VERSION 5.8 ;
BUSBITCHARS "[]" ;
DIVIDERCHAR "/" ;
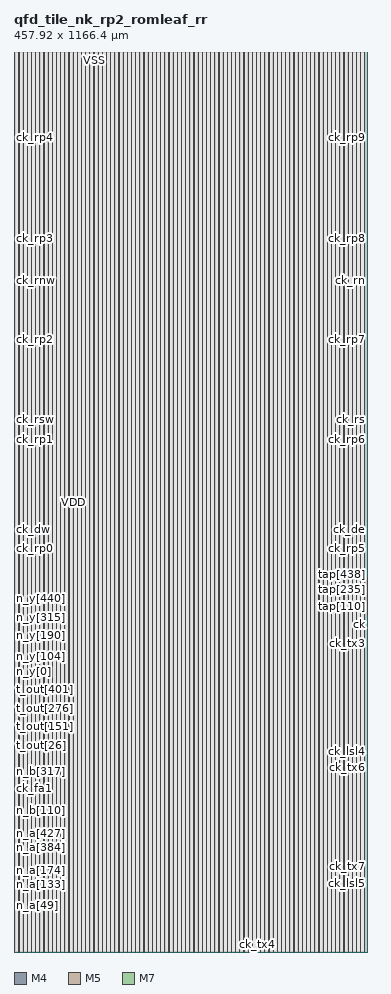
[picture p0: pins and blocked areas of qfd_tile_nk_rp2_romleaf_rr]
MACRO qfd_tile_nk_rp2_romleaf_rr
  CLASS BLOCK ;
  ORIGIN 0 0 ;
  FOREIGN qfd_tile_nk_rp2_romleaf_rr 0 0 ;
  SIZE 457.92 BY 1166.4 ;
  SYMMETRY X Y ;
  PIN n_a[0]
    DIRECTION INPUT ;
    USE SIGNAL ;
    PORT
      LAYER M4 ;
        RECT 0.000 61.632 0.192 61.656 ;
    END
  END n_a[0]
  PIN n_a[1]
    DIRECTION INPUT ;
    USE SIGNAL ;
    PORT
      LAYER M4 ;
        RECT 0.000 61.824 0.192 61.848 ;
    END
  END n_a[1]
  PIN n_a[2]
    DIRECTION INPUT ;
    USE SIGNAL ;
    PORT
      LAYER M4 ;
        RECT 0.000 62.016 0.192 62.040 ;
    END
  END n_a[2]
  PIN n_a[3]
    DIRECTION INPUT ;
    USE SIGNAL ;
    PORT
      LAYER M4 ;
        RECT 0.000 62.208 0.192 62.232 ;
    END
  END n_a[3]
  PIN n_a[4]
    DIRECTION INPUT ;
    USE SIGNAL ;
    PORT
      LAYER M4 ;
        RECT 0.000 62.400 0.192 62.424 ;
    END
  END n_a[4]
  PIN n_a[5]
    DIRECTION INPUT ;
    USE SIGNAL ;
    PORT
      LAYER M4 ;
        RECT 0.000 62.592 0.192 62.616 ;
    END
  END n_a[5]
  PIN n_a[6]
    DIRECTION INPUT ;
    USE SIGNAL ;
    PORT
      LAYER M4 ;
        RECT 0.000 62.784 0.192 62.808 ;
    END
  END n_a[6]
  PIN n_a[7]
    DIRECTION INPUT ;
    USE SIGNAL ;
    PORT
      LAYER M4 ;
        RECT 0.000 62.976 0.192 63.000 ;
    END
  END n_a[7]
  PIN n_a[8]
    DIRECTION INPUT ;
    USE SIGNAL ;
    PORT
      LAYER M4 ;
        RECT 0.000 63.168 0.192 63.192 ;
    END
  END n_a[8]
  PIN n_a[9]
    DIRECTION INPUT ;
    USE SIGNAL ;
    PORT
      LAYER M4 ;
        RECT 0.000 63.360 0.192 63.384 ;
    END
  END n_a[9]
  PIN n_a[10]
    DIRECTION INPUT ;
    USE SIGNAL ;
    PORT
      LAYER M4 ;
        RECT 0.000 63.552 0.192 63.576 ;
    END
  END n_a[10]
  PIN n_a[11]
    DIRECTION INPUT ;
    USE SIGNAL ;
    PORT
      LAYER M4 ;
        RECT 0.000 63.744 0.192 63.768 ;
    END
  END n_a[11]
  PIN n_a[12]
    DIRECTION INPUT ;
    USE SIGNAL ;
    PORT
      LAYER M4 ;
        RECT 0.000 63.936 0.192 63.960 ;
    END
  END n_a[12]
  PIN n_a[13]
    DIRECTION INPUT ;
    USE SIGNAL ;
    PORT
      LAYER M4 ;
        RECT 0.000 64.128 0.192 64.152 ;
    END
  END n_a[13]
  PIN n_a[14]
    DIRECTION INPUT ;
    USE SIGNAL ;
    PORT
      LAYER M4 ;
        RECT 0.000 64.320 0.192 64.344 ;
    END
  END n_a[14]
  PIN n_a[15]
    DIRECTION INPUT ;
    USE SIGNAL ;
    PORT
      LAYER M4 ;
        RECT 0.000 64.512 0.192 64.536 ;
    END
  END n_a[15]
  PIN n_a[16]
    DIRECTION INPUT ;
    USE SIGNAL ;
    PORT
      LAYER M4 ;
        RECT 0.000 64.704 0.192 64.728 ;
    END
  END n_a[16]
  PIN n_a[17]
    DIRECTION INPUT ;
    USE SIGNAL ;
    PORT
      LAYER M4 ;
        RECT 0.000 64.896 0.192 64.920 ;
    END
  END n_a[17]
  PIN n_a[18]
    DIRECTION INPUT ;
    USE SIGNAL ;
    PORT
      LAYER M4 ;
        RECT 0.000 65.088 0.192 65.112 ;
    END
  END n_a[18]
  PIN n_a[19]
    DIRECTION INPUT ;
    USE SIGNAL ;
    PORT
      LAYER M4 ;
        RECT 0.000 65.280 0.192 65.304 ;
    END
  END n_a[19]
  PIN n_a[20]
    DIRECTION INPUT ;
    USE SIGNAL ;
    PORT
      LAYER M4 ;
        RECT 0.000 65.472 0.192 65.496 ;
    END
  END n_a[20]
  PIN n_a[21]
    DIRECTION INPUT ;
    USE SIGNAL ;
    PORT
      LAYER M4 ;
        RECT 0.000 65.664 0.192 65.688 ;
    END
  END n_a[21]
  PIN n_a[22]
    DIRECTION INPUT ;
    USE SIGNAL ;
    PORT
      LAYER M4 ;
        RECT 0.000 65.856 0.192 65.880 ;
    END
  END n_a[22]
  PIN n_a[23]
    DIRECTION INPUT ;
    USE SIGNAL ;
    PORT
      LAYER M4 ;
        RECT 0.000 66.048 0.192 66.072 ;
    END
  END n_a[23]
  PIN n_a[24]
    DIRECTION INPUT ;
    USE SIGNAL ;
    PORT
      LAYER M4 ;
        RECT 0.000 66.240 0.192 66.264 ;
    END
  END n_a[24]
  PIN n_a[25]
    DIRECTION INPUT ;
    USE SIGNAL ;
    PORT
      LAYER M4 ;
        RECT 0.000 66.432 0.192 66.456 ;
    END
  END n_a[25]
  PIN n_a[26]
    DIRECTION INPUT ;
    USE SIGNAL ;
    PORT
      LAYER M4 ;
        RECT 0.000 66.624 0.192 66.648 ;
    END
  END n_a[26]
  PIN n_a[27]
    DIRECTION INPUT ;
    USE SIGNAL ;
    PORT
      LAYER M4 ;
        RECT 0.000 66.816 0.192 66.840 ;
    END
  END n_a[27]
  PIN n_a[28]
    DIRECTION INPUT ;
    USE SIGNAL ;
    PORT
      LAYER M4 ;
        RECT 0.000 67.008 0.192 67.032 ;
    END
  END n_a[28]
  PIN n_a[29]
    DIRECTION INPUT ;
    USE SIGNAL ;
    PORT
      LAYER M4 ;
        RECT 0.000 67.200 0.192 67.224 ;
    END
  END n_a[29]
  PIN n_a[30]
    DIRECTION INPUT ;
    USE SIGNAL ;
    PORT
      LAYER M4 ;
        RECT 0.000 67.392 0.192 67.416 ;
    END
  END n_a[30]
  PIN n_a[31]
    DIRECTION INPUT ;
    USE SIGNAL ;
    PORT
      LAYER M4 ;
        RECT 0.000 67.584 0.192 67.608 ;
    END
  END n_a[31]
  PIN n_a[32]
    DIRECTION INPUT ;
    USE SIGNAL ;
    PORT
      LAYER M4 ;
        RECT 0.000 67.776 0.192 67.800 ;
    END
  END n_a[32]
  PIN n_a[33]
    DIRECTION INPUT ;
    USE SIGNAL ;
    PORT
      LAYER M4 ;
        RECT 0.000 67.968 0.192 67.992 ;
    END
  END n_a[33]
  PIN n_a[34]
    DIRECTION INPUT ;
    USE SIGNAL ;
    PORT
      LAYER M4 ;
        RECT 0.000 68.160 0.192 68.184 ;
    END
  END n_a[34]
  PIN n_a[35]
    DIRECTION INPUT ;
    USE SIGNAL ;
    PORT
      LAYER M4 ;
        RECT 0.000 68.352 0.192 68.376 ;
    END
  END n_a[35]
  PIN n_a[36]
    DIRECTION INPUT ;
    USE SIGNAL ;
    PORT
      LAYER M4 ;
        RECT 0.000 68.544 0.192 68.568 ;
    END
  END n_a[36]
  PIN n_a[37]
    DIRECTION INPUT ;
    USE SIGNAL ;
    PORT
      LAYER M4 ;
        RECT 0.000 68.736 0.192 68.760 ;
    END
  END n_a[37]
  PIN n_a[38]
    DIRECTION INPUT ;
    USE SIGNAL ;
    PORT
      LAYER M4 ;
        RECT 0.000 68.928 0.192 68.952 ;
    END
  END n_a[38]
  PIN n_a[39]
    DIRECTION INPUT ;
    USE SIGNAL ;
    PORT
      LAYER M4 ;
        RECT 0.000 69.120 0.192 69.144 ;
    END
  END n_a[39]
  PIN n_a[40]
    DIRECTION INPUT ;
    USE SIGNAL ;
    PORT
      LAYER M4 ;
        RECT 0.000 69.312 0.192 69.336 ;
    END
  END n_a[40]
  PIN n_a[41]
    DIRECTION INPUT ;
    USE SIGNAL ;
    PORT
      LAYER M4 ;
        RECT 0.000 69.504 0.192 69.528 ;
    END
  END n_a[41]
  PIN n_a[42]
    DIRECTION INPUT ;
    USE SIGNAL ;
    PORT
      LAYER M4 ;
        RECT 0.000 69.696 0.192 69.720 ;
    END
  END n_a[42]
  PIN n_a[43]
    DIRECTION INPUT ;
    USE SIGNAL ;
    PORT
      LAYER M4 ;
        RECT 0.000 69.888 0.192 69.912 ;
    END
  END n_a[43]
  PIN n_a[44]
    DIRECTION INPUT ;
    USE SIGNAL ;
    PORT
      LAYER M4 ;
        RECT 0.000 70.080 0.192 70.104 ;
    END
  END n_a[44]
  PIN n_a[45]
    DIRECTION INPUT ;
    USE SIGNAL ;
    PORT
      LAYER M4 ;
        RECT 0.000 70.272 0.192 70.296 ;
    END
  END n_a[45]
  PIN n_a[46]
    DIRECTION INPUT ;
    USE SIGNAL ;
    PORT
      LAYER M4 ;
        RECT 0.000 70.464 0.192 70.488 ;
    END
  END n_a[46]
  PIN n_a[47]
    DIRECTION INPUT ;
    USE SIGNAL ;
    PORT
      LAYER M4 ;
        RECT 0.000 70.656 0.192 70.680 ;
    END
  END n_a[47]
  PIN n_a[48]
    DIRECTION INPUT ;
    USE SIGNAL ;
    PORT
      LAYER M4 ;
        RECT 0.000 70.848 0.192 70.872 ;
    END
  END n_a[48]
  PIN n_a[49]
    DIRECTION INPUT ;
    USE SIGNAL ;
    PORT
      LAYER M4 ;
        RECT 0.000 71.040 0.192 71.064 ;
    END
  END n_a[49]
  PIN n_a[50]
    DIRECTION INPUT ;
    USE SIGNAL ;
    PORT
      LAYER M4 ;
        RECT 0.000 71.232 0.192 71.256 ;
    END
  END n_a[50]
  PIN n_a[51]
    DIRECTION INPUT ;
    USE SIGNAL ;
    PORT
      LAYER M4 ;
        RECT 0.000 71.424 0.192 71.448 ;
    END
  END n_a[51]
  PIN n_a[52]
    DIRECTION INPUT ;
    USE SIGNAL ;
    PORT
      LAYER M4 ;
        RECT 0.000 71.616 0.192 71.640 ;
    END
  END n_a[52]
  PIN n_a[53]
    DIRECTION INPUT ;
    USE SIGNAL ;
    PORT
      LAYER M4 ;
        RECT 0.000 71.808 0.192 71.832 ;
    END
  END n_a[53]
  PIN n_a[54]
    DIRECTION INPUT ;
    USE SIGNAL ;
    PORT
      LAYER M4 ;
        RECT 0.000 72.000 0.192 72.024 ;
    END
  END n_a[54]
  PIN n_a[55]
    DIRECTION INPUT ;
    USE SIGNAL ;
    PORT
      LAYER M4 ;
        RECT 0.000 72.192 0.192 72.216 ;
    END
  END n_a[55]
  PIN n_a[56]
    DIRECTION INPUT ;
    USE SIGNAL ;
    PORT
      LAYER M4 ;
        RECT 0.000 72.384 0.192 72.408 ;
    END
  END n_a[56]
  PIN n_a[57]
    DIRECTION INPUT ;
    USE SIGNAL ;
    PORT
      LAYER M4 ;
        RECT 0.000 72.576 0.192 72.600 ;
    END
  END n_a[57]
  PIN n_a[58]
    DIRECTION INPUT ;
    USE SIGNAL ;
    PORT
      LAYER M4 ;
        RECT 0.000 72.768 0.192 72.792 ;
    END
  END n_a[58]
  PIN n_a[59]
    DIRECTION INPUT ;
    USE SIGNAL ;
    PORT
      LAYER M4 ;
        RECT 0.000 72.960 0.192 72.984 ;
    END
  END n_a[59]
  PIN n_a[60]
    DIRECTION INPUT ;
    USE SIGNAL ;
    PORT
      LAYER M4 ;
        RECT 0.000 73.152 0.192 73.176 ;
    END
  END n_a[60]
  PIN n_a[61]
    DIRECTION INPUT ;
    USE SIGNAL ;
    PORT
      LAYER M4 ;
        RECT 0.000 73.344 0.192 73.368 ;
    END
  END n_a[61]
  PIN n_a[62]
    DIRECTION INPUT ;
    USE SIGNAL ;
    PORT
      LAYER M4 ;
        RECT 0.000 73.536 0.192 73.560 ;
    END
  END n_a[62]
  PIN n_a[63]
    DIRECTION INPUT ;
    USE SIGNAL ;
    PORT
      LAYER M4 ;
        RECT 0.000 73.728 0.192 73.752 ;
    END
  END n_a[63]
  PIN n_a[64]
    DIRECTION INPUT ;
    USE SIGNAL ;
    PORT
      LAYER M4 ;
        RECT 0.000 73.920 0.192 73.944 ;
    END
  END n_a[64]
  PIN n_a[65]
    DIRECTION INPUT ;
    USE SIGNAL ;
    PORT
      LAYER M4 ;
        RECT 0.000 74.112 0.192 74.136 ;
    END
  END n_a[65]
  PIN n_a[66]
    DIRECTION INPUT ;
    USE SIGNAL ;
    PORT
      LAYER M4 ;
        RECT 0.000 74.304 0.192 74.328 ;
    END
  END n_a[66]
  PIN n_a[67]
    DIRECTION INPUT ;
    USE SIGNAL ;
    PORT
      LAYER M4 ;
        RECT 0.000 74.496 0.192 74.520 ;
    END
  END n_a[67]
  PIN n_a[68]
    DIRECTION INPUT ;
    USE SIGNAL ;
    PORT
      LAYER M4 ;
        RECT 0.000 74.688 0.192 74.712 ;
    END
  END n_a[68]
  PIN n_a[69]
    DIRECTION INPUT ;
    USE SIGNAL ;
    PORT
      LAYER M4 ;
        RECT 0.000 74.880 0.192 74.904 ;
    END
  END n_a[69]
  PIN n_a[70]
    DIRECTION INPUT ;
    USE SIGNAL ;
    PORT
      LAYER M4 ;
        RECT 0.000 75.072 0.192 75.096 ;
    END
  END n_a[70]
  PIN n_a[71]
    DIRECTION INPUT ;
    USE SIGNAL ;
    PORT
      LAYER M4 ;
        RECT 0.000 75.264 0.192 75.288 ;
    END
  END n_a[71]
  PIN n_a[72]
    DIRECTION INPUT ;
    USE SIGNAL ;
    PORT
      LAYER M4 ;
        RECT 0.000 75.456 0.192 75.480 ;
    END
  END n_a[72]
  PIN n_a[73]
    DIRECTION INPUT ;
    USE SIGNAL ;
    PORT
      LAYER M4 ;
        RECT 0.000 75.648 0.192 75.672 ;
    END
  END n_a[73]
  PIN n_a[74]
    DIRECTION INPUT ;
    USE SIGNAL ;
    PORT
      LAYER M4 ;
        RECT 0.000 75.840 0.192 75.864 ;
    END
  END n_a[74]
  PIN n_a[75]
    DIRECTION INPUT ;
    USE SIGNAL ;
    PORT
      LAYER M4 ;
        RECT 0.000 76.032 0.192 76.056 ;
    END
  END n_a[75]
  PIN n_a[76]
    DIRECTION INPUT ;
    USE SIGNAL ;
    PORT
      LAYER M4 ;
        RECT 0.000 76.224 0.192 76.248 ;
    END
  END n_a[76]
  PIN n_a[77]
    DIRECTION INPUT ;
    USE SIGNAL ;
    PORT
      LAYER M4 ;
        RECT 0.000 76.416 0.192 76.440 ;
    END
  END n_a[77]
  PIN n_a[78]
    DIRECTION INPUT ;
    USE SIGNAL ;
    PORT
      LAYER M4 ;
        RECT 0.000 76.608 0.192 76.632 ;
    END
  END n_a[78]
  PIN n_a[79]
    DIRECTION INPUT ;
    USE SIGNAL ;
    PORT
      LAYER M4 ;
        RECT 0.000 76.800 0.192 76.824 ;
    END
  END n_a[79]
  PIN n_a[80]
    DIRECTION INPUT ;
    USE SIGNAL ;
    PORT
      LAYER M4 ;
        RECT 0.000 76.992 0.192 77.016 ;
    END
  END n_a[80]
  PIN n_a[81]
    DIRECTION INPUT ;
    USE SIGNAL ;
    PORT
      LAYER M4 ;
        RECT 0.000 77.184 0.192 77.208 ;
    END
  END n_a[81]
  PIN n_a[82]
    DIRECTION INPUT ;
    USE SIGNAL ;
    PORT
      LAYER M4 ;
        RECT 0.000 77.376 0.192 77.400 ;
    END
  END n_a[82]
  PIN n_a[83]
    DIRECTION INPUT ;
    USE SIGNAL ;
    PORT
      LAYER M4 ;
        RECT 0.000 77.568 0.192 77.592 ;
    END
  END n_a[83]
  PIN n_a[84]
    DIRECTION INPUT ;
    USE SIGNAL ;
    PORT
      LAYER M4 ;
        RECT 0.000 77.760 0.192 77.784 ;
    END
  END n_a[84]
  PIN n_a[85]
    DIRECTION INPUT ;
    USE SIGNAL ;
    PORT
      LAYER M4 ;
        RECT 0.000 77.952 0.192 77.976 ;
    END
  END n_a[85]
  PIN n_a[86]
    DIRECTION INPUT ;
    USE SIGNAL ;
    PORT
      LAYER M4 ;
        RECT 0.000 78.144 0.192 78.168 ;
    END
  END n_a[86]
  PIN n_a[87]
    DIRECTION INPUT ;
    USE SIGNAL ;
    PORT
      LAYER M4 ;
        RECT 0.000 78.336 0.192 78.360 ;
    END
  END n_a[87]
  PIN n_a[88]
    DIRECTION INPUT ;
    USE SIGNAL ;
    PORT
      LAYER M4 ;
        RECT 0.000 78.528 0.192 78.552 ;
    END
  END n_a[88]
  PIN n_a[89]
    DIRECTION INPUT ;
    USE SIGNAL ;
    PORT
      LAYER M4 ;
        RECT 0.000 78.720 0.192 78.744 ;
    END
  END n_a[89]
  PIN n_a[90]
    DIRECTION INPUT ;
    USE SIGNAL ;
    PORT
      LAYER M4 ;
        RECT 0.000 78.912 0.192 78.936 ;
    END
  END n_a[90]
  PIN n_a[91]
    DIRECTION INPUT ;
    USE SIGNAL ;
    PORT
      LAYER M4 ;
        RECT 0.000 79.104 0.192 79.128 ;
    END
  END n_a[91]
  PIN n_a[92]
    DIRECTION INPUT ;
    USE SIGNAL ;
    PORT
      LAYER M4 ;
        RECT 0.000 79.296 0.192 79.320 ;
    END
  END n_a[92]
  PIN n_a[93]
    DIRECTION INPUT ;
    USE SIGNAL ;
    PORT
      LAYER M4 ;
        RECT 0.000 79.488 0.192 79.512 ;
    END
  END n_a[93]
  PIN n_a[94]
    DIRECTION INPUT ;
    USE SIGNAL ;
    PORT
      LAYER M4 ;
        RECT 0.000 79.680 0.192 79.704 ;
    END
  END n_a[94]
  PIN n_a[95]
    DIRECTION INPUT ;
    USE SIGNAL ;
    PORT
      LAYER M4 ;
        RECT 0.000 79.872 0.192 79.896 ;
    END
  END n_a[95]
  PIN n_a[96]
    DIRECTION INPUT ;
    USE SIGNAL ;
    PORT
      LAYER M4 ;
        RECT 0.000 80.064 0.192 80.088 ;
    END
  END n_a[96]
  PIN n_a[97]
    DIRECTION INPUT ;
    USE SIGNAL ;
    PORT
      LAYER M4 ;
        RECT 0.000 80.256 0.192 80.280 ;
    END
  END n_a[97]
  PIN n_a[98]
    DIRECTION INPUT ;
    USE SIGNAL ;
    PORT
      LAYER M4 ;
        RECT 0.000 80.448 0.192 80.472 ;
    END
  END n_a[98]
  PIN n_a[99]
    DIRECTION INPUT ;
    USE SIGNAL ;
    PORT
      LAYER M4 ;
        RECT 0.000 80.640 0.192 80.664 ;
    END
  END n_a[99]
  PIN n_a[100]
    DIRECTION INPUT ;
    USE SIGNAL ;
    PORT
      LAYER M4 ;
        RECT 0.000 80.832 0.192 80.856 ;
    END
  END n_a[100]
  PIN n_a[101]
    DIRECTION INPUT ;
    USE SIGNAL ;
    PORT
      LAYER M4 ;
        RECT 0.000 81.024 0.192 81.048 ;
    END
  END n_a[101]
  PIN n_a[102]
    DIRECTION INPUT ;
    USE SIGNAL ;
    PORT
      LAYER M4 ;
        RECT 0.000 81.216 0.192 81.240 ;
    END
  END n_a[102]
  PIN n_a[103]
    DIRECTION INPUT ;
    USE SIGNAL ;
    PORT
      LAYER M4 ;
        RECT 0.000 81.408 0.192 81.432 ;
    END
  END n_a[103]
  PIN n_a[104]
    DIRECTION INPUT ;
    USE SIGNAL ;
    PORT
      LAYER M4 ;
        RECT 0.000 81.600 0.192 81.624 ;
    END
  END n_a[104]
  PIN n_a[105]
    DIRECTION INPUT ;
    USE SIGNAL ;
    PORT
      LAYER M4 ;
        RECT 0.000 81.792 0.192 81.816 ;
    END
  END n_a[105]
  PIN n_a[106]
    DIRECTION INPUT ;
    USE SIGNAL ;
    PORT
      LAYER M4 ;
        RECT 0.000 81.984 0.192 82.008 ;
    END
  END n_a[106]
  PIN n_a[107]
    DIRECTION INPUT ;
    USE SIGNAL ;
    PORT
      LAYER M4 ;
        RECT 0.000 82.176 0.192 82.200 ;
    END
  END n_a[107]
  PIN n_a[108]
    DIRECTION INPUT ;
    USE SIGNAL ;
    PORT
      LAYER M4 ;
        RECT 0.000 82.368 0.192 82.392 ;
    END
  END n_a[108]
  PIN n_a[109]
    DIRECTION INPUT ;
    USE SIGNAL ;
    PORT
      LAYER M4 ;
        RECT 0.000 82.560 0.192 82.584 ;
    END
  END n_a[109]
  PIN n_a[110]
    DIRECTION INPUT ;
    USE SIGNAL ;
    PORT
      LAYER M4 ;
        RECT 0.000 82.752 0.192 82.776 ;
    END
  END n_a[110]
  PIN n_a[111]
    DIRECTION INPUT ;
    USE SIGNAL ;
    PORT
      LAYER M4 ;
        RECT 0.000 82.944 0.192 82.968 ;
    END
  END n_a[111]
  PIN n_a[112]
    DIRECTION INPUT ;
    USE SIGNAL ;
    PORT
      LAYER M4 ;
        RECT 0.000 83.136 0.192 83.160 ;
    END
  END n_a[112]
  PIN n_a[113]
    DIRECTION INPUT ;
    USE SIGNAL ;
    PORT
      LAYER M4 ;
        RECT 0.000 83.328 0.192 83.352 ;
    END
  END n_a[113]
  PIN n_a[114]
    DIRECTION INPUT ;
    USE SIGNAL ;
    PORT
      LAYER M4 ;
        RECT 0.000 83.520 0.192 83.544 ;
    END
  END n_a[114]
  PIN n_a[115]
    DIRECTION INPUT ;
    USE SIGNAL ;
    PORT
      LAYER M4 ;
        RECT 0.000 83.712 0.192 83.736 ;
    END
  END n_a[115]
  PIN n_a[116]
    DIRECTION INPUT ;
    USE SIGNAL ;
    PORT
      LAYER M4 ;
        RECT 0.000 83.904 0.192 83.928 ;
    END
  END n_a[116]
  PIN n_a[117]
    DIRECTION INPUT ;
    USE SIGNAL ;
    PORT
      LAYER M4 ;
        RECT 0.000 84.096 0.192 84.120 ;
    END
  END n_a[117]
  PIN n_a[118]
    DIRECTION INPUT ;
    USE SIGNAL ;
    PORT
      LAYER M4 ;
        RECT 0.000 84.288 0.192 84.312 ;
    END
  END n_a[118]
  PIN n_a[119]
    DIRECTION INPUT ;
    USE SIGNAL ;
    PORT
      LAYER M4 ;
        RECT 0.000 84.480 0.192 84.504 ;
    END
  END n_a[119]
  PIN n_a[120]
    DIRECTION INPUT ;
    USE SIGNAL ;
    PORT
      LAYER M4 ;
        RECT 0.000 84.672 0.192 84.696 ;
    END
  END n_a[120]
  PIN n_a[121]
    DIRECTION INPUT ;
    USE SIGNAL ;
    PORT
      LAYER M4 ;
        RECT 0.000 84.864 0.192 84.888 ;
    END
  END n_a[121]
  PIN n_a[122]
    DIRECTION INPUT ;
    USE SIGNAL ;
    PORT
      LAYER M4 ;
        RECT 0.000 85.056 0.192 85.080 ;
    END
  END n_a[122]
  PIN n_a[123]
    DIRECTION INPUT ;
    USE SIGNAL ;
    PORT
      LAYER M4 ;
        RECT 0.000 85.248 0.192 85.272 ;
    END
  END n_a[123]
  PIN n_a[124]
    DIRECTION INPUT ;
    USE SIGNAL ;
    PORT
      LAYER M4 ;
        RECT 0.000 85.440 0.192 85.464 ;
    END
  END n_a[124]
  PIN n_a[125]
    DIRECTION INPUT ;
    USE SIGNAL ;
    PORT
      LAYER M4 ;
        RECT 0.000 85.632 0.192 85.656 ;
    END
  END n_a[125]
  PIN n_a[126]
    DIRECTION INPUT ;
    USE SIGNAL ;
    PORT
      LAYER M4 ;
        RECT 0.000 85.824 0.192 85.848 ;
    END
  END n_a[126]
  PIN n_a[127]
    DIRECTION INPUT ;
    USE SIGNAL ;
    PORT
      LAYER M4 ;
        RECT 0.000 86.016 0.192 86.040 ;
    END
  END n_a[127]
  PIN n_a[128]
    DIRECTION INPUT ;
    USE SIGNAL ;
    PORT
      LAYER M4 ;
        RECT 0.000 86.208 0.192 86.232 ;
    END
  END n_a[128]
  PIN n_a[129]
    DIRECTION INPUT ;
    USE SIGNAL ;
    PORT
      LAYER M4 ;
        RECT 0.000 86.400 0.192 86.424 ;
    END
  END n_a[129]
  PIN n_a[130]
    DIRECTION INPUT ;
    USE SIGNAL ;
    PORT
      LAYER M4 ;
        RECT 0.000 86.592 0.192 86.616 ;
    END
  END n_a[130]
  PIN n_a[131]
    DIRECTION INPUT ;
    USE SIGNAL ;
    PORT
      LAYER M4 ;
        RECT 0.000 86.784 0.192 86.808 ;
    END
  END n_a[131]
  PIN n_a[132]
    DIRECTION INPUT ;
    USE SIGNAL ;
    PORT
      LAYER M4 ;
        RECT 0.000 86.976 0.192 87.000 ;
    END
  END n_a[132]
  PIN n_a[133]
    DIRECTION INPUT ;
    USE SIGNAL ;
    PORT
      LAYER M4 ;
        RECT 0.000 87.168 0.192 87.192 ;
    END
  END n_a[133]
  PIN n_a[134]
    DIRECTION INPUT ;
    USE SIGNAL ;
    PORT
      LAYER M4 ;
        RECT 0.000 87.360 0.192 87.384 ;
    END
  END n_a[134]
  PIN n_a[135]
    DIRECTION INPUT ;
    USE SIGNAL ;
    PORT
      LAYER M4 ;
        RECT 0.000 87.552 0.192 87.576 ;
    END
  END n_a[135]
  PIN n_a[136]
    DIRECTION INPUT ;
    USE SIGNAL ;
    PORT
      LAYER M4 ;
        RECT 0.000 87.744 0.192 87.768 ;
    END
  END n_a[136]
  PIN n_a[137]
    DIRECTION INPUT ;
    USE SIGNAL ;
    PORT
      LAYER M4 ;
        RECT 0.000 87.936 0.192 87.960 ;
    END
  END n_a[137]
  PIN n_a[138]
    DIRECTION INPUT ;
    USE SIGNAL ;
    PORT
      LAYER M4 ;
        RECT 0.000 88.128 0.192 88.152 ;
    END
  END n_a[138]
  PIN n_a[139]
    DIRECTION INPUT ;
    USE SIGNAL ;
    PORT
      LAYER M4 ;
        RECT 0.000 88.320 0.192 88.344 ;
    END
  END n_a[139]
  PIN n_a[140]
    DIRECTION INPUT ;
    USE SIGNAL ;
    PORT
      LAYER M4 ;
        RECT 0.000 88.512 0.192 88.536 ;
    END
  END n_a[140]
  PIN n_a[141]
    DIRECTION INPUT ;
    USE SIGNAL ;
    PORT
      LAYER M4 ;
        RECT 0.000 88.704 0.192 88.728 ;
    END
  END n_a[141]
  PIN n_a[142]
    DIRECTION INPUT ;
    USE SIGNAL ;
    PORT
      LAYER M4 ;
        RECT 0.000 88.896 0.192 88.920 ;
    END
  END n_a[142]
  PIN n_a[143]
    DIRECTION INPUT ;
    USE SIGNAL ;
    PORT
      LAYER M4 ;
        RECT 0.000 89.088 0.192 89.112 ;
    END
  END n_a[143]
  PIN n_a[144]
    DIRECTION INPUT ;
    USE SIGNAL ;
    PORT
      LAYER M4 ;
        RECT 0.000 89.280 0.192 89.304 ;
    END
  END n_a[144]
  PIN n_a[145]
    DIRECTION INPUT ;
    USE SIGNAL ;
    PORT
      LAYER M4 ;
        RECT 0.000 89.472 0.192 89.496 ;
    END
  END n_a[145]
  PIN n_a[146]
    DIRECTION INPUT ;
    USE SIGNAL ;
    PORT
      LAYER M4 ;
        RECT 0.000 89.664 0.192 89.688 ;
    END
  END n_a[146]
  PIN n_a[147]
    DIRECTION INPUT ;
    USE SIGNAL ;
    PORT
      LAYER M4 ;
        RECT 0.000 89.856 0.192 89.880 ;
    END
  END n_a[147]
  PIN n_a[148]
    DIRECTION INPUT ;
    USE SIGNAL ;
    PORT
      LAYER M4 ;
        RECT 0.000 90.048 0.192 90.072 ;
    END
  END n_a[148]
  PIN n_a[149]
    DIRECTION INPUT ;
    USE SIGNAL ;
    PORT
      LAYER M4 ;
        RECT 0.000 90.240 0.192 90.264 ;
    END
  END n_a[149]
  PIN n_a[150]
    DIRECTION INPUT ;
    USE SIGNAL ;
    PORT
      LAYER M4 ;
        RECT 0.000 90.432 0.192 90.456 ;
    END
  END n_a[150]
  PIN n_a[151]
    DIRECTION INPUT ;
    USE SIGNAL ;
    PORT
      LAYER M4 ;
        RECT 0.000 90.624 0.192 90.648 ;
    END
  END n_a[151]
  PIN n_a[152]
    DIRECTION INPUT ;
    USE SIGNAL ;
    PORT
      LAYER M4 ;
        RECT 0.000 90.816 0.192 90.840 ;
    END
  END n_a[152]
  PIN n_a[153]
    DIRECTION INPUT ;
    USE SIGNAL ;
    PORT
      LAYER M4 ;
        RECT 0.000 91.008 0.192 91.032 ;
    END
  END n_a[153]
  PIN n_a[154]
    DIRECTION INPUT ;
    USE SIGNAL ;
    PORT
      LAYER M4 ;
        RECT 0.000 91.200 0.192 91.224 ;
    END
  END n_a[154]
  PIN n_a[155]
    DIRECTION INPUT ;
    USE SIGNAL ;
    PORT
      LAYER M4 ;
        RECT 0.000 91.392 0.192 91.416 ;
    END
  END n_a[155]
  PIN n_a[156]
    DIRECTION INPUT ;
    USE SIGNAL ;
    PORT
      LAYER M4 ;
        RECT 0.000 91.584 0.192 91.608 ;
    END
  END n_a[156]
  PIN n_a[157]
    DIRECTION INPUT ;
    USE SIGNAL ;
    PORT
      LAYER M4 ;
        RECT 0.000 91.776 0.192 91.800 ;
    END
  END n_a[157]
  PIN n_a[158]
    DIRECTION INPUT ;
    USE SIGNAL ;
    PORT
      LAYER M4 ;
        RECT 0.000 91.968 0.192 91.992 ;
    END
  END n_a[158]
  PIN n_a[159]
    DIRECTION INPUT ;
    USE SIGNAL ;
    PORT
      LAYER M4 ;
        RECT 0.000 92.160 0.192 92.184 ;
    END
  END n_a[159]
  PIN n_a[160]
    DIRECTION INPUT ;
    USE SIGNAL ;
    PORT
      LAYER M4 ;
        RECT 0.000 92.352 0.192 92.376 ;
    END
  END n_a[160]
  PIN n_a[161]
    DIRECTION INPUT ;
    USE SIGNAL ;
    PORT
      LAYER M4 ;
        RECT 0.000 92.544 0.192 92.568 ;
    END
  END n_a[161]
  PIN n_a[162]
    DIRECTION INPUT ;
    USE SIGNAL ;
    PORT
      LAYER M4 ;
        RECT 0.000 92.736 0.192 92.760 ;
    END
  END n_a[162]
  PIN n_a[163]
    DIRECTION INPUT ;
    USE SIGNAL ;
    PORT
      LAYER M4 ;
        RECT 0.000 92.928 0.192 92.952 ;
    END
  END n_a[163]
  PIN n_a[164]
    DIRECTION INPUT ;
    USE SIGNAL ;
    PORT
      LAYER M4 ;
        RECT 0.000 93.120 0.192 93.144 ;
    END
  END n_a[164]
  PIN n_a[165]
    DIRECTION INPUT ;
    USE SIGNAL ;
    PORT
      LAYER M4 ;
        RECT 0.000 93.312 0.192 93.336 ;
    END
  END n_a[165]
  PIN n_a[166]
    DIRECTION INPUT ;
    USE SIGNAL ;
    PORT
      LAYER M4 ;
        RECT 0.000 93.504 0.192 93.528 ;
    END
  END n_a[166]
  PIN n_a[167]
    DIRECTION INPUT ;
    USE SIGNAL ;
    PORT
      LAYER M4 ;
        RECT 0.000 93.696 0.192 93.720 ;
    END
  END n_a[167]
  PIN n_a[168]
    DIRECTION INPUT ;
    USE SIGNAL ;
    PORT
      LAYER M4 ;
        RECT 0.000 93.888 0.192 93.912 ;
    END
  END n_a[168]
  PIN n_a[169]
    DIRECTION INPUT ;
    USE SIGNAL ;
    PORT
      LAYER M4 ;
        RECT 0.000 94.080 0.192 94.104 ;
    END
  END n_a[169]
  PIN n_a[170]
    DIRECTION INPUT ;
    USE SIGNAL ;
    PORT
      LAYER M4 ;
        RECT 0.000 94.272 0.192 94.296 ;
    END
  END n_a[170]
  PIN n_a[171]
    DIRECTION INPUT ;
    USE SIGNAL ;
    PORT
      LAYER M4 ;
        RECT 0.000 94.464 0.192 94.488 ;
    END
  END n_a[171]
  PIN n_a[172]
    DIRECTION INPUT ;
    USE SIGNAL ;
    PORT
      LAYER M4 ;
        RECT 0.000 94.656 0.192 94.680 ;
    END
  END n_a[172]
  PIN n_a[173]
    DIRECTION INPUT ;
    USE SIGNAL ;
    PORT
      LAYER M4 ;
        RECT 0.000 94.848 0.192 94.872 ;
    END
  END n_a[173]
  PIN n_a[174]
    DIRECTION INPUT ;
    USE SIGNAL ;
    PORT
      LAYER M4 ;
        RECT 0.000 95.040 0.192 95.064 ;
    END
  END n_a[174]
  PIN n_a[175]
    DIRECTION INPUT ;
    USE SIGNAL ;
    PORT
      LAYER M4 ;
        RECT 0.000 95.232 0.192 95.256 ;
    END
  END n_a[175]
  PIN n_a[176]
    DIRECTION INPUT ;
    USE SIGNAL ;
    PORT
      LAYER M4 ;
        RECT 0.000 95.424 0.192 95.448 ;
    END
  END n_a[176]
  PIN n_a[177]
    DIRECTION INPUT ;
    USE SIGNAL ;
    PORT
      LAYER M4 ;
        RECT 0.000 95.616 0.192 95.640 ;
    END
  END n_a[177]
  PIN n_a[178]
    DIRECTION INPUT ;
    USE SIGNAL ;
    PORT
      LAYER M4 ;
        RECT 0.000 95.808 0.192 95.832 ;
    END
  END n_a[178]
  PIN n_a[179]
    DIRECTION INPUT ;
    USE SIGNAL ;
    PORT
      LAYER M4 ;
        RECT 0.000 96.000 0.192 96.024 ;
    END
  END n_a[179]
  PIN n_a[180]
    DIRECTION INPUT ;
    USE SIGNAL ;
    PORT
      LAYER M4 ;
        RECT 0.000 96.192 0.192 96.216 ;
    END
  END n_a[180]
  PIN n_a[181]
    DIRECTION INPUT ;
    USE SIGNAL ;
    PORT
      LAYER M4 ;
        RECT 0.000 96.384 0.192 96.408 ;
    END
  END n_a[181]
  PIN n_a[182]
    DIRECTION INPUT ;
    USE SIGNAL ;
    PORT
      LAYER M4 ;
        RECT 0.000 96.576 0.192 96.600 ;
    END
  END n_a[182]
  PIN n_a[183]
    DIRECTION INPUT ;
    USE SIGNAL ;
    PORT
      LAYER M4 ;
        RECT 0.000 96.768 0.192 96.792 ;
    END
  END n_a[183]
  PIN n_a[184]
    DIRECTION INPUT ;
    USE SIGNAL ;
    PORT
      LAYER M4 ;
        RECT 0.000 96.960 0.192 96.984 ;
    END
  END n_a[184]
  PIN n_a[185]
    DIRECTION INPUT ;
    USE SIGNAL ;
    PORT
      LAYER M4 ;
        RECT 0.000 97.152 0.192 97.176 ;
    END
  END n_a[185]
  PIN n_a[186]
    DIRECTION INPUT ;
    USE SIGNAL ;
    PORT
      LAYER M4 ;
        RECT 0.000 97.344 0.192 97.368 ;
    END
  END n_a[186]
  PIN n_a[187]
    DIRECTION INPUT ;
    USE SIGNAL ;
    PORT
      LAYER M4 ;
        RECT 0.000 97.536 0.192 97.560 ;
    END
  END n_a[187]
  PIN n_a[188]
    DIRECTION INPUT ;
    USE SIGNAL ;
    PORT
      LAYER M4 ;
        RECT 0.000 97.728 0.192 97.752 ;
    END
  END n_a[188]
  PIN n_a[189]
    DIRECTION INPUT ;
    USE SIGNAL ;
    PORT
      LAYER M4 ;
        RECT 0.000 97.920 0.192 97.944 ;
    END
  END n_a[189]
  PIN n_a[190]
    DIRECTION INPUT ;
    USE SIGNAL ;
    PORT
      LAYER M4 ;
        RECT 0.000 98.112 0.192 98.136 ;
    END
  END n_a[190]
  PIN n_a[191]
    DIRECTION INPUT ;
    USE SIGNAL ;
    PORT
      LAYER M4 ;
        RECT 0.000 98.304 0.192 98.328 ;
    END
  END n_a[191]
  PIN n_a[192]
    DIRECTION INPUT ;
    USE SIGNAL ;
    PORT
      LAYER M4 ;
        RECT 0.000 98.496 0.192 98.520 ;
    END
  END n_a[192]
  PIN n_a[193]
    DIRECTION INPUT ;
    USE SIGNAL ;
    PORT
      LAYER M4 ;
        RECT 0.000 98.688 0.192 98.712 ;
    END
  END n_a[193]
  PIN n_a[194]
    DIRECTION INPUT ;
    USE SIGNAL ;
    PORT
      LAYER M4 ;
        RECT 0.000 98.880 0.192 98.904 ;
    END
  END n_a[194]
  PIN n_a[195]
    DIRECTION INPUT ;
    USE SIGNAL ;
    PORT
      LAYER M4 ;
        RECT 0.000 99.072 0.192 99.096 ;
    END
  END n_a[195]
  PIN n_a[196]
    DIRECTION INPUT ;
    USE SIGNAL ;
    PORT
      LAYER M4 ;
        RECT 0.000 99.264 0.192 99.288 ;
    END
  END n_a[196]
  PIN n_a[197]
    DIRECTION INPUT ;
    USE SIGNAL ;
    PORT
      LAYER M4 ;
        RECT 0.000 99.456 0.192 99.480 ;
    END
  END n_a[197]
  PIN n_a[198]
    DIRECTION INPUT ;
    USE SIGNAL ;
    PORT
      LAYER M4 ;
        RECT 0.000 99.648 0.192 99.672 ;
    END
  END n_a[198]
  PIN n_a[199]
    DIRECTION INPUT ;
    USE SIGNAL ;
    PORT
      LAYER M4 ;
        RECT 0.000 99.840 0.192 99.864 ;
    END
  END n_a[199]
  PIN n_a[200]
    DIRECTION INPUT ;
    USE SIGNAL ;
    PORT
      LAYER M4 ;
        RECT 0.000 100.032 0.192 100.056 ;
    END
  END n_a[200]
  PIN n_a[201]
    DIRECTION INPUT ;
    USE SIGNAL ;
    PORT
      LAYER M4 ;
        RECT 0.000 100.224 0.192 100.248 ;
    END
  END n_a[201]
  PIN n_a[202]
    DIRECTION INPUT ;
    USE SIGNAL ;
    PORT
      LAYER M4 ;
        RECT 0.000 100.416 0.192 100.440 ;
    END
  END n_a[202]
  PIN n_a[203]
    DIRECTION INPUT ;
    USE SIGNAL ;
    PORT
      LAYER M4 ;
        RECT 0.000 100.608 0.192 100.632 ;
    END
  END n_a[203]
  PIN n_a[204]
    DIRECTION INPUT ;
    USE SIGNAL ;
    PORT
      LAYER M4 ;
        RECT 0.000 100.800 0.192 100.824 ;
    END
  END n_a[204]
  PIN n_a[205]
    DIRECTION INPUT ;
    USE SIGNAL ;
    PORT
      LAYER M4 ;
        RECT 0.000 100.992 0.192 101.016 ;
    END
  END n_a[205]
  PIN n_a[206]
    DIRECTION INPUT ;
    USE SIGNAL ;
    PORT
      LAYER M4 ;
        RECT 0.000 101.184 0.192 101.208 ;
    END
  END n_a[206]
  PIN n_a[207]
    DIRECTION INPUT ;
    USE SIGNAL ;
    PORT
      LAYER M4 ;
        RECT 0.000 101.376 0.192 101.400 ;
    END
  END n_a[207]
  PIN n_a[208]
    DIRECTION INPUT ;
    USE SIGNAL ;
    PORT
      LAYER M4 ;
        RECT 0.000 101.568 0.192 101.592 ;
    END
  END n_a[208]
  PIN n_a[209]
    DIRECTION INPUT ;
    USE SIGNAL ;
    PORT
      LAYER M4 ;
        RECT 0.000 101.760 0.192 101.784 ;
    END
  END n_a[209]
  PIN n_a[210]
    DIRECTION INPUT ;
    USE SIGNAL ;
    PORT
      LAYER M4 ;
        RECT 0.000 101.952 0.192 101.976 ;
    END
  END n_a[210]
  PIN n_a[211]
    DIRECTION INPUT ;
    USE SIGNAL ;
    PORT
      LAYER M4 ;
        RECT 0.000 102.144 0.192 102.168 ;
    END
  END n_a[211]
  PIN n_a[212]
    DIRECTION INPUT ;
    USE SIGNAL ;
    PORT
      LAYER M4 ;
        RECT 0.000 102.336 0.192 102.360 ;
    END
  END n_a[212]
  PIN n_a[213]
    DIRECTION INPUT ;
    USE SIGNAL ;
    PORT
      LAYER M4 ;
        RECT 0.000 102.528 0.192 102.552 ;
    END
  END n_a[213]
  PIN n_a[214]
    DIRECTION INPUT ;
    USE SIGNAL ;
    PORT
      LAYER M4 ;
        RECT 0.000 102.720 0.192 102.744 ;
    END
  END n_a[214]
  PIN n_a[215]
    DIRECTION INPUT ;
    USE SIGNAL ;
    PORT
      LAYER M4 ;
        RECT 0.000 102.912 0.192 102.936 ;
    END
  END n_a[215]
  PIN n_a[216]
    DIRECTION INPUT ;
    USE SIGNAL ;
    PORT
      LAYER M4 ;
        RECT 0.000 103.104 0.192 103.128 ;
    END
  END n_a[216]
  PIN n_a[217]
    DIRECTION INPUT ;
    USE SIGNAL ;
    PORT
      LAYER M4 ;
        RECT 0.000 103.296 0.192 103.320 ;
    END
  END n_a[217]
  PIN n_a[218]
    DIRECTION INPUT ;
    USE SIGNAL ;
    PORT
      LAYER M4 ;
        RECT 0.000 103.488 0.192 103.512 ;
    END
  END n_a[218]
  PIN n_a[219]
    DIRECTION INPUT ;
    USE SIGNAL ;
    PORT
      LAYER M4 ;
        RECT 0.000 103.680 0.192 103.704 ;
    END
  END n_a[219]
  PIN n_a[220]
    DIRECTION INPUT ;
    USE SIGNAL ;
    PORT
      LAYER M4 ;
        RECT 0.000 103.872 0.192 103.896 ;
    END
  END n_a[220]
  PIN n_a[221]
    DIRECTION INPUT ;
    USE SIGNAL ;
    PORT
      LAYER M4 ;
        RECT 0.000 104.064 0.192 104.088 ;
    END
  END n_a[221]
  PIN n_a[222]
    DIRECTION INPUT ;
    USE SIGNAL ;
    PORT
      LAYER M4 ;
        RECT 0.000 104.256 0.192 104.280 ;
    END
  END n_a[222]
  PIN n_a[223]
    DIRECTION INPUT ;
    USE SIGNAL ;
    PORT
      LAYER M4 ;
        RECT 0.000 104.448 0.192 104.472 ;
    END
  END n_a[223]
  PIN n_a[224]
    DIRECTION INPUT ;
    USE SIGNAL ;
    PORT
      LAYER M4 ;
        RECT 0.000 104.640 0.192 104.664 ;
    END
  END n_a[224]
  PIN n_a[225]
    DIRECTION INPUT ;
    USE SIGNAL ;
    PORT
      LAYER M4 ;
        RECT 0.000 104.832 0.192 104.856 ;
    END
  END n_a[225]
  PIN n_a[226]
    DIRECTION INPUT ;
    USE SIGNAL ;
    PORT
      LAYER M4 ;
        RECT 0.000 105.024 0.192 105.048 ;
    END
  END n_a[226]
  PIN n_a[227]
    DIRECTION INPUT ;
    USE SIGNAL ;
    PORT
      LAYER M4 ;
        RECT 0.000 105.216 0.192 105.240 ;
    END
  END n_a[227]
  PIN n_a[228]
    DIRECTION INPUT ;
    USE SIGNAL ;
    PORT
      LAYER M4 ;
        RECT 0.000 105.408 0.192 105.432 ;
    END
  END n_a[228]
  PIN n_a[229]
    DIRECTION INPUT ;
    USE SIGNAL ;
    PORT
      LAYER M4 ;
        RECT 0.000 105.600 0.192 105.624 ;
    END
  END n_a[229]
  PIN n_a[230]
    DIRECTION INPUT ;
    USE SIGNAL ;
    PORT
      LAYER M4 ;
        RECT 0.000 105.792 0.192 105.816 ;
    END
  END n_a[230]
  PIN n_a[231]
    DIRECTION INPUT ;
    USE SIGNAL ;
    PORT
      LAYER M4 ;
        RECT 0.000 105.984 0.192 106.008 ;
    END
  END n_a[231]
  PIN n_a[232]
    DIRECTION INPUT ;
    USE SIGNAL ;
    PORT
      LAYER M4 ;
        RECT 0.000 106.176 0.192 106.200 ;
    END
  END n_a[232]
  PIN n_a[233]
    DIRECTION INPUT ;
    USE SIGNAL ;
    PORT
      LAYER M4 ;
        RECT 0.000 106.368 0.192 106.392 ;
    END
  END n_a[233]
  PIN n_a[234]
    DIRECTION INPUT ;
    USE SIGNAL ;
    PORT
      LAYER M4 ;
        RECT 0.000 106.560 0.192 106.584 ;
    END
  END n_a[234]
  PIN n_a[235]
    DIRECTION INPUT ;
    USE SIGNAL ;
    PORT
      LAYER M4 ;
        RECT 0.000 106.752 0.192 106.776 ;
    END
  END n_a[235]
  PIN n_a[236]
    DIRECTION INPUT ;
    USE SIGNAL ;
    PORT
      LAYER M4 ;
        RECT 0.000 106.944 0.192 106.968 ;
    END
  END n_a[236]
  PIN n_a[237]
    DIRECTION INPUT ;
    USE SIGNAL ;
    PORT
      LAYER M4 ;
        RECT 0.000 107.136 0.192 107.160 ;
    END
  END n_a[237]
  PIN n_a[238]
    DIRECTION INPUT ;
    USE SIGNAL ;
    PORT
      LAYER M4 ;
        RECT 0.000 107.328 0.192 107.352 ;
    END
  END n_a[238]
  PIN n_a[239]
    DIRECTION INPUT ;
    USE SIGNAL ;
    PORT
      LAYER M4 ;
        RECT 0.000 107.520 0.192 107.544 ;
    END
  END n_a[239]
  PIN n_a[240]
    DIRECTION INPUT ;
    USE SIGNAL ;
    PORT
      LAYER M4 ;
        RECT 0.000 107.712 0.192 107.736 ;
    END
  END n_a[240]
  PIN n_a[241]
    DIRECTION INPUT ;
    USE SIGNAL ;
    PORT
      LAYER M4 ;
        RECT 0.000 107.904 0.192 107.928 ;
    END
  END n_a[241]
  PIN n_a[242]
    DIRECTION INPUT ;
    USE SIGNAL ;
    PORT
      LAYER M4 ;
        RECT 0.000 108.096 0.192 108.120 ;
    END
  END n_a[242]
  PIN n_a[243]
    DIRECTION INPUT ;
    USE SIGNAL ;
    PORT
      LAYER M4 ;
        RECT 0.000 108.288 0.192 108.312 ;
    END
  END n_a[243]
  PIN n_a[244]
    DIRECTION INPUT ;
    USE SIGNAL ;
    PORT
      LAYER M4 ;
        RECT 0.000 108.480 0.192 108.504 ;
    END
  END n_a[244]
  PIN n_a[245]
    DIRECTION INPUT ;
    USE SIGNAL ;
    PORT
      LAYER M4 ;
        RECT 0.000 108.672 0.192 108.696 ;
    END
  END n_a[245]
  PIN n_a[246]
    DIRECTION INPUT ;
    USE SIGNAL ;
    PORT
      LAYER M4 ;
        RECT 0.000 108.864 0.192 108.888 ;
    END
  END n_a[246]
  PIN n_a[247]
    DIRECTION INPUT ;
    USE SIGNAL ;
    PORT
      LAYER M4 ;
        RECT 0.000 109.056 0.192 109.080 ;
    END
  END n_a[247]
  PIN n_a[248]
    DIRECTION INPUT ;
    USE SIGNAL ;
    PORT
      LAYER M4 ;
        RECT 0.000 109.248 0.192 109.272 ;
    END
  END n_a[248]
  PIN n_a[249]
    DIRECTION INPUT ;
    USE SIGNAL ;
    PORT
      LAYER M4 ;
        RECT 0.000 109.440 0.192 109.464 ;
    END
  END n_a[249]
  PIN n_a[250]
    DIRECTION INPUT ;
    USE SIGNAL ;
    PORT
      LAYER M4 ;
        RECT 0.000 109.632 0.192 109.656 ;
    END
  END n_a[250]
  PIN n_a[251]
    DIRECTION INPUT ;
    USE SIGNAL ;
    PORT
      LAYER M4 ;
        RECT 0.000 109.824 0.192 109.848 ;
    END
  END n_a[251]
  PIN n_a[252]
    DIRECTION INPUT ;
    USE SIGNAL ;
    PORT
      LAYER M4 ;
        RECT 0.000 110.016 0.192 110.040 ;
    END
  END n_a[252]
  PIN n_a[253]
    DIRECTION INPUT ;
    USE SIGNAL ;
    PORT
      LAYER M4 ;
        RECT 0.000 110.208 0.192 110.232 ;
    END
  END n_a[253]
  PIN n_a[254]
    DIRECTION INPUT ;
    USE SIGNAL ;
    PORT
      LAYER M4 ;
        RECT 0.000 110.400 0.192 110.424 ;
    END
  END n_a[254]
  PIN n_a[255]
    DIRECTION INPUT ;
    USE SIGNAL ;
    PORT
      LAYER M4 ;
        RECT 0.000 110.592 0.192 110.616 ;
    END
  END n_a[255]
  PIN n_a[256]
    DIRECTION INPUT ;
    USE SIGNAL ;
    PORT
      LAYER M4 ;
        RECT 0.000 110.784 0.192 110.808 ;
    END
  END n_a[256]
  PIN n_a[257]
    DIRECTION INPUT ;
    USE SIGNAL ;
    PORT
      LAYER M4 ;
        RECT 0.000 110.976 0.192 111.000 ;
    END
  END n_a[257]
  PIN n_a[258]
    DIRECTION INPUT ;
    USE SIGNAL ;
    PORT
      LAYER M4 ;
        RECT 0.000 111.168 0.192 111.192 ;
    END
  END n_a[258]
  PIN n_a[259]
    DIRECTION INPUT ;
    USE SIGNAL ;
    PORT
      LAYER M4 ;
        RECT 0.000 111.360 0.192 111.384 ;
    END
  END n_a[259]
  PIN n_a[260]
    DIRECTION INPUT ;
    USE SIGNAL ;
    PORT
      LAYER M4 ;
        RECT 0.000 111.552 0.192 111.576 ;
    END
  END n_a[260]
  PIN n_a[261]
    DIRECTION INPUT ;
    USE SIGNAL ;
    PORT
      LAYER M4 ;
        RECT 0.000 111.744 0.192 111.768 ;
    END
  END n_a[261]
  PIN n_a[262]
    DIRECTION INPUT ;
    USE SIGNAL ;
    PORT
      LAYER M4 ;
        RECT 0.000 111.936 0.192 111.960 ;
    END
  END n_a[262]
  PIN n_a[263]
    DIRECTION INPUT ;
    USE SIGNAL ;
    PORT
      LAYER M4 ;
        RECT 0.000 112.128 0.192 112.152 ;
    END
  END n_a[263]
  PIN n_a[264]
    DIRECTION INPUT ;
    USE SIGNAL ;
    PORT
      LAYER M4 ;
        RECT 0.000 112.320 0.192 112.344 ;
    END
  END n_a[264]
  PIN n_a[265]
    DIRECTION INPUT ;
    USE SIGNAL ;
    PORT
      LAYER M4 ;
        RECT 0.000 112.512 0.192 112.536 ;
    END
  END n_a[265]
  PIN n_a[266]
    DIRECTION INPUT ;
    USE SIGNAL ;
    PORT
      LAYER M4 ;
        RECT 0.000 112.704 0.192 112.728 ;
    END
  END n_a[266]
  PIN n_a[267]
    DIRECTION INPUT ;
    USE SIGNAL ;
    PORT
      LAYER M4 ;
        RECT 0.000 112.896 0.192 112.920 ;
    END
  END n_a[267]
  PIN n_a[268]
    DIRECTION INPUT ;
    USE SIGNAL ;
    PORT
      LAYER M4 ;
        RECT 0.000 113.088 0.192 113.112 ;
    END
  END n_a[268]
  PIN n_a[269]
    DIRECTION INPUT ;
    USE SIGNAL ;
    PORT
      LAYER M4 ;
        RECT 0.000 113.280 0.192 113.304 ;
    END
  END n_a[269]
  PIN n_a[270]
    DIRECTION INPUT ;
    USE SIGNAL ;
    PORT
      LAYER M4 ;
        RECT 0.000 113.472 0.192 113.496 ;
    END
  END n_a[270]
  PIN n_a[271]
    DIRECTION INPUT ;
    USE SIGNAL ;
    PORT
      LAYER M4 ;
        RECT 0.000 113.664 0.192 113.688 ;
    END
  END n_a[271]
  PIN n_a[272]
    DIRECTION INPUT ;
    USE SIGNAL ;
    PORT
      LAYER M4 ;
        RECT 0.000 113.856 0.192 113.880 ;
    END
  END n_a[272]
  PIN n_a[273]
    DIRECTION INPUT ;
    USE SIGNAL ;
    PORT
      LAYER M4 ;
        RECT 0.000 114.048 0.192 114.072 ;
    END
  END n_a[273]
  PIN n_a[274]
    DIRECTION INPUT ;
    USE SIGNAL ;
    PORT
      LAYER M4 ;
        RECT 0.000 114.240 0.192 114.264 ;
    END
  END n_a[274]
  PIN n_a[275]
    DIRECTION INPUT ;
    USE SIGNAL ;
    PORT
      LAYER M4 ;
        RECT 0.000 114.432 0.192 114.456 ;
    END
  END n_a[275]
  PIN n_a[276]
    DIRECTION INPUT ;
    USE SIGNAL ;
    PORT
      LAYER M4 ;
        RECT 0.000 114.624 0.192 114.648 ;
    END
  END n_a[276]
  PIN n_a[277]
    DIRECTION INPUT ;
    USE SIGNAL ;
    PORT
      LAYER M4 ;
        RECT 0.000 114.816 0.192 114.840 ;
    END
  END n_a[277]
  PIN n_a[278]
    DIRECTION INPUT ;
    USE SIGNAL ;
    PORT
      LAYER M4 ;
        RECT 0.000 115.008 0.192 115.032 ;
    END
  END n_a[278]
  PIN n_a[279]
    DIRECTION INPUT ;
    USE SIGNAL ;
    PORT
      LAYER M4 ;
        RECT 0.000 115.200 0.192 115.224 ;
    END
  END n_a[279]
  PIN n_a[280]
    DIRECTION INPUT ;
    USE SIGNAL ;
    PORT
      LAYER M4 ;
        RECT 0.000 115.392 0.192 115.416 ;
    END
  END n_a[280]
  PIN n_a[281]
    DIRECTION INPUT ;
    USE SIGNAL ;
    PORT
      LAYER M4 ;
        RECT 0.000 115.584 0.192 115.608 ;
    END
  END n_a[281]
  PIN n_a[282]
    DIRECTION INPUT ;
    USE SIGNAL ;
    PORT
      LAYER M4 ;
        RECT 0.000 115.776 0.192 115.800 ;
    END
  END n_a[282]
  PIN n_a[283]
    DIRECTION INPUT ;
    USE SIGNAL ;
    PORT
      LAYER M4 ;
        RECT 0.000 115.968 0.192 115.992 ;
    END
  END n_a[283]
  PIN n_a[284]
    DIRECTION INPUT ;
    USE SIGNAL ;
    PORT
      LAYER M4 ;
        RECT 0.000 116.160 0.192 116.184 ;
    END
  END n_a[284]
  PIN n_a[285]
    DIRECTION INPUT ;
    USE SIGNAL ;
    PORT
      LAYER M4 ;
        RECT 0.000 116.352 0.192 116.376 ;
    END
  END n_a[285]
  PIN n_a[286]
    DIRECTION INPUT ;
    USE SIGNAL ;
    PORT
      LAYER M4 ;
        RECT 0.000 116.544 0.192 116.568 ;
    END
  END n_a[286]
  PIN n_a[287]
    DIRECTION INPUT ;
    USE SIGNAL ;
    PORT
      LAYER M4 ;
        RECT 0.000 116.736 0.192 116.760 ;
    END
  END n_a[287]
  PIN n_a[288]
    DIRECTION INPUT ;
    USE SIGNAL ;
    PORT
      LAYER M4 ;
        RECT 0.000 116.928 0.192 116.952 ;
    END
  END n_a[288]
  PIN n_a[289]
    DIRECTION INPUT ;
    USE SIGNAL ;
    PORT
      LAYER M4 ;
        RECT 0.000 117.120 0.192 117.144 ;
    END
  END n_a[289]
  PIN n_a[290]
    DIRECTION INPUT ;
    USE SIGNAL ;
    PORT
      LAYER M4 ;
        RECT 0.000 117.312 0.192 117.336 ;
    END
  END n_a[290]
  PIN n_a[291]
    DIRECTION INPUT ;
    USE SIGNAL ;
    PORT
      LAYER M4 ;
        RECT 0.000 117.504 0.192 117.528 ;
    END
  END n_a[291]
  PIN n_a[292]
    DIRECTION INPUT ;
    USE SIGNAL ;
    PORT
      LAYER M4 ;
        RECT 0.000 117.696 0.192 117.720 ;
    END
  END n_a[292]
  PIN n_a[293]
    DIRECTION INPUT ;
    USE SIGNAL ;
    PORT
      LAYER M4 ;
        RECT 0.000 117.888 0.192 117.912 ;
    END
  END n_a[293]
  PIN n_a[294]
    DIRECTION INPUT ;
    USE SIGNAL ;
    PORT
      LAYER M4 ;
        RECT 0.000 118.080 0.192 118.104 ;
    END
  END n_a[294]
  PIN n_a[295]
    DIRECTION INPUT ;
    USE SIGNAL ;
    PORT
      LAYER M4 ;
        RECT 0.000 118.272 0.192 118.296 ;
    END
  END n_a[295]
  PIN n_a[296]
    DIRECTION INPUT ;
    USE SIGNAL ;
    PORT
      LAYER M4 ;
        RECT 0.000 118.464 0.192 118.488 ;
    END
  END n_a[296]
  PIN n_a[297]
    DIRECTION INPUT ;
    USE SIGNAL ;
    PORT
      LAYER M4 ;
        RECT 0.000 118.656 0.192 118.680 ;
    END
  END n_a[297]
  PIN n_a[298]
    DIRECTION INPUT ;
    USE SIGNAL ;
    PORT
      LAYER M4 ;
        RECT 0.000 118.848 0.192 118.872 ;
    END
  END n_a[298]
  PIN n_a[299]
    DIRECTION INPUT ;
    USE SIGNAL ;
    PORT
      LAYER M4 ;
        RECT 0.000 119.040 0.192 119.064 ;
    END
  END n_a[299]
  PIN n_a[300]
    DIRECTION INPUT ;
    USE SIGNAL ;
    PORT
      LAYER M4 ;
        RECT 0.000 119.232 0.192 119.256 ;
    END
  END n_a[300]
  PIN n_a[301]
    DIRECTION INPUT ;
    USE SIGNAL ;
    PORT
      LAYER M4 ;
        RECT 0.000 119.424 0.192 119.448 ;
    END
  END n_a[301]
  PIN n_a[302]
    DIRECTION INPUT ;
    USE SIGNAL ;
    PORT
      LAYER M4 ;
        RECT 0.000 119.616 0.192 119.640 ;
    END
  END n_a[302]
  PIN n_a[303]
    DIRECTION INPUT ;
    USE SIGNAL ;
    PORT
      LAYER M4 ;
        RECT 0.000 119.808 0.192 119.832 ;
    END
  END n_a[303]
  PIN n_a[304]
    DIRECTION INPUT ;
    USE SIGNAL ;
    PORT
      LAYER M4 ;
        RECT 0.000 120.000 0.192 120.024 ;
    END
  END n_a[304]
  PIN n_a[305]
    DIRECTION INPUT ;
    USE SIGNAL ;
    PORT
      LAYER M4 ;
        RECT 0.000 120.192 0.192 120.216 ;
    END
  END n_a[305]
  PIN n_a[306]
    DIRECTION INPUT ;
    USE SIGNAL ;
    PORT
      LAYER M4 ;
        RECT 0.000 120.384 0.192 120.408 ;
    END
  END n_a[306]
  PIN n_a[307]
    DIRECTION INPUT ;
    USE SIGNAL ;
    PORT
      LAYER M4 ;
        RECT 0.000 120.576 0.192 120.600 ;
    END
  END n_a[307]
  PIN n_a[308]
    DIRECTION INPUT ;
    USE SIGNAL ;
    PORT
      LAYER M4 ;
        RECT 0.000 120.768 0.192 120.792 ;
    END
  END n_a[308]
  PIN n_a[309]
    DIRECTION INPUT ;
    USE SIGNAL ;
    PORT
      LAYER M4 ;
        RECT 0.000 120.960 0.192 120.984 ;
    END
  END n_a[309]
  PIN n_a[310]
    DIRECTION INPUT ;
    USE SIGNAL ;
    PORT
      LAYER M4 ;
        RECT 0.000 121.152 0.192 121.176 ;
    END
  END n_a[310]
  PIN n_a[311]
    DIRECTION INPUT ;
    USE SIGNAL ;
    PORT
      LAYER M4 ;
        RECT 0.000 121.344 0.192 121.368 ;
    END
  END n_a[311]
  PIN n_a[312]
    DIRECTION INPUT ;
    USE SIGNAL ;
    PORT
      LAYER M4 ;
        RECT 0.000 121.536 0.192 121.560 ;
    END
  END n_a[312]
  PIN n_a[313]
    DIRECTION INPUT ;
    USE SIGNAL ;
    PORT
      LAYER M4 ;
        RECT 0.000 121.728 0.192 121.752 ;
    END
  END n_a[313]
  PIN n_a[314]
    DIRECTION INPUT ;
    USE SIGNAL ;
    PORT
      LAYER M4 ;
        RECT 0.000 121.920 0.192 121.944 ;
    END
  END n_a[314]
  PIN n_a[315]
    DIRECTION INPUT ;
    USE SIGNAL ;
    PORT
      LAYER M4 ;
        RECT 0.000 122.112 0.192 122.136 ;
    END
  END n_a[315]
  PIN n_a[316]
    DIRECTION INPUT ;
    USE SIGNAL ;
    PORT
      LAYER M4 ;
        RECT 0.000 122.304 0.192 122.328 ;
    END
  END n_a[316]
  PIN n_a[317]
    DIRECTION INPUT ;
    USE SIGNAL ;
    PORT
      LAYER M4 ;
        RECT 0.000 122.496 0.192 122.520 ;
    END
  END n_a[317]
  PIN n_a[318]
    DIRECTION INPUT ;
    USE SIGNAL ;
    PORT
      LAYER M4 ;
        RECT 0.000 122.688 0.192 122.712 ;
    END
  END n_a[318]
  PIN n_a[319]
    DIRECTION INPUT ;
    USE SIGNAL ;
    PORT
      LAYER M4 ;
        RECT 0.000 122.880 0.192 122.904 ;
    END
  END n_a[319]
  PIN n_a[320]
    DIRECTION INPUT ;
    USE SIGNAL ;
    PORT
      LAYER M4 ;
        RECT 0.000 123.072 0.192 123.096 ;
    END
  END n_a[320]
  PIN n_a[321]
    DIRECTION INPUT ;
    USE SIGNAL ;
    PORT
      LAYER M4 ;
        RECT 0.000 123.264 0.192 123.288 ;
    END
  END n_a[321]
  PIN n_a[322]
    DIRECTION INPUT ;
    USE SIGNAL ;
    PORT
      LAYER M4 ;
        RECT 0.000 123.456 0.192 123.480 ;
    END
  END n_a[322]
  PIN n_a[323]
    DIRECTION INPUT ;
    USE SIGNAL ;
    PORT
      LAYER M4 ;
        RECT 0.000 123.648 0.192 123.672 ;
    END
  END n_a[323]
  PIN n_a[324]
    DIRECTION INPUT ;
    USE SIGNAL ;
    PORT
      LAYER M4 ;
        RECT 0.000 123.840 0.192 123.864 ;
    END
  END n_a[324]
  PIN n_a[325]
    DIRECTION INPUT ;
    USE SIGNAL ;
    PORT
      LAYER M4 ;
        RECT 0.000 124.032 0.192 124.056 ;
    END
  END n_a[325]
  PIN n_a[326]
    DIRECTION INPUT ;
    USE SIGNAL ;
    PORT
      LAYER M4 ;
        RECT 0.000 124.224 0.192 124.248 ;
    END
  END n_a[326]
  PIN n_a[327]
    DIRECTION INPUT ;
    USE SIGNAL ;
    PORT
      LAYER M4 ;
        RECT 0.000 124.416 0.192 124.440 ;
    END
  END n_a[327]
  PIN n_a[328]
    DIRECTION INPUT ;
    USE SIGNAL ;
    PORT
      LAYER M4 ;
        RECT 0.000 124.608 0.192 124.632 ;
    END
  END n_a[328]
  PIN n_a[329]
    DIRECTION INPUT ;
    USE SIGNAL ;
    PORT
      LAYER M4 ;
        RECT 0.000 124.800 0.192 124.824 ;
    END
  END n_a[329]
  PIN n_a[330]
    DIRECTION INPUT ;
    USE SIGNAL ;
    PORT
      LAYER M4 ;
        RECT 0.000 124.992 0.192 125.016 ;
    END
  END n_a[330]
  PIN n_a[331]
    DIRECTION INPUT ;
    USE SIGNAL ;
    PORT
      LAYER M4 ;
        RECT 0.000 125.184 0.192 125.208 ;
    END
  END n_a[331]
  PIN n_a[332]
    DIRECTION INPUT ;
    USE SIGNAL ;
    PORT
      LAYER M4 ;
        RECT 0.000 125.376 0.192 125.400 ;
    END
  END n_a[332]
  PIN n_a[333]
    DIRECTION INPUT ;
    USE SIGNAL ;
    PORT
      LAYER M4 ;
        RECT 0.000 125.568 0.192 125.592 ;
    END
  END n_a[333]
  PIN n_a[334]
    DIRECTION INPUT ;
    USE SIGNAL ;
    PORT
      LAYER M4 ;
        RECT 0.000 125.760 0.192 125.784 ;
    END
  END n_a[334]
  PIN n_a[335]
    DIRECTION INPUT ;
    USE SIGNAL ;
    PORT
      LAYER M4 ;
        RECT 0.000 125.952 0.192 125.976 ;
    END
  END n_a[335]
  PIN n_a[336]
    DIRECTION INPUT ;
    USE SIGNAL ;
    PORT
      LAYER M4 ;
        RECT 0.000 126.144 0.192 126.168 ;
    END
  END n_a[336]
  PIN n_a[337]
    DIRECTION INPUT ;
    USE SIGNAL ;
    PORT
      LAYER M4 ;
        RECT 0.000 126.336 0.192 126.360 ;
    END
  END n_a[337]
  PIN n_a[338]
    DIRECTION INPUT ;
    USE SIGNAL ;
    PORT
      LAYER M4 ;
        RECT 0.000 126.528 0.192 126.552 ;
    END
  END n_a[338]
  PIN n_a[339]
    DIRECTION INPUT ;
    USE SIGNAL ;
    PORT
      LAYER M4 ;
        RECT 0.000 126.720 0.192 126.744 ;
    END
  END n_a[339]
  PIN n_a[340]
    DIRECTION INPUT ;
    USE SIGNAL ;
    PORT
      LAYER M4 ;
        RECT 0.000 126.912 0.192 126.936 ;
    END
  END n_a[340]
  PIN n_a[341]
    DIRECTION INPUT ;
    USE SIGNAL ;
    PORT
      LAYER M4 ;
        RECT 0.000 127.104 0.192 127.128 ;
    END
  END n_a[341]
  PIN n_a[342]
    DIRECTION INPUT ;
    USE SIGNAL ;
    PORT
      LAYER M4 ;
        RECT 0.000 127.296 0.192 127.320 ;
    END
  END n_a[342]
  PIN n_a[343]
    DIRECTION INPUT ;
    USE SIGNAL ;
    PORT
      LAYER M4 ;
        RECT 0.000 127.488 0.192 127.512 ;
    END
  END n_a[343]
  PIN n_a[344]
    DIRECTION INPUT ;
    USE SIGNAL ;
    PORT
      LAYER M4 ;
        RECT 0.000 127.680 0.192 127.704 ;
    END
  END n_a[344]
  PIN n_a[345]
    DIRECTION INPUT ;
    USE SIGNAL ;
    PORT
      LAYER M4 ;
        RECT 0.000 127.872 0.192 127.896 ;
    END
  END n_a[345]
  PIN n_a[346]
    DIRECTION INPUT ;
    USE SIGNAL ;
    PORT
      LAYER M4 ;
        RECT 0.000 128.064 0.192 128.088 ;
    END
  END n_a[346]
  PIN n_a[347]
    DIRECTION INPUT ;
    USE SIGNAL ;
    PORT
      LAYER M4 ;
        RECT 0.000 128.256 0.192 128.280 ;
    END
  END n_a[347]
  PIN n_a[348]
    DIRECTION INPUT ;
    USE SIGNAL ;
    PORT
      LAYER M4 ;
        RECT 0.000 128.448 0.192 128.472 ;
    END
  END n_a[348]
  PIN n_a[349]
    DIRECTION INPUT ;
    USE SIGNAL ;
    PORT
      LAYER M4 ;
        RECT 0.000 128.640 0.192 128.664 ;
    END
  END n_a[349]
  PIN n_a[350]
    DIRECTION INPUT ;
    USE SIGNAL ;
    PORT
      LAYER M4 ;
        RECT 0.000 128.832 0.192 128.856 ;
    END
  END n_a[350]
  PIN n_a[351]
    DIRECTION INPUT ;
    USE SIGNAL ;
    PORT
      LAYER M4 ;
        RECT 0.000 129.024 0.192 129.048 ;
    END
  END n_a[351]
  PIN n_a[352]
    DIRECTION INPUT ;
    USE SIGNAL ;
    PORT
      LAYER M4 ;
        RECT 0.000 129.216 0.192 129.240 ;
    END
  END n_a[352]
  PIN n_a[353]
    DIRECTION INPUT ;
    USE SIGNAL ;
    PORT
      LAYER M4 ;
        RECT 0.000 129.408 0.192 129.432 ;
    END
  END n_a[353]
  PIN n_a[354]
    DIRECTION INPUT ;
    USE SIGNAL ;
    PORT
      LAYER M4 ;
        RECT 0.000 129.600 0.192 129.624 ;
    END
  END n_a[354]
  PIN n_a[355]
    DIRECTION INPUT ;
    USE SIGNAL ;
    PORT
      LAYER M4 ;
        RECT 0.000 129.792 0.192 129.816 ;
    END
  END n_a[355]
  PIN n_a[356]
    DIRECTION INPUT ;
    USE SIGNAL ;
    PORT
      LAYER M4 ;
        RECT 0.000 129.984 0.192 130.008 ;
    END
  END n_a[356]
  PIN n_a[357]
    DIRECTION INPUT ;
    USE SIGNAL ;
    PORT
      LAYER M4 ;
        RECT 0.000 130.176 0.192 130.200 ;
    END
  END n_a[357]
  PIN n_a[358]
    DIRECTION INPUT ;
    USE SIGNAL ;
    PORT
      LAYER M4 ;
        RECT 0.000 130.368 0.192 130.392 ;
    END
  END n_a[358]
  PIN n_a[359]
    DIRECTION INPUT ;
    USE SIGNAL ;
    PORT
      LAYER M4 ;
        RECT 0.000 130.560 0.192 130.584 ;
    END
  END n_a[359]
  PIN n_a[360]
    DIRECTION INPUT ;
    USE SIGNAL ;
    PORT
      LAYER M4 ;
        RECT 0.000 130.752 0.192 130.776 ;
    END
  END n_a[360]
  PIN n_a[361]
    DIRECTION INPUT ;
    USE SIGNAL ;
    PORT
      LAYER M4 ;
        RECT 0.000 130.944 0.192 130.968 ;
    END
  END n_a[361]
  PIN n_a[362]
    DIRECTION INPUT ;
    USE SIGNAL ;
    PORT
      LAYER M4 ;
        RECT 0.000 131.136 0.192 131.160 ;
    END
  END n_a[362]
  PIN n_a[363]
    DIRECTION INPUT ;
    USE SIGNAL ;
    PORT
      LAYER M4 ;
        RECT 0.000 131.328 0.192 131.352 ;
    END
  END n_a[363]
  PIN n_a[364]
    DIRECTION INPUT ;
    USE SIGNAL ;
    PORT
      LAYER M4 ;
        RECT 0.000 131.520 0.192 131.544 ;
    END
  END n_a[364]
  PIN n_a[365]
    DIRECTION INPUT ;
    USE SIGNAL ;
    PORT
      LAYER M4 ;
        RECT 0.000 131.712 0.192 131.736 ;
    END
  END n_a[365]
  PIN n_a[366]
    DIRECTION INPUT ;
    USE SIGNAL ;
    PORT
      LAYER M4 ;
        RECT 0.000 131.904 0.192 131.928 ;
    END
  END n_a[366]
  PIN n_a[367]
    DIRECTION INPUT ;
    USE SIGNAL ;
    PORT
      LAYER M4 ;
        RECT 0.000 132.096 0.192 132.120 ;
    END
  END n_a[367]
  PIN n_a[368]
    DIRECTION INPUT ;
    USE SIGNAL ;
    PORT
      LAYER M4 ;
        RECT 0.000 132.288 0.192 132.312 ;
    END
  END n_a[368]
  PIN n_a[369]
    DIRECTION INPUT ;
    USE SIGNAL ;
    PORT
      LAYER M4 ;
        RECT 0.000 132.480 0.192 132.504 ;
    END
  END n_a[369]
  PIN n_a[370]
    DIRECTION INPUT ;
    USE SIGNAL ;
    PORT
      LAYER M4 ;
        RECT 0.000 132.672 0.192 132.696 ;
    END
  END n_a[370]
  PIN n_a[371]
    DIRECTION INPUT ;
    USE SIGNAL ;
    PORT
      LAYER M4 ;
        RECT 0.000 132.864 0.192 132.888 ;
    END
  END n_a[371]
  PIN n_a[372]
    DIRECTION INPUT ;
    USE SIGNAL ;
    PORT
      LAYER M4 ;
        RECT 0.000 133.056 0.192 133.080 ;
    END
  END n_a[372]
  PIN n_a[373]
    DIRECTION INPUT ;
    USE SIGNAL ;
    PORT
      LAYER M4 ;
        RECT 0.000 133.248 0.192 133.272 ;
    END
  END n_a[373]
  PIN n_a[374]
    DIRECTION INPUT ;
    USE SIGNAL ;
    PORT
      LAYER M4 ;
        RECT 0.000 133.440 0.192 133.464 ;
    END
  END n_a[374]
  PIN n_a[375]
    DIRECTION INPUT ;
    USE SIGNAL ;
    PORT
      LAYER M4 ;
        RECT 0.000 133.632 0.192 133.656 ;
    END
  END n_a[375]
  PIN n_a[376]
    DIRECTION INPUT ;
    USE SIGNAL ;
    PORT
      LAYER M4 ;
        RECT 0.000 133.824 0.192 133.848 ;
    END
  END n_a[376]
  PIN n_a[377]
    DIRECTION INPUT ;
    USE SIGNAL ;
    PORT
      LAYER M4 ;
        RECT 0.000 134.016 0.192 134.040 ;
    END
  END n_a[377]
  PIN n_a[378]
    DIRECTION INPUT ;
    USE SIGNAL ;
    PORT
      LAYER M4 ;
        RECT 0.000 134.208 0.192 134.232 ;
    END
  END n_a[378]
  PIN n_a[379]
    DIRECTION INPUT ;
    USE SIGNAL ;
    PORT
      LAYER M4 ;
        RECT 0.000 134.400 0.192 134.424 ;
    END
  END n_a[379]
  PIN n_a[380]
    DIRECTION INPUT ;
    USE SIGNAL ;
    PORT
      LAYER M4 ;
        RECT 0.000 134.592 0.192 134.616 ;
    END
  END n_a[380]
  PIN n_a[381]
    DIRECTION INPUT ;
    USE SIGNAL ;
    PORT
      LAYER M4 ;
        RECT 0.000 134.784 0.192 134.808 ;
    END
  END n_a[381]
  PIN n_a[382]
    DIRECTION INPUT ;
    USE SIGNAL ;
    PORT
      LAYER M4 ;
        RECT 0.000 134.976 0.192 135.000 ;
    END
  END n_a[382]
  PIN n_a[383]
    DIRECTION INPUT ;
    USE SIGNAL ;
    PORT
      LAYER M4 ;
        RECT 0.000 135.168 0.192 135.192 ;
    END
  END n_a[383]
  PIN n_a[384]
    DIRECTION INPUT ;
    USE SIGNAL ;
    PORT
      LAYER M4 ;
        RECT 0.000 135.360 0.192 135.384 ;
    END
  END n_a[384]
  PIN n_a[385]
    DIRECTION INPUT ;
    USE SIGNAL ;
    PORT
      LAYER M4 ;
        RECT 0.000 135.552 0.192 135.576 ;
    END
  END n_a[385]
  PIN n_a[386]
    DIRECTION INPUT ;
    USE SIGNAL ;
    PORT
      LAYER M4 ;
        RECT 0.000 135.744 0.192 135.768 ;
    END
  END n_a[386]
  PIN n_a[387]
    DIRECTION INPUT ;
    USE SIGNAL ;
    PORT
      LAYER M4 ;
        RECT 0.000 135.936 0.192 135.960 ;
    END
  END n_a[387]
  PIN n_a[388]
    DIRECTION INPUT ;
    USE SIGNAL ;
    PORT
      LAYER M4 ;
        RECT 0.000 136.128 0.192 136.152 ;
    END
  END n_a[388]
  PIN n_a[389]
    DIRECTION INPUT ;
    USE SIGNAL ;
    PORT
      LAYER M4 ;
        RECT 0.000 136.320 0.192 136.344 ;
    END
  END n_a[389]
  PIN n_a[390]
    DIRECTION INPUT ;
    USE SIGNAL ;
    PORT
      LAYER M4 ;
        RECT 0.000 136.512 0.192 136.536 ;
    END
  END n_a[390]
  PIN n_a[391]
    DIRECTION INPUT ;
    USE SIGNAL ;
    PORT
      LAYER M4 ;
        RECT 0.000 136.704 0.192 136.728 ;
    END
  END n_a[391]
  PIN n_a[392]
    DIRECTION INPUT ;
    USE SIGNAL ;
    PORT
      LAYER M4 ;
        RECT 0.000 136.896 0.192 136.920 ;
    END
  END n_a[392]
  PIN n_a[393]
    DIRECTION INPUT ;
    USE SIGNAL ;
    PORT
      LAYER M4 ;
        RECT 0.000 137.088 0.192 137.112 ;
    END
  END n_a[393]
  PIN n_a[394]
    DIRECTION INPUT ;
    USE SIGNAL ;
    PORT
      LAYER M4 ;
        RECT 0.000 137.280 0.192 137.304 ;
    END
  END n_a[394]
  PIN n_a[395]
    DIRECTION INPUT ;
    USE SIGNAL ;
    PORT
      LAYER M4 ;
        RECT 0.000 137.472 0.192 137.496 ;
    END
  END n_a[395]
  PIN n_a[396]
    DIRECTION INPUT ;
    USE SIGNAL ;
    PORT
      LAYER M4 ;
        RECT 0.000 137.664 0.192 137.688 ;
    END
  END n_a[396]
  PIN n_a[397]
    DIRECTION INPUT ;
    USE SIGNAL ;
    PORT
      LAYER M4 ;
        RECT 0.000 137.856 0.192 137.880 ;
    END
  END n_a[397]
  PIN n_a[398]
    DIRECTION INPUT ;
    USE SIGNAL ;
    PORT
      LAYER M4 ;
        RECT 0.000 138.048 0.192 138.072 ;
    END
  END n_a[398]
  PIN n_a[399]
    DIRECTION INPUT ;
    USE SIGNAL ;
    PORT
      LAYER M4 ;
        RECT 0.000 138.240 0.192 138.264 ;
    END
  END n_a[399]
  PIN n_a[400]
    DIRECTION INPUT ;
    USE SIGNAL ;
    PORT
      LAYER M4 ;
        RECT 0.000 138.432 0.192 138.456 ;
    END
  END n_a[400]
  PIN n_a[401]
    DIRECTION INPUT ;
    USE SIGNAL ;
    PORT
      LAYER M4 ;
        RECT 0.000 138.624 0.192 138.648 ;
    END
  END n_a[401]
  PIN n_a[402]
    DIRECTION INPUT ;
    USE SIGNAL ;
    PORT
      LAYER M4 ;
        RECT 0.000 138.816 0.192 138.840 ;
    END
  END n_a[402]
  PIN n_a[403]
    DIRECTION INPUT ;
    USE SIGNAL ;
    PORT
      LAYER M4 ;
        RECT 0.000 139.008 0.192 139.032 ;
    END
  END n_a[403]
  PIN n_a[404]
    DIRECTION INPUT ;
    USE SIGNAL ;
    PORT
      LAYER M4 ;
        RECT 0.000 139.200 0.192 139.224 ;
    END
  END n_a[404]
  PIN n_a[405]
    DIRECTION INPUT ;
    USE SIGNAL ;
    PORT
      LAYER M4 ;
        RECT 0.000 139.392 0.192 139.416 ;
    END
  END n_a[405]
  PIN n_a[406]
    DIRECTION INPUT ;
    USE SIGNAL ;
    PORT
      LAYER M4 ;
        RECT 0.000 139.584 0.192 139.608 ;
    END
  END n_a[406]
  PIN n_a[407]
    DIRECTION INPUT ;
    USE SIGNAL ;
    PORT
      LAYER M4 ;
        RECT 0.000 139.776 0.192 139.800 ;
    END
  END n_a[407]
  PIN n_a[408]
    DIRECTION INPUT ;
    USE SIGNAL ;
    PORT
      LAYER M4 ;
        RECT 0.000 139.968 0.192 139.992 ;
    END
  END n_a[408]
  PIN n_a[409]
    DIRECTION INPUT ;
    USE SIGNAL ;
    PORT
      LAYER M4 ;
        RECT 0.000 140.160 0.192 140.184 ;
    END
  END n_a[409]
  PIN n_a[410]
    DIRECTION INPUT ;
    USE SIGNAL ;
    PORT
      LAYER M4 ;
        RECT 0.000 140.352 0.192 140.376 ;
    END
  END n_a[410]
  PIN n_a[411]
    DIRECTION INPUT ;
    USE SIGNAL ;
    PORT
      LAYER M4 ;
        RECT 0.000 140.544 0.192 140.568 ;
    END
  END n_a[411]
  PIN n_a[412]
    DIRECTION INPUT ;
    USE SIGNAL ;
    PORT
      LAYER M4 ;
        RECT 0.000 140.736 0.192 140.760 ;
    END
  END n_a[412]
  PIN n_a[413]
    DIRECTION INPUT ;
    USE SIGNAL ;
    PORT
      LAYER M4 ;
        RECT 0.000 140.928 0.192 140.952 ;
    END
  END n_a[413]
  PIN n_a[414]
    DIRECTION INPUT ;
    USE SIGNAL ;
    PORT
      LAYER M4 ;
        RECT 0.000 141.120 0.192 141.144 ;
    END
  END n_a[414]
  PIN n_a[415]
    DIRECTION INPUT ;
    USE SIGNAL ;
    PORT
      LAYER M4 ;
        RECT 0.000 141.312 0.192 141.336 ;
    END
  END n_a[415]
  PIN n_a[416]
    DIRECTION INPUT ;
    USE SIGNAL ;
    PORT
      LAYER M4 ;
        RECT 0.000 141.504 0.192 141.528 ;
    END
  END n_a[416]
  PIN n_a[417]
    DIRECTION INPUT ;
    USE SIGNAL ;
    PORT
      LAYER M4 ;
        RECT 0.000 141.696 0.192 141.720 ;
    END
  END n_a[417]
  PIN n_a[418]
    DIRECTION INPUT ;
    USE SIGNAL ;
    PORT
      LAYER M4 ;
        RECT 0.000 141.888 0.192 141.912 ;
    END
  END n_a[418]
  PIN n_a[419]
    DIRECTION INPUT ;
    USE SIGNAL ;
    PORT
      LAYER M4 ;
        RECT 0.000 142.080 0.192 142.104 ;
    END
  END n_a[419]
  PIN n_a[420]
    DIRECTION INPUT ;
    USE SIGNAL ;
    PORT
      LAYER M4 ;
        RECT 0.000 142.272 0.192 142.296 ;
    END
  END n_a[420]
  PIN n_a[421]
    DIRECTION INPUT ;
    USE SIGNAL ;
    PORT
      LAYER M4 ;
        RECT 0.000 142.464 0.192 142.488 ;
    END
  END n_a[421]
  PIN n_a[422]
    DIRECTION INPUT ;
    USE SIGNAL ;
    PORT
      LAYER M4 ;
        RECT 0.000 142.656 0.192 142.680 ;
    END
  END n_a[422]
  PIN n_a[423]
    DIRECTION INPUT ;
    USE SIGNAL ;
    PORT
      LAYER M4 ;
        RECT 0.000 142.848 0.192 142.872 ;
    END
  END n_a[423]
  PIN n_a[424]
    DIRECTION INPUT ;
    USE SIGNAL ;
    PORT
      LAYER M4 ;
        RECT 0.000 143.040 0.192 143.064 ;
    END
  END n_a[424]
  PIN n_a[425]
    DIRECTION INPUT ;
    USE SIGNAL ;
    PORT
      LAYER M4 ;
        RECT 0.000 143.232 0.192 143.256 ;
    END
  END n_a[425]
  PIN n_a[426]
    DIRECTION INPUT ;
    USE SIGNAL ;
    PORT
      LAYER M4 ;
        RECT 0.000 143.424 0.192 143.448 ;
    END
  END n_a[426]
  PIN n_a[427]
    DIRECTION INPUT ;
    USE SIGNAL ;
    PORT
      LAYER M4 ;
        RECT 0.000 143.616 0.192 143.640 ;
    END
  END n_a[427]
  PIN n_a[428]
    DIRECTION INPUT ;
    USE SIGNAL ;
    PORT
      LAYER M4 ;
        RECT 0.000 143.808 0.192 143.832 ;
    END
  END n_a[428]
  PIN n_a[429]
    DIRECTION INPUT ;
    USE SIGNAL ;
    PORT
      LAYER M4 ;
        RECT 0.000 144.000 0.192 144.024 ;
    END
  END n_a[429]
  PIN n_a[430]
    DIRECTION INPUT ;
    USE SIGNAL ;
    PORT
      LAYER M4 ;
        RECT 0.000 144.192 0.192 144.216 ;
    END
  END n_a[430]
  PIN n_a[431]
    DIRECTION INPUT ;
    USE SIGNAL ;
    PORT
      LAYER M4 ;
        RECT 0.000 144.384 0.192 144.408 ;
    END
  END n_a[431]
  PIN n_a[432]
    DIRECTION INPUT ;
    USE SIGNAL ;
    PORT
      LAYER M4 ;
        RECT 0.000 144.576 0.192 144.600 ;
    END
  END n_a[432]
  PIN n_a[433]
    DIRECTION INPUT ;
    USE SIGNAL ;
    PORT
      LAYER M4 ;
        RECT 0.000 144.768 0.192 144.792 ;
    END
  END n_a[433]
  PIN n_a[434]
    DIRECTION INPUT ;
    USE SIGNAL ;
    PORT
      LAYER M4 ;
        RECT 0.000 144.960 0.192 144.984 ;
    END
  END n_a[434]
  PIN n_a[435]
    DIRECTION INPUT ;
    USE SIGNAL ;
    PORT
      LAYER M4 ;
        RECT 0.000 145.152 0.192 145.176 ;
    END
  END n_a[435]
  PIN n_a[436]
    DIRECTION INPUT ;
    USE SIGNAL ;
    PORT
      LAYER M4 ;
        RECT 0.000 145.344 0.192 145.368 ;
    END
  END n_a[436]
  PIN n_a[437]
    DIRECTION INPUT ;
    USE SIGNAL ;
    PORT
      LAYER M4 ;
        RECT 0.000 145.536 0.192 145.560 ;
    END
  END n_a[437]
  PIN n_a[438]
    DIRECTION INPUT ;
    USE SIGNAL ;
    PORT
      LAYER M4 ;
        RECT 0.000 145.728 0.192 145.752 ;
    END
  END n_a[438]
  PIN n_a[439]
    DIRECTION INPUT ;
    USE SIGNAL ;
    PORT
      LAYER M4 ;
        RECT 0.000 145.920 0.192 145.944 ;
    END
  END n_a[439]
  PIN n_a[440]
    DIRECTION INPUT ;
    USE SIGNAL ;
    PORT
      LAYER M4 ;
        RECT 0.000 146.112 0.192 146.136 ;
    END
  END n_a[440]
  PIN n_a[441]
    DIRECTION INPUT ;
    USE SIGNAL ;
    PORT
      LAYER M4 ;
        RECT 0.000 146.304 0.192 146.328 ;
    END
  END n_a[441]
  PIN n_a[442]
    DIRECTION INPUT ;
    USE SIGNAL ;
    PORT
      LAYER M4 ;
        RECT 0.000 146.496 0.192 146.520 ;
    END
  END n_a[442]
  PIN n_a[443]
    DIRECTION INPUT ;
    USE SIGNAL ;
    PORT
      LAYER M4 ;
        RECT 0.000 146.688 0.192 146.712 ;
    END
  END n_a[443]
  PIN n_a[444]
    DIRECTION INPUT ;
    USE SIGNAL ;
    PORT
      LAYER M4 ;
        RECT 0.000 146.880 0.192 146.904 ;
    END
  END n_a[444]
  PIN n_a[445]
    DIRECTION INPUT ;
    USE SIGNAL ;
    PORT
      LAYER M4 ;
        RECT 0.000 147.072 0.192 147.096 ;
    END
  END n_a[445]
  PIN n_a[446]
    DIRECTION INPUT ;
    USE SIGNAL ;
    PORT
      LAYER M4 ;
        RECT 0.000 147.264 0.192 147.288 ;
    END
  END n_a[446]
  PIN n_a[447]
    DIRECTION INPUT ;
    USE SIGNAL ;
    PORT
      LAYER M4 ;
        RECT 0.000 147.456 0.192 147.480 ;
    END
  END n_a[447]
  PIN n_a[448]
    DIRECTION INPUT ;
    USE SIGNAL ;
    PORT
      LAYER M4 ;
        RECT 0.000 147.648 0.192 147.672 ;
    END
  END n_a[448]
  PIN n_a[449]
    DIRECTION INPUT ;
    USE SIGNAL ;
    PORT
      LAYER M4 ;
        RECT 0.000 147.840 0.192 147.864 ;
    END
  END n_a[449]
  PIN n_a[450]
    DIRECTION INPUT ;
    USE SIGNAL ;
    PORT
      LAYER M4 ;
        RECT 0.000 148.032 0.192 148.056 ;
    END
  END n_a[450]
  PIN n_a[451]
    DIRECTION INPUT ;
    USE SIGNAL ;
    PORT
      LAYER M4 ;
        RECT 0.000 148.224 0.192 148.248 ;
    END
  END n_a[451]
  PIN n_a[452]
    DIRECTION INPUT ;
    USE SIGNAL ;
    PORT
      LAYER M4 ;
        RECT 0.000 148.416 0.192 148.440 ;
    END
  END n_a[452]
  PIN n_a[453]
    DIRECTION INPUT ;
    USE SIGNAL ;
    PORT
      LAYER M4 ;
        RECT 0.000 148.608 0.192 148.632 ;
    END
  END n_a[453]
  PIN n_a[454]
    DIRECTION INPUT ;
    USE SIGNAL ;
    PORT
      LAYER M4 ;
        RECT 0.000 148.800 0.192 148.824 ;
    END
  END n_a[454]
  PIN n_a[455]
    DIRECTION INPUT ;
    USE SIGNAL ;
    PORT
      LAYER M4 ;
        RECT 0.000 148.992 0.192 149.016 ;
    END
  END n_a[455]
  PIN n_a[456]
    DIRECTION INPUT ;
    USE SIGNAL ;
    PORT
      LAYER M4 ;
        RECT 0.000 149.184 0.192 149.208 ;
    END
  END n_a[456]
  PIN n_a[457]
    DIRECTION INPUT ;
    USE SIGNAL ;
    PORT
      LAYER M4 ;
        RECT 0.000 149.376 0.192 149.400 ;
    END
  END n_a[457]
  PIN n_a[458]
    DIRECTION INPUT ;
    USE SIGNAL ;
    PORT
      LAYER M4 ;
        RECT 0.000 149.568 0.192 149.592 ;
    END
  END n_a[458]
  PIN n_a[459]
    DIRECTION INPUT ;
    USE SIGNAL ;
    PORT
      LAYER M4 ;
        RECT 0.000 149.760 0.192 149.784 ;
    END
  END n_a[459]
  PIN n_a[460]
    DIRECTION INPUT ;
    USE SIGNAL ;
    PORT
      LAYER M4 ;
        RECT 0.000 149.952 0.192 149.976 ;
    END
  END n_a[460]
  PIN n_a[461]
    DIRECTION INPUT ;
    USE SIGNAL ;
    PORT
      LAYER M4 ;
        RECT 0.000 150.144 0.192 150.168 ;
    END
  END n_a[461]
  PIN n_a[462]
    DIRECTION INPUT ;
    USE SIGNAL ;
    PORT
      LAYER M4 ;
        RECT 0.000 150.336 0.192 150.360 ;
    END
  END n_a[462]
  PIN n_a[463]
    DIRECTION INPUT ;
    USE SIGNAL ;
    PORT
      LAYER M4 ;
        RECT 0.000 150.528 0.192 150.552 ;
    END
  END n_a[463]
  PIN n_a[464]
    DIRECTION INPUT ;
    USE SIGNAL ;
    PORT
      LAYER M4 ;
        RECT 0.000 150.720 0.192 150.744 ;
    END
  END n_a[464]
  PIN n_a[465]
    DIRECTION INPUT ;
    USE SIGNAL ;
    PORT
      LAYER M4 ;
        RECT 0.000 150.912 0.192 150.936 ;
    END
  END n_a[465]
  PIN n_a[466]
    DIRECTION INPUT ;
    USE SIGNAL ;
    PORT
      LAYER M4 ;
        RECT 0.000 151.104 0.192 151.128 ;
    END
  END n_a[466]
  PIN n_a[467]
    DIRECTION INPUT ;
    USE SIGNAL ;
    PORT
      LAYER M4 ;
        RECT 0.000 151.296 0.192 151.320 ;
    END
  END n_a[467]
  PIN n_a[468]
    DIRECTION INPUT ;
    USE SIGNAL ;
    PORT
      LAYER M4 ;
        RECT 0.000 151.488 0.192 151.512 ;
    END
  END n_a[468]
  PIN n_a[469]
    DIRECTION INPUT ;
    USE SIGNAL ;
    PORT
      LAYER M4 ;
        RECT 0.000 151.680 0.192 151.704 ;
    END
  END n_a[469]
  PIN n_a[470]
    DIRECTION INPUT ;
    USE SIGNAL ;
    PORT
      LAYER M4 ;
        RECT 0.000 151.872 0.192 151.896 ;
    END
  END n_a[470]
  PIN n_a[471]
    DIRECTION INPUT ;
    USE SIGNAL ;
    PORT
      LAYER M4 ;
        RECT 0.000 152.064 0.192 152.088 ;
    END
  END n_a[471]
  PIN n_a[472]
    DIRECTION INPUT ;
    USE SIGNAL ;
    PORT
      LAYER M4 ;
        RECT 0.000 152.256 0.192 152.280 ;
    END
  END n_a[472]
  PIN n_a[473]
    DIRECTION INPUT ;
    USE SIGNAL ;
    PORT
      LAYER M4 ;
        RECT 0.000 152.448 0.192 152.472 ;
    END
  END n_a[473]
  PIN n_a[474]
    DIRECTION INPUT ;
    USE SIGNAL ;
    PORT
      LAYER M4 ;
        RECT 0.000 152.640 0.192 152.664 ;
    END
  END n_a[474]
  PIN n_a[475]
    DIRECTION INPUT ;
    USE SIGNAL ;
    PORT
      LAYER M4 ;
        RECT 0.000 152.832 0.192 152.856 ;
    END
  END n_a[475]
  PIN n_a[476]
    DIRECTION INPUT ;
    USE SIGNAL ;
    PORT
      LAYER M4 ;
        RECT 0.000 153.024 0.192 153.048 ;
    END
  END n_a[476]
  PIN n_a[477]
    DIRECTION INPUT ;
    USE SIGNAL ;
    PORT
      LAYER M4 ;
        RECT 0.000 153.216 0.192 153.240 ;
    END
  END n_a[477]
  PIN n_a[478]
    DIRECTION INPUT ;
    USE SIGNAL ;
    PORT
      LAYER M4 ;
        RECT 0.000 153.408 0.192 153.432 ;
    END
  END n_a[478]
  PIN n_a[479]
    DIRECTION INPUT ;
    USE SIGNAL ;
    PORT
      LAYER M4 ;
        RECT 0.000 153.600 0.192 153.624 ;
    END
  END n_a[479]
  PIN n_a[480]
    DIRECTION INPUT ;
    USE SIGNAL ;
    PORT
      LAYER M4 ;
        RECT 0.000 153.792 0.192 153.816 ;
    END
  END n_a[480]
  PIN n_a[481]
    DIRECTION INPUT ;
    USE SIGNAL ;
    PORT
      LAYER M4 ;
        RECT 0.000 153.984 0.192 154.008 ;
    END
  END n_a[481]
  PIN n_a[482]
    DIRECTION INPUT ;
    USE SIGNAL ;
    PORT
      LAYER M4 ;
        RECT 0.000 154.176 0.192 154.200 ;
    END
  END n_a[482]
  PIN n_a[483]
    DIRECTION INPUT ;
    USE SIGNAL ;
    PORT
      LAYER M4 ;
        RECT 0.000 154.368 0.192 154.392 ;
    END
  END n_a[483]
  PIN n_a[484]
    DIRECTION INPUT ;
    USE SIGNAL ;
    PORT
      LAYER M4 ;
        RECT 0.000 154.560 0.192 154.584 ;
    END
  END n_a[484]
  PIN n_a[485]
    DIRECTION INPUT ;
    USE SIGNAL ;
    PORT
      LAYER M4 ;
        RECT 0.000 154.752 0.192 154.776 ;
    END
  END n_a[485]
  PIN n_a[486]
    DIRECTION INPUT ;
    USE SIGNAL ;
    PORT
      LAYER M4 ;
        RECT 0.000 154.944 0.192 154.968 ;
    END
  END n_a[486]
  PIN n_a[487]
    DIRECTION INPUT ;
    USE SIGNAL ;
    PORT
      LAYER M4 ;
        RECT 0.000 155.136 0.192 155.160 ;
    END
  END n_a[487]
  PIN n_a[488]
    DIRECTION INPUT ;
    USE SIGNAL ;
    PORT
      LAYER M4 ;
        RECT 0.000 155.328 0.192 155.352 ;
    END
  END n_a[488]
  PIN n_a[489]
    DIRECTION INPUT ;
    USE SIGNAL ;
    PORT
      LAYER M4 ;
        RECT 0.000 155.520 0.192 155.544 ;
    END
  END n_a[489]
  PIN n_a[490]
    DIRECTION INPUT ;
    USE SIGNAL ;
    PORT
      LAYER M4 ;
        RECT 0.000 155.712 0.192 155.736 ;
    END
  END n_a[490]
  PIN n_a[491]
    DIRECTION INPUT ;
    USE SIGNAL ;
    PORT
      LAYER M4 ;
        RECT 0.000 155.904 0.192 155.928 ;
    END
  END n_a[491]
  PIN n_a[492]
    DIRECTION INPUT ;
    USE SIGNAL ;
    PORT
      LAYER M4 ;
        RECT 0.000 156.096 0.192 156.120 ;
    END
  END n_a[492]
  PIN n_a[493]
    DIRECTION INPUT ;
    USE SIGNAL ;
    PORT
      LAYER M4 ;
        RECT 0.000 156.288 0.192 156.312 ;
    END
  END n_a[493]
  PIN n_a[494]
    DIRECTION INPUT ;
    USE SIGNAL ;
    PORT
      LAYER M4 ;
        RECT 0.000 156.480 0.192 156.504 ;
    END
  END n_a[494]
  PIN n_a[495]
    DIRECTION INPUT ;
    USE SIGNAL ;
    PORT
      LAYER M4 ;
        RECT 0.000 156.672 0.192 156.696 ;
    END
  END n_a[495]
  PIN n_a[496]
    DIRECTION INPUT ;
    USE SIGNAL ;
    PORT
      LAYER M4 ;
        RECT 0.000 156.864 0.192 156.888 ;
    END
  END n_a[496]
  PIN n_a[497]
    DIRECTION INPUT ;
    USE SIGNAL ;
    PORT
      LAYER M4 ;
        RECT 0.000 157.056 0.192 157.080 ;
    END
  END n_a[497]
  PIN n_a[498]
    DIRECTION INPUT ;
    USE SIGNAL ;
    PORT
      LAYER M4 ;
        RECT 0.000 157.248 0.192 157.272 ;
    END
  END n_a[498]
  PIN n_a[499]
    DIRECTION INPUT ;
    USE SIGNAL ;
    PORT
      LAYER M4 ;
        RECT 0.000 157.440 0.192 157.464 ;
    END
  END n_a[499]
  PIN n_a[500]
    DIRECTION INPUT ;
    USE SIGNAL ;
    PORT
      LAYER M4 ;
        RECT 0.000 157.632 0.192 157.656 ;
    END
  END n_a[500]
  PIN n_a[501]
    DIRECTION INPUT ;
    USE SIGNAL ;
    PORT
      LAYER M4 ;
        RECT 0.000 157.824 0.192 157.848 ;
    END
  END n_a[501]
  PIN n_a[502]
    DIRECTION INPUT ;
    USE SIGNAL ;
    PORT
      LAYER M4 ;
        RECT 0.000 158.016 0.192 158.040 ;
    END
  END n_a[502]
  PIN n_a[503]
    DIRECTION INPUT ;
    USE SIGNAL ;
    PORT
      LAYER M4 ;
        RECT 0.000 158.208 0.192 158.232 ;
    END
  END n_a[503]
  PIN n_a[504]
    DIRECTION INPUT ;
    USE SIGNAL ;
    PORT
      LAYER M4 ;
        RECT 0.000 158.400 0.192 158.424 ;
    END
  END n_a[504]
  PIN n_a[505]
    DIRECTION INPUT ;
    USE SIGNAL ;
    PORT
      LAYER M4 ;
        RECT 0.000 158.592 0.192 158.616 ;
    END
  END n_a[505]
  PIN n_a[506]
    DIRECTION INPUT ;
    USE SIGNAL ;
    PORT
      LAYER M4 ;
        RECT 0.000 158.784 0.192 158.808 ;
    END
  END n_a[506]
  PIN n_a[507]
    DIRECTION INPUT ;
    USE SIGNAL ;
    PORT
      LAYER M4 ;
        RECT 0.000 158.976 0.192 159.000 ;
    END
  END n_a[507]
  PIN n_a[508]
    DIRECTION INPUT ;
    USE SIGNAL ;
    PORT
      LAYER M4 ;
        RECT 0.000 159.168 0.192 159.192 ;
    END
  END n_a[508]
  PIN n_a[509]
    DIRECTION INPUT ;
    USE SIGNAL ;
    PORT
      LAYER M4 ;
        RECT 0.000 159.360 0.192 159.384 ;
    END
  END n_a[509]
  PIN n_a[510]
    DIRECTION INPUT ;
    USE SIGNAL ;
    PORT
      LAYER M4 ;
        RECT 0.000 159.552 0.192 159.576 ;
    END
  END n_a[510]
  PIN n_a[511]
    DIRECTION INPUT ;
    USE SIGNAL ;
    PORT
      LAYER M4 ;
        RECT 0.000 159.744 0.192 159.768 ;
    END
  END n_a[511]
  PIN n_a[512]
    DIRECTION INPUT ;
    USE SIGNAL ;
    PORT
      LAYER M4 ;
        RECT 0.000 159.936 0.192 159.960 ;
    END
  END n_a[512]
  PIN n_a[513]
    DIRECTION INPUT ;
    USE SIGNAL ;
    PORT
      LAYER M4 ;
        RECT 0.000 160.128 0.192 160.152 ;
    END
  END n_a[513]
  PIN n_b[0]
    DIRECTION INPUT ;
    USE SIGNAL ;
    PORT
      LAYER M4 ;
        RECT 0.000 162.240 0.192 162.264 ;
    END
  END n_b[0]
  PIN n_b[1]
    DIRECTION INPUT ;
    USE SIGNAL ;
    PORT
      LAYER M4 ;
        RECT 0.000 162.432 0.192 162.456 ;
    END
  END n_b[1]
  PIN n_b[2]
    DIRECTION INPUT ;
    USE SIGNAL ;
    PORT
      LAYER M4 ;
        RECT 0.000 162.624 0.192 162.648 ;
    END
  END n_b[2]
  PIN n_b[3]
    DIRECTION INPUT ;
    USE SIGNAL ;
    PORT
      LAYER M4 ;
        RECT 0.000 162.816 0.192 162.840 ;
    END
  END n_b[3]
  PIN n_b[4]
    DIRECTION INPUT ;
    USE SIGNAL ;
    PORT
      LAYER M4 ;
        RECT 0.000 163.008 0.192 163.032 ;
    END
  END n_b[4]
  PIN n_b[5]
    DIRECTION INPUT ;
    USE SIGNAL ;
    PORT
      LAYER M4 ;
        RECT 0.000 163.200 0.192 163.224 ;
    END
  END n_b[5]
  PIN n_b[6]
    DIRECTION INPUT ;
    USE SIGNAL ;
    PORT
      LAYER M4 ;
        RECT 0.000 163.392 0.192 163.416 ;
    END
  END n_b[6]
  PIN n_b[7]
    DIRECTION INPUT ;
    USE SIGNAL ;
    PORT
      LAYER M4 ;
        RECT 0.000 163.584 0.192 163.608 ;
    END
  END n_b[7]
  PIN n_b[8]
    DIRECTION INPUT ;
    USE SIGNAL ;
    PORT
      LAYER M4 ;
        RECT 0.000 163.776 0.192 163.800 ;
    END
  END n_b[8]
  PIN n_b[9]
    DIRECTION INPUT ;
    USE SIGNAL ;
    PORT
      LAYER M4 ;
        RECT 0.000 163.968 0.192 163.992 ;
    END
  END n_b[9]
  PIN n_b[10]
    DIRECTION INPUT ;
    USE SIGNAL ;
    PORT
      LAYER M4 ;
        RECT 0.000 164.160 0.192 164.184 ;
    END
  END n_b[10]
  PIN n_b[11]
    DIRECTION INPUT ;
    USE SIGNAL ;
    PORT
      LAYER M4 ;
        RECT 0.000 164.352 0.192 164.376 ;
    END
  END n_b[11]
  PIN n_b[12]
    DIRECTION INPUT ;
    USE SIGNAL ;
    PORT
      LAYER M4 ;
        RECT 0.000 164.544 0.192 164.568 ;
    END
  END n_b[12]
  PIN n_b[13]
    DIRECTION INPUT ;
    USE SIGNAL ;
    PORT
      LAYER M4 ;
        RECT 0.000 164.736 0.192 164.760 ;
    END
  END n_b[13]
  PIN n_b[14]
    DIRECTION INPUT ;
    USE SIGNAL ;
    PORT
      LAYER M4 ;
        RECT 0.000 164.928 0.192 164.952 ;
    END
  END n_b[14]
  PIN n_b[15]
    DIRECTION INPUT ;
    USE SIGNAL ;
    PORT
      LAYER M4 ;
        RECT 0.000 165.120 0.192 165.144 ;
    END
  END n_b[15]
  PIN n_b[16]
    DIRECTION INPUT ;
    USE SIGNAL ;
    PORT
      LAYER M4 ;
        RECT 0.000 165.312 0.192 165.336 ;
    END
  END n_b[16]
  PIN n_b[17]
    DIRECTION INPUT ;
    USE SIGNAL ;
    PORT
      LAYER M4 ;
        RECT 0.000 165.504 0.192 165.528 ;
    END
  END n_b[17]
  PIN n_b[18]
    DIRECTION INPUT ;
    USE SIGNAL ;
    PORT
      LAYER M4 ;
        RECT 0.000 165.696 0.192 165.720 ;
    END
  END n_b[18]
  PIN n_b[19]
    DIRECTION INPUT ;
    USE SIGNAL ;
    PORT
      LAYER M4 ;
        RECT 0.000 165.888 0.192 165.912 ;
    END
  END n_b[19]
  PIN n_b[20]
    DIRECTION INPUT ;
    USE SIGNAL ;
    PORT
      LAYER M4 ;
        RECT 0.000 166.080 0.192 166.104 ;
    END
  END n_b[20]
  PIN n_b[21]
    DIRECTION INPUT ;
    USE SIGNAL ;
    PORT
      LAYER M4 ;
        RECT 0.000 166.272 0.192 166.296 ;
    END
  END n_b[21]
  PIN n_b[22]
    DIRECTION INPUT ;
    USE SIGNAL ;
    PORT
      LAYER M4 ;
        RECT 0.000 166.464 0.192 166.488 ;
    END
  END n_b[22]
  PIN n_b[23]
    DIRECTION INPUT ;
    USE SIGNAL ;
    PORT
      LAYER M4 ;
        RECT 0.000 166.656 0.192 166.680 ;
    END
  END n_b[23]
  PIN n_b[24]
    DIRECTION INPUT ;
    USE SIGNAL ;
    PORT
      LAYER M4 ;
        RECT 0.000 166.848 0.192 166.872 ;
    END
  END n_b[24]
  PIN n_b[25]
    DIRECTION INPUT ;
    USE SIGNAL ;
    PORT
      LAYER M4 ;
        RECT 0.000 167.040 0.192 167.064 ;
    END
  END n_b[25]
  PIN n_b[26]
    DIRECTION INPUT ;
    USE SIGNAL ;
    PORT
      LAYER M4 ;
        RECT 0.000 167.232 0.192 167.256 ;
    END
  END n_b[26]
  PIN n_b[27]
    DIRECTION INPUT ;
    USE SIGNAL ;
    PORT
      LAYER M4 ;
        RECT 0.000 167.424 0.192 167.448 ;
    END
  END n_b[27]
  PIN n_b[28]
    DIRECTION INPUT ;
    USE SIGNAL ;
    PORT
      LAYER M4 ;
        RECT 0.000 167.616 0.192 167.640 ;
    END
  END n_b[28]
  PIN n_b[29]
    DIRECTION INPUT ;
    USE SIGNAL ;
    PORT
      LAYER M4 ;
        RECT 0.000 167.808 0.192 167.832 ;
    END
  END n_b[29]
  PIN n_b[30]
    DIRECTION INPUT ;
    USE SIGNAL ;
    PORT
      LAYER M4 ;
        RECT 0.000 168.000 0.192 168.024 ;
    END
  END n_b[30]
  PIN n_b[31]
    DIRECTION INPUT ;
    USE SIGNAL ;
    PORT
      LAYER M4 ;
        RECT 0.000 168.192 0.192 168.216 ;
    END
  END n_b[31]
  PIN n_b[32]
    DIRECTION INPUT ;
    USE SIGNAL ;
    PORT
      LAYER M4 ;
        RECT 0.000 168.384 0.192 168.408 ;
    END
  END n_b[32]
  PIN n_b[33]
    DIRECTION INPUT ;
    USE SIGNAL ;
    PORT
      LAYER M4 ;
        RECT 0.000 168.576 0.192 168.600 ;
    END
  END n_b[33]
  PIN n_b[34]
    DIRECTION INPUT ;
    USE SIGNAL ;
    PORT
      LAYER M4 ;
        RECT 0.000 168.768 0.192 168.792 ;
    END
  END n_b[34]
  PIN n_b[35]
    DIRECTION INPUT ;
    USE SIGNAL ;
    PORT
      LAYER M4 ;
        RECT 0.000 168.960 0.192 168.984 ;
    END
  END n_b[35]
  PIN n_b[36]
    DIRECTION INPUT ;
    USE SIGNAL ;
    PORT
      LAYER M4 ;
        RECT 0.000 169.152 0.192 169.176 ;
    END
  END n_b[36]
  PIN n_b[37]
    DIRECTION INPUT ;
    USE SIGNAL ;
    PORT
      LAYER M4 ;
        RECT 0.000 169.344 0.192 169.368 ;
    END
  END n_b[37]
  PIN n_b[38]
    DIRECTION INPUT ;
    USE SIGNAL ;
    PORT
      LAYER M4 ;
        RECT 0.000 169.536 0.192 169.560 ;
    END
  END n_b[38]
  PIN n_b[39]
    DIRECTION INPUT ;
    USE SIGNAL ;
    PORT
      LAYER M4 ;
        RECT 0.000 169.728 0.192 169.752 ;
    END
  END n_b[39]
  PIN n_b[40]
    DIRECTION INPUT ;
    USE SIGNAL ;
    PORT
      LAYER M4 ;
        RECT 0.000 169.920 0.192 169.944 ;
    END
  END n_b[40]
  PIN n_b[41]
    DIRECTION INPUT ;
    USE SIGNAL ;
    PORT
      LAYER M4 ;
        RECT 0.000 170.112 0.192 170.136 ;
    END
  END n_b[41]
  PIN n_b[42]
    DIRECTION INPUT ;
    USE SIGNAL ;
    PORT
      LAYER M4 ;
        RECT 0.000 170.304 0.192 170.328 ;
    END
  END n_b[42]
  PIN n_b[43]
    DIRECTION INPUT ;
    USE SIGNAL ;
    PORT
      LAYER M4 ;
        RECT 0.000 170.496 0.192 170.520 ;
    END
  END n_b[43]
  PIN n_b[44]
    DIRECTION INPUT ;
    USE SIGNAL ;
    PORT
      LAYER M4 ;
        RECT 0.000 170.688 0.192 170.712 ;
    END
  END n_b[44]
  PIN n_b[45]
    DIRECTION INPUT ;
    USE SIGNAL ;
    PORT
      LAYER M4 ;
        RECT 0.000 170.880 0.192 170.904 ;
    END
  END n_b[45]
  PIN n_b[46]
    DIRECTION INPUT ;
    USE SIGNAL ;
    PORT
      LAYER M4 ;
        RECT 0.000 171.072 0.192 171.096 ;
    END
  END n_b[46]
  PIN n_b[47]
    DIRECTION INPUT ;
    USE SIGNAL ;
    PORT
      LAYER M4 ;
        RECT 0.000 171.264 0.192 171.288 ;
    END
  END n_b[47]
  PIN n_b[48]
    DIRECTION INPUT ;
    USE SIGNAL ;
    PORT
      LAYER M4 ;
        RECT 0.000 171.456 0.192 171.480 ;
    END
  END n_b[48]
  PIN n_b[49]
    DIRECTION INPUT ;
    USE SIGNAL ;
    PORT
      LAYER M4 ;
        RECT 0.000 171.648 0.192 171.672 ;
    END
  END n_b[49]
  PIN n_b[50]
    DIRECTION INPUT ;
    USE SIGNAL ;
    PORT
      LAYER M4 ;
        RECT 0.000 171.840 0.192 171.864 ;
    END
  END n_b[50]
  PIN n_b[51]
    DIRECTION INPUT ;
    USE SIGNAL ;
    PORT
      LAYER M4 ;
        RECT 0.000 172.032 0.192 172.056 ;
    END
  END n_b[51]
  PIN n_b[52]
    DIRECTION INPUT ;
    USE SIGNAL ;
    PORT
      LAYER M4 ;
        RECT 0.000 172.224 0.192 172.248 ;
    END
  END n_b[52]
  PIN n_b[53]
    DIRECTION INPUT ;
    USE SIGNAL ;
    PORT
      LAYER M4 ;
        RECT 0.000 172.416 0.192 172.440 ;
    END
  END n_b[53]
  PIN n_b[54]
    DIRECTION INPUT ;
    USE SIGNAL ;
    PORT
      LAYER M4 ;
        RECT 0.000 172.608 0.192 172.632 ;
    END
  END n_b[54]
  PIN n_b[55]
    DIRECTION INPUT ;
    USE SIGNAL ;
    PORT
      LAYER M4 ;
        RECT 0.000 172.800 0.192 172.824 ;
    END
  END n_b[55]
  PIN n_b[56]
    DIRECTION INPUT ;
    USE SIGNAL ;
    PORT
      LAYER M4 ;
        RECT 0.000 172.992 0.192 173.016 ;
    END
  END n_b[56]
  PIN n_b[57]
    DIRECTION INPUT ;
    USE SIGNAL ;
    PORT
      LAYER M4 ;
        RECT 0.000 173.184 0.192 173.208 ;
    END
  END n_b[57]
  PIN n_b[58]
    DIRECTION INPUT ;
    USE SIGNAL ;
    PORT
      LAYER M4 ;
        RECT 0.000 173.376 0.192 173.400 ;
    END
  END n_b[58]
  PIN n_b[59]
    DIRECTION INPUT ;
    USE SIGNAL ;
    PORT
      LAYER M4 ;
        RECT 0.000 173.568 0.192 173.592 ;
    END
  END n_b[59]
  PIN n_b[60]
    DIRECTION INPUT ;
    USE SIGNAL ;
    PORT
      LAYER M4 ;
        RECT 0.000 173.760 0.192 173.784 ;
    END
  END n_b[60]
  PIN n_b[61]
    DIRECTION INPUT ;
    USE SIGNAL ;
    PORT
      LAYER M4 ;
        RECT 0.000 173.952 0.192 173.976 ;
    END
  END n_b[61]
  PIN n_b[62]
    DIRECTION INPUT ;
    USE SIGNAL ;
    PORT
      LAYER M4 ;
        RECT 0.000 174.144 0.192 174.168 ;
    END
  END n_b[62]
  PIN n_b[63]
    DIRECTION INPUT ;
    USE SIGNAL ;
    PORT
      LAYER M4 ;
        RECT 0.000 174.336 0.192 174.360 ;
    END
  END n_b[63]
  PIN n_b[64]
    DIRECTION INPUT ;
    USE SIGNAL ;
    PORT
      LAYER M4 ;
        RECT 0.000 174.528 0.192 174.552 ;
    END
  END n_b[64]
  PIN n_b[65]
    DIRECTION INPUT ;
    USE SIGNAL ;
    PORT
      LAYER M4 ;
        RECT 0.000 174.720 0.192 174.744 ;
    END
  END n_b[65]
  PIN n_b[66]
    DIRECTION INPUT ;
    USE SIGNAL ;
    PORT
      LAYER M4 ;
        RECT 0.000 174.912 0.192 174.936 ;
    END
  END n_b[66]
  PIN n_b[67]
    DIRECTION INPUT ;
    USE SIGNAL ;
    PORT
      LAYER M4 ;
        RECT 0.000 175.104 0.192 175.128 ;
    END
  END n_b[67]
  PIN n_b[68]
    DIRECTION INPUT ;
    USE SIGNAL ;
    PORT
      LAYER M4 ;
        RECT 0.000 175.296 0.192 175.320 ;
    END
  END n_b[68]
  PIN n_b[69]
    DIRECTION INPUT ;
    USE SIGNAL ;
    PORT
      LAYER M4 ;
        RECT 0.000 175.488 0.192 175.512 ;
    END
  END n_b[69]
  PIN n_b[70]
    DIRECTION INPUT ;
    USE SIGNAL ;
    PORT
      LAYER M4 ;
        RECT 0.000 175.680 0.192 175.704 ;
    END
  END n_b[70]
  PIN n_b[71]
    DIRECTION INPUT ;
    USE SIGNAL ;
    PORT
      LAYER M4 ;
        RECT 0.000 175.872 0.192 175.896 ;
    END
  END n_b[71]
  PIN n_b[72]
    DIRECTION INPUT ;
    USE SIGNAL ;
    PORT
      LAYER M4 ;
        RECT 0.000 176.064 0.192 176.088 ;
    END
  END n_b[72]
  PIN n_b[73]
    DIRECTION INPUT ;
    USE SIGNAL ;
    PORT
      LAYER M4 ;
        RECT 0.000 176.256 0.192 176.280 ;
    END
  END n_b[73]
  PIN n_b[74]
    DIRECTION INPUT ;
    USE SIGNAL ;
    PORT
      LAYER M4 ;
        RECT 0.000 176.448 0.192 176.472 ;
    END
  END n_b[74]
  PIN n_b[75]
    DIRECTION INPUT ;
    USE SIGNAL ;
    PORT
      LAYER M4 ;
        RECT 0.000 176.640 0.192 176.664 ;
    END
  END n_b[75]
  PIN n_b[76]
    DIRECTION INPUT ;
    USE SIGNAL ;
    PORT
      LAYER M4 ;
        RECT 0.000 176.832 0.192 176.856 ;
    END
  END n_b[76]
  PIN n_b[77]
    DIRECTION INPUT ;
    USE SIGNAL ;
    PORT
      LAYER M4 ;
        RECT 0.000 177.024 0.192 177.048 ;
    END
  END n_b[77]
  PIN n_b[78]
    DIRECTION INPUT ;
    USE SIGNAL ;
    PORT
      LAYER M4 ;
        RECT 0.000 177.216 0.192 177.240 ;
    END
  END n_b[78]
  PIN n_b[79]
    DIRECTION INPUT ;
    USE SIGNAL ;
    PORT
      LAYER M4 ;
        RECT 0.000 177.408 0.192 177.432 ;
    END
  END n_b[79]
  PIN n_b[80]
    DIRECTION INPUT ;
    USE SIGNAL ;
    PORT
      LAYER M4 ;
        RECT 0.000 177.600 0.192 177.624 ;
    END
  END n_b[80]
  PIN n_b[81]
    DIRECTION INPUT ;
    USE SIGNAL ;
    PORT
      LAYER M4 ;
        RECT 0.000 177.792 0.192 177.816 ;
    END
  END n_b[81]
  PIN n_b[82]
    DIRECTION INPUT ;
    USE SIGNAL ;
    PORT
      LAYER M4 ;
        RECT 0.000 177.984 0.192 178.008 ;
    END
  END n_b[82]
  PIN n_b[83]
    DIRECTION INPUT ;
    USE SIGNAL ;
    PORT
      LAYER M4 ;
        RECT 0.000 178.176 0.192 178.200 ;
    END
  END n_b[83]
  PIN n_b[84]
    DIRECTION INPUT ;
    USE SIGNAL ;
    PORT
      LAYER M4 ;
        RECT 0.000 178.368 0.192 178.392 ;
    END
  END n_b[84]
  PIN n_b[85]
    DIRECTION INPUT ;
    USE SIGNAL ;
    PORT
      LAYER M4 ;
        RECT 0.000 178.560 0.192 178.584 ;
    END
  END n_b[85]
  PIN n_b[86]
    DIRECTION INPUT ;
    USE SIGNAL ;
    PORT
      LAYER M4 ;
        RECT 0.000 178.752 0.192 178.776 ;
    END
  END n_b[86]
  PIN n_b[87]
    DIRECTION INPUT ;
    USE SIGNAL ;
    PORT
      LAYER M4 ;
        RECT 0.000 178.944 0.192 178.968 ;
    END
  END n_b[87]
  PIN n_b[88]
    DIRECTION INPUT ;
    USE SIGNAL ;
    PORT
      LAYER M4 ;
        RECT 0.000 179.136 0.192 179.160 ;
    END
  END n_b[88]
  PIN n_b[89]
    DIRECTION INPUT ;
    USE SIGNAL ;
    PORT
      LAYER M4 ;
        RECT 0.000 179.328 0.192 179.352 ;
    END
  END n_b[89]
  PIN n_b[90]
    DIRECTION INPUT ;
    USE SIGNAL ;
    PORT
      LAYER M4 ;
        RECT 0.000 179.520 0.192 179.544 ;
    END
  END n_b[90]
  PIN n_b[91]
    DIRECTION INPUT ;
    USE SIGNAL ;
    PORT
      LAYER M4 ;
        RECT 0.000 179.712 0.192 179.736 ;
    END
  END n_b[91]
  PIN n_b[92]
    DIRECTION INPUT ;
    USE SIGNAL ;
    PORT
      LAYER M4 ;
        RECT 0.000 179.904 0.192 179.928 ;
    END
  END n_b[92]
  PIN n_b[93]
    DIRECTION INPUT ;
    USE SIGNAL ;
    PORT
      LAYER M4 ;
        RECT 0.000 180.096 0.192 180.120 ;
    END
  END n_b[93]
  PIN n_b[94]
    DIRECTION INPUT ;
    USE SIGNAL ;
    PORT
      LAYER M4 ;
        RECT 0.000 180.288 0.192 180.312 ;
    END
  END n_b[94]
  PIN n_b[95]
    DIRECTION INPUT ;
    USE SIGNAL ;
    PORT
      LAYER M4 ;
        RECT 0.000 180.480 0.192 180.504 ;
    END
  END n_b[95]
  PIN n_b[96]
    DIRECTION INPUT ;
    USE SIGNAL ;
    PORT
      LAYER M4 ;
        RECT 0.000 180.672 0.192 180.696 ;
    END
  END n_b[96]
  PIN n_b[97]
    DIRECTION INPUT ;
    USE SIGNAL ;
    PORT
      LAYER M4 ;
        RECT 0.000 180.864 0.192 180.888 ;
    END
  END n_b[97]
  PIN n_b[98]
    DIRECTION INPUT ;
    USE SIGNAL ;
    PORT
      LAYER M4 ;
        RECT 0.000 181.056 0.192 181.080 ;
    END
  END n_b[98]
  PIN n_b[99]
    DIRECTION INPUT ;
    USE SIGNAL ;
    PORT
      LAYER M4 ;
        RECT 0.000 181.248 0.192 181.272 ;
    END
  END n_b[99]
  PIN n_b[100]
    DIRECTION INPUT ;
    USE SIGNAL ;
    PORT
      LAYER M4 ;
        RECT 0.000 181.440 0.192 181.464 ;
    END
  END n_b[100]
  PIN n_b[101]
    DIRECTION INPUT ;
    USE SIGNAL ;
    PORT
      LAYER M4 ;
        RECT 0.000 181.632 0.192 181.656 ;
    END
  END n_b[101]
  PIN n_b[102]
    DIRECTION INPUT ;
    USE SIGNAL ;
    PORT
      LAYER M4 ;
        RECT 0.000 181.824 0.192 181.848 ;
    END
  END n_b[102]
  PIN n_b[103]
    DIRECTION INPUT ;
    USE SIGNAL ;
    PORT
      LAYER M4 ;
        RECT 0.000 182.016 0.192 182.040 ;
    END
  END n_b[103]
  PIN n_b[104]
    DIRECTION INPUT ;
    USE SIGNAL ;
    PORT
      LAYER M4 ;
        RECT 0.000 182.208 0.192 182.232 ;
    END
  END n_b[104]
  PIN n_b[105]
    DIRECTION INPUT ;
    USE SIGNAL ;
    PORT
      LAYER M4 ;
        RECT 0.000 182.400 0.192 182.424 ;
    END
  END n_b[105]
  PIN n_b[106]
    DIRECTION INPUT ;
    USE SIGNAL ;
    PORT
      LAYER M4 ;
        RECT 0.000 182.592 0.192 182.616 ;
    END
  END n_b[106]
  PIN n_b[107]
    DIRECTION INPUT ;
    USE SIGNAL ;
    PORT
      LAYER M4 ;
        RECT 0.000 182.784 0.192 182.808 ;
    END
  END n_b[107]
  PIN n_b[108]
    DIRECTION INPUT ;
    USE SIGNAL ;
    PORT
      LAYER M4 ;
        RECT 0.000 182.976 0.192 183.000 ;
    END
  END n_b[108]
  PIN n_b[109]
    DIRECTION INPUT ;
    USE SIGNAL ;
    PORT
      LAYER M4 ;
        RECT 0.000 183.168 0.192 183.192 ;
    END
  END n_b[109]
  PIN n_b[110]
    DIRECTION INPUT ;
    USE SIGNAL ;
    PORT
      LAYER M4 ;
        RECT 0.000 183.360 0.192 183.384 ;
    END
  END n_b[110]
  PIN n_b[111]
    DIRECTION INPUT ;
    USE SIGNAL ;
    PORT
      LAYER M4 ;
        RECT 0.000 183.552 0.192 183.576 ;
    END
  END n_b[111]
  PIN n_b[112]
    DIRECTION INPUT ;
    USE SIGNAL ;
    PORT
      LAYER M4 ;
        RECT 0.000 183.744 0.192 183.768 ;
    END
  END n_b[112]
  PIN n_b[113]
    DIRECTION INPUT ;
    USE SIGNAL ;
    PORT
      LAYER M4 ;
        RECT 0.000 183.936 0.192 183.960 ;
    END
  END n_b[113]
  PIN n_b[114]
    DIRECTION INPUT ;
    USE SIGNAL ;
    PORT
      LAYER M4 ;
        RECT 0.000 184.128 0.192 184.152 ;
    END
  END n_b[114]
  PIN n_b[115]
    DIRECTION INPUT ;
    USE SIGNAL ;
    PORT
      LAYER M4 ;
        RECT 0.000 184.320 0.192 184.344 ;
    END
  END n_b[115]
  PIN n_b[116]
    DIRECTION INPUT ;
    USE SIGNAL ;
    PORT
      LAYER M4 ;
        RECT 0.000 184.512 0.192 184.536 ;
    END
  END n_b[116]
  PIN n_b[117]
    DIRECTION INPUT ;
    USE SIGNAL ;
    PORT
      LAYER M4 ;
        RECT 0.000 184.704 0.192 184.728 ;
    END
  END n_b[117]
  PIN n_b[118]
    DIRECTION INPUT ;
    USE SIGNAL ;
    PORT
      LAYER M4 ;
        RECT 0.000 184.896 0.192 184.920 ;
    END
  END n_b[118]
  PIN n_b[119]
    DIRECTION INPUT ;
    USE SIGNAL ;
    PORT
      LAYER M4 ;
        RECT 0.000 185.088 0.192 185.112 ;
    END
  END n_b[119]
  PIN n_b[120]
    DIRECTION INPUT ;
    USE SIGNAL ;
    PORT
      LAYER M4 ;
        RECT 0.000 185.280 0.192 185.304 ;
    END
  END n_b[120]
  PIN n_b[121]
    DIRECTION INPUT ;
    USE SIGNAL ;
    PORT
      LAYER M4 ;
        RECT 0.000 185.472 0.192 185.496 ;
    END
  END n_b[121]
  PIN n_b[122]
    DIRECTION INPUT ;
    USE SIGNAL ;
    PORT
      LAYER M4 ;
        RECT 0.000 185.664 0.192 185.688 ;
    END
  END n_b[122]
  PIN n_b[123]
    DIRECTION INPUT ;
    USE SIGNAL ;
    PORT
      LAYER M4 ;
        RECT 0.000 185.856 0.192 185.880 ;
    END
  END n_b[123]
  PIN n_b[124]
    DIRECTION INPUT ;
    USE SIGNAL ;
    PORT
      LAYER M4 ;
        RECT 0.000 186.048 0.192 186.072 ;
    END
  END n_b[124]
  PIN n_b[125]
    DIRECTION INPUT ;
    USE SIGNAL ;
    PORT
      LAYER M4 ;
        RECT 0.000 186.240 0.192 186.264 ;
    END
  END n_b[125]
  PIN n_b[126]
    DIRECTION INPUT ;
    USE SIGNAL ;
    PORT
      LAYER M4 ;
        RECT 0.000 186.432 0.192 186.456 ;
    END
  END n_b[126]
  PIN n_b[127]
    DIRECTION INPUT ;
    USE SIGNAL ;
    PORT
      LAYER M4 ;
        RECT 0.000 186.624 0.192 186.648 ;
    END
  END n_b[127]
  PIN n_b[128]
    DIRECTION INPUT ;
    USE SIGNAL ;
    PORT
      LAYER M4 ;
        RECT 0.000 186.816 0.192 186.840 ;
    END
  END n_b[128]
  PIN n_b[129]
    DIRECTION INPUT ;
    USE SIGNAL ;
    PORT
      LAYER M4 ;
        RECT 0.000 187.008 0.192 187.032 ;
    END
  END n_b[129]
  PIN n_b[130]
    DIRECTION INPUT ;
    USE SIGNAL ;
    PORT
      LAYER M4 ;
        RECT 0.000 187.200 0.192 187.224 ;
    END
  END n_b[130]
  PIN n_b[131]
    DIRECTION INPUT ;
    USE SIGNAL ;
    PORT
      LAYER M4 ;
        RECT 0.000 187.392 0.192 187.416 ;
    END
  END n_b[131]
  PIN n_b[132]
    DIRECTION INPUT ;
    USE SIGNAL ;
    PORT
      LAYER M4 ;
        RECT 0.000 187.584 0.192 187.608 ;
    END
  END n_b[132]
  PIN n_b[133]
    DIRECTION INPUT ;
    USE SIGNAL ;
    PORT
      LAYER M4 ;
        RECT 0.000 187.776 0.192 187.800 ;
    END
  END n_b[133]
  PIN n_b[134]
    DIRECTION INPUT ;
    USE SIGNAL ;
    PORT
      LAYER M4 ;
        RECT 0.000 187.968 0.192 187.992 ;
    END
  END n_b[134]
  PIN n_b[135]
    DIRECTION INPUT ;
    USE SIGNAL ;
    PORT
      LAYER M4 ;
        RECT 0.000 188.160 0.192 188.184 ;
    END
  END n_b[135]
  PIN n_b[136]
    DIRECTION INPUT ;
    USE SIGNAL ;
    PORT
      LAYER M4 ;
        RECT 0.000 188.352 0.192 188.376 ;
    END
  END n_b[136]
  PIN n_b[137]
    DIRECTION INPUT ;
    USE SIGNAL ;
    PORT
      LAYER M4 ;
        RECT 0.000 188.544 0.192 188.568 ;
    END
  END n_b[137]
  PIN n_b[138]
    DIRECTION INPUT ;
    USE SIGNAL ;
    PORT
      LAYER M4 ;
        RECT 0.000 188.736 0.192 188.760 ;
    END
  END n_b[138]
  PIN n_b[139]
    DIRECTION INPUT ;
    USE SIGNAL ;
    PORT
      LAYER M4 ;
        RECT 0.000 188.928 0.192 188.952 ;
    END
  END n_b[139]
  PIN n_b[140]
    DIRECTION INPUT ;
    USE SIGNAL ;
    PORT
      LAYER M4 ;
        RECT 0.000 189.120 0.192 189.144 ;
    END
  END n_b[140]
  PIN n_b[141]
    DIRECTION INPUT ;
    USE SIGNAL ;
    PORT
      LAYER M4 ;
        RECT 0.000 189.312 0.192 189.336 ;
    END
  END n_b[141]
  PIN n_b[142]
    DIRECTION INPUT ;
    USE SIGNAL ;
    PORT
      LAYER M4 ;
        RECT 0.000 189.504 0.192 189.528 ;
    END
  END n_b[142]
  PIN n_b[143]
    DIRECTION INPUT ;
    USE SIGNAL ;
    PORT
      LAYER M4 ;
        RECT 0.000 189.696 0.192 189.720 ;
    END
  END n_b[143]
  PIN n_b[144]
    DIRECTION INPUT ;
    USE SIGNAL ;
    PORT
      LAYER M4 ;
        RECT 0.000 189.888 0.192 189.912 ;
    END
  END n_b[144]
  PIN n_b[145]
    DIRECTION INPUT ;
    USE SIGNAL ;
    PORT
      LAYER M4 ;
        RECT 0.000 190.080 0.192 190.104 ;
    END
  END n_b[145]
  PIN n_b[146]
    DIRECTION INPUT ;
    USE SIGNAL ;
    PORT
      LAYER M4 ;
        RECT 0.000 190.272 0.192 190.296 ;
    END
  END n_b[146]
  PIN n_b[147]
    DIRECTION INPUT ;
    USE SIGNAL ;
    PORT
      LAYER M4 ;
        RECT 0.000 190.464 0.192 190.488 ;
    END
  END n_b[147]
  PIN n_b[148]
    DIRECTION INPUT ;
    USE SIGNAL ;
    PORT
      LAYER M4 ;
        RECT 0.000 190.656 0.192 190.680 ;
    END
  END n_b[148]
  PIN n_b[149]
    DIRECTION INPUT ;
    USE SIGNAL ;
    PORT
      LAYER M4 ;
        RECT 0.000 190.848 0.192 190.872 ;
    END
  END n_b[149]
  PIN n_b[150]
    DIRECTION INPUT ;
    USE SIGNAL ;
    PORT
      LAYER M4 ;
        RECT 0.000 191.040 0.192 191.064 ;
    END
  END n_b[150]
  PIN n_b[151]
    DIRECTION INPUT ;
    USE SIGNAL ;
    PORT
      LAYER M4 ;
        RECT 0.000 191.232 0.192 191.256 ;
    END
  END n_b[151]
  PIN n_b[152]
    DIRECTION INPUT ;
    USE SIGNAL ;
    PORT
      LAYER M4 ;
        RECT 0.000 191.424 0.192 191.448 ;
    END
  END n_b[152]
  PIN n_b[153]
    DIRECTION INPUT ;
    USE SIGNAL ;
    PORT
      LAYER M4 ;
        RECT 0.000 191.616 0.192 191.640 ;
    END
  END n_b[153]
  PIN n_b[154]
    DIRECTION INPUT ;
    USE SIGNAL ;
    PORT
      LAYER M4 ;
        RECT 0.000 191.808 0.192 191.832 ;
    END
  END n_b[154]
  PIN n_b[155]
    DIRECTION INPUT ;
    USE SIGNAL ;
    PORT
      LAYER M4 ;
        RECT 0.000 192.000 0.192 192.024 ;
    END
  END n_b[155]
  PIN n_b[156]
    DIRECTION INPUT ;
    USE SIGNAL ;
    PORT
      LAYER M4 ;
        RECT 0.000 192.192 0.192 192.216 ;
    END
  END n_b[156]
  PIN n_b[157]
    DIRECTION INPUT ;
    USE SIGNAL ;
    PORT
      LAYER M4 ;
        RECT 0.000 192.384 0.192 192.408 ;
    END
  END n_b[157]
  PIN n_b[158]
    DIRECTION INPUT ;
    USE SIGNAL ;
    PORT
      LAYER M4 ;
        RECT 0.000 192.576 0.192 192.600 ;
    END
  END n_b[158]
  PIN n_b[159]
    DIRECTION INPUT ;
    USE SIGNAL ;
    PORT
      LAYER M4 ;
        RECT 0.000 192.768 0.192 192.792 ;
    END
  END n_b[159]
  PIN n_b[160]
    DIRECTION INPUT ;
    USE SIGNAL ;
    PORT
      LAYER M4 ;
        RECT 0.000 192.960 0.192 192.984 ;
    END
  END n_b[160]
  PIN n_b[161]
    DIRECTION INPUT ;
    USE SIGNAL ;
    PORT
      LAYER M4 ;
        RECT 0.000 193.152 0.192 193.176 ;
    END
  END n_b[161]
  PIN n_b[162]
    DIRECTION INPUT ;
    USE SIGNAL ;
    PORT
      LAYER M4 ;
        RECT 0.000 193.344 0.192 193.368 ;
    END
  END n_b[162]
  PIN n_b[163]
    DIRECTION INPUT ;
    USE SIGNAL ;
    PORT
      LAYER M4 ;
        RECT 0.000 193.536 0.192 193.560 ;
    END
  END n_b[163]
  PIN n_b[164]
    DIRECTION INPUT ;
    USE SIGNAL ;
    PORT
      LAYER M4 ;
        RECT 0.000 193.728 0.192 193.752 ;
    END
  END n_b[164]
  PIN n_b[165]
    DIRECTION INPUT ;
    USE SIGNAL ;
    PORT
      LAYER M4 ;
        RECT 0.000 193.920 0.192 193.944 ;
    END
  END n_b[165]
  PIN n_b[166]
    DIRECTION INPUT ;
    USE SIGNAL ;
    PORT
      LAYER M4 ;
        RECT 0.000 194.112 0.192 194.136 ;
    END
  END n_b[166]
  PIN n_b[167]
    DIRECTION INPUT ;
    USE SIGNAL ;
    PORT
      LAYER M4 ;
        RECT 0.000 194.304 0.192 194.328 ;
    END
  END n_b[167]
  PIN n_b[168]
    DIRECTION INPUT ;
    USE SIGNAL ;
    PORT
      LAYER M4 ;
        RECT 0.000 194.496 0.192 194.520 ;
    END
  END n_b[168]
  PIN n_b[169]
    DIRECTION INPUT ;
    USE SIGNAL ;
    PORT
      LAYER M4 ;
        RECT 0.000 194.688 0.192 194.712 ;
    END
  END n_b[169]
  PIN n_b[170]
    DIRECTION INPUT ;
    USE SIGNAL ;
    PORT
      LAYER M4 ;
        RECT 0.000 194.880 0.192 194.904 ;
    END
  END n_b[170]
  PIN n_b[171]
    DIRECTION INPUT ;
    USE SIGNAL ;
    PORT
      LAYER M4 ;
        RECT 0.000 195.072 0.192 195.096 ;
    END
  END n_b[171]
  PIN n_b[172]
    DIRECTION INPUT ;
    USE SIGNAL ;
    PORT
      LAYER M4 ;
        RECT 0.000 195.264 0.192 195.288 ;
    END
  END n_b[172]
  PIN n_b[173]
    DIRECTION INPUT ;
    USE SIGNAL ;
    PORT
      LAYER M4 ;
        RECT 0.000 195.456 0.192 195.480 ;
    END
  END n_b[173]
  PIN n_b[174]
    DIRECTION INPUT ;
    USE SIGNAL ;
    PORT
      LAYER M4 ;
        RECT 0.000 195.648 0.192 195.672 ;
    END
  END n_b[174]
  PIN n_b[175]
    DIRECTION INPUT ;
    USE SIGNAL ;
    PORT
      LAYER M4 ;
        RECT 0.000 195.840 0.192 195.864 ;
    END
  END n_b[175]
  PIN n_b[176]
    DIRECTION INPUT ;
    USE SIGNAL ;
    PORT
      LAYER M4 ;
        RECT 0.000 196.032 0.192 196.056 ;
    END
  END n_b[176]
  PIN n_b[177]
    DIRECTION INPUT ;
    USE SIGNAL ;
    PORT
      LAYER M4 ;
        RECT 0.000 196.224 0.192 196.248 ;
    END
  END n_b[177]
  PIN n_b[178]
    DIRECTION INPUT ;
    USE SIGNAL ;
    PORT
      LAYER M4 ;
        RECT 0.000 196.416 0.192 196.440 ;
    END
  END n_b[178]
  PIN n_b[179]
    DIRECTION INPUT ;
    USE SIGNAL ;
    PORT
      LAYER M4 ;
        RECT 0.000 196.608 0.192 196.632 ;
    END
  END n_b[179]
  PIN n_b[180]
    DIRECTION INPUT ;
    USE SIGNAL ;
    PORT
      LAYER M4 ;
        RECT 0.000 196.800 0.192 196.824 ;
    END
  END n_b[180]
  PIN n_b[181]
    DIRECTION INPUT ;
    USE SIGNAL ;
    PORT
      LAYER M4 ;
        RECT 0.000 196.992 0.192 197.016 ;
    END
  END n_b[181]
  PIN n_b[182]
    DIRECTION INPUT ;
    USE SIGNAL ;
    PORT
      LAYER M4 ;
        RECT 0.000 197.184 0.192 197.208 ;
    END
  END n_b[182]
  PIN n_b[183]
    DIRECTION INPUT ;
    USE SIGNAL ;
    PORT
      LAYER M4 ;
        RECT 0.000 197.376 0.192 197.400 ;
    END
  END n_b[183]
  PIN n_b[184]
    DIRECTION INPUT ;
    USE SIGNAL ;
    PORT
      LAYER M4 ;
        RECT 0.000 197.568 0.192 197.592 ;
    END
  END n_b[184]
  PIN n_b[185]
    DIRECTION INPUT ;
    USE SIGNAL ;
    PORT
      LAYER M4 ;
        RECT 0.000 197.760 0.192 197.784 ;
    END
  END n_b[185]
  PIN n_b[186]
    DIRECTION INPUT ;
    USE SIGNAL ;
    PORT
      LAYER M4 ;
        RECT 0.000 197.952 0.192 197.976 ;
    END
  END n_b[186]
  PIN n_b[187]
    DIRECTION INPUT ;
    USE SIGNAL ;
    PORT
      LAYER M4 ;
        RECT 0.000 198.144 0.192 198.168 ;
    END
  END n_b[187]
  PIN n_b[188]
    DIRECTION INPUT ;
    USE SIGNAL ;
    PORT
      LAYER M4 ;
        RECT 0.000 198.336 0.192 198.360 ;
    END
  END n_b[188]
  PIN n_b[189]
    DIRECTION INPUT ;
    USE SIGNAL ;
    PORT
      LAYER M4 ;
        RECT 0.000 198.528 0.192 198.552 ;
    END
  END n_b[189]
  PIN n_b[190]
    DIRECTION INPUT ;
    USE SIGNAL ;
    PORT
      LAYER M4 ;
        RECT 0.000 198.720 0.192 198.744 ;
    END
  END n_b[190]
  PIN n_b[191]
    DIRECTION INPUT ;
    USE SIGNAL ;
    PORT
      LAYER M4 ;
        RECT 0.000 198.912 0.192 198.936 ;
    END
  END n_b[191]
  PIN n_b[192]
    DIRECTION INPUT ;
    USE SIGNAL ;
    PORT
      LAYER M4 ;
        RECT 0.000 199.104 0.192 199.128 ;
    END
  END n_b[192]
  PIN n_b[193]
    DIRECTION INPUT ;
    USE SIGNAL ;
    PORT
      LAYER M4 ;
        RECT 0.000 199.296 0.192 199.320 ;
    END
  END n_b[193]
  PIN n_b[194]
    DIRECTION INPUT ;
    USE SIGNAL ;
    PORT
      LAYER M4 ;
        RECT 0.000 199.488 0.192 199.512 ;
    END
  END n_b[194]
  PIN n_b[195]
    DIRECTION INPUT ;
    USE SIGNAL ;
    PORT
      LAYER M4 ;
        RECT 0.000 199.680 0.192 199.704 ;
    END
  END n_b[195]
  PIN n_b[196]
    DIRECTION INPUT ;
    USE SIGNAL ;
    PORT
      LAYER M4 ;
        RECT 0.000 199.872 0.192 199.896 ;
    END
  END n_b[196]
  PIN n_b[197]
    DIRECTION INPUT ;
    USE SIGNAL ;
    PORT
      LAYER M4 ;
        RECT 0.000 200.064 0.192 200.088 ;
    END
  END n_b[197]
  PIN n_b[198]
    DIRECTION INPUT ;
    USE SIGNAL ;
    PORT
      LAYER M4 ;
        RECT 0.000 200.256 0.192 200.280 ;
    END
  END n_b[198]
  PIN n_b[199]
    DIRECTION INPUT ;
    USE SIGNAL ;
    PORT
      LAYER M4 ;
        RECT 0.000 200.448 0.192 200.472 ;
    END
  END n_b[199]
  PIN n_b[200]
    DIRECTION INPUT ;
    USE SIGNAL ;
    PORT
      LAYER M4 ;
        RECT 0.000 200.640 0.192 200.664 ;
    END
  END n_b[200]
  PIN n_b[201]
    DIRECTION INPUT ;
    USE SIGNAL ;
    PORT
      LAYER M4 ;
        RECT 0.000 200.832 0.192 200.856 ;
    END
  END n_b[201]
  PIN n_b[202]
    DIRECTION INPUT ;
    USE SIGNAL ;
    PORT
      LAYER M4 ;
        RECT 0.000 201.024 0.192 201.048 ;
    END
  END n_b[202]
  PIN n_b[203]
    DIRECTION INPUT ;
    USE SIGNAL ;
    PORT
      LAYER M4 ;
        RECT 0.000 201.216 0.192 201.240 ;
    END
  END n_b[203]
  PIN n_b[204]
    DIRECTION INPUT ;
    USE SIGNAL ;
    PORT
      LAYER M4 ;
        RECT 0.000 201.408 0.192 201.432 ;
    END
  END n_b[204]
  PIN n_b[205]
    DIRECTION INPUT ;
    USE SIGNAL ;
    PORT
      LAYER M4 ;
        RECT 0.000 201.600 0.192 201.624 ;
    END
  END n_b[205]
  PIN n_b[206]
    DIRECTION INPUT ;
    USE SIGNAL ;
    PORT
      LAYER M4 ;
        RECT 0.000 201.792 0.192 201.816 ;
    END
  END n_b[206]
  PIN n_b[207]
    DIRECTION INPUT ;
    USE SIGNAL ;
    PORT
      LAYER M4 ;
        RECT 0.000 201.984 0.192 202.008 ;
    END
  END n_b[207]
  PIN n_b[208]
    DIRECTION INPUT ;
    USE SIGNAL ;
    PORT
      LAYER M4 ;
        RECT 0.000 202.176 0.192 202.200 ;
    END
  END n_b[208]
  PIN n_b[209]
    DIRECTION INPUT ;
    USE SIGNAL ;
    PORT
      LAYER M4 ;
        RECT 0.000 202.368 0.192 202.392 ;
    END
  END n_b[209]
  PIN n_b[210]
    DIRECTION INPUT ;
    USE SIGNAL ;
    PORT
      LAYER M4 ;
        RECT 0.000 202.560 0.192 202.584 ;
    END
  END n_b[210]
  PIN n_b[211]
    DIRECTION INPUT ;
    USE SIGNAL ;
    PORT
      LAYER M4 ;
        RECT 0.000 202.752 0.192 202.776 ;
    END
  END n_b[211]
  PIN n_b[212]
    DIRECTION INPUT ;
    USE SIGNAL ;
    PORT
      LAYER M4 ;
        RECT 0.000 202.944 0.192 202.968 ;
    END
  END n_b[212]
  PIN n_b[213]
    DIRECTION INPUT ;
    USE SIGNAL ;
    PORT
      LAYER M4 ;
        RECT 0.000 203.136 0.192 203.160 ;
    END
  END n_b[213]
  PIN n_b[214]
    DIRECTION INPUT ;
    USE SIGNAL ;
    PORT
      LAYER M4 ;
        RECT 0.000 203.328 0.192 203.352 ;
    END
  END n_b[214]
  PIN n_b[215]
    DIRECTION INPUT ;
    USE SIGNAL ;
    PORT
      LAYER M4 ;
        RECT 0.000 203.520 0.192 203.544 ;
    END
  END n_b[215]
  PIN n_b[216]
    DIRECTION INPUT ;
    USE SIGNAL ;
    PORT
      LAYER M4 ;
        RECT 0.000 203.712 0.192 203.736 ;
    END
  END n_b[216]
  PIN n_b[217]
    DIRECTION INPUT ;
    USE SIGNAL ;
    PORT
      LAYER M4 ;
        RECT 0.000 203.904 0.192 203.928 ;
    END
  END n_b[217]
  PIN n_b[218]
    DIRECTION INPUT ;
    USE SIGNAL ;
    PORT
      LAYER M4 ;
        RECT 0.000 204.096 0.192 204.120 ;
    END
  END n_b[218]
  PIN n_b[219]
    DIRECTION INPUT ;
    USE SIGNAL ;
    PORT
      LAYER M4 ;
        RECT 0.000 204.288 0.192 204.312 ;
    END
  END n_b[219]
  PIN n_b[220]
    DIRECTION INPUT ;
    USE SIGNAL ;
    PORT
      LAYER M4 ;
        RECT 0.000 204.480 0.192 204.504 ;
    END
  END n_b[220]
  PIN n_b[221]
    DIRECTION INPUT ;
    USE SIGNAL ;
    PORT
      LAYER M4 ;
        RECT 0.000 204.672 0.192 204.696 ;
    END
  END n_b[221]
  PIN n_b[222]
    DIRECTION INPUT ;
    USE SIGNAL ;
    PORT
      LAYER M4 ;
        RECT 0.000 204.864 0.192 204.888 ;
    END
  END n_b[222]
  PIN n_b[223]
    DIRECTION INPUT ;
    USE SIGNAL ;
    PORT
      LAYER M4 ;
        RECT 0.000 205.056 0.192 205.080 ;
    END
  END n_b[223]
  PIN n_b[224]
    DIRECTION INPUT ;
    USE SIGNAL ;
    PORT
      LAYER M4 ;
        RECT 0.000 205.248 0.192 205.272 ;
    END
  END n_b[224]
  PIN n_b[225]
    DIRECTION INPUT ;
    USE SIGNAL ;
    PORT
      LAYER M4 ;
        RECT 0.000 205.440 0.192 205.464 ;
    END
  END n_b[225]
  PIN n_b[226]
    DIRECTION INPUT ;
    USE SIGNAL ;
    PORT
      LAYER M4 ;
        RECT 0.000 205.632 0.192 205.656 ;
    END
  END n_b[226]
  PIN n_b[227]
    DIRECTION INPUT ;
    USE SIGNAL ;
    PORT
      LAYER M4 ;
        RECT 0.000 205.824 0.192 205.848 ;
    END
  END n_b[227]
  PIN n_b[228]
    DIRECTION INPUT ;
    USE SIGNAL ;
    PORT
      LAYER M4 ;
        RECT 0.000 206.016 0.192 206.040 ;
    END
  END n_b[228]
  PIN n_b[229]
    DIRECTION INPUT ;
    USE SIGNAL ;
    PORT
      LAYER M4 ;
        RECT 0.000 206.208 0.192 206.232 ;
    END
  END n_b[229]
  PIN n_b[230]
    DIRECTION INPUT ;
    USE SIGNAL ;
    PORT
      LAYER M4 ;
        RECT 0.000 206.400 0.192 206.424 ;
    END
  END n_b[230]
  PIN n_b[231]
    DIRECTION INPUT ;
    USE SIGNAL ;
    PORT
      LAYER M4 ;
        RECT 0.000 206.592 0.192 206.616 ;
    END
  END n_b[231]
  PIN n_b[232]
    DIRECTION INPUT ;
    USE SIGNAL ;
    PORT
      LAYER M4 ;
        RECT 0.000 206.784 0.192 206.808 ;
    END
  END n_b[232]
  PIN n_b[233]
    DIRECTION INPUT ;
    USE SIGNAL ;
    PORT
      LAYER M4 ;
        RECT 0.000 206.976 0.192 207.000 ;
    END
  END n_b[233]
  PIN n_b[234]
    DIRECTION INPUT ;
    USE SIGNAL ;
    PORT
      LAYER M4 ;
        RECT 0.000 207.168 0.192 207.192 ;
    END
  END n_b[234]
  PIN n_b[235]
    DIRECTION INPUT ;
    USE SIGNAL ;
    PORT
      LAYER M4 ;
        RECT 0.000 207.360 0.192 207.384 ;
    END
  END n_b[235]
  PIN n_b[236]
    DIRECTION INPUT ;
    USE SIGNAL ;
    PORT
      LAYER M4 ;
        RECT 0.000 207.552 0.192 207.576 ;
    END
  END n_b[236]
  PIN n_b[237]
    DIRECTION INPUT ;
    USE SIGNAL ;
    PORT
      LAYER M4 ;
        RECT 0.000 207.744 0.192 207.768 ;
    END
  END n_b[237]
  PIN n_b[238]
    DIRECTION INPUT ;
    USE SIGNAL ;
    PORT
      LAYER M4 ;
        RECT 0.000 207.936 0.192 207.960 ;
    END
  END n_b[238]
  PIN n_b[239]
    DIRECTION INPUT ;
    USE SIGNAL ;
    PORT
      LAYER M4 ;
        RECT 0.000 208.128 0.192 208.152 ;
    END
  END n_b[239]
  PIN n_b[240]
    DIRECTION INPUT ;
    USE SIGNAL ;
    PORT
      LAYER M4 ;
        RECT 0.000 208.320 0.192 208.344 ;
    END
  END n_b[240]
  PIN n_b[241]
    DIRECTION INPUT ;
    USE SIGNAL ;
    PORT
      LAYER M4 ;
        RECT 0.000 208.512 0.192 208.536 ;
    END
  END n_b[241]
  PIN n_b[242]
    DIRECTION INPUT ;
    USE SIGNAL ;
    PORT
      LAYER M4 ;
        RECT 0.000 208.704 0.192 208.728 ;
    END
  END n_b[242]
  PIN n_b[243]
    DIRECTION INPUT ;
    USE SIGNAL ;
    PORT
      LAYER M4 ;
        RECT 0.000 208.896 0.192 208.920 ;
    END
  END n_b[243]
  PIN n_b[244]
    DIRECTION INPUT ;
    USE SIGNAL ;
    PORT
      LAYER M4 ;
        RECT 0.000 209.088 0.192 209.112 ;
    END
  END n_b[244]
  PIN n_b[245]
    DIRECTION INPUT ;
    USE SIGNAL ;
    PORT
      LAYER M4 ;
        RECT 0.000 209.280 0.192 209.304 ;
    END
  END n_b[245]
  PIN n_b[246]
    DIRECTION INPUT ;
    USE SIGNAL ;
    PORT
      LAYER M4 ;
        RECT 0.000 209.472 0.192 209.496 ;
    END
  END n_b[246]
  PIN n_b[247]
    DIRECTION INPUT ;
    USE SIGNAL ;
    PORT
      LAYER M4 ;
        RECT 0.000 209.664 0.192 209.688 ;
    END
  END n_b[247]
  PIN n_b[248]
    DIRECTION INPUT ;
    USE SIGNAL ;
    PORT
      LAYER M4 ;
        RECT 0.000 209.856 0.192 209.880 ;
    END
  END n_b[248]
  PIN n_b[249]
    DIRECTION INPUT ;
    USE SIGNAL ;
    PORT
      LAYER M4 ;
        RECT 0.000 210.048 0.192 210.072 ;
    END
  END n_b[249]
  PIN n_b[250]
    DIRECTION INPUT ;
    USE SIGNAL ;
    PORT
      LAYER M4 ;
        RECT 0.000 210.240 0.192 210.264 ;
    END
  END n_b[250]
  PIN n_b[251]
    DIRECTION INPUT ;
    USE SIGNAL ;
    PORT
      LAYER M4 ;
        RECT 0.000 210.432 0.192 210.456 ;
    END
  END n_b[251]
  PIN n_b[252]
    DIRECTION INPUT ;
    USE SIGNAL ;
    PORT
      LAYER M4 ;
        RECT 0.000 210.624 0.192 210.648 ;
    END
  END n_b[252]
  PIN n_b[253]
    DIRECTION INPUT ;
    USE SIGNAL ;
    PORT
      LAYER M4 ;
        RECT 0.000 210.816 0.192 210.840 ;
    END
  END n_b[253]
  PIN n_b[254]
    DIRECTION INPUT ;
    USE SIGNAL ;
    PORT
      LAYER M4 ;
        RECT 0.000 211.008 0.192 211.032 ;
    END
  END n_b[254]
  PIN n_b[255]
    DIRECTION INPUT ;
    USE SIGNAL ;
    PORT
      LAYER M4 ;
        RECT 0.000 211.200 0.192 211.224 ;
    END
  END n_b[255]
  PIN n_b[256]
    DIRECTION INPUT ;
    USE SIGNAL ;
    PORT
      LAYER M4 ;
        RECT 0.000 211.392 0.192 211.416 ;
    END
  END n_b[256]
  PIN n_b[257]
    DIRECTION INPUT ;
    USE SIGNAL ;
    PORT
      LAYER M4 ;
        RECT 0.000 211.584 0.192 211.608 ;
    END
  END n_b[257]
  PIN n_b[258]
    DIRECTION INPUT ;
    USE SIGNAL ;
    PORT
      LAYER M4 ;
        RECT 0.000 211.776 0.192 211.800 ;
    END
  END n_b[258]
  PIN n_b[259]
    DIRECTION INPUT ;
    USE SIGNAL ;
    PORT
      LAYER M4 ;
        RECT 0.000 211.968 0.192 211.992 ;
    END
  END n_b[259]
  PIN n_b[260]
    DIRECTION INPUT ;
    USE SIGNAL ;
    PORT
      LAYER M4 ;
        RECT 0.000 212.160 0.192 212.184 ;
    END
  END n_b[260]
  PIN n_b[261]
    DIRECTION INPUT ;
    USE SIGNAL ;
    PORT
      LAYER M4 ;
        RECT 0.000 212.352 0.192 212.376 ;
    END
  END n_b[261]
  PIN n_b[262]
    DIRECTION INPUT ;
    USE SIGNAL ;
    PORT
      LAYER M4 ;
        RECT 0.000 212.544 0.192 212.568 ;
    END
  END n_b[262]
  PIN n_b[263]
    DIRECTION INPUT ;
    USE SIGNAL ;
    PORT
      LAYER M4 ;
        RECT 0.000 212.736 0.192 212.760 ;
    END
  END n_b[263]
  PIN n_b[264]
    DIRECTION INPUT ;
    USE SIGNAL ;
    PORT
      LAYER M4 ;
        RECT 0.000 212.928 0.192 212.952 ;
    END
  END n_b[264]
  PIN n_b[265]
    DIRECTION INPUT ;
    USE SIGNAL ;
    PORT
      LAYER M4 ;
        RECT 0.000 213.120 0.192 213.144 ;
    END
  END n_b[265]
  PIN n_b[266]
    DIRECTION INPUT ;
    USE SIGNAL ;
    PORT
      LAYER M4 ;
        RECT 0.000 213.312 0.192 213.336 ;
    END
  END n_b[266]
  PIN n_b[267]
    DIRECTION INPUT ;
    USE SIGNAL ;
    PORT
      LAYER M4 ;
        RECT 0.000 213.504 0.192 213.528 ;
    END
  END n_b[267]
  PIN n_b[268]
    DIRECTION INPUT ;
    USE SIGNAL ;
    PORT
      LAYER M4 ;
        RECT 0.000 213.696 0.192 213.720 ;
    END
  END n_b[268]
  PIN n_b[269]
    DIRECTION INPUT ;
    USE SIGNAL ;
    PORT
      LAYER M4 ;
        RECT 0.000 213.888 0.192 213.912 ;
    END
  END n_b[269]
  PIN n_b[270]
    DIRECTION INPUT ;
    USE SIGNAL ;
    PORT
      LAYER M4 ;
        RECT 0.000 214.080 0.192 214.104 ;
    END
  END n_b[270]
  PIN n_b[271]
    DIRECTION INPUT ;
    USE SIGNAL ;
    PORT
      LAYER M4 ;
        RECT 0.000 214.272 0.192 214.296 ;
    END
  END n_b[271]
  PIN n_b[272]
    DIRECTION INPUT ;
    USE SIGNAL ;
    PORT
      LAYER M4 ;
        RECT 0.000 214.464 0.192 214.488 ;
    END
  END n_b[272]
  PIN n_b[273]
    DIRECTION INPUT ;
    USE SIGNAL ;
    PORT
      LAYER M4 ;
        RECT 0.000 214.656 0.192 214.680 ;
    END
  END n_b[273]
  PIN n_b[274]
    DIRECTION INPUT ;
    USE SIGNAL ;
    PORT
      LAYER M4 ;
        RECT 0.000 214.848 0.192 214.872 ;
    END
  END n_b[274]
  PIN n_b[275]
    DIRECTION INPUT ;
    USE SIGNAL ;
    PORT
      LAYER M4 ;
        RECT 0.000 215.040 0.192 215.064 ;
    END
  END n_b[275]
  PIN n_b[276]
    DIRECTION INPUT ;
    USE SIGNAL ;
    PORT
      LAYER M4 ;
        RECT 0.000 215.232 0.192 215.256 ;
    END
  END n_b[276]
  PIN n_b[277]
    DIRECTION INPUT ;
    USE SIGNAL ;
    PORT
      LAYER M4 ;
        RECT 0.000 215.424 0.192 215.448 ;
    END
  END n_b[277]
  PIN n_b[278]
    DIRECTION INPUT ;
    USE SIGNAL ;
    PORT
      LAYER M4 ;
        RECT 0.000 215.616 0.192 215.640 ;
    END
  END n_b[278]
  PIN n_b[279]
    DIRECTION INPUT ;
    USE SIGNAL ;
    PORT
      LAYER M4 ;
        RECT 0.000 215.808 0.192 215.832 ;
    END
  END n_b[279]
  PIN n_b[280]
    DIRECTION INPUT ;
    USE SIGNAL ;
    PORT
      LAYER M4 ;
        RECT 0.000 216.000 0.192 216.024 ;
    END
  END n_b[280]
  PIN n_b[281]
    DIRECTION INPUT ;
    USE SIGNAL ;
    PORT
      LAYER M4 ;
        RECT 0.000 216.192 0.192 216.216 ;
    END
  END n_b[281]
  PIN n_b[282]
    DIRECTION INPUT ;
    USE SIGNAL ;
    PORT
      LAYER M4 ;
        RECT 0.000 216.384 0.192 216.408 ;
    END
  END n_b[282]
  PIN n_b[283]
    DIRECTION INPUT ;
    USE SIGNAL ;
    PORT
      LAYER M4 ;
        RECT 0.000 216.576 0.192 216.600 ;
    END
  END n_b[283]
  PIN n_b[284]
    DIRECTION INPUT ;
    USE SIGNAL ;
    PORT
      LAYER M4 ;
        RECT 0.000 216.768 0.192 216.792 ;
    END
  END n_b[284]
  PIN n_b[285]
    DIRECTION INPUT ;
    USE SIGNAL ;
    PORT
      LAYER M4 ;
        RECT 0.000 216.960 0.192 216.984 ;
    END
  END n_b[285]
  PIN n_b[286]
    DIRECTION INPUT ;
    USE SIGNAL ;
    PORT
      LAYER M4 ;
        RECT 0.000 217.152 0.192 217.176 ;
    END
  END n_b[286]
  PIN n_b[287]
    DIRECTION INPUT ;
    USE SIGNAL ;
    PORT
      LAYER M4 ;
        RECT 0.000 217.344 0.192 217.368 ;
    END
  END n_b[287]
  PIN n_b[288]
    DIRECTION INPUT ;
    USE SIGNAL ;
    PORT
      LAYER M4 ;
        RECT 0.000 217.536 0.192 217.560 ;
    END
  END n_b[288]
  PIN n_b[289]
    DIRECTION INPUT ;
    USE SIGNAL ;
    PORT
      LAYER M4 ;
        RECT 0.000 217.728 0.192 217.752 ;
    END
  END n_b[289]
  PIN n_b[290]
    DIRECTION INPUT ;
    USE SIGNAL ;
    PORT
      LAYER M4 ;
        RECT 0.000 217.920 0.192 217.944 ;
    END
  END n_b[290]
  PIN n_b[291]
    DIRECTION INPUT ;
    USE SIGNAL ;
    PORT
      LAYER M4 ;
        RECT 0.000 218.112 0.192 218.136 ;
    END
  END n_b[291]
  PIN n_b[292]
    DIRECTION INPUT ;
    USE SIGNAL ;
    PORT
      LAYER M4 ;
        RECT 0.000 218.304 0.192 218.328 ;
    END
  END n_b[292]
  PIN n_b[293]
    DIRECTION INPUT ;
    USE SIGNAL ;
    PORT
      LAYER M4 ;
        RECT 0.000 218.496 0.192 218.520 ;
    END
  END n_b[293]
  PIN n_b[294]
    DIRECTION INPUT ;
    USE SIGNAL ;
    PORT
      LAYER M4 ;
        RECT 0.000 218.688 0.192 218.712 ;
    END
  END n_b[294]
  PIN n_b[295]
    DIRECTION INPUT ;
    USE SIGNAL ;
    PORT
      LAYER M4 ;
        RECT 0.000 218.880 0.192 218.904 ;
    END
  END n_b[295]
  PIN n_b[296]
    DIRECTION INPUT ;
    USE SIGNAL ;
    PORT
      LAYER M4 ;
        RECT 0.000 219.072 0.192 219.096 ;
    END
  END n_b[296]
  PIN n_b[297]
    DIRECTION INPUT ;
    USE SIGNAL ;
    PORT
      LAYER M4 ;
        RECT 0.000 219.264 0.192 219.288 ;
    END
  END n_b[297]
  PIN n_b[298]
    DIRECTION INPUT ;
    USE SIGNAL ;
    PORT
      LAYER M4 ;
        RECT 0.000 219.456 0.192 219.480 ;
    END
  END n_b[298]
  PIN n_b[299]
    DIRECTION INPUT ;
    USE SIGNAL ;
    PORT
      LAYER M4 ;
        RECT 0.000 219.648 0.192 219.672 ;
    END
  END n_b[299]
  PIN n_b[300]
    DIRECTION INPUT ;
    USE SIGNAL ;
    PORT
      LAYER M4 ;
        RECT 0.000 219.840 0.192 219.864 ;
    END
  END n_b[300]
  PIN n_b[301]
    DIRECTION INPUT ;
    USE SIGNAL ;
    PORT
      LAYER M4 ;
        RECT 0.000 220.032 0.192 220.056 ;
    END
  END n_b[301]
  PIN n_b[302]
    DIRECTION INPUT ;
    USE SIGNAL ;
    PORT
      LAYER M4 ;
        RECT 0.000 220.224 0.192 220.248 ;
    END
  END n_b[302]
  PIN n_b[303]
    DIRECTION INPUT ;
    USE SIGNAL ;
    PORT
      LAYER M4 ;
        RECT 0.000 220.416 0.192 220.440 ;
    END
  END n_b[303]
  PIN n_b[304]
    DIRECTION INPUT ;
    USE SIGNAL ;
    PORT
      LAYER M4 ;
        RECT 0.000 220.608 0.192 220.632 ;
    END
  END n_b[304]
  PIN n_b[305]
    DIRECTION INPUT ;
    USE SIGNAL ;
    PORT
      LAYER M4 ;
        RECT 0.000 220.800 0.192 220.824 ;
    END
  END n_b[305]
  PIN n_b[306]
    DIRECTION INPUT ;
    USE SIGNAL ;
    PORT
      LAYER M4 ;
        RECT 0.000 220.992 0.192 221.016 ;
    END
  END n_b[306]
  PIN n_b[307]
    DIRECTION INPUT ;
    USE SIGNAL ;
    PORT
      LAYER M4 ;
        RECT 0.000 221.184 0.192 221.208 ;
    END
  END n_b[307]
  PIN n_b[308]
    DIRECTION INPUT ;
    USE SIGNAL ;
    PORT
      LAYER M4 ;
        RECT 0.000 221.376 0.192 221.400 ;
    END
  END n_b[308]
  PIN n_b[309]
    DIRECTION INPUT ;
    USE SIGNAL ;
    PORT
      LAYER M4 ;
        RECT 0.000 221.568 0.192 221.592 ;
    END
  END n_b[309]
  PIN n_b[310]
    DIRECTION INPUT ;
    USE SIGNAL ;
    PORT
      LAYER M4 ;
        RECT 0.000 221.760 0.192 221.784 ;
    END
  END n_b[310]
  PIN n_b[311]
    DIRECTION INPUT ;
    USE SIGNAL ;
    PORT
      LAYER M4 ;
        RECT 0.000 221.952 0.192 221.976 ;
    END
  END n_b[311]
  PIN n_b[312]
    DIRECTION INPUT ;
    USE SIGNAL ;
    PORT
      LAYER M4 ;
        RECT 0.000 222.144 0.192 222.168 ;
    END
  END n_b[312]
  PIN n_b[313]
    DIRECTION INPUT ;
    USE SIGNAL ;
    PORT
      LAYER M4 ;
        RECT 0.000 222.336 0.192 222.360 ;
    END
  END n_b[313]
  PIN n_b[314]
    DIRECTION INPUT ;
    USE SIGNAL ;
    PORT
      LAYER M4 ;
        RECT 0.000 222.528 0.192 222.552 ;
    END
  END n_b[314]
  PIN n_b[315]
    DIRECTION INPUT ;
    USE SIGNAL ;
    PORT
      LAYER M4 ;
        RECT 0.000 222.720 0.192 222.744 ;
    END
  END n_b[315]
  PIN n_b[316]
    DIRECTION INPUT ;
    USE SIGNAL ;
    PORT
      LAYER M4 ;
        RECT 0.000 222.912 0.192 222.936 ;
    END
  END n_b[316]
  PIN n_b[317]
    DIRECTION INPUT ;
    USE SIGNAL ;
    PORT
      LAYER M4 ;
        RECT 0.000 223.104 0.192 223.128 ;
    END
  END n_b[317]
  PIN n_b[318]
    DIRECTION INPUT ;
    USE SIGNAL ;
    PORT
      LAYER M4 ;
        RECT 0.000 223.296 0.192 223.320 ;
    END
  END n_b[318]
  PIN n_b[319]
    DIRECTION INPUT ;
    USE SIGNAL ;
    PORT
      LAYER M4 ;
        RECT 0.000 223.488 0.192 223.512 ;
    END
  END n_b[319]
  PIN n_b[320]
    DIRECTION INPUT ;
    USE SIGNAL ;
    PORT
      LAYER M4 ;
        RECT 0.000 223.680 0.192 223.704 ;
    END
  END n_b[320]
  PIN n_b[321]
    DIRECTION INPUT ;
    USE SIGNAL ;
    PORT
      LAYER M4 ;
        RECT 0.000 223.872 0.192 223.896 ;
    END
  END n_b[321]
  PIN n_b[322]
    DIRECTION INPUT ;
    USE SIGNAL ;
    PORT
      LAYER M4 ;
        RECT 0.000 224.064 0.192 224.088 ;
    END
  END n_b[322]
  PIN n_b[323]
    DIRECTION INPUT ;
    USE SIGNAL ;
    PORT
      LAYER M4 ;
        RECT 0.000 224.256 0.192 224.280 ;
    END
  END n_b[323]
  PIN n_b[324]
    DIRECTION INPUT ;
    USE SIGNAL ;
    PORT
      LAYER M4 ;
        RECT 0.000 224.448 0.192 224.472 ;
    END
  END n_b[324]
  PIN n_b[325]
    DIRECTION INPUT ;
    USE SIGNAL ;
    PORT
      LAYER M4 ;
        RECT 0.000 224.640 0.192 224.664 ;
    END
  END n_b[325]
  PIN n_b[326]
    DIRECTION INPUT ;
    USE SIGNAL ;
    PORT
      LAYER M4 ;
        RECT 0.000 224.832 0.192 224.856 ;
    END
  END n_b[326]
  PIN n_b[327]
    DIRECTION INPUT ;
    USE SIGNAL ;
    PORT
      LAYER M4 ;
        RECT 0.000 225.024 0.192 225.048 ;
    END
  END n_b[327]
  PIN n_b[328]
    DIRECTION INPUT ;
    USE SIGNAL ;
    PORT
      LAYER M4 ;
        RECT 0.000 225.216 0.192 225.240 ;
    END
  END n_b[328]
  PIN n_b[329]
    DIRECTION INPUT ;
    USE SIGNAL ;
    PORT
      LAYER M4 ;
        RECT 0.000 225.408 0.192 225.432 ;
    END
  END n_b[329]
  PIN n_b[330]
    DIRECTION INPUT ;
    USE SIGNAL ;
    PORT
      LAYER M4 ;
        RECT 0.000 225.600 0.192 225.624 ;
    END
  END n_b[330]
  PIN n_b[331]
    DIRECTION INPUT ;
    USE SIGNAL ;
    PORT
      LAYER M4 ;
        RECT 0.000 225.792 0.192 225.816 ;
    END
  END n_b[331]
  PIN n_b[332]
    DIRECTION INPUT ;
    USE SIGNAL ;
    PORT
      LAYER M4 ;
        RECT 0.000 225.984 0.192 226.008 ;
    END
  END n_b[332]
  PIN n_b[333]
    DIRECTION INPUT ;
    USE SIGNAL ;
    PORT
      LAYER M4 ;
        RECT 0.000 226.176 0.192 226.200 ;
    END
  END n_b[333]
  PIN n_b[334]
    DIRECTION INPUT ;
    USE SIGNAL ;
    PORT
      LAYER M4 ;
        RECT 0.000 226.368 0.192 226.392 ;
    END
  END n_b[334]
  PIN n_b[335]
    DIRECTION INPUT ;
    USE SIGNAL ;
    PORT
      LAYER M4 ;
        RECT 0.000 226.560 0.192 226.584 ;
    END
  END n_b[335]
  PIN n_b[336]
    DIRECTION INPUT ;
    USE SIGNAL ;
    PORT
      LAYER M4 ;
        RECT 0.000 226.752 0.192 226.776 ;
    END
  END n_b[336]
  PIN n_b[337]
    DIRECTION INPUT ;
    USE SIGNAL ;
    PORT
      LAYER M4 ;
        RECT 0.000 226.944 0.192 226.968 ;
    END
  END n_b[337]
  PIN n_b[338]
    DIRECTION INPUT ;
    USE SIGNAL ;
    PORT
      LAYER M4 ;
        RECT 0.000 227.136 0.192 227.160 ;
    END
  END n_b[338]
  PIN n_b[339]
    DIRECTION INPUT ;
    USE SIGNAL ;
    PORT
      LAYER M4 ;
        RECT 0.000 227.328 0.192 227.352 ;
    END
  END n_b[339]
  PIN n_b[340]
    DIRECTION INPUT ;
    USE SIGNAL ;
    PORT
      LAYER M4 ;
        RECT 0.000 227.520 0.192 227.544 ;
    END
  END n_b[340]
  PIN n_b[341]
    DIRECTION INPUT ;
    USE SIGNAL ;
    PORT
      LAYER M4 ;
        RECT 0.000 227.712 0.192 227.736 ;
    END
  END n_b[341]
  PIN n_b[342]
    DIRECTION INPUT ;
    USE SIGNAL ;
    PORT
      LAYER M4 ;
        RECT 0.000 227.904 0.192 227.928 ;
    END
  END n_b[342]
  PIN n_b[343]
    DIRECTION INPUT ;
    USE SIGNAL ;
    PORT
      LAYER M4 ;
        RECT 0.000 228.096 0.192 228.120 ;
    END
  END n_b[343]
  PIN n_b[344]
    DIRECTION INPUT ;
    USE SIGNAL ;
    PORT
      LAYER M4 ;
        RECT 0.000 228.288 0.192 228.312 ;
    END
  END n_b[344]
  PIN n_b[345]
    DIRECTION INPUT ;
    USE SIGNAL ;
    PORT
      LAYER M4 ;
        RECT 0.000 228.480 0.192 228.504 ;
    END
  END n_b[345]
  PIN n_b[346]
    DIRECTION INPUT ;
    USE SIGNAL ;
    PORT
      LAYER M4 ;
        RECT 0.000 228.672 0.192 228.696 ;
    END
  END n_b[346]
  PIN n_b[347]
    DIRECTION INPUT ;
    USE SIGNAL ;
    PORT
      LAYER M4 ;
        RECT 0.000 228.864 0.192 228.888 ;
    END
  END n_b[347]
  PIN n_b[348]
    DIRECTION INPUT ;
    USE SIGNAL ;
    PORT
      LAYER M4 ;
        RECT 0.000 229.056 0.192 229.080 ;
    END
  END n_b[348]
  PIN n_b[349]
    DIRECTION INPUT ;
    USE SIGNAL ;
    PORT
      LAYER M4 ;
        RECT 0.000 229.248 0.192 229.272 ;
    END
  END n_b[349]
  PIN n_b[350]
    DIRECTION INPUT ;
    USE SIGNAL ;
    PORT
      LAYER M4 ;
        RECT 0.000 229.440 0.192 229.464 ;
    END
  END n_b[350]
  PIN n_b[351]
    DIRECTION INPUT ;
    USE SIGNAL ;
    PORT
      LAYER M4 ;
        RECT 0.000 229.632 0.192 229.656 ;
    END
  END n_b[351]
  PIN n_b[352]
    DIRECTION INPUT ;
    USE SIGNAL ;
    PORT
      LAYER M4 ;
        RECT 0.000 229.824 0.192 229.848 ;
    END
  END n_b[352]
  PIN n_b[353]
    DIRECTION INPUT ;
    USE SIGNAL ;
    PORT
      LAYER M4 ;
        RECT 0.000 230.016 0.192 230.040 ;
    END
  END n_b[353]
  PIN n_b[354]
    DIRECTION INPUT ;
    USE SIGNAL ;
    PORT
      LAYER M4 ;
        RECT 0.000 230.208 0.192 230.232 ;
    END
  END n_b[354]
  PIN n_b[355]
    DIRECTION INPUT ;
    USE SIGNAL ;
    PORT
      LAYER M4 ;
        RECT 0.000 230.400 0.192 230.424 ;
    END
  END n_b[355]
  PIN n_b[356]
    DIRECTION INPUT ;
    USE SIGNAL ;
    PORT
      LAYER M4 ;
        RECT 0.000 230.592 0.192 230.616 ;
    END
  END n_b[356]
  PIN n_b[357]
    DIRECTION INPUT ;
    USE SIGNAL ;
    PORT
      LAYER M4 ;
        RECT 0.000 230.784 0.192 230.808 ;
    END
  END n_b[357]
  PIN n_b[358]
    DIRECTION INPUT ;
    USE SIGNAL ;
    PORT
      LAYER M4 ;
        RECT 0.000 230.976 0.192 231.000 ;
    END
  END n_b[358]
  PIN n_b[359]
    DIRECTION INPUT ;
    USE SIGNAL ;
    PORT
      LAYER M4 ;
        RECT 0.000 231.168 0.192 231.192 ;
    END
  END n_b[359]
  PIN n_b[360]
    DIRECTION INPUT ;
    USE SIGNAL ;
    PORT
      LAYER M4 ;
        RECT 0.000 231.360 0.192 231.384 ;
    END
  END n_b[360]
  PIN n_b[361]
    DIRECTION INPUT ;
    USE SIGNAL ;
    PORT
      LAYER M4 ;
        RECT 0.000 231.552 0.192 231.576 ;
    END
  END n_b[361]
  PIN n_b[362]
    DIRECTION INPUT ;
    USE SIGNAL ;
    PORT
      LAYER M4 ;
        RECT 0.000 231.744 0.192 231.768 ;
    END
  END n_b[362]
  PIN n_b[363]
    DIRECTION INPUT ;
    USE SIGNAL ;
    PORT
      LAYER M4 ;
        RECT 0.000 231.936 0.192 231.960 ;
    END
  END n_b[363]
  PIN n_b[364]
    DIRECTION INPUT ;
    USE SIGNAL ;
    PORT
      LAYER M4 ;
        RECT 0.000 232.128 0.192 232.152 ;
    END
  END n_b[364]
  PIN n_b[365]
    DIRECTION INPUT ;
    USE SIGNAL ;
    PORT
      LAYER M4 ;
        RECT 0.000 232.320 0.192 232.344 ;
    END
  END n_b[365]
  PIN n_b[366]
    DIRECTION INPUT ;
    USE SIGNAL ;
    PORT
      LAYER M4 ;
        RECT 0.000 232.512 0.192 232.536 ;
    END
  END n_b[366]
  PIN n_b[367]
    DIRECTION INPUT ;
    USE SIGNAL ;
    PORT
      LAYER M4 ;
        RECT 0.000 232.704 0.192 232.728 ;
    END
  END n_b[367]
  PIN n_b[368]
    DIRECTION INPUT ;
    USE SIGNAL ;
    PORT
      LAYER M4 ;
        RECT 0.000 232.896 0.192 232.920 ;
    END
  END n_b[368]
  PIN n_b[369]
    DIRECTION INPUT ;
    USE SIGNAL ;
    PORT
      LAYER M4 ;
        RECT 0.000 233.088 0.192 233.112 ;
    END
  END n_b[369]
  PIN n_b[370]
    DIRECTION INPUT ;
    USE SIGNAL ;
    PORT
      LAYER M4 ;
        RECT 0.000 233.280 0.192 233.304 ;
    END
  END n_b[370]
  PIN n_b[371]
    DIRECTION INPUT ;
    USE SIGNAL ;
    PORT
      LAYER M4 ;
        RECT 0.000 233.472 0.192 233.496 ;
    END
  END n_b[371]
  PIN n_b[372]
    DIRECTION INPUT ;
    USE SIGNAL ;
    PORT
      LAYER M4 ;
        RECT 0.000 233.664 0.192 233.688 ;
    END
  END n_b[372]
  PIN n_b[373]
    DIRECTION INPUT ;
    USE SIGNAL ;
    PORT
      LAYER M4 ;
        RECT 0.000 233.856 0.192 233.880 ;
    END
  END n_b[373]
  PIN n_b[374]
    DIRECTION INPUT ;
    USE SIGNAL ;
    PORT
      LAYER M4 ;
        RECT 0.000 234.048 0.192 234.072 ;
    END
  END n_b[374]
  PIN n_b[375]
    DIRECTION INPUT ;
    USE SIGNAL ;
    PORT
      LAYER M4 ;
        RECT 0.000 234.240 0.192 234.264 ;
    END
  END n_b[375]
  PIN n_b[376]
    DIRECTION INPUT ;
    USE SIGNAL ;
    PORT
      LAYER M4 ;
        RECT 0.000 234.432 0.192 234.456 ;
    END
  END n_b[376]
  PIN n_b[377]
    DIRECTION INPUT ;
    USE SIGNAL ;
    PORT
      LAYER M4 ;
        RECT 0.000 234.624 0.192 234.648 ;
    END
  END n_b[377]
  PIN n_b[378]
    DIRECTION INPUT ;
    USE SIGNAL ;
    PORT
      LAYER M4 ;
        RECT 0.000 234.816 0.192 234.840 ;
    END
  END n_b[378]
  PIN n_b[379]
    DIRECTION INPUT ;
    USE SIGNAL ;
    PORT
      LAYER M4 ;
        RECT 0.000 235.008 0.192 235.032 ;
    END
  END n_b[379]
  PIN n_b[380]
    DIRECTION INPUT ;
    USE SIGNAL ;
    PORT
      LAYER M4 ;
        RECT 0.000 235.200 0.192 235.224 ;
    END
  END n_b[380]
  PIN n_b[381]
    DIRECTION INPUT ;
    USE SIGNAL ;
    PORT
      LAYER M4 ;
        RECT 0.000 235.392 0.192 235.416 ;
    END
  END n_b[381]
  PIN n_b[382]
    DIRECTION INPUT ;
    USE SIGNAL ;
    PORT
      LAYER M4 ;
        RECT 0.000 235.584 0.192 235.608 ;
    END
  END n_b[382]
  PIN n_b[383]
    DIRECTION INPUT ;
    USE SIGNAL ;
    PORT
      LAYER M4 ;
        RECT 0.000 235.776 0.192 235.800 ;
    END
  END n_b[383]
  PIN n_b[384]
    DIRECTION INPUT ;
    USE SIGNAL ;
    PORT
      LAYER M4 ;
        RECT 0.000 235.968 0.192 235.992 ;
    END
  END n_b[384]
  PIN n_b[385]
    DIRECTION INPUT ;
    USE SIGNAL ;
    PORT
      LAYER M4 ;
        RECT 0.000 236.160 0.192 236.184 ;
    END
  END n_b[385]
  PIN n_b[386]
    DIRECTION INPUT ;
    USE SIGNAL ;
    PORT
      LAYER M4 ;
        RECT 0.000 236.352 0.192 236.376 ;
    END
  END n_b[386]
  PIN n_b[387]
    DIRECTION INPUT ;
    USE SIGNAL ;
    PORT
      LAYER M4 ;
        RECT 0.000 236.544 0.192 236.568 ;
    END
  END n_b[387]
  PIN n_b[388]
    DIRECTION INPUT ;
    USE SIGNAL ;
    PORT
      LAYER M4 ;
        RECT 0.000 236.736 0.192 236.760 ;
    END
  END n_b[388]
  PIN n_b[389]
    DIRECTION INPUT ;
    USE SIGNAL ;
    PORT
      LAYER M4 ;
        RECT 0.000 236.928 0.192 236.952 ;
    END
  END n_b[389]
  PIN n_b[390]
    DIRECTION INPUT ;
    USE SIGNAL ;
    PORT
      LAYER M4 ;
        RECT 0.000 237.120 0.192 237.144 ;
    END
  END n_b[390]
  PIN n_b[391]
    DIRECTION INPUT ;
    USE SIGNAL ;
    PORT
      LAYER M4 ;
        RECT 0.000 237.312 0.192 237.336 ;
    END
  END n_b[391]
  PIN n_b[392]
    DIRECTION INPUT ;
    USE SIGNAL ;
    PORT
      LAYER M4 ;
        RECT 0.000 237.504 0.192 237.528 ;
    END
  END n_b[392]
  PIN n_b[393]
    DIRECTION INPUT ;
    USE SIGNAL ;
    PORT
      LAYER M4 ;
        RECT 0.000 237.696 0.192 237.720 ;
    END
  END n_b[393]
  PIN n_b[394]
    DIRECTION INPUT ;
    USE SIGNAL ;
    PORT
      LAYER M4 ;
        RECT 0.000 237.888 0.192 237.912 ;
    END
  END n_b[394]
  PIN n_b[395]
    DIRECTION INPUT ;
    USE SIGNAL ;
    PORT
      LAYER M4 ;
        RECT 0.000 238.080 0.192 238.104 ;
    END
  END n_b[395]
  PIN n_b[396]
    DIRECTION INPUT ;
    USE SIGNAL ;
    PORT
      LAYER M4 ;
        RECT 0.000 238.272 0.192 238.296 ;
    END
  END n_b[396]
  PIN n_b[397]
    DIRECTION INPUT ;
    USE SIGNAL ;
    PORT
      LAYER M4 ;
        RECT 0.000 238.464 0.192 238.488 ;
    END
  END n_b[397]
  PIN n_b[398]
    DIRECTION INPUT ;
    USE SIGNAL ;
    PORT
      LAYER M4 ;
        RECT 0.000 238.656 0.192 238.680 ;
    END
  END n_b[398]
  PIN n_b[399]
    DIRECTION INPUT ;
    USE SIGNAL ;
    PORT
      LAYER M4 ;
        RECT 0.000 238.848 0.192 238.872 ;
    END
  END n_b[399]
  PIN n_b[400]
    DIRECTION INPUT ;
    USE SIGNAL ;
    PORT
      LAYER M4 ;
        RECT 0.000 239.040 0.192 239.064 ;
    END
  END n_b[400]
  PIN n_b[401]
    DIRECTION INPUT ;
    USE SIGNAL ;
    PORT
      LAYER M4 ;
        RECT 0.000 239.232 0.192 239.256 ;
    END
  END n_b[401]
  PIN n_b[402]
    DIRECTION INPUT ;
    USE SIGNAL ;
    PORT
      LAYER M4 ;
        RECT 0.000 239.424 0.192 239.448 ;
    END
  END n_b[402]
  PIN n_b[403]
    DIRECTION INPUT ;
    USE SIGNAL ;
    PORT
      LAYER M4 ;
        RECT 0.000 239.616 0.192 239.640 ;
    END
  END n_b[403]
  PIN n_b[404]
    DIRECTION INPUT ;
    USE SIGNAL ;
    PORT
      LAYER M4 ;
        RECT 0.000 239.808 0.192 239.832 ;
    END
  END n_b[404]
  PIN n_b[405]
    DIRECTION INPUT ;
    USE SIGNAL ;
    PORT
      LAYER M4 ;
        RECT 0.000 240.000 0.192 240.024 ;
    END
  END n_b[405]
  PIN n_b[406]
    DIRECTION INPUT ;
    USE SIGNAL ;
    PORT
      LAYER M4 ;
        RECT 0.000 240.192 0.192 240.216 ;
    END
  END n_b[406]
  PIN n_b[407]
    DIRECTION INPUT ;
    USE SIGNAL ;
    PORT
      LAYER M4 ;
        RECT 0.000 240.384 0.192 240.408 ;
    END
  END n_b[407]
  PIN n_b[408]
    DIRECTION INPUT ;
    USE SIGNAL ;
    PORT
      LAYER M4 ;
        RECT 0.000 240.576 0.192 240.600 ;
    END
  END n_b[408]
  PIN n_b[409]
    DIRECTION INPUT ;
    USE SIGNAL ;
    PORT
      LAYER M4 ;
        RECT 0.000 240.768 0.192 240.792 ;
    END
  END n_b[409]
  PIN n_b[410]
    DIRECTION INPUT ;
    USE SIGNAL ;
    PORT
      LAYER M4 ;
        RECT 0.000 240.960 0.192 240.984 ;
    END
  END n_b[410]
  PIN n_b[411]
    DIRECTION INPUT ;
    USE SIGNAL ;
    PORT
      LAYER M4 ;
        RECT 0.000 241.152 0.192 241.176 ;
    END
  END n_b[411]
  PIN n_b[412]
    DIRECTION INPUT ;
    USE SIGNAL ;
    PORT
      LAYER M4 ;
        RECT 0.000 241.344 0.192 241.368 ;
    END
  END n_b[412]
  PIN n_b[413]
    DIRECTION INPUT ;
    USE SIGNAL ;
    PORT
      LAYER M4 ;
        RECT 0.000 241.536 0.192 241.560 ;
    END
  END n_b[413]
  PIN n_b[414]
    DIRECTION INPUT ;
    USE SIGNAL ;
    PORT
      LAYER M4 ;
        RECT 0.000 241.728 0.192 241.752 ;
    END
  END n_b[414]
  PIN n_b[415]
    DIRECTION INPUT ;
    USE SIGNAL ;
    PORT
      LAYER M4 ;
        RECT 0.000 241.920 0.192 241.944 ;
    END
  END n_b[415]
  PIN n_b[416]
    DIRECTION INPUT ;
    USE SIGNAL ;
    PORT
      LAYER M4 ;
        RECT 0.000 242.112 0.192 242.136 ;
    END
  END n_b[416]
  PIN n_b[417]
    DIRECTION INPUT ;
    USE SIGNAL ;
    PORT
      LAYER M4 ;
        RECT 0.000 242.304 0.192 242.328 ;
    END
  END n_b[417]
  PIN n_b[418]
    DIRECTION INPUT ;
    USE SIGNAL ;
    PORT
      LAYER M4 ;
        RECT 0.000 242.496 0.192 242.520 ;
    END
  END n_b[418]
  PIN n_b[419]
    DIRECTION INPUT ;
    USE SIGNAL ;
    PORT
      LAYER M4 ;
        RECT 0.000 242.688 0.192 242.712 ;
    END
  END n_b[419]
  PIN n_b[420]
    DIRECTION INPUT ;
    USE SIGNAL ;
    PORT
      LAYER M4 ;
        RECT 0.000 242.880 0.192 242.904 ;
    END
  END n_b[420]
  PIN n_b[421]
    DIRECTION INPUT ;
    USE SIGNAL ;
    PORT
      LAYER M4 ;
        RECT 0.000 243.072 0.192 243.096 ;
    END
  END n_b[421]
  PIN n_b[422]
    DIRECTION INPUT ;
    USE SIGNAL ;
    PORT
      LAYER M4 ;
        RECT 0.000 243.264 0.192 243.288 ;
    END
  END n_b[422]
  PIN n_b[423]
    DIRECTION INPUT ;
    USE SIGNAL ;
    PORT
      LAYER M4 ;
        RECT 0.000 243.456 0.192 243.480 ;
    END
  END n_b[423]
  PIN n_b[424]
    DIRECTION INPUT ;
    USE SIGNAL ;
    PORT
      LAYER M4 ;
        RECT 0.000 243.648 0.192 243.672 ;
    END
  END n_b[424]
  PIN n_b[425]
    DIRECTION INPUT ;
    USE SIGNAL ;
    PORT
      LAYER M4 ;
        RECT 0.000 243.840 0.192 243.864 ;
    END
  END n_b[425]
  PIN n_b[426]
    DIRECTION INPUT ;
    USE SIGNAL ;
    PORT
      LAYER M4 ;
        RECT 0.000 244.032 0.192 244.056 ;
    END
  END n_b[426]
  PIN n_b[427]
    DIRECTION INPUT ;
    USE SIGNAL ;
    PORT
      LAYER M4 ;
        RECT 0.000 244.224 0.192 244.248 ;
    END
  END n_b[427]
  PIN n_b[428]
    DIRECTION INPUT ;
    USE SIGNAL ;
    PORT
      LAYER M4 ;
        RECT 0.000 244.416 0.192 244.440 ;
    END
  END n_b[428]
  PIN n_b[429]
    DIRECTION INPUT ;
    USE SIGNAL ;
    PORT
      LAYER M4 ;
        RECT 0.000 244.608 0.192 244.632 ;
    END
  END n_b[429]
  PIN n_b[430]
    DIRECTION INPUT ;
    USE SIGNAL ;
    PORT
      LAYER M4 ;
        RECT 0.000 244.800 0.192 244.824 ;
    END
  END n_b[430]
  PIN n_b[431]
    DIRECTION INPUT ;
    USE SIGNAL ;
    PORT
      LAYER M4 ;
        RECT 0.000 244.992 0.192 245.016 ;
    END
  END n_b[431]
  PIN n_b[432]
    DIRECTION INPUT ;
    USE SIGNAL ;
    PORT
      LAYER M4 ;
        RECT 0.000 245.184 0.192 245.208 ;
    END
  END n_b[432]
  PIN n_b[433]
    DIRECTION INPUT ;
    USE SIGNAL ;
    PORT
      LAYER M4 ;
        RECT 0.000 245.376 0.192 245.400 ;
    END
  END n_b[433]
  PIN n_b[434]
    DIRECTION INPUT ;
    USE SIGNAL ;
    PORT
      LAYER M4 ;
        RECT 0.000 245.568 0.192 245.592 ;
    END
  END n_b[434]
  PIN n_b[435]
    DIRECTION INPUT ;
    USE SIGNAL ;
    PORT
      LAYER M4 ;
        RECT 0.000 245.760 0.192 245.784 ;
    END
  END n_b[435]
  PIN n_b[436]
    DIRECTION INPUT ;
    USE SIGNAL ;
    PORT
      LAYER M4 ;
        RECT 0.000 245.952 0.192 245.976 ;
    END
  END n_b[436]
  PIN n_b[437]
    DIRECTION INPUT ;
    USE SIGNAL ;
    PORT
      LAYER M4 ;
        RECT 0.000 246.144 0.192 246.168 ;
    END
  END n_b[437]
  PIN n_b[438]
    DIRECTION INPUT ;
    USE SIGNAL ;
    PORT
      LAYER M4 ;
        RECT 0.000 246.336 0.192 246.360 ;
    END
  END n_b[438]
  PIN n_b[439]
    DIRECTION INPUT ;
    USE SIGNAL ;
    PORT
      LAYER M4 ;
        RECT 0.000 246.528 0.192 246.552 ;
    END
  END n_b[439]
  PIN n_b[440]
    DIRECTION INPUT ;
    USE SIGNAL ;
    PORT
      LAYER M4 ;
        RECT 0.000 246.720 0.192 246.744 ;
    END
  END n_b[440]
  PIN n_b[441]
    DIRECTION INPUT ;
    USE SIGNAL ;
    PORT
      LAYER M4 ;
        RECT 0.000 246.912 0.192 246.936 ;
    END
  END n_b[441]
  PIN n_b[442]
    DIRECTION INPUT ;
    USE SIGNAL ;
    PORT
      LAYER M4 ;
        RECT 0.000 247.104 0.192 247.128 ;
    END
  END n_b[442]
  PIN n_b[443]
    DIRECTION INPUT ;
    USE SIGNAL ;
    PORT
      LAYER M4 ;
        RECT 0.000 247.296 0.192 247.320 ;
    END
  END n_b[443]
  PIN n_b[444]
    DIRECTION INPUT ;
    USE SIGNAL ;
    PORT
      LAYER M4 ;
        RECT 0.000 247.488 0.192 247.512 ;
    END
  END n_b[444]
  PIN n_b[445]
    DIRECTION INPUT ;
    USE SIGNAL ;
    PORT
      LAYER M4 ;
        RECT 0.000 247.680 0.192 247.704 ;
    END
  END n_b[445]
  PIN n_b[446]
    DIRECTION INPUT ;
    USE SIGNAL ;
    PORT
      LAYER M4 ;
        RECT 0.000 247.872 0.192 247.896 ;
    END
  END n_b[446]
  PIN n_b[447]
    DIRECTION INPUT ;
    USE SIGNAL ;
    PORT
      LAYER M4 ;
        RECT 0.000 248.064 0.192 248.088 ;
    END
  END n_b[447]
  PIN n_b[448]
    DIRECTION INPUT ;
    USE SIGNAL ;
    PORT
      LAYER M4 ;
        RECT 0.000 248.256 0.192 248.280 ;
    END
  END n_b[448]
  PIN n_b[449]
    DIRECTION INPUT ;
    USE SIGNAL ;
    PORT
      LAYER M4 ;
        RECT 0.000 248.448 0.192 248.472 ;
    END
  END n_b[449]
  PIN n_b[450]
    DIRECTION INPUT ;
    USE SIGNAL ;
    PORT
      LAYER M4 ;
        RECT 0.000 248.640 0.192 248.664 ;
    END
  END n_b[450]
  PIN n_b[451]
    DIRECTION INPUT ;
    USE SIGNAL ;
    PORT
      LAYER M4 ;
        RECT 0.000 248.832 0.192 248.856 ;
    END
  END n_b[451]
  PIN n_b[452]
    DIRECTION INPUT ;
    USE SIGNAL ;
    PORT
      LAYER M4 ;
        RECT 0.000 249.024 0.192 249.048 ;
    END
  END n_b[452]
  PIN n_b[453]
    DIRECTION INPUT ;
    USE SIGNAL ;
    PORT
      LAYER M4 ;
        RECT 0.000 249.216 0.192 249.240 ;
    END
  END n_b[453]
  PIN n_b[454]
    DIRECTION INPUT ;
    USE SIGNAL ;
    PORT
      LAYER M4 ;
        RECT 0.000 249.408 0.192 249.432 ;
    END
  END n_b[454]
  PIN n_b[455]
    DIRECTION INPUT ;
    USE SIGNAL ;
    PORT
      LAYER M4 ;
        RECT 0.000 249.600 0.192 249.624 ;
    END
  END n_b[455]
  PIN n_b[456]
    DIRECTION INPUT ;
    USE SIGNAL ;
    PORT
      LAYER M4 ;
        RECT 0.000 249.792 0.192 249.816 ;
    END
  END n_b[456]
  PIN n_b[457]
    DIRECTION INPUT ;
    USE SIGNAL ;
    PORT
      LAYER M4 ;
        RECT 0.000 249.984 0.192 250.008 ;
    END
  END n_b[457]
  PIN n_b[458]
    DIRECTION INPUT ;
    USE SIGNAL ;
    PORT
      LAYER M4 ;
        RECT 0.000 250.176 0.192 250.200 ;
    END
  END n_b[458]
  PIN n_b[459]
    DIRECTION INPUT ;
    USE SIGNAL ;
    PORT
      LAYER M4 ;
        RECT 0.000 250.368 0.192 250.392 ;
    END
  END n_b[459]
  PIN n_b[460]
    DIRECTION INPUT ;
    USE SIGNAL ;
    PORT
      LAYER M4 ;
        RECT 0.000 250.560 0.192 250.584 ;
    END
  END n_b[460]
  PIN n_b[461]
    DIRECTION INPUT ;
    USE SIGNAL ;
    PORT
      LAYER M4 ;
        RECT 0.000 250.752 0.192 250.776 ;
    END
  END n_b[461]
  PIN n_b[462]
    DIRECTION INPUT ;
    USE SIGNAL ;
    PORT
      LAYER M4 ;
        RECT 0.000 250.944 0.192 250.968 ;
    END
  END n_b[462]
  PIN n_b[463]
    DIRECTION INPUT ;
    USE SIGNAL ;
    PORT
      LAYER M4 ;
        RECT 0.000 251.136 0.192 251.160 ;
    END
  END n_b[463]
  PIN n_b[464]
    DIRECTION INPUT ;
    USE SIGNAL ;
    PORT
      LAYER M4 ;
        RECT 0.000 251.328 0.192 251.352 ;
    END
  END n_b[464]
  PIN n_b[465]
    DIRECTION INPUT ;
    USE SIGNAL ;
    PORT
      LAYER M4 ;
        RECT 0.000 251.520 0.192 251.544 ;
    END
  END n_b[465]
  PIN n_b[466]
    DIRECTION INPUT ;
    USE SIGNAL ;
    PORT
      LAYER M4 ;
        RECT 0.000 251.712 0.192 251.736 ;
    END
  END n_b[466]
  PIN n_b[467]
    DIRECTION INPUT ;
    USE SIGNAL ;
    PORT
      LAYER M4 ;
        RECT 0.000 251.904 0.192 251.928 ;
    END
  END n_b[467]
  PIN n_b[468]
    DIRECTION INPUT ;
    USE SIGNAL ;
    PORT
      LAYER M4 ;
        RECT 0.000 252.096 0.192 252.120 ;
    END
  END n_b[468]
  PIN n_b[469]
    DIRECTION INPUT ;
    USE SIGNAL ;
    PORT
      LAYER M4 ;
        RECT 0.000 252.288 0.192 252.312 ;
    END
  END n_b[469]
  PIN n_b[470]
    DIRECTION INPUT ;
    USE SIGNAL ;
    PORT
      LAYER M4 ;
        RECT 0.000 252.480 0.192 252.504 ;
    END
  END n_b[470]
  PIN n_b[471]
    DIRECTION INPUT ;
    USE SIGNAL ;
    PORT
      LAYER M4 ;
        RECT 0.000 252.672 0.192 252.696 ;
    END
  END n_b[471]
  PIN n_b[472]
    DIRECTION INPUT ;
    USE SIGNAL ;
    PORT
      LAYER M4 ;
        RECT 0.000 252.864 0.192 252.888 ;
    END
  END n_b[472]
  PIN n_b[473]
    DIRECTION INPUT ;
    USE SIGNAL ;
    PORT
      LAYER M4 ;
        RECT 0.000 253.056 0.192 253.080 ;
    END
  END n_b[473]
  PIN n_b[474]
    DIRECTION INPUT ;
    USE SIGNAL ;
    PORT
      LAYER M4 ;
        RECT 0.000 253.248 0.192 253.272 ;
    END
  END n_b[474]
  PIN n_b[475]
    DIRECTION INPUT ;
    USE SIGNAL ;
    PORT
      LAYER M4 ;
        RECT 0.000 253.440 0.192 253.464 ;
    END
  END n_b[475]
  PIN n_b[476]
    DIRECTION INPUT ;
    USE SIGNAL ;
    PORT
      LAYER M4 ;
        RECT 0.000 253.632 0.192 253.656 ;
    END
  END n_b[476]
  PIN n_b[477]
    DIRECTION INPUT ;
    USE SIGNAL ;
    PORT
      LAYER M4 ;
        RECT 0.000 253.824 0.192 253.848 ;
    END
  END n_b[477]
  PIN n_b[478]
    DIRECTION INPUT ;
    USE SIGNAL ;
    PORT
      LAYER M4 ;
        RECT 0.000 254.016 0.192 254.040 ;
    END
  END n_b[478]
  PIN n_b[479]
    DIRECTION INPUT ;
    USE SIGNAL ;
    PORT
      LAYER M4 ;
        RECT 0.000 254.208 0.192 254.232 ;
    END
  END n_b[479]
  PIN n_b[480]
    DIRECTION INPUT ;
    USE SIGNAL ;
    PORT
      LAYER M4 ;
        RECT 0.000 254.400 0.192 254.424 ;
    END
  END n_b[480]
  PIN n_b[481]
    DIRECTION INPUT ;
    USE SIGNAL ;
    PORT
      LAYER M4 ;
        RECT 0.000 254.592 0.192 254.616 ;
    END
  END n_b[481]
  PIN n_b[482]
    DIRECTION INPUT ;
    USE SIGNAL ;
    PORT
      LAYER M4 ;
        RECT 0.000 254.784 0.192 254.808 ;
    END
  END n_b[482]
  PIN n_b[483]
    DIRECTION INPUT ;
    USE SIGNAL ;
    PORT
      LAYER M4 ;
        RECT 0.000 254.976 0.192 255.000 ;
    END
  END n_b[483]
  PIN n_b[484]
    DIRECTION INPUT ;
    USE SIGNAL ;
    PORT
      LAYER M4 ;
        RECT 0.000 255.168 0.192 255.192 ;
    END
  END n_b[484]
  PIN n_b[485]
    DIRECTION INPUT ;
    USE SIGNAL ;
    PORT
      LAYER M4 ;
        RECT 0.000 255.360 0.192 255.384 ;
    END
  END n_b[485]
  PIN n_b[486]
    DIRECTION INPUT ;
    USE SIGNAL ;
    PORT
      LAYER M4 ;
        RECT 0.000 255.552 0.192 255.576 ;
    END
  END n_b[486]
  PIN n_b[487]
    DIRECTION INPUT ;
    USE SIGNAL ;
    PORT
      LAYER M4 ;
        RECT 0.000 255.744 0.192 255.768 ;
    END
  END n_b[487]
  PIN n_b[488]
    DIRECTION INPUT ;
    USE SIGNAL ;
    PORT
      LAYER M4 ;
        RECT 0.000 255.936 0.192 255.960 ;
    END
  END n_b[488]
  PIN n_b[489]
    DIRECTION INPUT ;
    USE SIGNAL ;
    PORT
      LAYER M4 ;
        RECT 0.000 256.128 0.192 256.152 ;
    END
  END n_b[489]
  PIN n_b[490]
    DIRECTION INPUT ;
    USE SIGNAL ;
    PORT
      LAYER M4 ;
        RECT 0.000 256.320 0.192 256.344 ;
    END
  END n_b[490]
  PIN n_b[491]
    DIRECTION INPUT ;
    USE SIGNAL ;
    PORT
      LAYER M4 ;
        RECT 0.000 256.512 0.192 256.536 ;
    END
  END n_b[491]
  PIN n_b[492]
    DIRECTION INPUT ;
    USE SIGNAL ;
    PORT
      LAYER M4 ;
        RECT 0.000 256.704 0.192 256.728 ;
    END
  END n_b[492]
  PIN n_b[493]
    DIRECTION INPUT ;
    USE SIGNAL ;
    PORT
      LAYER M4 ;
        RECT 0.000 256.896 0.192 256.920 ;
    END
  END n_b[493]
  PIN n_b[494]
    DIRECTION INPUT ;
    USE SIGNAL ;
    PORT
      LAYER M4 ;
        RECT 0.000 257.088 0.192 257.112 ;
    END
  END n_b[494]
  PIN n_b[495]
    DIRECTION INPUT ;
    USE SIGNAL ;
    PORT
      LAYER M4 ;
        RECT 0.000 257.280 0.192 257.304 ;
    END
  END n_b[495]
  PIN n_b[496]
    DIRECTION INPUT ;
    USE SIGNAL ;
    PORT
      LAYER M4 ;
        RECT 0.000 257.472 0.192 257.496 ;
    END
  END n_b[496]
  PIN n_b[497]
    DIRECTION INPUT ;
    USE SIGNAL ;
    PORT
      LAYER M4 ;
        RECT 0.000 257.664 0.192 257.688 ;
    END
  END n_b[497]
  PIN n_b[498]
    DIRECTION INPUT ;
    USE SIGNAL ;
    PORT
      LAYER M4 ;
        RECT 0.000 257.856 0.192 257.880 ;
    END
  END n_b[498]
  PIN n_b[499]
    DIRECTION INPUT ;
    USE SIGNAL ;
    PORT
      LAYER M4 ;
        RECT 0.000 258.048 0.192 258.072 ;
    END
  END n_b[499]
  PIN n_b[500]
    DIRECTION INPUT ;
    USE SIGNAL ;
    PORT
      LAYER M4 ;
        RECT 0.000 258.240 0.192 258.264 ;
    END
  END n_b[500]
  PIN n_b[501]
    DIRECTION INPUT ;
    USE SIGNAL ;
    PORT
      LAYER M4 ;
        RECT 0.000 258.432 0.192 258.456 ;
    END
  END n_b[501]
  PIN n_b[502]
    DIRECTION INPUT ;
    USE SIGNAL ;
    PORT
      LAYER M4 ;
        RECT 0.000 258.624 0.192 258.648 ;
    END
  END n_b[502]
  PIN n_b[503]
    DIRECTION INPUT ;
    USE SIGNAL ;
    PORT
      LAYER M4 ;
        RECT 0.000 258.816 0.192 258.840 ;
    END
  END n_b[503]
  PIN n_b[504]
    DIRECTION INPUT ;
    USE SIGNAL ;
    PORT
      LAYER M4 ;
        RECT 0.000 259.008 0.192 259.032 ;
    END
  END n_b[504]
  PIN n_b[505]
    DIRECTION INPUT ;
    USE SIGNAL ;
    PORT
      LAYER M4 ;
        RECT 0.000 259.200 0.192 259.224 ;
    END
  END n_b[505]
  PIN n_b[506]
    DIRECTION INPUT ;
    USE SIGNAL ;
    PORT
      LAYER M4 ;
        RECT 0.000 259.392 0.192 259.416 ;
    END
  END n_b[506]
  PIN n_b[507]
    DIRECTION INPUT ;
    USE SIGNAL ;
    PORT
      LAYER M4 ;
        RECT 0.000 259.584 0.192 259.608 ;
    END
  END n_b[507]
  PIN n_b[508]
    DIRECTION INPUT ;
    USE SIGNAL ;
    PORT
      LAYER M4 ;
        RECT 0.000 259.776 0.192 259.800 ;
    END
  END n_b[508]
  PIN n_b[509]
    DIRECTION INPUT ;
    USE SIGNAL ;
    PORT
      LAYER M4 ;
        RECT 0.000 259.968 0.192 259.992 ;
    END
  END n_b[509]
  PIN n_b[510]
    DIRECTION INPUT ;
    USE SIGNAL ;
    PORT
      LAYER M4 ;
        RECT 0.000 260.160 0.192 260.184 ;
    END
  END n_b[510]
  PIN n_b[511]
    DIRECTION INPUT ;
    USE SIGNAL ;
    PORT
      LAYER M4 ;
        RECT 0.000 260.352 0.192 260.376 ;
    END
  END n_b[511]
  PIN n_b[512]
    DIRECTION INPUT ;
    USE SIGNAL ;
    PORT
      LAYER M4 ;
        RECT 0.000 260.544 0.192 260.568 ;
    END
  END n_b[512]
  PIN n_b[513]
    DIRECTION INPUT ;
    USE SIGNAL ;
    PORT
      LAYER M4 ;
        RECT 0.000 260.736 0.192 260.760 ;
    END
  END n_b[513]
  PIN t_out[0]
    DIRECTION OUTPUT ;
    USE SIGNAL ;
    PORT
      LAYER M4 ;
        RECT 0.000 262.752 0.192 262.776 ;
    END
  END t_out[0]
  PIN t_out[1]
    DIRECTION OUTPUT ;
    USE SIGNAL ;
    PORT
      LAYER M4 ;
        RECT 0.000 262.944 0.192 262.968 ;
    END
  END t_out[1]
  PIN t_out[2]
    DIRECTION OUTPUT ;
    USE SIGNAL ;
    PORT
      LAYER M4 ;
        RECT 0.000 263.136 0.192 263.160 ;
    END
  END t_out[2]
  PIN t_out[3]
    DIRECTION OUTPUT ;
    USE SIGNAL ;
    PORT
      LAYER M4 ;
        RECT 0.000 263.328 0.192 263.352 ;
    END
  END t_out[3]
  PIN t_out[4]
    DIRECTION OUTPUT ;
    USE SIGNAL ;
    PORT
      LAYER M4 ;
        RECT 0.000 263.520 0.192 263.544 ;
    END
  END t_out[4]
  PIN t_out[5]
    DIRECTION OUTPUT ;
    USE SIGNAL ;
    PORT
      LAYER M4 ;
        RECT 0.000 263.712 0.192 263.736 ;
    END
  END t_out[5]
  PIN t_out[6]
    DIRECTION OUTPUT ;
    USE SIGNAL ;
    PORT
      LAYER M4 ;
        RECT 0.000 263.904 0.192 263.928 ;
    END
  END t_out[6]
  PIN t_out[7]
    DIRECTION OUTPUT ;
    USE SIGNAL ;
    PORT
      LAYER M4 ;
        RECT 0.000 264.096 0.192 264.120 ;
    END
  END t_out[7]
  PIN t_out[8]
    DIRECTION OUTPUT ;
    USE SIGNAL ;
    PORT
      LAYER M4 ;
        RECT 0.000 264.288 0.192 264.312 ;
    END
  END t_out[8]
  PIN t_out[9]
    DIRECTION OUTPUT ;
    USE SIGNAL ;
    PORT
      LAYER M4 ;
        RECT 0.000 264.480 0.192 264.504 ;
    END
  END t_out[9]
  PIN t_out[10]
    DIRECTION OUTPUT ;
    USE SIGNAL ;
    PORT
      LAYER M4 ;
        RECT 0.000 264.672 0.192 264.696 ;
    END
  END t_out[10]
  PIN t_out[11]
    DIRECTION OUTPUT ;
    USE SIGNAL ;
    PORT
      LAYER M4 ;
        RECT 0.000 264.864 0.192 264.888 ;
    END
  END t_out[11]
  PIN t_out[12]
    DIRECTION OUTPUT ;
    USE SIGNAL ;
    PORT
      LAYER M4 ;
        RECT 0.000 265.056 0.192 265.080 ;
    END
  END t_out[12]
  PIN t_out[13]
    DIRECTION OUTPUT ;
    USE SIGNAL ;
    PORT
      LAYER M4 ;
        RECT 0.000 265.248 0.192 265.272 ;
    END
  END t_out[13]
  PIN t_out[14]
    DIRECTION OUTPUT ;
    USE SIGNAL ;
    PORT
      LAYER M4 ;
        RECT 0.000 265.440 0.192 265.464 ;
    END
  END t_out[14]
  PIN t_out[15]
    DIRECTION OUTPUT ;
    USE SIGNAL ;
    PORT
      LAYER M4 ;
        RECT 0.000 265.632 0.192 265.656 ;
    END
  END t_out[15]
  PIN t_out[16]
    DIRECTION OUTPUT ;
    USE SIGNAL ;
    PORT
      LAYER M4 ;
        RECT 0.000 265.824 0.192 265.848 ;
    END
  END t_out[16]
  PIN t_out[17]
    DIRECTION OUTPUT ;
    USE SIGNAL ;
    PORT
      LAYER M4 ;
        RECT 0.000 266.016 0.192 266.040 ;
    END
  END t_out[17]
  PIN t_out[18]
    DIRECTION OUTPUT ;
    USE SIGNAL ;
    PORT
      LAYER M4 ;
        RECT 0.000 266.208 0.192 266.232 ;
    END
  END t_out[18]
  PIN t_out[19]
    DIRECTION OUTPUT ;
    USE SIGNAL ;
    PORT
      LAYER M4 ;
        RECT 0.000 266.400 0.192 266.424 ;
    END
  END t_out[19]
  PIN t_out[20]
    DIRECTION OUTPUT ;
    USE SIGNAL ;
    PORT
      LAYER M4 ;
        RECT 0.000 266.592 0.192 266.616 ;
    END
  END t_out[20]
  PIN t_out[21]
    DIRECTION OUTPUT ;
    USE SIGNAL ;
    PORT
      LAYER M4 ;
        RECT 0.000 266.784 0.192 266.808 ;
    END
  END t_out[21]
  PIN t_out[22]
    DIRECTION OUTPUT ;
    USE SIGNAL ;
    PORT
      LAYER M4 ;
        RECT 0.000 266.976 0.192 267.000 ;
    END
  END t_out[22]
  PIN t_out[23]
    DIRECTION OUTPUT ;
    USE SIGNAL ;
    PORT
      LAYER M4 ;
        RECT 0.000 267.168 0.192 267.192 ;
    END
  END t_out[23]
  PIN t_out[24]
    DIRECTION OUTPUT ;
    USE SIGNAL ;
    PORT
      LAYER M4 ;
        RECT 0.000 267.360 0.192 267.384 ;
    END
  END t_out[24]
  PIN t_out[25]
    DIRECTION OUTPUT ;
    USE SIGNAL ;
    PORT
      LAYER M4 ;
        RECT 0.000 267.552 0.192 267.576 ;
    END
  END t_out[25]
  PIN t_out[26]
    DIRECTION OUTPUT ;
    USE SIGNAL ;
    PORT
      LAYER M4 ;
        RECT 0.000 267.744 0.192 267.768 ;
    END
  END t_out[26]
  PIN t_out[27]
    DIRECTION OUTPUT ;
    USE SIGNAL ;
    PORT
      LAYER M4 ;
        RECT 0.000 267.936 0.192 267.960 ;
    END
  END t_out[27]
  PIN t_out[28]
    DIRECTION OUTPUT ;
    USE SIGNAL ;
    PORT
      LAYER M4 ;
        RECT 0.000 268.128 0.192 268.152 ;
    END
  END t_out[28]
  PIN t_out[29]
    DIRECTION OUTPUT ;
    USE SIGNAL ;
    PORT
      LAYER M4 ;
        RECT 0.000 268.320 0.192 268.344 ;
    END
  END t_out[29]
  PIN t_out[30]
    DIRECTION OUTPUT ;
    USE SIGNAL ;
    PORT
      LAYER M4 ;
        RECT 0.000 268.512 0.192 268.536 ;
    END
  END t_out[30]
  PIN t_out[31]
    DIRECTION OUTPUT ;
    USE SIGNAL ;
    PORT
      LAYER M4 ;
        RECT 0.000 268.704 0.192 268.728 ;
    END
  END t_out[31]
  PIN t_out[32]
    DIRECTION OUTPUT ;
    USE SIGNAL ;
    PORT
      LAYER M4 ;
        RECT 0.000 268.896 0.192 268.920 ;
    END
  END t_out[32]
  PIN t_out[33]
    DIRECTION OUTPUT ;
    USE SIGNAL ;
    PORT
      LAYER M4 ;
        RECT 0.000 269.088 0.192 269.112 ;
    END
  END t_out[33]
  PIN t_out[34]
    DIRECTION OUTPUT ;
    USE SIGNAL ;
    PORT
      LAYER M4 ;
        RECT 0.000 269.280 0.192 269.304 ;
    END
  END t_out[34]
  PIN t_out[35]
    DIRECTION OUTPUT ;
    USE SIGNAL ;
    PORT
      LAYER M4 ;
        RECT 0.000 269.472 0.192 269.496 ;
    END
  END t_out[35]
  PIN t_out[36]
    DIRECTION OUTPUT ;
    USE SIGNAL ;
    PORT
      LAYER M4 ;
        RECT 0.000 269.664 0.192 269.688 ;
    END
  END t_out[36]
  PIN t_out[37]
    DIRECTION OUTPUT ;
    USE SIGNAL ;
    PORT
      LAYER M4 ;
        RECT 0.000 269.856 0.192 269.880 ;
    END
  END t_out[37]
  PIN t_out[38]
    DIRECTION OUTPUT ;
    USE SIGNAL ;
    PORT
      LAYER M4 ;
        RECT 0.000 270.048 0.192 270.072 ;
    END
  END t_out[38]
  PIN t_out[39]
    DIRECTION OUTPUT ;
    USE SIGNAL ;
    PORT
      LAYER M4 ;
        RECT 0.000 270.240 0.192 270.264 ;
    END
  END t_out[39]
  PIN t_out[40]
    DIRECTION OUTPUT ;
    USE SIGNAL ;
    PORT
      LAYER M4 ;
        RECT 0.000 270.432 0.192 270.456 ;
    END
  END t_out[40]
  PIN t_out[41]
    DIRECTION OUTPUT ;
    USE SIGNAL ;
    PORT
      LAYER M4 ;
        RECT 0.000 270.624 0.192 270.648 ;
    END
  END t_out[41]
  PIN t_out[42]
    DIRECTION OUTPUT ;
    USE SIGNAL ;
    PORT
      LAYER M4 ;
        RECT 0.000 270.816 0.192 270.840 ;
    END
  END t_out[42]
  PIN t_out[43]
    DIRECTION OUTPUT ;
    USE SIGNAL ;
    PORT
      LAYER M4 ;
        RECT 0.000 271.008 0.192 271.032 ;
    END
  END t_out[43]
  PIN t_out[44]
    DIRECTION OUTPUT ;
    USE SIGNAL ;
    PORT
      LAYER M4 ;
        RECT 0.000 271.200 0.192 271.224 ;
    END
  END t_out[44]
  PIN t_out[45]
    DIRECTION OUTPUT ;
    USE SIGNAL ;
    PORT
      LAYER M4 ;
        RECT 0.000 271.392 0.192 271.416 ;
    END
  END t_out[45]
  PIN t_out[46]
    DIRECTION OUTPUT ;
    USE SIGNAL ;
    PORT
      LAYER M4 ;
        RECT 0.000 271.584 0.192 271.608 ;
    END
  END t_out[46]
  PIN t_out[47]
    DIRECTION OUTPUT ;
    USE SIGNAL ;
    PORT
      LAYER M4 ;
        RECT 0.000 271.776 0.192 271.800 ;
    END
  END t_out[47]
  PIN t_out[48]
    DIRECTION OUTPUT ;
    USE SIGNAL ;
    PORT
      LAYER M4 ;
        RECT 0.000 271.968 0.192 271.992 ;
    END
  END t_out[48]
  PIN t_out[49]
    DIRECTION OUTPUT ;
    USE SIGNAL ;
    PORT
      LAYER M4 ;
        RECT 0.000 272.160 0.192 272.184 ;
    END
  END t_out[49]
  PIN t_out[50]
    DIRECTION OUTPUT ;
    USE SIGNAL ;
    PORT
      LAYER M4 ;
        RECT 0.000 272.352 0.192 272.376 ;
    END
  END t_out[50]
  PIN t_out[51]
    DIRECTION OUTPUT ;
    USE SIGNAL ;
    PORT
      LAYER M4 ;
        RECT 0.000 272.544 0.192 272.568 ;
    END
  END t_out[51]
  PIN t_out[52]
    DIRECTION OUTPUT ;
    USE SIGNAL ;
    PORT
      LAYER M4 ;
        RECT 0.000 272.736 0.192 272.760 ;
    END
  END t_out[52]
  PIN t_out[53]
    DIRECTION OUTPUT ;
    USE SIGNAL ;
    PORT
      LAYER M4 ;
        RECT 0.000 272.928 0.192 272.952 ;
    END
  END t_out[53]
  PIN t_out[54]
    DIRECTION OUTPUT ;
    USE SIGNAL ;
    PORT
      LAYER M4 ;
        RECT 0.000 273.120 0.192 273.144 ;
    END
  END t_out[54]
  PIN t_out[55]
    DIRECTION OUTPUT ;
    USE SIGNAL ;
    PORT
      LAYER M4 ;
        RECT 0.000 273.312 0.192 273.336 ;
    END
  END t_out[55]
  PIN t_out[56]
    DIRECTION OUTPUT ;
    USE SIGNAL ;
    PORT
      LAYER M4 ;
        RECT 0.000 273.504 0.192 273.528 ;
    END
  END t_out[56]
  PIN t_out[57]
    DIRECTION OUTPUT ;
    USE SIGNAL ;
    PORT
      LAYER M4 ;
        RECT 0.000 273.696 0.192 273.720 ;
    END
  END t_out[57]
  PIN t_out[58]
    DIRECTION OUTPUT ;
    USE SIGNAL ;
    PORT
      LAYER M4 ;
        RECT 0.000 273.888 0.192 273.912 ;
    END
  END t_out[58]
  PIN t_out[59]
    DIRECTION OUTPUT ;
    USE SIGNAL ;
    PORT
      LAYER M4 ;
        RECT 0.000 274.080 0.192 274.104 ;
    END
  END t_out[59]
  PIN t_out[60]
    DIRECTION OUTPUT ;
    USE SIGNAL ;
    PORT
      LAYER M4 ;
        RECT 0.000 274.272 0.192 274.296 ;
    END
  END t_out[60]
  PIN t_out[61]
    DIRECTION OUTPUT ;
    USE SIGNAL ;
    PORT
      LAYER M4 ;
        RECT 0.000 274.464 0.192 274.488 ;
    END
  END t_out[61]
  PIN t_out[62]
    DIRECTION OUTPUT ;
    USE SIGNAL ;
    PORT
      LAYER M4 ;
        RECT 0.000 274.656 0.192 274.680 ;
    END
  END t_out[62]
  PIN t_out[63]
    DIRECTION OUTPUT ;
    USE SIGNAL ;
    PORT
      LAYER M4 ;
        RECT 0.000 274.848 0.192 274.872 ;
    END
  END t_out[63]
  PIN t_out[64]
    DIRECTION OUTPUT ;
    USE SIGNAL ;
    PORT
      LAYER M4 ;
        RECT 0.000 275.040 0.192 275.064 ;
    END
  END t_out[64]
  PIN t_out[65]
    DIRECTION OUTPUT ;
    USE SIGNAL ;
    PORT
      LAYER M4 ;
        RECT 0.000 275.232 0.192 275.256 ;
    END
  END t_out[65]
  PIN t_out[66]
    DIRECTION OUTPUT ;
    USE SIGNAL ;
    PORT
      LAYER M4 ;
        RECT 0.000 275.424 0.192 275.448 ;
    END
  END t_out[66]
  PIN t_out[67]
    DIRECTION OUTPUT ;
    USE SIGNAL ;
    PORT
      LAYER M4 ;
        RECT 0.000 275.616 0.192 275.640 ;
    END
  END t_out[67]
  PIN t_out[68]
    DIRECTION OUTPUT ;
    USE SIGNAL ;
    PORT
      LAYER M4 ;
        RECT 0.000 275.808 0.192 275.832 ;
    END
  END t_out[68]
  PIN t_out[69]
    DIRECTION OUTPUT ;
    USE SIGNAL ;
    PORT
      LAYER M4 ;
        RECT 0.000 276.000 0.192 276.024 ;
    END
  END t_out[69]
  PIN t_out[70]
    DIRECTION OUTPUT ;
    USE SIGNAL ;
    PORT
      LAYER M4 ;
        RECT 0.000 276.192 0.192 276.216 ;
    END
  END t_out[70]
  PIN t_out[71]
    DIRECTION OUTPUT ;
    USE SIGNAL ;
    PORT
      LAYER M4 ;
        RECT 0.000 276.384 0.192 276.408 ;
    END
  END t_out[71]
  PIN t_out[72]
    DIRECTION OUTPUT ;
    USE SIGNAL ;
    PORT
      LAYER M4 ;
        RECT 0.000 276.576 0.192 276.600 ;
    END
  END t_out[72]
  PIN t_out[73]
    DIRECTION OUTPUT ;
    USE SIGNAL ;
    PORT
      LAYER M4 ;
        RECT 0.000 276.768 0.192 276.792 ;
    END
  END t_out[73]
  PIN t_out[74]
    DIRECTION OUTPUT ;
    USE SIGNAL ;
    PORT
      LAYER M4 ;
        RECT 0.000 276.960 0.192 276.984 ;
    END
  END t_out[74]
  PIN t_out[75]
    DIRECTION OUTPUT ;
    USE SIGNAL ;
    PORT
      LAYER M4 ;
        RECT 0.000 277.152 0.192 277.176 ;
    END
  END t_out[75]
  PIN t_out[76]
    DIRECTION OUTPUT ;
    USE SIGNAL ;
    PORT
      LAYER M4 ;
        RECT 0.000 277.344 0.192 277.368 ;
    END
  END t_out[76]
  PIN t_out[77]
    DIRECTION OUTPUT ;
    USE SIGNAL ;
    PORT
      LAYER M4 ;
        RECT 0.000 277.536 0.192 277.560 ;
    END
  END t_out[77]
  PIN t_out[78]
    DIRECTION OUTPUT ;
    USE SIGNAL ;
    PORT
      LAYER M4 ;
        RECT 0.000 277.728 0.192 277.752 ;
    END
  END t_out[78]
  PIN t_out[79]
    DIRECTION OUTPUT ;
    USE SIGNAL ;
    PORT
      LAYER M4 ;
        RECT 0.000 277.920 0.192 277.944 ;
    END
  END t_out[79]
  PIN t_out[80]
    DIRECTION OUTPUT ;
    USE SIGNAL ;
    PORT
      LAYER M4 ;
        RECT 0.000 278.112 0.192 278.136 ;
    END
  END t_out[80]
  PIN t_out[81]
    DIRECTION OUTPUT ;
    USE SIGNAL ;
    PORT
      LAYER M4 ;
        RECT 0.000 278.304 0.192 278.328 ;
    END
  END t_out[81]
  PIN t_out[82]
    DIRECTION OUTPUT ;
    USE SIGNAL ;
    PORT
      LAYER M4 ;
        RECT 0.000 278.496 0.192 278.520 ;
    END
  END t_out[82]
  PIN t_out[83]
    DIRECTION OUTPUT ;
    USE SIGNAL ;
    PORT
      LAYER M4 ;
        RECT 0.000 278.688 0.192 278.712 ;
    END
  END t_out[83]
  PIN t_out[84]
    DIRECTION OUTPUT ;
    USE SIGNAL ;
    PORT
      LAYER M4 ;
        RECT 0.000 278.880 0.192 278.904 ;
    END
  END t_out[84]
  PIN t_out[85]
    DIRECTION OUTPUT ;
    USE SIGNAL ;
    PORT
      LAYER M4 ;
        RECT 0.000 279.072 0.192 279.096 ;
    END
  END t_out[85]
  PIN t_out[86]
    DIRECTION OUTPUT ;
    USE SIGNAL ;
    PORT
      LAYER M4 ;
        RECT 0.000 279.264 0.192 279.288 ;
    END
  END t_out[86]
  PIN t_out[87]
    DIRECTION OUTPUT ;
    USE SIGNAL ;
    PORT
      LAYER M4 ;
        RECT 0.000 279.456 0.192 279.480 ;
    END
  END t_out[87]
  PIN t_out[88]
    DIRECTION OUTPUT ;
    USE SIGNAL ;
    PORT
      LAYER M4 ;
        RECT 0.000 279.648 0.192 279.672 ;
    END
  END t_out[88]
  PIN t_out[89]
    DIRECTION OUTPUT ;
    USE SIGNAL ;
    PORT
      LAYER M4 ;
        RECT 0.000 279.840 0.192 279.864 ;
    END
  END t_out[89]
  PIN t_out[90]
    DIRECTION OUTPUT ;
    USE SIGNAL ;
    PORT
      LAYER M4 ;
        RECT 0.000 280.032 0.192 280.056 ;
    END
  END t_out[90]
  PIN t_out[91]
    DIRECTION OUTPUT ;
    USE SIGNAL ;
    PORT
      LAYER M4 ;
        RECT 0.000 280.224 0.192 280.248 ;
    END
  END t_out[91]
  PIN t_out[92]
    DIRECTION OUTPUT ;
    USE SIGNAL ;
    PORT
      LAYER M4 ;
        RECT 0.000 280.416 0.192 280.440 ;
    END
  END t_out[92]
  PIN t_out[93]
    DIRECTION OUTPUT ;
    USE SIGNAL ;
    PORT
      LAYER M4 ;
        RECT 0.000 280.608 0.192 280.632 ;
    END
  END t_out[93]
  PIN t_out[94]
    DIRECTION OUTPUT ;
    USE SIGNAL ;
    PORT
      LAYER M4 ;
        RECT 0.000 280.800 0.192 280.824 ;
    END
  END t_out[94]
  PIN t_out[95]
    DIRECTION OUTPUT ;
    USE SIGNAL ;
    PORT
      LAYER M4 ;
        RECT 0.000 280.992 0.192 281.016 ;
    END
  END t_out[95]
  PIN t_out[96]
    DIRECTION OUTPUT ;
    USE SIGNAL ;
    PORT
      LAYER M4 ;
        RECT 0.000 281.184 0.192 281.208 ;
    END
  END t_out[96]
  PIN t_out[97]
    DIRECTION OUTPUT ;
    USE SIGNAL ;
    PORT
      LAYER M4 ;
        RECT 0.000 281.376 0.192 281.400 ;
    END
  END t_out[97]
  PIN t_out[98]
    DIRECTION OUTPUT ;
    USE SIGNAL ;
    PORT
      LAYER M4 ;
        RECT 0.000 281.568 0.192 281.592 ;
    END
  END t_out[98]
  PIN t_out[99]
    DIRECTION OUTPUT ;
    USE SIGNAL ;
    PORT
      LAYER M4 ;
        RECT 0.000 281.760 0.192 281.784 ;
    END
  END t_out[99]
  PIN t_out[100]
    DIRECTION OUTPUT ;
    USE SIGNAL ;
    PORT
      LAYER M4 ;
        RECT 0.000 281.952 0.192 281.976 ;
    END
  END t_out[100]
  PIN t_out[101]
    DIRECTION OUTPUT ;
    USE SIGNAL ;
    PORT
      LAYER M4 ;
        RECT 0.000 282.144 0.192 282.168 ;
    END
  END t_out[101]
  PIN t_out[102]
    DIRECTION OUTPUT ;
    USE SIGNAL ;
    PORT
      LAYER M4 ;
        RECT 0.000 282.336 0.192 282.360 ;
    END
  END t_out[102]
  PIN t_out[103]
    DIRECTION OUTPUT ;
    USE SIGNAL ;
    PORT
      LAYER M4 ;
        RECT 0.000 282.528 0.192 282.552 ;
    END
  END t_out[103]
  PIN t_out[104]
    DIRECTION OUTPUT ;
    USE SIGNAL ;
    PORT
      LAYER M4 ;
        RECT 0.000 282.720 0.192 282.744 ;
    END
  END t_out[104]
  PIN t_out[105]
    DIRECTION OUTPUT ;
    USE SIGNAL ;
    PORT
      LAYER M4 ;
        RECT 0.000 282.912 0.192 282.936 ;
    END
  END t_out[105]
  PIN t_out[106]
    DIRECTION OUTPUT ;
    USE SIGNAL ;
    PORT
      LAYER M4 ;
        RECT 0.000 283.104 0.192 283.128 ;
    END
  END t_out[106]
  PIN t_out[107]
    DIRECTION OUTPUT ;
    USE SIGNAL ;
    PORT
      LAYER M4 ;
        RECT 0.000 283.296 0.192 283.320 ;
    END
  END t_out[107]
  PIN t_out[108]
    DIRECTION OUTPUT ;
    USE SIGNAL ;
    PORT
      LAYER M4 ;
        RECT 0.000 283.488 0.192 283.512 ;
    END
  END t_out[108]
  PIN t_out[109]
    DIRECTION OUTPUT ;
    USE SIGNAL ;
    PORT
      LAYER M4 ;
        RECT 0.000 283.680 0.192 283.704 ;
    END
  END t_out[109]
  PIN t_out[110]
    DIRECTION OUTPUT ;
    USE SIGNAL ;
    PORT
      LAYER M4 ;
        RECT 0.000 283.872 0.192 283.896 ;
    END
  END t_out[110]
  PIN t_out[111]
    DIRECTION OUTPUT ;
    USE SIGNAL ;
    PORT
      LAYER M4 ;
        RECT 0.000 284.064 0.192 284.088 ;
    END
  END t_out[111]
  PIN t_out[112]
    DIRECTION OUTPUT ;
    USE SIGNAL ;
    PORT
      LAYER M4 ;
        RECT 0.000 284.256 0.192 284.280 ;
    END
  END t_out[112]
  PIN t_out[113]
    DIRECTION OUTPUT ;
    USE SIGNAL ;
    PORT
      LAYER M4 ;
        RECT 0.000 284.448 0.192 284.472 ;
    END
  END t_out[113]
  PIN t_out[114]
    DIRECTION OUTPUT ;
    USE SIGNAL ;
    PORT
      LAYER M4 ;
        RECT 0.000 284.640 0.192 284.664 ;
    END
  END t_out[114]
  PIN t_out[115]
    DIRECTION OUTPUT ;
    USE SIGNAL ;
    PORT
      LAYER M4 ;
        RECT 0.000 284.832 0.192 284.856 ;
    END
  END t_out[115]
  PIN t_out[116]
    DIRECTION OUTPUT ;
    USE SIGNAL ;
    PORT
      LAYER M4 ;
        RECT 0.000 285.024 0.192 285.048 ;
    END
  END t_out[116]
  PIN t_out[117]
    DIRECTION OUTPUT ;
    USE SIGNAL ;
    PORT
      LAYER M4 ;
        RECT 0.000 285.216 0.192 285.240 ;
    END
  END t_out[117]
  PIN t_out[118]
    DIRECTION OUTPUT ;
    USE SIGNAL ;
    PORT
      LAYER M4 ;
        RECT 0.000 285.408 0.192 285.432 ;
    END
  END t_out[118]
  PIN t_out[119]
    DIRECTION OUTPUT ;
    USE SIGNAL ;
    PORT
      LAYER M4 ;
        RECT 0.000 285.600 0.192 285.624 ;
    END
  END t_out[119]
  PIN t_out[120]
    DIRECTION OUTPUT ;
    USE SIGNAL ;
    PORT
      LAYER M4 ;
        RECT 0.000 285.792 0.192 285.816 ;
    END
  END t_out[120]
  PIN t_out[121]
    DIRECTION OUTPUT ;
    USE SIGNAL ;
    PORT
      LAYER M4 ;
        RECT 0.000 285.984 0.192 286.008 ;
    END
  END t_out[121]
  PIN t_out[122]
    DIRECTION OUTPUT ;
    USE SIGNAL ;
    PORT
      LAYER M4 ;
        RECT 0.000 286.176 0.192 286.200 ;
    END
  END t_out[122]
  PIN t_out[123]
    DIRECTION OUTPUT ;
    USE SIGNAL ;
    PORT
      LAYER M4 ;
        RECT 0.000 286.368 0.192 286.392 ;
    END
  END t_out[123]
  PIN t_out[124]
    DIRECTION OUTPUT ;
    USE SIGNAL ;
    PORT
      LAYER M4 ;
        RECT 0.000 286.560 0.192 286.584 ;
    END
  END t_out[124]
  PIN t_out[125]
    DIRECTION OUTPUT ;
    USE SIGNAL ;
    PORT
      LAYER M4 ;
        RECT 0.000 286.752 0.192 286.776 ;
    END
  END t_out[125]
  PIN t_out[126]
    DIRECTION OUTPUT ;
    USE SIGNAL ;
    PORT
      LAYER M4 ;
        RECT 0.000 286.944 0.192 286.968 ;
    END
  END t_out[126]
  PIN t_out[127]
    DIRECTION OUTPUT ;
    USE SIGNAL ;
    PORT
      LAYER M4 ;
        RECT 0.000 287.136 0.192 287.160 ;
    END
  END t_out[127]
  PIN t_out[128]
    DIRECTION OUTPUT ;
    USE SIGNAL ;
    PORT
      LAYER M4 ;
        RECT 0.000 287.328 0.192 287.352 ;
    END
  END t_out[128]
  PIN t_out[129]
    DIRECTION OUTPUT ;
    USE SIGNAL ;
    PORT
      LAYER M4 ;
        RECT 0.000 287.520 0.192 287.544 ;
    END
  END t_out[129]
  PIN t_out[130]
    DIRECTION OUTPUT ;
    USE SIGNAL ;
    PORT
      LAYER M4 ;
        RECT 0.000 287.712 0.192 287.736 ;
    END
  END t_out[130]
  PIN t_out[131]
    DIRECTION OUTPUT ;
    USE SIGNAL ;
    PORT
      LAYER M4 ;
        RECT 0.000 287.904 0.192 287.928 ;
    END
  END t_out[131]
  PIN t_out[132]
    DIRECTION OUTPUT ;
    USE SIGNAL ;
    PORT
      LAYER M4 ;
        RECT 0.000 288.096 0.192 288.120 ;
    END
  END t_out[132]
  PIN t_out[133]
    DIRECTION OUTPUT ;
    USE SIGNAL ;
    PORT
      LAYER M4 ;
        RECT 0.000 288.288 0.192 288.312 ;
    END
  END t_out[133]
  PIN t_out[134]
    DIRECTION OUTPUT ;
    USE SIGNAL ;
    PORT
      LAYER M4 ;
        RECT 0.000 288.480 0.192 288.504 ;
    END
  END t_out[134]
  PIN t_out[135]
    DIRECTION OUTPUT ;
    USE SIGNAL ;
    PORT
      LAYER M4 ;
        RECT 0.000 288.672 0.192 288.696 ;
    END
  END t_out[135]
  PIN t_out[136]
    DIRECTION OUTPUT ;
    USE SIGNAL ;
    PORT
      LAYER M4 ;
        RECT 0.000 288.864 0.192 288.888 ;
    END
  END t_out[136]
  PIN t_out[137]
    DIRECTION OUTPUT ;
    USE SIGNAL ;
    PORT
      LAYER M4 ;
        RECT 0.000 289.056 0.192 289.080 ;
    END
  END t_out[137]
  PIN t_out[138]
    DIRECTION OUTPUT ;
    USE SIGNAL ;
    PORT
      LAYER M4 ;
        RECT 0.000 289.248 0.192 289.272 ;
    END
  END t_out[138]
  PIN t_out[139]
    DIRECTION OUTPUT ;
    USE SIGNAL ;
    PORT
      LAYER M4 ;
        RECT 0.000 289.440 0.192 289.464 ;
    END
  END t_out[139]
  PIN t_out[140]
    DIRECTION OUTPUT ;
    USE SIGNAL ;
    PORT
      LAYER M4 ;
        RECT 0.000 289.632 0.192 289.656 ;
    END
  END t_out[140]
  PIN t_out[141]
    DIRECTION OUTPUT ;
    USE SIGNAL ;
    PORT
      LAYER M4 ;
        RECT 0.000 289.824 0.192 289.848 ;
    END
  END t_out[141]
  PIN t_out[142]
    DIRECTION OUTPUT ;
    USE SIGNAL ;
    PORT
      LAYER M4 ;
        RECT 0.000 290.016 0.192 290.040 ;
    END
  END t_out[142]
  PIN t_out[143]
    DIRECTION OUTPUT ;
    USE SIGNAL ;
    PORT
      LAYER M4 ;
        RECT 0.000 290.208 0.192 290.232 ;
    END
  END t_out[143]
  PIN t_out[144]
    DIRECTION OUTPUT ;
    USE SIGNAL ;
    PORT
      LAYER M4 ;
        RECT 0.000 290.400 0.192 290.424 ;
    END
  END t_out[144]
  PIN t_out[145]
    DIRECTION OUTPUT ;
    USE SIGNAL ;
    PORT
      LAYER M4 ;
        RECT 0.000 290.592 0.192 290.616 ;
    END
  END t_out[145]
  PIN t_out[146]
    DIRECTION OUTPUT ;
    USE SIGNAL ;
    PORT
      LAYER M4 ;
        RECT 0.000 290.784 0.192 290.808 ;
    END
  END t_out[146]
  PIN t_out[147]
    DIRECTION OUTPUT ;
    USE SIGNAL ;
    PORT
      LAYER M4 ;
        RECT 0.000 290.976 0.192 291.000 ;
    END
  END t_out[147]
  PIN t_out[148]
    DIRECTION OUTPUT ;
    USE SIGNAL ;
    PORT
      LAYER M4 ;
        RECT 0.000 291.168 0.192 291.192 ;
    END
  END t_out[148]
  PIN t_out[149]
    DIRECTION OUTPUT ;
    USE SIGNAL ;
    PORT
      LAYER M4 ;
        RECT 0.000 291.360 0.192 291.384 ;
    END
  END t_out[149]
  PIN t_out[150]
    DIRECTION OUTPUT ;
    USE SIGNAL ;
    PORT
      LAYER M4 ;
        RECT 0.000 291.552 0.192 291.576 ;
    END
  END t_out[150]
  PIN t_out[151]
    DIRECTION OUTPUT ;
    USE SIGNAL ;
    PORT
      LAYER M4 ;
        RECT 0.000 291.744 0.192 291.768 ;
    END
  END t_out[151]
  PIN t_out[152]
    DIRECTION OUTPUT ;
    USE SIGNAL ;
    PORT
      LAYER M4 ;
        RECT 0.000 291.936 0.192 291.960 ;
    END
  END t_out[152]
  PIN t_out[153]
    DIRECTION OUTPUT ;
    USE SIGNAL ;
    PORT
      LAYER M4 ;
        RECT 0.000 292.128 0.192 292.152 ;
    END
  END t_out[153]
  PIN t_out[154]
    DIRECTION OUTPUT ;
    USE SIGNAL ;
    PORT
      LAYER M4 ;
        RECT 0.000 292.320 0.192 292.344 ;
    END
  END t_out[154]
  PIN t_out[155]
    DIRECTION OUTPUT ;
    USE SIGNAL ;
    PORT
      LAYER M4 ;
        RECT 0.000 292.512 0.192 292.536 ;
    END
  END t_out[155]
  PIN t_out[156]
    DIRECTION OUTPUT ;
    USE SIGNAL ;
    PORT
      LAYER M4 ;
        RECT 0.000 292.704 0.192 292.728 ;
    END
  END t_out[156]
  PIN t_out[157]
    DIRECTION OUTPUT ;
    USE SIGNAL ;
    PORT
      LAYER M4 ;
        RECT 0.000 292.896 0.192 292.920 ;
    END
  END t_out[157]
  PIN t_out[158]
    DIRECTION OUTPUT ;
    USE SIGNAL ;
    PORT
      LAYER M4 ;
        RECT 0.000 293.088 0.192 293.112 ;
    END
  END t_out[158]
  PIN t_out[159]
    DIRECTION OUTPUT ;
    USE SIGNAL ;
    PORT
      LAYER M4 ;
        RECT 0.000 293.280 0.192 293.304 ;
    END
  END t_out[159]
  PIN t_out[160]
    DIRECTION OUTPUT ;
    USE SIGNAL ;
    PORT
      LAYER M4 ;
        RECT 0.000 293.472 0.192 293.496 ;
    END
  END t_out[160]
  PIN t_out[161]
    DIRECTION OUTPUT ;
    USE SIGNAL ;
    PORT
      LAYER M4 ;
        RECT 0.000 293.664 0.192 293.688 ;
    END
  END t_out[161]
  PIN t_out[162]
    DIRECTION OUTPUT ;
    USE SIGNAL ;
    PORT
      LAYER M4 ;
        RECT 0.000 293.856 0.192 293.880 ;
    END
  END t_out[162]
  PIN t_out[163]
    DIRECTION OUTPUT ;
    USE SIGNAL ;
    PORT
      LAYER M4 ;
        RECT 0.000 294.048 0.192 294.072 ;
    END
  END t_out[163]
  PIN t_out[164]
    DIRECTION OUTPUT ;
    USE SIGNAL ;
    PORT
      LAYER M4 ;
        RECT 0.000 294.240 0.192 294.264 ;
    END
  END t_out[164]
  PIN t_out[165]
    DIRECTION OUTPUT ;
    USE SIGNAL ;
    PORT
      LAYER M4 ;
        RECT 0.000 294.432 0.192 294.456 ;
    END
  END t_out[165]
  PIN t_out[166]
    DIRECTION OUTPUT ;
    USE SIGNAL ;
    PORT
      LAYER M4 ;
        RECT 0.000 294.624 0.192 294.648 ;
    END
  END t_out[166]
  PIN t_out[167]
    DIRECTION OUTPUT ;
    USE SIGNAL ;
    PORT
      LAYER M4 ;
        RECT 0.000 294.816 0.192 294.840 ;
    END
  END t_out[167]
  PIN t_out[168]
    DIRECTION OUTPUT ;
    USE SIGNAL ;
    PORT
      LAYER M4 ;
        RECT 0.000 295.008 0.192 295.032 ;
    END
  END t_out[168]
  PIN t_out[169]
    DIRECTION OUTPUT ;
    USE SIGNAL ;
    PORT
      LAYER M4 ;
        RECT 0.000 295.200 0.192 295.224 ;
    END
  END t_out[169]
  PIN t_out[170]
    DIRECTION OUTPUT ;
    USE SIGNAL ;
    PORT
      LAYER M4 ;
        RECT 0.000 295.392 0.192 295.416 ;
    END
  END t_out[170]
  PIN t_out[171]
    DIRECTION OUTPUT ;
    USE SIGNAL ;
    PORT
      LAYER M4 ;
        RECT 0.000 295.584 0.192 295.608 ;
    END
  END t_out[171]
  PIN t_out[172]
    DIRECTION OUTPUT ;
    USE SIGNAL ;
    PORT
      LAYER M4 ;
        RECT 0.000 295.776 0.192 295.800 ;
    END
  END t_out[172]
  PIN t_out[173]
    DIRECTION OUTPUT ;
    USE SIGNAL ;
    PORT
      LAYER M4 ;
        RECT 0.000 295.968 0.192 295.992 ;
    END
  END t_out[173]
  PIN t_out[174]
    DIRECTION OUTPUT ;
    USE SIGNAL ;
    PORT
      LAYER M4 ;
        RECT 0.000 296.160 0.192 296.184 ;
    END
  END t_out[174]
  PIN t_out[175]
    DIRECTION OUTPUT ;
    USE SIGNAL ;
    PORT
      LAYER M4 ;
        RECT 0.000 296.352 0.192 296.376 ;
    END
  END t_out[175]
  PIN t_out[176]
    DIRECTION OUTPUT ;
    USE SIGNAL ;
    PORT
      LAYER M4 ;
        RECT 0.000 296.544 0.192 296.568 ;
    END
  END t_out[176]
  PIN t_out[177]
    DIRECTION OUTPUT ;
    USE SIGNAL ;
    PORT
      LAYER M4 ;
        RECT 0.000 296.736 0.192 296.760 ;
    END
  END t_out[177]
  PIN t_out[178]
    DIRECTION OUTPUT ;
    USE SIGNAL ;
    PORT
      LAYER M4 ;
        RECT 0.000 296.928 0.192 296.952 ;
    END
  END t_out[178]
  PIN t_out[179]
    DIRECTION OUTPUT ;
    USE SIGNAL ;
    PORT
      LAYER M4 ;
        RECT 0.000 297.120 0.192 297.144 ;
    END
  END t_out[179]
  PIN t_out[180]
    DIRECTION OUTPUT ;
    USE SIGNAL ;
    PORT
      LAYER M4 ;
        RECT 0.000 297.312 0.192 297.336 ;
    END
  END t_out[180]
  PIN t_out[181]
    DIRECTION OUTPUT ;
    USE SIGNAL ;
    PORT
      LAYER M4 ;
        RECT 0.000 297.504 0.192 297.528 ;
    END
  END t_out[181]
  PIN t_out[182]
    DIRECTION OUTPUT ;
    USE SIGNAL ;
    PORT
      LAYER M4 ;
        RECT 0.000 297.696 0.192 297.720 ;
    END
  END t_out[182]
  PIN t_out[183]
    DIRECTION OUTPUT ;
    USE SIGNAL ;
    PORT
      LAYER M4 ;
        RECT 0.000 297.888 0.192 297.912 ;
    END
  END t_out[183]
  PIN t_out[184]
    DIRECTION OUTPUT ;
    USE SIGNAL ;
    PORT
      LAYER M4 ;
        RECT 0.000 298.080 0.192 298.104 ;
    END
  END t_out[184]
  PIN t_out[185]
    DIRECTION OUTPUT ;
    USE SIGNAL ;
    PORT
      LAYER M4 ;
        RECT 0.000 298.272 0.192 298.296 ;
    END
  END t_out[185]
  PIN t_out[186]
    DIRECTION OUTPUT ;
    USE SIGNAL ;
    PORT
      LAYER M4 ;
        RECT 0.000 298.464 0.192 298.488 ;
    END
  END t_out[186]
  PIN t_out[187]
    DIRECTION OUTPUT ;
    USE SIGNAL ;
    PORT
      LAYER M4 ;
        RECT 0.000 298.656 0.192 298.680 ;
    END
  END t_out[187]
  PIN t_out[188]
    DIRECTION OUTPUT ;
    USE SIGNAL ;
    PORT
      LAYER M4 ;
        RECT 0.000 298.848 0.192 298.872 ;
    END
  END t_out[188]
  PIN t_out[189]
    DIRECTION OUTPUT ;
    USE SIGNAL ;
    PORT
      LAYER M4 ;
        RECT 0.000 299.040 0.192 299.064 ;
    END
  END t_out[189]
  PIN t_out[190]
    DIRECTION OUTPUT ;
    USE SIGNAL ;
    PORT
      LAYER M4 ;
        RECT 0.000 299.232 0.192 299.256 ;
    END
  END t_out[190]
  PIN t_out[191]
    DIRECTION OUTPUT ;
    USE SIGNAL ;
    PORT
      LAYER M4 ;
        RECT 0.000 299.424 0.192 299.448 ;
    END
  END t_out[191]
  PIN t_out[192]
    DIRECTION OUTPUT ;
    USE SIGNAL ;
    PORT
      LAYER M4 ;
        RECT 0.000 299.616 0.192 299.640 ;
    END
  END t_out[192]
  PIN t_out[193]
    DIRECTION OUTPUT ;
    USE SIGNAL ;
    PORT
      LAYER M4 ;
        RECT 0.000 299.808 0.192 299.832 ;
    END
  END t_out[193]
  PIN t_out[194]
    DIRECTION OUTPUT ;
    USE SIGNAL ;
    PORT
      LAYER M4 ;
        RECT 0.000 300.000 0.192 300.024 ;
    END
  END t_out[194]
  PIN t_out[195]
    DIRECTION OUTPUT ;
    USE SIGNAL ;
    PORT
      LAYER M4 ;
        RECT 0.000 300.192 0.192 300.216 ;
    END
  END t_out[195]
  PIN t_out[196]
    DIRECTION OUTPUT ;
    USE SIGNAL ;
    PORT
      LAYER M4 ;
        RECT 0.000 300.384 0.192 300.408 ;
    END
  END t_out[196]
  PIN t_out[197]
    DIRECTION OUTPUT ;
    USE SIGNAL ;
    PORT
      LAYER M4 ;
        RECT 0.000 300.576 0.192 300.600 ;
    END
  END t_out[197]
  PIN t_out[198]
    DIRECTION OUTPUT ;
    USE SIGNAL ;
    PORT
      LAYER M4 ;
        RECT 0.000 300.768 0.192 300.792 ;
    END
  END t_out[198]
  PIN t_out[199]
    DIRECTION OUTPUT ;
    USE SIGNAL ;
    PORT
      LAYER M4 ;
        RECT 0.000 300.960 0.192 300.984 ;
    END
  END t_out[199]
  PIN t_out[200]
    DIRECTION OUTPUT ;
    USE SIGNAL ;
    PORT
      LAYER M4 ;
        RECT 0.000 301.152 0.192 301.176 ;
    END
  END t_out[200]
  PIN t_out[201]
    DIRECTION OUTPUT ;
    USE SIGNAL ;
    PORT
      LAYER M4 ;
        RECT 0.000 301.344 0.192 301.368 ;
    END
  END t_out[201]
  PIN t_out[202]
    DIRECTION OUTPUT ;
    USE SIGNAL ;
    PORT
      LAYER M4 ;
        RECT 0.000 301.536 0.192 301.560 ;
    END
  END t_out[202]
  PIN t_out[203]
    DIRECTION OUTPUT ;
    USE SIGNAL ;
    PORT
      LAYER M4 ;
        RECT 0.000 301.728 0.192 301.752 ;
    END
  END t_out[203]
  PIN t_out[204]
    DIRECTION OUTPUT ;
    USE SIGNAL ;
    PORT
      LAYER M4 ;
        RECT 0.000 301.920 0.192 301.944 ;
    END
  END t_out[204]
  PIN t_out[205]
    DIRECTION OUTPUT ;
    USE SIGNAL ;
    PORT
      LAYER M4 ;
        RECT 0.000 302.112 0.192 302.136 ;
    END
  END t_out[205]
  PIN t_out[206]
    DIRECTION OUTPUT ;
    USE SIGNAL ;
    PORT
      LAYER M4 ;
        RECT 0.000 302.304 0.192 302.328 ;
    END
  END t_out[206]
  PIN t_out[207]
    DIRECTION OUTPUT ;
    USE SIGNAL ;
    PORT
      LAYER M4 ;
        RECT 0.000 302.496 0.192 302.520 ;
    END
  END t_out[207]
  PIN t_out[208]
    DIRECTION OUTPUT ;
    USE SIGNAL ;
    PORT
      LAYER M4 ;
        RECT 0.000 302.688 0.192 302.712 ;
    END
  END t_out[208]
  PIN t_out[209]
    DIRECTION OUTPUT ;
    USE SIGNAL ;
    PORT
      LAYER M4 ;
        RECT 0.000 302.880 0.192 302.904 ;
    END
  END t_out[209]
  PIN t_out[210]
    DIRECTION OUTPUT ;
    USE SIGNAL ;
    PORT
      LAYER M4 ;
        RECT 0.000 303.072 0.192 303.096 ;
    END
  END t_out[210]
  PIN t_out[211]
    DIRECTION OUTPUT ;
    USE SIGNAL ;
    PORT
      LAYER M4 ;
        RECT 0.000 303.264 0.192 303.288 ;
    END
  END t_out[211]
  PIN t_out[212]
    DIRECTION OUTPUT ;
    USE SIGNAL ;
    PORT
      LAYER M4 ;
        RECT 0.000 303.456 0.192 303.480 ;
    END
  END t_out[212]
  PIN t_out[213]
    DIRECTION OUTPUT ;
    USE SIGNAL ;
    PORT
      LAYER M4 ;
        RECT 0.000 303.648 0.192 303.672 ;
    END
  END t_out[213]
  PIN t_out[214]
    DIRECTION OUTPUT ;
    USE SIGNAL ;
    PORT
      LAYER M4 ;
        RECT 0.000 303.840 0.192 303.864 ;
    END
  END t_out[214]
  PIN t_out[215]
    DIRECTION OUTPUT ;
    USE SIGNAL ;
    PORT
      LAYER M4 ;
        RECT 0.000 304.032 0.192 304.056 ;
    END
  END t_out[215]
  PIN t_out[216]
    DIRECTION OUTPUT ;
    USE SIGNAL ;
    PORT
      LAYER M4 ;
        RECT 0.000 304.224 0.192 304.248 ;
    END
  END t_out[216]
  PIN t_out[217]
    DIRECTION OUTPUT ;
    USE SIGNAL ;
    PORT
      LAYER M4 ;
        RECT 0.000 304.416 0.192 304.440 ;
    END
  END t_out[217]
  PIN t_out[218]
    DIRECTION OUTPUT ;
    USE SIGNAL ;
    PORT
      LAYER M4 ;
        RECT 0.000 304.608 0.192 304.632 ;
    END
  END t_out[218]
  PIN t_out[219]
    DIRECTION OUTPUT ;
    USE SIGNAL ;
    PORT
      LAYER M4 ;
        RECT 0.000 304.800 0.192 304.824 ;
    END
  END t_out[219]
  PIN t_out[220]
    DIRECTION OUTPUT ;
    USE SIGNAL ;
    PORT
      LAYER M4 ;
        RECT 0.000 304.992 0.192 305.016 ;
    END
  END t_out[220]
  PIN t_out[221]
    DIRECTION OUTPUT ;
    USE SIGNAL ;
    PORT
      LAYER M4 ;
        RECT 0.000 305.184 0.192 305.208 ;
    END
  END t_out[221]
  PIN t_out[222]
    DIRECTION OUTPUT ;
    USE SIGNAL ;
    PORT
      LAYER M4 ;
        RECT 0.000 305.376 0.192 305.400 ;
    END
  END t_out[222]
  PIN t_out[223]
    DIRECTION OUTPUT ;
    USE SIGNAL ;
    PORT
      LAYER M4 ;
        RECT 0.000 305.568 0.192 305.592 ;
    END
  END t_out[223]
  PIN t_out[224]
    DIRECTION OUTPUT ;
    USE SIGNAL ;
    PORT
      LAYER M4 ;
        RECT 0.000 305.760 0.192 305.784 ;
    END
  END t_out[224]
  PIN t_out[225]
    DIRECTION OUTPUT ;
    USE SIGNAL ;
    PORT
      LAYER M4 ;
        RECT 0.000 305.952 0.192 305.976 ;
    END
  END t_out[225]
  PIN t_out[226]
    DIRECTION OUTPUT ;
    USE SIGNAL ;
    PORT
      LAYER M4 ;
        RECT 0.000 306.144 0.192 306.168 ;
    END
  END t_out[226]
  PIN t_out[227]
    DIRECTION OUTPUT ;
    USE SIGNAL ;
    PORT
      LAYER M4 ;
        RECT 0.000 306.336 0.192 306.360 ;
    END
  END t_out[227]
  PIN t_out[228]
    DIRECTION OUTPUT ;
    USE SIGNAL ;
    PORT
      LAYER M4 ;
        RECT 0.000 306.528 0.192 306.552 ;
    END
  END t_out[228]
  PIN t_out[229]
    DIRECTION OUTPUT ;
    USE SIGNAL ;
    PORT
      LAYER M4 ;
        RECT 0.000 306.720 0.192 306.744 ;
    END
  END t_out[229]
  PIN t_out[230]
    DIRECTION OUTPUT ;
    USE SIGNAL ;
    PORT
      LAYER M4 ;
        RECT 0.000 306.912 0.192 306.936 ;
    END
  END t_out[230]
  PIN t_out[231]
    DIRECTION OUTPUT ;
    USE SIGNAL ;
    PORT
      LAYER M4 ;
        RECT 0.000 307.104 0.192 307.128 ;
    END
  END t_out[231]
  PIN t_out[232]
    DIRECTION OUTPUT ;
    USE SIGNAL ;
    PORT
      LAYER M4 ;
        RECT 0.000 307.296 0.192 307.320 ;
    END
  END t_out[232]
  PIN t_out[233]
    DIRECTION OUTPUT ;
    USE SIGNAL ;
    PORT
      LAYER M4 ;
        RECT 0.000 307.488 0.192 307.512 ;
    END
  END t_out[233]
  PIN t_out[234]
    DIRECTION OUTPUT ;
    USE SIGNAL ;
    PORT
      LAYER M4 ;
        RECT 0.000 307.680 0.192 307.704 ;
    END
  END t_out[234]
  PIN t_out[235]
    DIRECTION OUTPUT ;
    USE SIGNAL ;
    PORT
      LAYER M4 ;
        RECT 0.000 307.872 0.192 307.896 ;
    END
  END t_out[235]
  PIN t_out[236]
    DIRECTION OUTPUT ;
    USE SIGNAL ;
    PORT
      LAYER M4 ;
        RECT 0.000 308.064 0.192 308.088 ;
    END
  END t_out[236]
  PIN t_out[237]
    DIRECTION OUTPUT ;
    USE SIGNAL ;
    PORT
      LAYER M4 ;
        RECT 0.000 308.256 0.192 308.280 ;
    END
  END t_out[237]
  PIN t_out[238]
    DIRECTION OUTPUT ;
    USE SIGNAL ;
    PORT
      LAYER M4 ;
        RECT 0.000 308.448 0.192 308.472 ;
    END
  END t_out[238]
  PIN t_out[239]
    DIRECTION OUTPUT ;
    USE SIGNAL ;
    PORT
      LAYER M4 ;
        RECT 0.000 308.640 0.192 308.664 ;
    END
  END t_out[239]
  PIN t_out[240]
    DIRECTION OUTPUT ;
    USE SIGNAL ;
    PORT
      LAYER M4 ;
        RECT 0.000 308.832 0.192 308.856 ;
    END
  END t_out[240]
  PIN t_out[241]
    DIRECTION OUTPUT ;
    USE SIGNAL ;
    PORT
      LAYER M4 ;
        RECT 0.000 309.024 0.192 309.048 ;
    END
  END t_out[241]
  PIN t_out[242]
    DIRECTION OUTPUT ;
    USE SIGNAL ;
    PORT
      LAYER M4 ;
        RECT 0.000 309.216 0.192 309.240 ;
    END
  END t_out[242]
  PIN t_out[243]
    DIRECTION OUTPUT ;
    USE SIGNAL ;
    PORT
      LAYER M4 ;
        RECT 0.000 309.408 0.192 309.432 ;
    END
  END t_out[243]
  PIN t_out[244]
    DIRECTION OUTPUT ;
    USE SIGNAL ;
    PORT
      LAYER M4 ;
        RECT 0.000 309.600 0.192 309.624 ;
    END
  END t_out[244]
  PIN t_out[245]
    DIRECTION OUTPUT ;
    USE SIGNAL ;
    PORT
      LAYER M4 ;
        RECT 0.000 309.792 0.192 309.816 ;
    END
  END t_out[245]
  PIN t_out[246]
    DIRECTION OUTPUT ;
    USE SIGNAL ;
    PORT
      LAYER M4 ;
        RECT 0.000 309.984 0.192 310.008 ;
    END
  END t_out[246]
  PIN t_out[247]
    DIRECTION OUTPUT ;
    USE SIGNAL ;
    PORT
      LAYER M4 ;
        RECT 0.000 310.176 0.192 310.200 ;
    END
  END t_out[247]
  PIN t_out[248]
    DIRECTION OUTPUT ;
    USE SIGNAL ;
    PORT
      LAYER M4 ;
        RECT 0.000 310.368 0.192 310.392 ;
    END
  END t_out[248]
  PIN t_out[249]
    DIRECTION OUTPUT ;
    USE SIGNAL ;
    PORT
      LAYER M4 ;
        RECT 0.000 310.560 0.192 310.584 ;
    END
  END t_out[249]
  PIN t_out[250]
    DIRECTION OUTPUT ;
    USE SIGNAL ;
    PORT
      LAYER M4 ;
        RECT 0.000 310.752 0.192 310.776 ;
    END
  END t_out[250]
  PIN t_out[251]
    DIRECTION OUTPUT ;
    USE SIGNAL ;
    PORT
      LAYER M4 ;
        RECT 0.000 310.944 0.192 310.968 ;
    END
  END t_out[251]
  PIN t_out[252]
    DIRECTION OUTPUT ;
    USE SIGNAL ;
    PORT
      LAYER M4 ;
        RECT 0.000 311.136 0.192 311.160 ;
    END
  END t_out[252]
  PIN t_out[253]
    DIRECTION OUTPUT ;
    USE SIGNAL ;
    PORT
      LAYER M4 ;
        RECT 0.000 311.328 0.192 311.352 ;
    END
  END t_out[253]
  PIN t_out[254]
    DIRECTION OUTPUT ;
    USE SIGNAL ;
    PORT
      LAYER M4 ;
        RECT 0.000 311.520 0.192 311.544 ;
    END
  END t_out[254]
  PIN t_out[255]
    DIRECTION OUTPUT ;
    USE SIGNAL ;
    PORT
      LAYER M4 ;
        RECT 0.000 311.712 0.192 311.736 ;
    END
  END t_out[255]
  PIN t_out[256]
    DIRECTION OUTPUT ;
    USE SIGNAL ;
    PORT
      LAYER M4 ;
        RECT 0.000 311.904 0.192 311.928 ;
    END
  END t_out[256]
  PIN t_out[257]
    DIRECTION OUTPUT ;
    USE SIGNAL ;
    PORT
      LAYER M4 ;
        RECT 0.000 312.096 0.192 312.120 ;
    END
  END t_out[257]
  PIN t_out[258]
    DIRECTION OUTPUT ;
    USE SIGNAL ;
    PORT
      LAYER M4 ;
        RECT 0.000 312.288 0.192 312.312 ;
    END
  END t_out[258]
  PIN t_out[259]
    DIRECTION OUTPUT ;
    USE SIGNAL ;
    PORT
      LAYER M4 ;
        RECT 0.000 312.480 0.192 312.504 ;
    END
  END t_out[259]
  PIN t_out[260]
    DIRECTION OUTPUT ;
    USE SIGNAL ;
    PORT
      LAYER M4 ;
        RECT 0.000 312.672 0.192 312.696 ;
    END
  END t_out[260]
  PIN t_out[261]
    DIRECTION OUTPUT ;
    USE SIGNAL ;
    PORT
      LAYER M4 ;
        RECT 0.000 312.864 0.192 312.888 ;
    END
  END t_out[261]
  PIN t_out[262]
    DIRECTION OUTPUT ;
    USE SIGNAL ;
    PORT
      LAYER M4 ;
        RECT 0.000 313.056 0.192 313.080 ;
    END
  END t_out[262]
  PIN t_out[263]
    DIRECTION OUTPUT ;
    USE SIGNAL ;
    PORT
      LAYER M4 ;
        RECT 0.000 313.248 0.192 313.272 ;
    END
  END t_out[263]
  PIN t_out[264]
    DIRECTION OUTPUT ;
    USE SIGNAL ;
    PORT
      LAYER M4 ;
        RECT 0.000 313.440 0.192 313.464 ;
    END
  END t_out[264]
  PIN t_out[265]
    DIRECTION OUTPUT ;
    USE SIGNAL ;
    PORT
      LAYER M4 ;
        RECT 0.000 313.632 0.192 313.656 ;
    END
  END t_out[265]
  PIN t_out[266]
    DIRECTION OUTPUT ;
    USE SIGNAL ;
    PORT
      LAYER M4 ;
        RECT 0.000 313.824 0.192 313.848 ;
    END
  END t_out[266]
  PIN t_out[267]
    DIRECTION OUTPUT ;
    USE SIGNAL ;
    PORT
      LAYER M4 ;
        RECT 0.000 314.016 0.192 314.040 ;
    END
  END t_out[267]
  PIN t_out[268]
    DIRECTION OUTPUT ;
    USE SIGNAL ;
    PORT
      LAYER M4 ;
        RECT 0.000 314.208 0.192 314.232 ;
    END
  END t_out[268]
  PIN t_out[269]
    DIRECTION OUTPUT ;
    USE SIGNAL ;
    PORT
      LAYER M4 ;
        RECT 0.000 314.400 0.192 314.424 ;
    END
  END t_out[269]
  PIN t_out[270]
    DIRECTION OUTPUT ;
    USE SIGNAL ;
    PORT
      LAYER M4 ;
        RECT 0.000 314.592 0.192 314.616 ;
    END
  END t_out[270]
  PIN t_out[271]
    DIRECTION OUTPUT ;
    USE SIGNAL ;
    PORT
      LAYER M4 ;
        RECT 0.000 314.784 0.192 314.808 ;
    END
  END t_out[271]
  PIN t_out[272]
    DIRECTION OUTPUT ;
    USE SIGNAL ;
    PORT
      LAYER M4 ;
        RECT 0.000 314.976 0.192 315.000 ;
    END
  END t_out[272]
  PIN t_out[273]
    DIRECTION OUTPUT ;
    USE SIGNAL ;
    PORT
      LAYER M4 ;
        RECT 0.000 315.168 0.192 315.192 ;
    END
  END t_out[273]
  PIN t_out[274]
    DIRECTION OUTPUT ;
    USE SIGNAL ;
    PORT
      LAYER M4 ;
        RECT 0.000 315.360 0.192 315.384 ;
    END
  END t_out[274]
  PIN t_out[275]
    DIRECTION OUTPUT ;
    USE SIGNAL ;
    PORT
      LAYER M4 ;
        RECT 0.000 315.552 0.192 315.576 ;
    END
  END t_out[275]
  PIN t_out[276]
    DIRECTION OUTPUT ;
    USE SIGNAL ;
    PORT
      LAYER M4 ;
        RECT 0.000 315.744 0.192 315.768 ;
    END
  END t_out[276]
  PIN t_out[277]
    DIRECTION OUTPUT ;
    USE SIGNAL ;
    PORT
      LAYER M4 ;
        RECT 0.000 315.936 0.192 315.960 ;
    END
  END t_out[277]
  PIN t_out[278]
    DIRECTION OUTPUT ;
    USE SIGNAL ;
    PORT
      LAYER M4 ;
        RECT 0.000 316.128 0.192 316.152 ;
    END
  END t_out[278]
  PIN t_out[279]
    DIRECTION OUTPUT ;
    USE SIGNAL ;
    PORT
      LAYER M4 ;
        RECT 0.000 316.320 0.192 316.344 ;
    END
  END t_out[279]
  PIN t_out[280]
    DIRECTION OUTPUT ;
    USE SIGNAL ;
    PORT
      LAYER M4 ;
        RECT 0.000 316.512 0.192 316.536 ;
    END
  END t_out[280]
  PIN t_out[281]
    DIRECTION OUTPUT ;
    USE SIGNAL ;
    PORT
      LAYER M4 ;
        RECT 0.000 316.704 0.192 316.728 ;
    END
  END t_out[281]
  PIN t_out[282]
    DIRECTION OUTPUT ;
    USE SIGNAL ;
    PORT
      LAYER M4 ;
        RECT 0.000 316.896 0.192 316.920 ;
    END
  END t_out[282]
  PIN t_out[283]
    DIRECTION OUTPUT ;
    USE SIGNAL ;
    PORT
      LAYER M4 ;
        RECT 0.000 317.088 0.192 317.112 ;
    END
  END t_out[283]
  PIN t_out[284]
    DIRECTION OUTPUT ;
    USE SIGNAL ;
    PORT
      LAYER M4 ;
        RECT 0.000 317.280 0.192 317.304 ;
    END
  END t_out[284]
  PIN t_out[285]
    DIRECTION OUTPUT ;
    USE SIGNAL ;
    PORT
      LAYER M4 ;
        RECT 0.000 317.472 0.192 317.496 ;
    END
  END t_out[285]
  PIN t_out[286]
    DIRECTION OUTPUT ;
    USE SIGNAL ;
    PORT
      LAYER M4 ;
        RECT 0.000 317.664 0.192 317.688 ;
    END
  END t_out[286]
  PIN t_out[287]
    DIRECTION OUTPUT ;
    USE SIGNAL ;
    PORT
      LAYER M4 ;
        RECT 0.000 317.856 0.192 317.880 ;
    END
  END t_out[287]
  PIN t_out[288]
    DIRECTION OUTPUT ;
    USE SIGNAL ;
    PORT
      LAYER M4 ;
        RECT 0.000 318.048 0.192 318.072 ;
    END
  END t_out[288]
  PIN t_out[289]
    DIRECTION OUTPUT ;
    USE SIGNAL ;
    PORT
      LAYER M4 ;
        RECT 0.000 318.240 0.192 318.264 ;
    END
  END t_out[289]
  PIN t_out[290]
    DIRECTION OUTPUT ;
    USE SIGNAL ;
    PORT
      LAYER M4 ;
        RECT 0.000 318.432 0.192 318.456 ;
    END
  END t_out[290]
  PIN t_out[291]
    DIRECTION OUTPUT ;
    USE SIGNAL ;
    PORT
      LAYER M4 ;
        RECT 0.000 318.624 0.192 318.648 ;
    END
  END t_out[291]
  PIN t_out[292]
    DIRECTION OUTPUT ;
    USE SIGNAL ;
    PORT
      LAYER M4 ;
        RECT 0.000 318.816 0.192 318.840 ;
    END
  END t_out[292]
  PIN t_out[293]
    DIRECTION OUTPUT ;
    USE SIGNAL ;
    PORT
      LAYER M4 ;
        RECT 0.000 319.008 0.192 319.032 ;
    END
  END t_out[293]
  PIN t_out[294]
    DIRECTION OUTPUT ;
    USE SIGNAL ;
    PORT
      LAYER M4 ;
        RECT 0.000 319.200 0.192 319.224 ;
    END
  END t_out[294]
  PIN t_out[295]
    DIRECTION OUTPUT ;
    USE SIGNAL ;
    PORT
      LAYER M4 ;
        RECT 0.000 319.392 0.192 319.416 ;
    END
  END t_out[295]
  PIN t_out[296]
    DIRECTION OUTPUT ;
    USE SIGNAL ;
    PORT
      LAYER M4 ;
        RECT 0.000 319.584 0.192 319.608 ;
    END
  END t_out[296]
  PIN t_out[297]
    DIRECTION OUTPUT ;
    USE SIGNAL ;
    PORT
      LAYER M4 ;
        RECT 0.000 319.776 0.192 319.800 ;
    END
  END t_out[297]
  PIN t_out[298]
    DIRECTION OUTPUT ;
    USE SIGNAL ;
    PORT
      LAYER M4 ;
        RECT 0.000 319.968 0.192 319.992 ;
    END
  END t_out[298]
  PIN t_out[299]
    DIRECTION OUTPUT ;
    USE SIGNAL ;
    PORT
      LAYER M4 ;
        RECT 0.000 320.160 0.192 320.184 ;
    END
  END t_out[299]
  PIN t_out[300]
    DIRECTION OUTPUT ;
    USE SIGNAL ;
    PORT
      LAYER M4 ;
        RECT 0.000 320.352 0.192 320.376 ;
    END
  END t_out[300]
  PIN t_out[301]
    DIRECTION OUTPUT ;
    USE SIGNAL ;
    PORT
      LAYER M4 ;
        RECT 0.000 320.544 0.192 320.568 ;
    END
  END t_out[301]
  PIN t_out[302]
    DIRECTION OUTPUT ;
    USE SIGNAL ;
    PORT
      LAYER M4 ;
        RECT 0.000 320.736 0.192 320.760 ;
    END
  END t_out[302]
  PIN t_out[303]
    DIRECTION OUTPUT ;
    USE SIGNAL ;
    PORT
      LAYER M4 ;
        RECT 0.000 320.928 0.192 320.952 ;
    END
  END t_out[303]
  PIN t_out[304]
    DIRECTION OUTPUT ;
    USE SIGNAL ;
    PORT
      LAYER M4 ;
        RECT 0.000 321.120 0.192 321.144 ;
    END
  END t_out[304]
  PIN t_out[305]
    DIRECTION OUTPUT ;
    USE SIGNAL ;
    PORT
      LAYER M4 ;
        RECT 0.000 321.312 0.192 321.336 ;
    END
  END t_out[305]
  PIN t_out[306]
    DIRECTION OUTPUT ;
    USE SIGNAL ;
    PORT
      LAYER M4 ;
        RECT 0.000 321.504 0.192 321.528 ;
    END
  END t_out[306]
  PIN t_out[307]
    DIRECTION OUTPUT ;
    USE SIGNAL ;
    PORT
      LAYER M4 ;
        RECT 0.000 321.696 0.192 321.720 ;
    END
  END t_out[307]
  PIN t_out[308]
    DIRECTION OUTPUT ;
    USE SIGNAL ;
    PORT
      LAYER M4 ;
        RECT 0.000 321.888 0.192 321.912 ;
    END
  END t_out[308]
  PIN t_out[309]
    DIRECTION OUTPUT ;
    USE SIGNAL ;
    PORT
      LAYER M4 ;
        RECT 0.000 322.080 0.192 322.104 ;
    END
  END t_out[309]
  PIN t_out[310]
    DIRECTION OUTPUT ;
    USE SIGNAL ;
    PORT
      LAYER M4 ;
        RECT 0.000 322.272 0.192 322.296 ;
    END
  END t_out[310]
  PIN t_out[311]
    DIRECTION OUTPUT ;
    USE SIGNAL ;
    PORT
      LAYER M4 ;
        RECT 0.000 322.464 0.192 322.488 ;
    END
  END t_out[311]
  PIN t_out[312]
    DIRECTION OUTPUT ;
    USE SIGNAL ;
    PORT
      LAYER M4 ;
        RECT 0.000 322.656 0.192 322.680 ;
    END
  END t_out[312]
  PIN t_out[313]
    DIRECTION OUTPUT ;
    USE SIGNAL ;
    PORT
      LAYER M4 ;
        RECT 0.000 322.848 0.192 322.872 ;
    END
  END t_out[313]
  PIN t_out[314]
    DIRECTION OUTPUT ;
    USE SIGNAL ;
    PORT
      LAYER M4 ;
        RECT 0.000 323.040 0.192 323.064 ;
    END
  END t_out[314]
  PIN t_out[315]
    DIRECTION OUTPUT ;
    USE SIGNAL ;
    PORT
      LAYER M4 ;
        RECT 0.000 323.232 0.192 323.256 ;
    END
  END t_out[315]
  PIN t_out[316]
    DIRECTION OUTPUT ;
    USE SIGNAL ;
    PORT
      LAYER M4 ;
        RECT 0.000 323.424 0.192 323.448 ;
    END
  END t_out[316]
  PIN t_out[317]
    DIRECTION OUTPUT ;
    USE SIGNAL ;
    PORT
      LAYER M4 ;
        RECT 0.000 323.616 0.192 323.640 ;
    END
  END t_out[317]
  PIN t_out[318]
    DIRECTION OUTPUT ;
    USE SIGNAL ;
    PORT
      LAYER M4 ;
        RECT 0.000 323.808 0.192 323.832 ;
    END
  END t_out[318]
  PIN t_out[319]
    DIRECTION OUTPUT ;
    USE SIGNAL ;
    PORT
      LAYER M4 ;
        RECT 0.000 324.000 0.192 324.024 ;
    END
  END t_out[319]
  PIN t_out[320]
    DIRECTION OUTPUT ;
    USE SIGNAL ;
    PORT
      LAYER M4 ;
        RECT 0.000 324.192 0.192 324.216 ;
    END
  END t_out[320]
  PIN t_out[321]
    DIRECTION OUTPUT ;
    USE SIGNAL ;
    PORT
      LAYER M4 ;
        RECT 0.000 324.384 0.192 324.408 ;
    END
  END t_out[321]
  PIN t_out[322]
    DIRECTION OUTPUT ;
    USE SIGNAL ;
    PORT
      LAYER M4 ;
        RECT 0.000 324.576 0.192 324.600 ;
    END
  END t_out[322]
  PIN t_out[323]
    DIRECTION OUTPUT ;
    USE SIGNAL ;
    PORT
      LAYER M4 ;
        RECT 0.000 324.768 0.192 324.792 ;
    END
  END t_out[323]
  PIN t_out[324]
    DIRECTION OUTPUT ;
    USE SIGNAL ;
    PORT
      LAYER M4 ;
        RECT 0.000 324.960 0.192 324.984 ;
    END
  END t_out[324]
  PIN t_out[325]
    DIRECTION OUTPUT ;
    USE SIGNAL ;
    PORT
      LAYER M4 ;
        RECT 0.000 325.152 0.192 325.176 ;
    END
  END t_out[325]
  PIN t_out[326]
    DIRECTION OUTPUT ;
    USE SIGNAL ;
    PORT
      LAYER M4 ;
        RECT 0.000 325.344 0.192 325.368 ;
    END
  END t_out[326]
  PIN t_out[327]
    DIRECTION OUTPUT ;
    USE SIGNAL ;
    PORT
      LAYER M4 ;
        RECT 0.000 325.536 0.192 325.560 ;
    END
  END t_out[327]
  PIN t_out[328]
    DIRECTION OUTPUT ;
    USE SIGNAL ;
    PORT
      LAYER M4 ;
        RECT 0.000 325.728 0.192 325.752 ;
    END
  END t_out[328]
  PIN t_out[329]
    DIRECTION OUTPUT ;
    USE SIGNAL ;
    PORT
      LAYER M4 ;
        RECT 0.000 325.920 0.192 325.944 ;
    END
  END t_out[329]
  PIN t_out[330]
    DIRECTION OUTPUT ;
    USE SIGNAL ;
    PORT
      LAYER M4 ;
        RECT 0.000 326.112 0.192 326.136 ;
    END
  END t_out[330]
  PIN t_out[331]
    DIRECTION OUTPUT ;
    USE SIGNAL ;
    PORT
      LAYER M4 ;
        RECT 0.000 326.304 0.192 326.328 ;
    END
  END t_out[331]
  PIN t_out[332]
    DIRECTION OUTPUT ;
    USE SIGNAL ;
    PORT
      LAYER M4 ;
        RECT 0.000 326.496 0.192 326.520 ;
    END
  END t_out[332]
  PIN t_out[333]
    DIRECTION OUTPUT ;
    USE SIGNAL ;
    PORT
      LAYER M4 ;
        RECT 0.000 326.688 0.192 326.712 ;
    END
  END t_out[333]
  PIN t_out[334]
    DIRECTION OUTPUT ;
    USE SIGNAL ;
    PORT
      LAYER M4 ;
        RECT 0.000 326.880 0.192 326.904 ;
    END
  END t_out[334]
  PIN t_out[335]
    DIRECTION OUTPUT ;
    USE SIGNAL ;
    PORT
      LAYER M4 ;
        RECT 0.000 327.072 0.192 327.096 ;
    END
  END t_out[335]
  PIN t_out[336]
    DIRECTION OUTPUT ;
    USE SIGNAL ;
    PORT
      LAYER M4 ;
        RECT 0.000 327.264 0.192 327.288 ;
    END
  END t_out[336]
  PIN t_out[337]
    DIRECTION OUTPUT ;
    USE SIGNAL ;
    PORT
      LAYER M4 ;
        RECT 0.000 327.456 0.192 327.480 ;
    END
  END t_out[337]
  PIN t_out[338]
    DIRECTION OUTPUT ;
    USE SIGNAL ;
    PORT
      LAYER M4 ;
        RECT 0.000 327.648 0.192 327.672 ;
    END
  END t_out[338]
  PIN t_out[339]
    DIRECTION OUTPUT ;
    USE SIGNAL ;
    PORT
      LAYER M4 ;
        RECT 0.000 327.840 0.192 327.864 ;
    END
  END t_out[339]
  PIN t_out[340]
    DIRECTION OUTPUT ;
    USE SIGNAL ;
    PORT
      LAYER M4 ;
        RECT 0.000 328.032 0.192 328.056 ;
    END
  END t_out[340]
  PIN t_out[341]
    DIRECTION OUTPUT ;
    USE SIGNAL ;
    PORT
      LAYER M4 ;
        RECT 0.000 328.224 0.192 328.248 ;
    END
  END t_out[341]
  PIN t_out[342]
    DIRECTION OUTPUT ;
    USE SIGNAL ;
    PORT
      LAYER M4 ;
        RECT 0.000 328.416 0.192 328.440 ;
    END
  END t_out[342]
  PIN t_out[343]
    DIRECTION OUTPUT ;
    USE SIGNAL ;
    PORT
      LAYER M4 ;
        RECT 0.000 328.608 0.192 328.632 ;
    END
  END t_out[343]
  PIN t_out[344]
    DIRECTION OUTPUT ;
    USE SIGNAL ;
    PORT
      LAYER M4 ;
        RECT 0.000 328.800 0.192 328.824 ;
    END
  END t_out[344]
  PIN t_out[345]
    DIRECTION OUTPUT ;
    USE SIGNAL ;
    PORT
      LAYER M4 ;
        RECT 0.000 328.992 0.192 329.016 ;
    END
  END t_out[345]
  PIN t_out[346]
    DIRECTION OUTPUT ;
    USE SIGNAL ;
    PORT
      LAYER M4 ;
        RECT 0.000 329.184 0.192 329.208 ;
    END
  END t_out[346]
  PIN t_out[347]
    DIRECTION OUTPUT ;
    USE SIGNAL ;
    PORT
      LAYER M4 ;
        RECT 0.000 329.376 0.192 329.400 ;
    END
  END t_out[347]
  PIN t_out[348]
    DIRECTION OUTPUT ;
    USE SIGNAL ;
    PORT
      LAYER M4 ;
        RECT 0.000 329.568 0.192 329.592 ;
    END
  END t_out[348]
  PIN t_out[349]
    DIRECTION OUTPUT ;
    USE SIGNAL ;
    PORT
      LAYER M4 ;
        RECT 0.000 329.760 0.192 329.784 ;
    END
  END t_out[349]
  PIN t_out[350]
    DIRECTION OUTPUT ;
    USE SIGNAL ;
    PORT
      LAYER M4 ;
        RECT 0.000 329.952 0.192 329.976 ;
    END
  END t_out[350]
  PIN t_out[351]
    DIRECTION OUTPUT ;
    USE SIGNAL ;
    PORT
      LAYER M4 ;
        RECT 0.000 330.144 0.192 330.168 ;
    END
  END t_out[351]
  PIN t_out[352]
    DIRECTION OUTPUT ;
    USE SIGNAL ;
    PORT
      LAYER M4 ;
        RECT 0.000 330.336 0.192 330.360 ;
    END
  END t_out[352]
  PIN t_out[353]
    DIRECTION OUTPUT ;
    USE SIGNAL ;
    PORT
      LAYER M4 ;
        RECT 0.000 330.528 0.192 330.552 ;
    END
  END t_out[353]
  PIN t_out[354]
    DIRECTION OUTPUT ;
    USE SIGNAL ;
    PORT
      LAYER M4 ;
        RECT 0.000 330.720 0.192 330.744 ;
    END
  END t_out[354]
  PIN t_out[355]
    DIRECTION OUTPUT ;
    USE SIGNAL ;
    PORT
      LAYER M4 ;
        RECT 0.000 330.912 0.192 330.936 ;
    END
  END t_out[355]
  PIN t_out[356]
    DIRECTION OUTPUT ;
    USE SIGNAL ;
    PORT
      LAYER M4 ;
        RECT 0.000 331.104 0.192 331.128 ;
    END
  END t_out[356]
  PIN t_out[357]
    DIRECTION OUTPUT ;
    USE SIGNAL ;
    PORT
      LAYER M4 ;
        RECT 0.000 331.296 0.192 331.320 ;
    END
  END t_out[357]
  PIN t_out[358]
    DIRECTION OUTPUT ;
    USE SIGNAL ;
    PORT
      LAYER M4 ;
        RECT 0.000 331.488 0.192 331.512 ;
    END
  END t_out[358]
  PIN t_out[359]
    DIRECTION OUTPUT ;
    USE SIGNAL ;
    PORT
      LAYER M4 ;
        RECT 0.000 331.680 0.192 331.704 ;
    END
  END t_out[359]
  PIN t_out[360]
    DIRECTION OUTPUT ;
    USE SIGNAL ;
    PORT
      LAYER M4 ;
        RECT 0.000 331.872 0.192 331.896 ;
    END
  END t_out[360]
  PIN t_out[361]
    DIRECTION OUTPUT ;
    USE SIGNAL ;
    PORT
      LAYER M4 ;
        RECT 0.000 332.064 0.192 332.088 ;
    END
  END t_out[361]
  PIN t_out[362]
    DIRECTION OUTPUT ;
    USE SIGNAL ;
    PORT
      LAYER M4 ;
        RECT 0.000 332.256 0.192 332.280 ;
    END
  END t_out[362]
  PIN t_out[363]
    DIRECTION OUTPUT ;
    USE SIGNAL ;
    PORT
      LAYER M4 ;
        RECT 0.000 332.448 0.192 332.472 ;
    END
  END t_out[363]
  PIN t_out[364]
    DIRECTION OUTPUT ;
    USE SIGNAL ;
    PORT
      LAYER M4 ;
        RECT 0.000 332.640 0.192 332.664 ;
    END
  END t_out[364]
  PIN t_out[365]
    DIRECTION OUTPUT ;
    USE SIGNAL ;
    PORT
      LAYER M4 ;
        RECT 0.000 332.832 0.192 332.856 ;
    END
  END t_out[365]
  PIN t_out[366]
    DIRECTION OUTPUT ;
    USE SIGNAL ;
    PORT
      LAYER M4 ;
        RECT 0.000 333.024 0.192 333.048 ;
    END
  END t_out[366]
  PIN t_out[367]
    DIRECTION OUTPUT ;
    USE SIGNAL ;
    PORT
      LAYER M4 ;
        RECT 0.000 333.216 0.192 333.240 ;
    END
  END t_out[367]
  PIN t_out[368]
    DIRECTION OUTPUT ;
    USE SIGNAL ;
    PORT
      LAYER M4 ;
        RECT 0.000 333.408 0.192 333.432 ;
    END
  END t_out[368]
  PIN t_out[369]
    DIRECTION OUTPUT ;
    USE SIGNAL ;
    PORT
      LAYER M4 ;
        RECT 0.000 333.600 0.192 333.624 ;
    END
  END t_out[369]
  PIN t_out[370]
    DIRECTION OUTPUT ;
    USE SIGNAL ;
    PORT
      LAYER M4 ;
        RECT 0.000 333.792 0.192 333.816 ;
    END
  END t_out[370]
  PIN t_out[371]
    DIRECTION OUTPUT ;
    USE SIGNAL ;
    PORT
      LAYER M4 ;
        RECT 0.000 333.984 0.192 334.008 ;
    END
  END t_out[371]
  PIN t_out[372]
    DIRECTION OUTPUT ;
    USE SIGNAL ;
    PORT
      LAYER M4 ;
        RECT 0.000 334.176 0.192 334.200 ;
    END
  END t_out[372]
  PIN t_out[373]
    DIRECTION OUTPUT ;
    USE SIGNAL ;
    PORT
      LAYER M4 ;
        RECT 0.000 334.368 0.192 334.392 ;
    END
  END t_out[373]
  PIN t_out[374]
    DIRECTION OUTPUT ;
    USE SIGNAL ;
    PORT
      LAYER M4 ;
        RECT 0.000 334.560 0.192 334.584 ;
    END
  END t_out[374]
  PIN t_out[375]
    DIRECTION OUTPUT ;
    USE SIGNAL ;
    PORT
      LAYER M4 ;
        RECT 0.000 334.752 0.192 334.776 ;
    END
  END t_out[375]
  PIN t_out[376]
    DIRECTION OUTPUT ;
    USE SIGNAL ;
    PORT
      LAYER M4 ;
        RECT 0.000 334.944 0.192 334.968 ;
    END
  END t_out[376]
  PIN t_out[377]
    DIRECTION OUTPUT ;
    USE SIGNAL ;
    PORT
      LAYER M4 ;
        RECT 0.000 335.136 0.192 335.160 ;
    END
  END t_out[377]
  PIN t_out[378]
    DIRECTION OUTPUT ;
    USE SIGNAL ;
    PORT
      LAYER M4 ;
        RECT 0.000 335.328 0.192 335.352 ;
    END
  END t_out[378]
  PIN t_out[379]
    DIRECTION OUTPUT ;
    USE SIGNAL ;
    PORT
      LAYER M4 ;
        RECT 0.000 335.520 0.192 335.544 ;
    END
  END t_out[379]
  PIN t_out[380]
    DIRECTION OUTPUT ;
    USE SIGNAL ;
    PORT
      LAYER M4 ;
        RECT 0.000 335.712 0.192 335.736 ;
    END
  END t_out[380]
  PIN t_out[381]
    DIRECTION OUTPUT ;
    USE SIGNAL ;
    PORT
      LAYER M4 ;
        RECT 0.000 335.904 0.192 335.928 ;
    END
  END t_out[381]
  PIN t_out[382]
    DIRECTION OUTPUT ;
    USE SIGNAL ;
    PORT
      LAYER M4 ;
        RECT 0.000 336.096 0.192 336.120 ;
    END
  END t_out[382]
  PIN t_out[383]
    DIRECTION OUTPUT ;
    USE SIGNAL ;
    PORT
      LAYER M4 ;
        RECT 0.000 336.288 0.192 336.312 ;
    END
  END t_out[383]
  PIN t_out[384]
    DIRECTION OUTPUT ;
    USE SIGNAL ;
    PORT
      LAYER M4 ;
        RECT 0.000 336.480 0.192 336.504 ;
    END
  END t_out[384]
  PIN t_out[385]
    DIRECTION OUTPUT ;
    USE SIGNAL ;
    PORT
      LAYER M4 ;
        RECT 0.000 336.672 0.192 336.696 ;
    END
  END t_out[385]
  PIN t_out[386]
    DIRECTION OUTPUT ;
    USE SIGNAL ;
    PORT
      LAYER M4 ;
        RECT 0.000 336.864 0.192 336.888 ;
    END
  END t_out[386]
  PIN t_out[387]
    DIRECTION OUTPUT ;
    USE SIGNAL ;
    PORT
      LAYER M4 ;
        RECT 0.000 337.056 0.192 337.080 ;
    END
  END t_out[387]
  PIN t_out[388]
    DIRECTION OUTPUT ;
    USE SIGNAL ;
    PORT
      LAYER M4 ;
        RECT 0.000 337.248 0.192 337.272 ;
    END
  END t_out[388]
  PIN t_out[389]
    DIRECTION OUTPUT ;
    USE SIGNAL ;
    PORT
      LAYER M4 ;
        RECT 0.000 337.440 0.192 337.464 ;
    END
  END t_out[389]
  PIN t_out[390]
    DIRECTION OUTPUT ;
    USE SIGNAL ;
    PORT
      LAYER M4 ;
        RECT 0.000 337.632 0.192 337.656 ;
    END
  END t_out[390]
  PIN t_out[391]
    DIRECTION OUTPUT ;
    USE SIGNAL ;
    PORT
      LAYER M4 ;
        RECT 0.000 337.824 0.192 337.848 ;
    END
  END t_out[391]
  PIN t_out[392]
    DIRECTION OUTPUT ;
    USE SIGNAL ;
    PORT
      LAYER M4 ;
        RECT 0.000 338.016 0.192 338.040 ;
    END
  END t_out[392]
  PIN t_out[393]
    DIRECTION OUTPUT ;
    USE SIGNAL ;
    PORT
      LAYER M4 ;
        RECT 0.000 338.208 0.192 338.232 ;
    END
  END t_out[393]
  PIN t_out[394]
    DIRECTION OUTPUT ;
    USE SIGNAL ;
    PORT
      LAYER M4 ;
        RECT 0.000 338.400 0.192 338.424 ;
    END
  END t_out[394]
  PIN t_out[395]
    DIRECTION OUTPUT ;
    USE SIGNAL ;
    PORT
      LAYER M4 ;
        RECT 0.000 338.592 0.192 338.616 ;
    END
  END t_out[395]
  PIN t_out[396]
    DIRECTION OUTPUT ;
    USE SIGNAL ;
    PORT
      LAYER M4 ;
        RECT 0.000 338.784 0.192 338.808 ;
    END
  END t_out[396]
  PIN t_out[397]
    DIRECTION OUTPUT ;
    USE SIGNAL ;
    PORT
      LAYER M4 ;
        RECT 0.000 338.976 0.192 339.000 ;
    END
  END t_out[397]
  PIN t_out[398]
    DIRECTION OUTPUT ;
    USE SIGNAL ;
    PORT
      LAYER M4 ;
        RECT 0.000 339.168 0.192 339.192 ;
    END
  END t_out[398]
  PIN t_out[399]
    DIRECTION OUTPUT ;
    USE SIGNAL ;
    PORT
      LAYER M4 ;
        RECT 0.000 339.360 0.192 339.384 ;
    END
  END t_out[399]
  PIN t_out[400]
    DIRECTION OUTPUT ;
    USE SIGNAL ;
    PORT
      LAYER M4 ;
        RECT 0.000 339.552 0.192 339.576 ;
    END
  END t_out[400]
  PIN t_out[401]
    DIRECTION OUTPUT ;
    USE SIGNAL ;
    PORT
      LAYER M4 ;
        RECT 0.000 339.744 0.192 339.768 ;
    END
  END t_out[401]
  PIN t_out[402]
    DIRECTION OUTPUT ;
    USE SIGNAL ;
    PORT
      LAYER M4 ;
        RECT 0.000 339.936 0.192 339.960 ;
    END
  END t_out[402]
  PIN t_out[403]
    DIRECTION OUTPUT ;
    USE SIGNAL ;
    PORT
      LAYER M4 ;
        RECT 0.000 340.128 0.192 340.152 ;
    END
  END t_out[403]
  PIN t_out[404]
    DIRECTION OUTPUT ;
    USE SIGNAL ;
    PORT
      LAYER M4 ;
        RECT 0.000 340.320 0.192 340.344 ;
    END
  END t_out[404]
  PIN t_out[405]
    DIRECTION OUTPUT ;
    USE SIGNAL ;
    PORT
      LAYER M4 ;
        RECT 0.000 340.512 0.192 340.536 ;
    END
  END t_out[405]
  PIN t_out[406]
    DIRECTION OUTPUT ;
    USE SIGNAL ;
    PORT
      LAYER M4 ;
        RECT 0.000 340.704 0.192 340.728 ;
    END
  END t_out[406]
  PIN t_out[407]
    DIRECTION OUTPUT ;
    USE SIGNAL ;
    PORT
      LAYER M4 ;
        RECT 0.000 340.896 0.192 340.920 ;
    END
  END t_out[407]
  PIN t_out[408]
    DIRECTION OUTPUT ;
    USE SIGNAL ;
    PORT
      LAYER M4 ;
        RECT 0.000 341.088 0.192 341.112 ;
    END
  END t_out[408]
  PIN t_out[409]
    DIRECTION OUTPUT ;
    USE SIGNAL ;
    PORT
      LAYER M4 ;
        RECT 0.000 341.280 0.192 341.304 ;
    END
  END t_out[409]
  PIN t_out[410]
    DIRECTION OUTPUT ;
    USE SIGNAL ;
    PORT
      LAYER M4 ;
        RECT 0.000 341.472 0.192 341.496 ;
    END
  END t_out[410]
  PIN t_out[411]
    DIRECTION OUTPUT ;
    USE SIGNAL ;
    PORT
      LAYER M4 ;
        RECT 0.000 341.664 0.192 341.688 ;
    END
  END t_out[411]
  PIN t_out[412]
    DIRECTION OUTPUT ;
    USE SIGNAL ;
    PORT
      LAYER M4 ;
        RECT 0.000 341.856 0.192 341.880 ;
    END
  END t_out[412]
  PIN t_out[413]
    DIRECTION OUTPUT ;
    USE SIGNAL ;
    PORT
      LAYER M4 ;
        RECT 0.000 342.048 0.192 342.072 ;
    END
  END t_out[413]
  PIN t_out[414]
    DIRECTION OUTPUT ;
    USE SIGNAL ;
    PORT
      LAYER M4 ;
        RECT 0.000 342.240 0.192 342.264 ;
    END
  END t_out[414]
  PIN t_out[415]
    DIRECTION OUTPUT ;
    USE SIGNAL ;
    PORT
      LAYER M4 ;
        RECT 0.000 342.432 0.192 342.456 ;
    END
  END t_out[415]
  PIN t_out[416]
    DIRECTION OUTPUT ;
    USE SIGNAL ;
    PORT
      LAYER M4 ;
        RECT 0.000 342.624 0.192 342.648 ;
    END
  END t_out[416]
  PIN t_out[417]
    DIRECTION OUTPUT ;
    USE SIGNAL ;
    PORT
      LAYER M4 ;
        RECT 0.000 342.816 0.192 342.840 ;
    END
  END t_out[417]
  PIN t_out[418]
    DIRECTION OUTPUT ;
    USE SIGNAL ;
    PORT
      LAYER M4 ;
        RECT 0.000 343.008 0.192 343.032 ;
    END
  END t_out[418]
  PIN t_out[419]
    DIRECTION OUTPUT ;
    USE SIGNAL ;
    PORT
      LAYER M4 ;
        RECT 0.000 343.200 0.192 343.224 ;
    END
  END t_out[419]
  PIN t_out[420]
    DIRECTION OUTPUT ;
    USE SIGNAL ;
    PORT
      LAYER M4 ;
        RECT 0.000 343.392 0.192 343.416 ;
    END
  END t_out[420]
  PIN t_out[421]
    DIRECTION OUTPUT ;
    USE SIGNAL ;
    PORT
      LAYER M4 ;
        RECT 0.000 343.584 0.192 343.608 ;
    END
  END t_out[421]
  PIN t_out[422]
    DIRECTION OUTPUT ;
    USE SIGNAL ;
    PORT
      LAYER M4 ;
        RECT 0.000 343.776 0.192 343.800 ;
    END
  END t_out[422]
  PIN t_out[423]
    DIRECTION OUTPUT ;
    USE SIGNAL ;
    PORT
      LAYER M4 ;
        RECT 0.000 343.968 0.192 343.992 ;
    END
  END t_out[423]
  PIN t_out[424]
    DIRECTION OUTPUT ;
    USE SIGNAL ;
    PORT
      LAYER M4 ;
        RECT 0.000 344.160 0.192 344.184 ;
    END
  END t_out[424]
  PIN t_out[425]
    DIRECTION OUTPUT ;
    USE SIGNAL ;
    PORT
      LAYER M4 ;
        RECT 0.000 344.352 0.192 344.376 ;
    END
  END t_out[425]
  PIN t_out[426]
    DIRECTION OUTPUT ;
    USE SIGNAL ;
    PORT
      LAYER M4 ;
        RECT 0.000 344.544 0.192 344.568 ;
    END
  END t_out[426]
  PIN t_out[427]
    DIRECTION OUTPUT ;
    USE SIGNAL ;
    PORT
      LAYER M4 ;
        RECT 0.000 344.736 0.192 344.760 ;
    END
  END t_out[427]
  PIN t_out[428]
    DIRECTION OUTPUT ;
    USE SIGNAL ;
    PORT
      LAYER M4 ;
        RECT 0.000 344.928 0.192 344.952 ;
    END
  END t_out[428]
  PIN t_out[429]
    DIRECTION OUTPUT ;
    USE SIGNAL ;
    PORT
      LAYER M4 ;
        RECT 0.000 345.120 0.192 345.144 ;
    END
  END t_out[429]
  PIN t_out[430]
    DIRECTION OUTPUT ;
    USE SIGNAL ;
    PORT
      LAYER M4 ;
        RECT 0.000 345.312 0.192 345.336 ;
    END
  END t_out[430]
  PIN t_out[431]
    DIRECTION OUTPUT ;
    USE SIGNAL ;
    PORT
      LAYER M4 ;
        RECT 0.000 345.504 0.192 345.528 ;
    END
  END t_out[431]
  PIN t_out[432]
    DIRECTION OUTPUT ;
    USE SIGNAL ;
    PORT
      LAYER M4 ;
        RECT 0.000 345.696 0.192 345.720 ;
    END
  END t_out[432]
  PIN t_out[433]
    DIRECTION OUTPUT ;
    USE SIGNAL ;
    PORT
      LAYER M4 ;
        RECT 0.000 345.888 0.192 345.912 ;
    END
  END t_out[433]
  PIN t_out[434]
    DIRECTION OUTPUT ;
    USE SIGNAL ;
    PORT
      LAYER M4 ;
        RECT 0.000 346.080 0.192 346.104 ;
    END
  END t_out[434]
  PIN t_out[435]
    DIRECTION OUTPUT ;
    USE SIGNAL ;
    PORT
      LAYER M4 ;
        RECT 0.000 346.272 0.192 346.296 ;
    END
  END t_out[435]
  PIN t_out[436]
    DIRECTION OUTPUT ;
    USE SIGNAL ;
    PORT
      LAYER M4 ;
        RECT 0.000 346.464 0.192 346.488 ;
    END
  END t_out[436]
  PIN t_out[437]
    DIRECTION OUTPUT ;
    USE SIGNAL ;
    PORT
      LAYER M4 ;
        RECT 0.000 346.656 0.192 346.680 ;
    END
  END t_out[437]
  PIN t_out[438]
    DIRECTION OUTPUT ;
    USE SIGNAL ;
    PORT
      LAYER M4 ;
        RECT 0.000 346.848 0.192 346.872 ;
    END
  END t_out[438]
  PIN t_out[439]
    DIRECTION OUTPUT ;
    USE SIGNAL ;
    PORT
      LAYER M4 ;
        RECT 0.000 347.040 0.192 347.064 ;
    END
  END t_out[439]
  PIN t_out[440]
    DIRECTION OUTPUT ;
    USE SIGNAL ;
    PORT
      LAYER M4 ;
        RECT 0.000 347.232 0.192 347.256 ;
    END
  END t_out[440]
  PIN t_out[441]
    DIRECTION OUTPUT ;
    USE SIGNAL ;
    PORT
      LAYER M4 ;
        RECT 0.000 347.424 0.192 347.448 ;
    END
  END t_out[441]
  PIN t_out[442]
    DIRECTION OUTPUT ;
    USE SIGNAL ;
    PORT
      LAYER M4 ;
        RECT 0.000 347.616 0.192 347.640 ;
    END
  END t_out[442]
  PIN t_out[443]
    DIRECTION OUTPUT ;
    USE SIGNAL ;
    PORT
      LAYER M4 ;
        RECT 0.000 347.808 0.192 347.832 ;
    END
  END t_out[443]
  PIN t_out[444]
    DIRECTION OUTPUT ;
    USE SIGNAL ;
    PORT
      LAYER M4 ;
        RECT 0.000 348.000 0.192 348.024 ;
    END
  END t_out[444]
  PIN t_out[445]
    DIRECTION OUTPUT ;
    USE SIGNAL ;
    PORT
      LAYER M4 ;
        RECT 0.000 348.192 0.192 348.216 ;
    END
  END t_out[445]
  PIN t_out[446]
    DIRECTION OUTPUT ;
    USE SIGNAL ;
    PORT
      LAYER M4 ;
        RECT 0.000 348.384 0.192 348.408 ;
    END
  END t_out[446]
  PIN t_out[447]
    DIRECTION OUTPUT ;
    USE SIGNAL ;
    PORT
      LAYER M4 ;
        RECT 0.000 348.576 0.192 348.600 ;
    END
  END t_out[447]
  PIN t_out[448]
    DIRECTION OUTPUT ;
    USE SIGNAL ;
    PORT
      LAYER M4 ;
        RECT 0.000 348.768 0.192 348.792 ;
    END
  END t_out[448]
  PIN t_out[449]
    DIRECTION OUTPUT ;
    USE SIGNAL ;
    PORT
      LAYER M4 ;
        RECT 0.000 348.960 0.192 348.984 ;
    END
  END t_out[449]
  PIN t_out[450]
    DIRECTION OUTPUT ;
    USE SIGNAL ;
    PORT
      LAYER M4 ;
        RECT 0.000 349.152 0.192 349.176 ;
    END
  END t_out[450]
  PIN t_out[451]
    DIRECTION OUTPUT ;
    USE SIGNAL ;
    PORT
      LAYER M4 ;
        RECT 0.000 349.344 0.192 349.368 ;
    END
  END t_out[451]
  PIN t_out[452]
    DIRECTION OUTPUT ;
    USE SIGNAL ;
    PORT
      LAYER M4 ;
        RECT 0.000 349.536 0.192 349.560 ;
    END
  END t_out[452]
  PIN t_out[453]
    DIRECTION OUTPUT ;
    USE SIGNAL ;
    PORT
      LAYER M4 ;
        RECT 0.000 349.728 0.192 349.752 ;
    END
  END t_out[453]
  PIN t_out[454]
    DIRECTION OUTPUT ;
    USE SIGNAL ;
    PORT
      LAYER M4 ;
        RECT 0.000 349.920 0.192 349.944 ;
    END
  END t_out[454]
  PIN t_out[455]
    DIRECTION OUTPUT ;
    USE SIGNAL ;
    PORT
      LAYER M4 ;
        RECT 0.000 350.112 0.192 350.136 ;
    END
  END t_out[455]
  PIN t_out[456]
    DIRECTION OUTPUT ;
    USE SIGNAL ;
    PORT
      LAYER M4 ;
        RECT 0.000 350.304 0.192 350.328 ;
    END
  END t_out[456]
  PIN t_out[457]
    DIRECTION OUTPUT ;
    USE SIGNAL ;
    PORT
      LAYER M4 ;
        RECT 0.000 350.496 0.192 350.520 ;
    END
  END t_out[457]
  PIN t_out[458]
    DIRECTION OUTPUT ;
    USE SIGNAL ;
    PORT
      LAYER M4 ;
        RECT 0.000 350.688 0.192 350.712 ;
    END
  END t_out[458]
  PIN t_out[459]
    DIRECTION OUTPUT ;
    USE SIGNAL ;
    PORT
      LAYER M4 ;
        RECT 0.000 350.880 0.192 350.904 ;
    END
  END t_out[459]
  PIN t_out[460]
    DIRECTION OUTPUT ;
    USE SIGNAL ;
    PORT
      LAYER M4 ;
        RECT 0.000 351.072 0.192 351.096 ;
    END
  END t_out[460]
  PIN t_out[461]
    DIRECTION OUTPUT ;
    USE SIGNAL ;
    PORT
      LAYER M4 ;
        RECT 0.000 351.264 0.192 351.288 ;
    END
  END t_out[461]
  PIN t_out[462]
    DIRECTION OUTPUT ;
    USE SIGNAL ;
    PORT
      LAYER M4 ;
        RECT 0.000 351.456 0.192 351.480 ;
    END
  END t_out[462]
  PIN t_out[463]
    DIRECTION OUTPUT ;
    USE SIGNAL ;
    PORT
      LAYER M4 ;
        RECT 0.000 351.648 0.192 351.672 ;
    END
  END t_out[463]
  PIN t_out[464]
    DIRECTION OUTPUT ;
    USE SIGNAL ;
    PORT
      LAYER M4 ;
        RECT 0.000 351.840 0.192 351.864 ;
    END
  END t_out[464]
  PIN t_out[465]
    DIRECTION OUTPUT ;
    USE SIGNAL ;
    PORT
      LAYER M4 ;
        RECT 0.000 352.032 0.192 352.056 ;
    END
  END t_out[465]
  PIN t_out[466]
    DIRECTION OUTPUT ;
    USE SIGNAL ;
    PORT
      LAYER M4 ;
        RECT 0.000 352.224 0.192 352.248 ;
    END
  END t_out[466]
  PIN t_out[467]
    DIRECTION OUTPUT ;
    USE SIGNAL ;
    PORT
      LAYER M4 ;
        RECT 0.000 352.416 0.192 352.440 ;
    END
  END t_out[467]
  PIN t_out[468]
    DIRECTION OUTPUT ;
    USE SIGNAL ;
    PORT
      LAYER M4 ;
        RECT 0.000 352.608 0.192 352.632 ;
    END
  END t_out[468]
  PIN t_out[469]
    DIRECTION OUTPUT ;
    USE SIGNAL ;
    PORT
      LAYER M4 ;
        RECT 0.000 352.800 0.192 352.824 ;
    END
  END t_out[469]
  PIN t_out[470]
    DIRECTION OUTPUT ;
    USE SIGNAL ;
    PORT
      LAYER M4 ;
        RECT 0.000 352.992 0.192 353.016 ;
    END
  END t_out[470]
  PIN t_out[471]
    DIRECTION OUTPUT ;
    USE SIGNAL ;
    PORT
      LAYER M4 ;
        RECT 0.000 353.184 0.192 353.208 ;
    END
  END t_out[471]
  PIN t_out[472]
    DIRECTION OUTPUT ;
    USE SIGNAL ;
    PORT
      LAYER M4 ;
        RECT 0.000 353.376 0.192 353.400 ;
    END
  END t_out[472]
  PIN t_out[473]
    DIRECTION OUTPUT ;
    USE SIGNAL ;
    PORT
      LAYER M4 ;
        RECT 0.000 353.568 0.192 353.592 ;
    END
  END t_out[473]
  PIN t_out[474]
    DIRECTION OUTPUT ;
    USE SIGNAL ;
    PORT
      LAYER M4 ;
        RECT 0.000 353.760 0.192 353.784 ;
    END
  END t_out[474]
  PIN t_out[475]
    DIRECTION OUTPUT ;
    USE SIGNAL ;
    PORT
      LAYER M4 ;
        RECT 0.000 353.952 0.192 353.976 ;
    END
  END t_out[475]
  PIN t_out[476]
    DIRECTION OUTPUT ;
    USE SIGNAL ;
    PORT
      LAYER M4 ;
        RECT 0.000 354.144 0.192 354.168 ;
    END
  END t_out[476]
  PIN t_out[477]
    DIRECTION OUTPUT ;
    USE SIGNAL ;
    PORT
      LAYER M4 ;
        RECT 0.000 354.336 0.192 354.360 ;
    END
  END t_out[477]
  PIN t_out[478]
    DIRECTION OUTPUT ;
    USE SIGNAL ;
    PORT
      LAYER M4 ;
        RECT 0.000 354.528 0.192 354.552 ;
    END
  END t_out[478]
  PIN t_out[479]
    DIRECTION OUTPUT ;
    USE SIGNAL ;
    PORT
      LAYER M4 ;
        RECT 0.000 354.720 0.192 354.744 ;
    END
  END t_out[479]
  PIN t_out[480]
    DIRECTION OUTPUT ;
    USE SIGNAL ;
    PORT
      LAYER M4 ;
        RECT 0.000 354.912 0.192 354.936 ;
    END
  END t_out[480]
  PIN t_out[481]
    DIRECTION OUTPUT ;
    USE SIGNAL ;
    PORT
      LAYER M4 ;
        RECT 0.000 355.104 0.192 355.128 ;
    END
  END t_out[481]
  PIN t_out[482]
    DIRECTION OUTPUT ;
    USE SIGNAL ;
    PORT
      LAYER M4 ;
        RECT 0.000 355.296 0.192 355.320 ;
    END
  END t_out[482]
  PIN t_out[483]
    DIRECTION OUTPUT ;
    USE SIGNAL ;
    PORT
      LAYER M4 ;
        RECT 0.000 355.488 0.192 355.512 ;
    END
  END t_out[483]
  PIN t_out[484]
    DIRECTION OUTPUT ;
    USE SIGNAL ;
    PORT
      LAYER M4 ;
        RECT 0.000 355.680 0.192 355.704 ;
    END
  END t_out[484]
  PIN t_out[485]
    DIRECTION OUTPUT ;
    USE SIGNAL ;
    PORT
      LAYER M4 ;
        RECT 0.000 355.872 0.192 355.896 ;
    END
  END t_out[485]
  PIN t_out[486]
    DIRECTION OUTPUT ;
    USE SIGNAL ;
    PORT
      LAYER M4 ;
        RECT 0.000 356.064 0.192 356.088 ;
    END
  END t_out[486]
  PIN t_out[487]
    DIRECTION OUTPUT ;
    USE SIGNAL ;
    PORT
      LAYER M4 ;
        RECT 0.000 356.256 0.192 356.280 ;
    END
  END t_out[487]
  PIN t_out[488]
    DIRECTION OUTPUT ;
    USE SIGNAL ;
    PORT
      LAYER M4 ;
        RECT 0.000 356.448 0.192 356.472 ;
    END
  END t_out[488]
  PIN t_out[489]
    DIRECTION OUTPUT ;
    USE SIGNAL ;
    PORT
      LAYER M4 ;
        RECT 0.000 356.640 0.192 356.664 ;
    END
  END t_out[489]
  PIN t_out[490]
    DIRECTION OUTPUT ;
    USE SIGNAL ;
    PORT
      LAYER M4 ;
        RECT 0.000 356.832 0.192 356.856 ;
    END
  END t_out[490]
  PIN t_out[491]
    DIRECTION OUTPUT ;
    USE SIGNAL ;
    PORT
      LAYER M4 ;
        RECT 0.000 357.024 0.192 357.048 ;
    END
  END t_out[491]
  PIN t_out[492]
    DIRECTION OUTPUT ;
    USE SIGNAL ;
    PORT
      LAYER M4 ;
        RECT 0.000 357.216 0.192 357.240 ;
    END
  END t_out[492]
  PIN t_out[493]
    DIRECTION OUTPUT ;
    USE SIGNAL ;
    PORT
      LAYER M4 ;
        RECT 0.000 357.408 0.192 357.432 ;
    END
  END t_out[493]
  PIN t_out[494]
    DIRECTION OUTPUT ;
    USE SIGNAL ;
    PORT
      LAYER M4 ;
        RECT 0.000 357.600 0.192 357.624 ;
    END
  END t_out[494]
  PIN t_out[495]
    DIRECTION OUTPUT ;
    USE SIGNAL ;
    PORT
      LAYER M4 ;
        RECT 0.000 357.792 0.192 357.816 ;
    END
  END t_out[495]
  PIN t_out[496]
    DIRECTION OUTPUT ;
    USE SIGNAL ;
    PORT
      LAYER M4 ;
        RECT 0.000 357.984 0.192 358.008 ;
    END
  END t_out[496]
  PIN t_out[497]
    DIRECTION OUTPUT ;
    USE SIGNAL ;
    PORT
      LAYER M4 ;
        RECT 0.000 358.176 0.192 358.200 ;
    END
  END t_out[497]
  PIN t_out[498]
    DIRECTION OUTPUT ;
    USE SIGNAL ;
    PORT
      LAYER M4 ;
        RECT 0.000 358.368 0.192 358.392 ;
    END
  END t_out[498]
  PIN t_out[499]
    DIRECTION OUTPUT ;
    USE SIGNAL ;
    PORT
      LAYER M4 ;
        RECT 0.000 358.560 0.192 358.584 ;
    END
  END t_out[499]
  PIN t_out[500]
    DIRECTION OUTPUT ;
    USE SIGNAL ;
    PORT
      LAYER M4 ;
        RECT 0.000 358.752 0.192 358.776 ;
    END
  END t_out[500]
  PIN t_out[501]
    DIRECTION OUTPUT ;
    USE SIGNAL ;
    PORT
      LAYER M4 ;
        RECT 0.000 358.944 0.192 358.968 ;
    END
  END t_out[501]
  PIN t_out[502]
    DIRECTION OUTPUT ;
    USE SIGNAL ;
    PORT
      LAYER M4 ;
        RECT 0.000 359.136 0.192 359.160 ;
    END
  END t_out[502]
  PIN t_out[503]
    DIRECTION OUTPUT ;
    USE SIGNAL ;
    PORT
      LAYER M4 ;
        RECT 0.000 359.328 0.192 359.352 ;
    END
  END t_out[503]
  PIN t_out[504]
    DIRECTION OUTPUT ;
    USE SIGNAL ;
    PORT
      LAYER M4 ;
        RECT 0.000 359.520 0.192 359.544 ;
    END
  END t_out[504]
  PIN t_out[505]
    DIRECTION OUTPUT ;
    USE SIGNAL ;
    PORT
      LAYER M4 ;
        RECT 0.000 359.712 0.192 359.736 ;
    END
  END t_out[505]
  PIN t_out[506]
    DIRECTION OUTPUT ;
    USE SIGNAL ;
    PORT
      LAYER M4 ;
        RECT 0.000 359.904 0.192 359.928 ;
    END
  END t_out[506]
  PIN t_out[507]
    DIRECTION OUTPUT ;
    USE SIGNAL ;
    PORT
      LAYER M4 ;
        RECT 0.000 360.096 0.192 360.120 ;
    END
  END t_out[507]
  PIN t_out[508]
    DIRECTION OUTPUT ;
    USE SIGNAL ;
    PORT
      LAYER M4 ;
        RECT 0.000 360.288 0.192 360.312 ;
    END
  END t_out[508]
  PIN t_out[509]
    DIRECTION OUTPUT ;
    USE SIGNAL ;
    PORT
      LAYER M4 ;
        RECT 0.000 360.480 0.192 360.504 ;
    END
  END t_out[509]
  PIN t_out[510]
    DIRECTION OUTPUT ;
    USE SIGNAL ;
    PORT
      LAYER M4 ;
        RECT 0.000 360.672 0.192 360.696 ;
    END
  END t_out[510]
  PIN t_out[511]
    DIRECTION OUTPUT ;
    USE SIGNAL ;
    PORT
      LAYER M4 ;
        RECT 0.000 360.864 0.192 360.888 ;
    END
  END t_out[511]
  PIN t_out[512]
    DIRECTION OUTPUT ;
    USE SIGNAL ;
    PORT
      LAYER M4 ;
        RECT 0.000 361.056 0.192 361.080 ;
    END
  END t_out[512]
  PIN t_out[513]
    DIRECTION OUTPUT ;
    USE SIGNAL ;
    PORT
      LAYER M4 ;
        RECT 0.000 361.248 0.192 361.272 ;
    END
  END t_out[513]
  PIN n_y[0]
    DIRECTION OUTPUT ;
    USE SIGNAL ;
    PORT
      LAYER M4 ;
        RECT 0.000 363.264 0.192 363.288 ;
    END
  END n_y[0]
  PIN n_y[1]
    DIRECTION OUTPUT ;
    USE SIGNAL ;
    PORT
      LAYER M4 ;
        RECT 0.000 363.456 0.192 363.480 ;
    END
  END n_y[1]
  PIN n_y[2]
    DIRECTION OUTPUT ;
    USE SIGNAL ;
    PORT
      LAYER M4 ;
        RECT 0.000 363.648 0.192 363.672 ;
    END
  END n_y[2]
  PIN n_y[3]
    DIRECTION OUTPUT ;
    USE SIGNAL ;
    PORT
      LAYER M4 ;
        RECT 0.000 363.840 0.192 363.864 ;
    END
  END n_y[3]
  PIN n_y[4]
    DIRECTION OUTPUT ;
    USE SIGNAL ;
    PORT
      LAYER M4 ;
        RECT 0.000 364.032 0.192 364.056 ;
    END
  END n_y[4]
  PIN n_y[5]
    DIRECTION OUTPUT ;
    USE SIGNAL ;
    PORT
      LAYER M4 ;
        RECT 0.000 364.224 0.192 364.248 ;
    END
  END n_y[5]
  PIN n_y[6]
    DIRECTION OUTPUT ;
    USE SIGNAL ;
    PORT
      LAYER M4 ;
        RECT 0.000 364.416 0.192 364.440 ;
    END
  END n_y[6]
  PIN n_y[7]
    DIRECTION OUTPUT ;
    USE SIGNAL ;
    PORT
      LAYER M4 ;
        RECT 0.000 364.608 0.192 364.632 ;
    END
  END n_y[7]
  PIN n_y[8]
    DIRECTION OUTPUT ;
    USE SIGNAL ;
    PORT
      LAYER M4 ;
        RECT 0.000 364.800 0.192 364.824 ;
    END
  END n_y[8]
  PIN n_y[9]
    DIRECTION OUTPUT ;
    USE SIGNAL ;
    PORT
      LAYER M4 ;
        RECT 0.000 364.992 0.192 365.016 ;
    END
  END n_y[9]
  PIN n_y[10]
    DIRECTION OUTPUT ;
    USE SIGNAL ;
    PORT
      LAYER M4 ;
        RECT 0.000 365.184 0.192 365.208 ;
    END
  END n_y[10]
  PIN n_y[11]
    DIRECTION OUTPUT ;
    USE SIGNAL ;
    PORT
      LAYER M4 ;
        RECT 0.000 365.376 0.192 365.400 ;
    END
  END n_y[11]
  PIN n_y[12]
    DIRECTION OUTPUT ;
    USE SIGNAL ;
    PORT
      LAYER M4 ;
        RECT 0.000 365.568 0.192 365.592 ;
    END
  END n_y[12]
  PIN n_y[13]
    DIRECTION OUTPUT ;
    USE SIGNAL ;
    PORT
      LAYER M4 ;
        RECT 0.000 365.760 0.192 365.784 ;
    END
  END n_y[13]
  PIN n_y[14]
    DIRECTION OUTPUT ;
    USE SIGNAL ;
    PORT
      LAYER M4 ;
        RECT 0.000 365.952 0.192 365.976 ;
    END
  END n_y[14]
  PIN n_y[15]
    DIRECTION OUTPUT ;
    USE SIGNAL ;
    PORT
      LAYER M4 ;
        RECT 0.000 366.144 0.192 366.168 ;
    END
  END n_y[15]
  PIN n_y[16]
    DIRECTION OUTPUT ;
    USE SIGNAL ;
    PORT
      LAYER M4 ;
        RECT 0.000 366.336 0.192 366.360 ;
    END
  END n_y[16]
  PIN n_y[17]
    DIRECTION OUTPUT ;
    USE SIGNAL ;
    PORT
      LAYER M4 ;
        RECT 0.000 366.528 0.192 366.552 ;
    END
  END n_y[17]
  PIN n_y[18]
    DIRECTION OUTPUT ;
    USE SIGNAL ;
    PORT
      LAYER M4 ;
        RECT 0.000 366.720 0.192 366.744 ;
    END
  END n_y[18]
  PIN n_y[19]
    DIRECTION OUTPUT ;
    USE SIGNAL ;
    PORT
      LAYER M4 ;
        RECT 0.000 366.912 0.192 366.936 ;
    END
  END n_y[19]
  PIN n_y[20]
    DIRECTION OUTPUT ;
    USE SIGNAL ;
    PORT
      LAYER M4 ;
        RECT 0.000 367.104 0.192 367.128 ;
    END
  END n_y[20]
  PIN n_y[21]
    DIRECTION OUTPUT ;
    USE SIGNAL ;
    PORT
      LAYER M4 ;
        RECT 0.000 367.296 0.192 367.320 ;
    END
  END n_y[21]
  PIN n_y[22]
    DIRECTION OUTPUT ;
    USE SIGNAL ;
    PORT
      LAYER M4 ;
        RECT 0.000 367.488 0.192 367.512 ;
    END
  END n_y[22]
  PIN n_y[23]
    DIRECTION OUTPUT ;
    USE SIGNAL ;
    PORT
      LAYER M4 ;
        RECT 0.000 367.680 0.192 367.704 ;
    END
  END n_y[23]
  PIN n_y[24]
    DIRECTION OUTPUT ;
    USE SIGNAL ;
    PORT
      LAYER M4 ;
        RECT 0.000 367.872 0.192 367.896 ;
    END
  END n_y[24]
  PIN n_y[25]
    DIRECTION OUTPUT ;
    USE SIGNAL ;
    PORT
      LAYER M4 ;
        RECT 0.000 368.064 0.192 368.088 ;
    END
  END n_y[25]
  PIN n_y[26]
    DIRECTION OUTPUT ;
    USE SIGNAL ;
    PORT
      LAYER M4 ;
        RECT 0.000 368.256 0.192 368.280 ;
    END
  END n_y[26]
  PIN n_y[27]
    DIRECTION OUTPUT ;
    USE SIGNAL ;
    PORT
      LAYER M4 ;
        RECT 0.000 368.448 0.192 368.472 ;
    END
  END n_y[27]
  PIN n_y[28]
    DIRECTION OUTPUT ;
    USE SIGNAL ;
    PORT
      LAYER M4 ;
        RECT 0.000 368.640 0.192 368.664 ;
    END
  END n_y[28]
  PIN n_y[29]
    DIRECTION OUTPUT ;
    USE SIGNAL ;
    PORT
      LAYER M4 ;
        RECT 0.000 368.832 0.192 368.856 ;
    END
  END n_y[29]
  PIN n_y[30]
    DIRECTION OUTPUT ;
    USE SIGNAL ;
    PORT
      LAYER M4 ;
        RECT 0.000 369.024 0.192 369.048 ;
    END
  END n_y[30]
  PIN n_y[31]
    DIRECTION OUTPUT ;
    USE SIGNAL ;
    PORT
      LAYER M4 ;
        RECT 0.000 369.216 0.192 369.240 ;
    END
  END n_y[31]
  PIN n_y[32]
    DIRECTION OUTPUT ;
    USE SIGNAL ;
    PORT
      LAYER M4 ;
        RECT 0.000 369.408 0.192 369.432 ;
    END
  END n_y[32]
  PIN n_y[33]
    DIRECTION OUTPUT ;
    USE SIGNAL ;
    PORT
      LAYER M4 ;
        RECT 0.000 369.600 0.192 369.624 ;
    END
  END n_y[33]
  PIN n_y[34]
    DIRECTION OUTPUT ;
    USE SIGNAL ;
    PORT
      LAYER M4 ;
        RECT 0.000 369.792 0.192 369.816 ;
    END
  END n_y[34]
  PIN n_y[35]
    DIRECTION OUTPUT ;
    USE SIGNAL ;
    PORT
      LAYER M4 ;
        RECT 0.000 369.984 0.192 370.008 ;
    END
  END n_y[35]
  PIN n_y[36]
    DIRECTION OUTPUT ;
    USE SIGNAL ;
    PORT
      LAYER M4 ;
        RECT 0.000 370.176 0.192 370.200 ;
    END
  END n_y[36]
  PIN n_y[37]
    DIRECTION OUTPUT ;
    USE SIGNAL ;
    PORT
      LAYER M4 ;
        RECT 0.000 370.368 0.192 370.392 ;
    END
  END n_y[37]
  PIN n_y[38]
    DIRECTION OUTPUT ;
    USE SIGNAL ;
    PORT
      LAYER M4 ;
        RECT 0.000 370.560 0.192 370.584 ;
    END
  END n_y[38]
  PIN n_y[39]
    DIRECTION OUTPUT ;
    USE SIGNAL ;
    PORT
      LAYER M4 ;
        RECT 0.000 370.752 0.192 370.776 ;
    END
  END n_y[39]
  PIN n_y[40]
    DIRECTION OUTPUT ;
    USE SIGNAL ;
    PORT
      LAYER M4 ;
        RECT 0.000 370.944 0.192 370.968 ;
    END
  END n_y[40]
  PIN n_y[41]
    DIRECTION OUTPUT ;
    USE SIGNAL ;
    PORT
      LAYER M4 ;
        RECT 0.000 371.136 0.192 371.160 ;
    END
  END n_y[41]
  PIN n_y[42]
    DIRECTION OUTPUT ;
    USE SIGNAL ;
    PORT
      LAYER M4 ;
        RECT 0.000 371.328 0.192 371.352 ;
    END
  END n_y[42]
  PIN n_y[43]
    DIRECTION OUTPUT ;
    USE SIGNAL ;
    PORT
      LAYER M4 ;
        RECT 0.000 371.520 0.192 371.544 ;
    END
  END n_y[43]
  PIN n_y[44]
    DIRECTION OUTPUT ;
    USE SIGNAL ;
    PORT
      LAYER M4 ;
        RECT 0.000 371.712 0.192 371.736 ;
    END
  END n_y[44]
  PIN n_y[45]
    DIRECTION OUTPUT ;
    USE SIGNAL ;
    PORT
      LAYER M4 ;
        RECT 0.000 371.904 0.192 371.928 ;
    END
  END n_y[45]
  PIN n_y[46]
    DIRECTION OUTPUT ;
    USE SIGNAL ;
    PORT
      LAYER M4 ;
        RECT 0.000 372.096 0.192 372.120 ;
    END
  END n_y[46]
  PIN n_y[47]
    DIRECTION OUTPUT ;
    USE SIGNAL ;
    PORT
      LAYER M4 ;
        RECT 0.000 372.288 0.192 372.312 ;
    END
  END n_y[47]
  PIN n_y[48]
    DIRECTION OUTPUT ;
    USE SIGNAL ;
    PORT
      LAYER M4 ;
        RECT 0.000 372.480 0.192 372.504 ;
    END
  END n_y[48]
  PIN n_y[49]
    DIRECTION OUTPUT ;
    USE SIGNAL ;
    PORT
      LAYER M4 ;
        RECT 0.000 372.672 0.192 372.696 ;
    END
  END n_y[49]
  PIN n_y[50]
    DIRECTION OUTPUT ;
    USE SIGNAL ;
    PORT
      LAYER M4 ;
        RECT 0.000 372.864 0.192 372.888 ;
    END
  END n_y[50]
  PIN n_y[51]
    DIRECTION OUTPUT ;
    USE SIGNAL ;
    PORT
      LAYER M4 ;
        RECT 0.000 373.056 0.192 373.080 ;
    END
  END n_y[51]
  PIN n_y[52]
    DIRECTION OUTPUT ;
    USE SIGNAL ;
    PORT
      LAYER M4 ;
        RECT 0.000 373.248 0.192 373.272 ;
    END
  END n_y[52]
  PIN n_y[53]
    DIRECTION OUTPUT ;
    USE SIGNAL ;
    PORT
      LAYER M4 ;
        RECT 0.000 373.440 0.192 373.464 ;
    END
  END n_y[53]
  PIN n_y[54]
    DIRECTION OUTPUT ;
    USE SIGNAL ;
    PORT
      LAYER M4 ;
        RECT 0.000 373.632 0.192 373.656 ;
    END
  END n_y[54]
  PIN n_y[55]
    DIRECTION OUTPUT ;
    USE SIGNAL ;
    PORT
      LAYER M4 ;
        RECT 0.000 373.824 0.192 373.848 ;
    END
  END n_y[55]
  PIN n_y[56]
    DIRECTION OUTPUT ;
    USE SIGNAL ;
    PORT
      LAYER M4 ;
        RECT 0.000 374.016 0.192 374.040 ;
    END
  END n_y[56]
  PIN n_y[57]
    DIRECTION OUTPUT ;
    USE SIGNAL ;
    PORT
      LAYER M4 ;
        RECT 0.000 374.208 0.192 374.232 ;
    END
  END n_y[57]
  PIN n_y[58]
    DIRECTION OUTPUT ;
    USE SIGNAL ;
    PORT
      LAYER M4 ;
        RECT 0.000 374.400 0.192 374.424 ;
    END
  END n_y[58]
  PIN n_y[59]
    DIRECTION OUTPUT ;
    USE SIGNAL ;
    PORT
      LAYER M4 ;
        RECT 0.000 374.592 0.192 374.616 ;
    END
  END n_y[59]
  PIN n_y[60]
    DIRECTION OUTPUT ;
    USE SIGNAL ;
    PORT
      LAYER M4 ;
        RECT 0.000 374.784 0.192 374.808 ;
    END
  END n_y[60]
  PIN n_y[61]
    DIRECTION OUTPUT ;
    USE SIGNAL ;
    PORT
      LAYER M4 ;
        RECT 0.000 374.976 0.192 375.000 ;
    END
  END n_y[61]
  PIN n_y[62]
    DIRECTION OUTPUT ;
    USE SIGNAL ;
    PORT
      LAYER M4 ;
        RECT 0.000 375.168 0.192 375.192 ;
    END
  END n_y[62]
  PIN n_y[63]
    DIRECTION OUTPUT ;
    USE SIGNAL ;
    PORT
      LAYER M4 ;
        RECT 0.000 375.360 0.192 375.384 ;
    END
  END n_y[63]
  PIN n_y[64]
    DIRECTION OUTPUT ;
    USE SIGNAL ;
    PORT
      LAYER M4 ;
        RECT 0.000 375.552 0.192 375.576 ;
    END
  END n_y[64]
  PIN n_y[65]
    DIRECTION OUTPUT ;
    USE SIGNAL ;
    PORT
      LAYER M4 ;
        RECT 0.000 375.744 0.192 375.768 ;
    END
  END n_y[65]
  PIN n_y[66]
    DIRECTION OUTPUT ;
    USE SIGNAL ;
    PORT
      LAYER M4 ;
        RECT 0.000 375.936 0.192 375.960 ;
    END
  END n_y[66]
  PIN n_y[67]
    DIRECTION OUTPUT ;
    USE SIGNAL ;
    PORT
      LAYER M4 ;
        RECT 0.000 376.128 0.192 376.152 ;
    END
  END n_y[67]
  PIN n_y[68]
    DIRECTION OUTPUT ;
    USE SIGNAL ;
    PORT
      LAYER M4 ;
        RECT 0.000 376.320 0.192 376.344 ;
    END
  END n_y[68]
  PIN n_y[69]
    DIRECTION OUTPUT ;
    USE SIGNAL ;
    PORT
      LAYER M4 ;
        RECT 0.000 376.512 0.192 376.536 ;
    END
  END n_y[69]
  PIN n_y[70]
    DIRECTION OUTPUT ;
    USE SIGNAL ;
    PORT
      LAYER M4 ;
        RECT 0.000 376.704 0.192 376.728 ;
    END
  END n_y[70]
  PIN n_y[71]
    DIRECTION OUTPUT ;
    USE SIGNAL ;
    PORT
      LAYER M4 ;
        RECT 0.000 376.896 0.192 376.920 ;
    END
  END n_y[71]
  PIN n_y[72]
    DIRECTION OUTPUT ;
    USE SIGNAL ;
    PORT
      LAYER M4 ;
        RECT 0.000 377.088 0.192 377.112 ;
    END
  END n_y[72]
  PIN n_y[73]
    DIRECTION OUTPUT ;
    USE SIGNAL ;
    PORT
      LAYER M4 ;
        RECT 0.000 377.280 0.192 377.304 ;
    END
  END n_y[73]
  PIN n_y[74]
    DIRECTION OUTPUT ;
    USE SIGNAL ;
    PORT
      LAYER M4 ;
        RECT 0.000 377.472 0.192 377.496 ;
    END
  END n_y[74]
  PIN n_y[75]
    DIRECTION OUTPUT ;
    USE SIGNAL ;
    PORT
      LAYER M4 ;
        RECT 0.000 377.664 0.192 377.688 ;
    END
  END n_y[75]
  PIN n_y[76]
    DIRECTION OUTPUT ;
    USE SIGNAL ;
    PORT
      LAYER M4 ;
        RECT 0.000 377.856 0.192 377.880 ;
    END
  END n_y[76]
  PIN n_y[77]
    DIRECTION OUTPUT ;
    USE SIGNAL ;
    PORT
      LAYER M4 ;
        RECT 0.000 378.048 0.192 378.072 ;
    END
  END n_y[77]
  PIN n_y[78]
    DIRECTION OUTPUT ;
    USE SIGNAL ;
    PORT
      LAYER M4 ;
        RECT 0.000 378.240 0.192 378.264 ;
    END
  END n_y[78]
  PIN n_y[79]
    DIRECTION OUTPUT ;
    USE SIGNAL ;
    PORT
      LAYER M4 ;
        RECT 0.000 378.432 0.192 378.456 ;
    END
  END n_y[79]
  PIN n_y[80]
    DIRECTION OUTPUT ;
    USE SIGNAL ;
    PORT
      LAYER M4 ;
        RECT 0.000 378.624 0.192 378.648 ;
    END
  END n_y[80]
  PIN n_y[81]
    DIRECTION OUTPUT ;
    USE SIGNAL ;
    PORT
      LAYER M4 ;
        RECT 0.000 378.816 0.192 378.840 ;
    END
  END n_y[81]
  PIN n_y[82]
    DIRECTION OUTPUT ;
    USE SIGNAL ;
    PORT
      LAYER M4 ;
        RECT 0.000 379.008 0.192 379.032 ;
    END
  END n_y[82]
  PIN n_y[83]
    DIRECTION OUTPUT ;
    USE SIGNAL ;
    PORT
      LAYER M4 ;
        RECT 0.000 379.200 0.192 379.224 ;
    END
  END n_y[83]
  PIN n_y[84]
    DIRECTION OUTPUT ;
    USE SIGNAL ;
    PORT
      LAYER M4 ;
        RECT 0.000 379.392 0.192 379.416 ;
    END
  END n_y[84]
  PIN n_y[85]
    DIRECTION OUTPUT ;
    USE SIGNAL ;
    PORT
      LAYER M4 ;
        RECT 0.000 379.584 0.192 379.608 ;
    END
  END n_y[85]
  PIN n_y[86]
    DIRECTION OUTPUT ;
    USE SIGNAL ;
    PORT
      LAYER M4 ;
        RECT 0.000 379.776 0.192 379.800 ;
    END
  END n_y[86]
  PIN n_y[87]
    DIRECTION OUTPUT ;
    USE SIGNAL ;
    PORT
      LAYER M4 ;
        RECT 0.000 379.968 0.192 379.992 ;
    END
  END n_y[87]
  PIN n_y[88]
    DIRECTION OUTPUT ;
    USE SIGNAL ;
    PORT
      LAYER M4 ;
        RECT 0.000 380.160 0.192 380.184 ;
    END
  END n_y[88]
  PIN n_y[89]
    DIRECTION OUTPUT ;
    USE SIGNAL ;
    PORT
      LAYER M4 ;
        RECT 0.000 380.352 0.192 380.376 ;
    END
  END n_y[89]
  PIN n_y[90]
    DIRECTION OUTPUT ;
    USE SIGNAL ;
    PORT
      LAYER M4 ;
        RECT 0.000 380.544 0.192 380.568 ;
    END
  END n_y[90]
  PIN n_y[91]
    DIRECTION OUTPUT ;
    USE SIGNAL ;
    PORT
      LAYER M4 ;
        RECT 0.000 380.736 0.192 380.760 ;
    END
  END n_y[91]
  PIN n_y[92]
    DIRECTION OUTPUT ;
    USE SIGNAL ;
    PORT
      LAYER M4 ;
        RECT 0.000 380.928 0.192 380.952 ;
    END
  END n_y[92]
  PIN n_y[93]
    DIRECTION OUTPUT ;
    USE SIGNAL ;
    PORT
      LAYER M4 ;
        RECT 0.000 381.120 0.192 381.144 ;
    END
  END n_y[93]
  PIN n_y[94]
    DIRECTION OUTPUT ;
    USE SIGNAL ;
    PORT
      LAYER M4 ;
        RECT 0.000 381.312 0.192 381.336 ;
    END
  END n_y[94]
  PIN n_y[95]
    DIRECTION OUTPUT ;
    USE SIGNAL ;
    PORT
      LAYER M4 ;
        RECT 0.000 381.504 0.192 381.528 ;
    END
  END n_y[95]
  PIN n_y[96]
    DIRECTION OUTPUT ;
    USE SIGNAL ;
    PORT
      LAYER M4 ;
        RECT 0.000 381.696 0.192 381.720 ;
    END
  END n_y[96]
  PIN n_y[97]
    DIRECTION OUTPUT ;
    USE SIGNAL ;
    PORT
      LAYER M4 ;
        RECT 0.000 381.888 0.192 381.912 ;
    END
  END n_y[97]
  PIN n_y[98]
    DIRECTION OUTPUT ;
    USE SIGNAL ;
    PORT
      LAYER M4 ;
        RECT 0.000 382.080 0.192 382.104 ;
    END
  END n_y[98]
  PIN n_y[99]
    DIRECTION OUTPUT ;
    USE SIGNAL ;
    PORT
      LAYER M4 ;
        RECT 0.000 382.272 0.192 382.296 ;
    END
  END n_y[99]
  PIN n_y[100]
    DIRECTION OUTPUT ;
    USE SIGNAL ;
    PORT
      LAYER M4 ;
        RECT 0.000 382.464 0.192 382.488 ;
    END
  END n_y[100]
  PIN n_y[101]
    DIRECTION OUTPUT ;
    USE SIGNAL ;
    PORT
      LAYER M4 ;
        RECT 0.000 382.656 0.192 382.680 ;
    END
  END n_y[101]
  PIN n_y[102]
    DIRECTION OUTPUT ;
    USE SIGNAL ;
    PORT
      LAYER M4 ;
        RECT 0.000 382.848 0.192 382.872 ;
    END
  END n_y[102]
  PIN n_y[103]
    DIRECTION OUTPUT ;
    USE SIGNAL ;
    PORT
      LAYER M4 ;
        RECT 0.000 383.040 0.192 383.064 ;
    END
  END n_y[103]
  PIN n_y[104]
    DIRECTION OUTPUT ;
    USE SIGNAL ;
    PORT
      LAYER M4 ;
        RECT 0.000 383.232 0.192 383.256 ;
    END
  END n_y[104]
  PIN n_y[105]
    DIRECTION OUTPUT ;
    USE SIGNAL ;
    PORT
      LAYER M4 ;
        RECT 0.000 383.424 0.192 383.448 ;
    END
  END n_y[105]
  PIN n_y[106]
    DIRECTION OUTPUT ;
    USE SIGNAL ;
    PORT
      LAYER M4 ;
        RECT 0.000 383.616 0.192 383.640 ;
    END
  END n_y[106]
  PIN n_y[107]
    DIRECTION OUTPUT ;
    USE SIGNAL ;
    PORT
      LAYER M4 ;
        RECT 0.000 383.808 0.192 383.832 ;
    END
  END n_y[107]
  PIN n_y[108]
    DIRECTION OUTPUT ;
    USE SIGNAL ;
    PORT
      LAYER M4 ;
        RECT 0.000 384.000 0.192 384.024 ;
    END
  END n_y[108]
  PIN n_y[109]
    DIRECTION OUTPUT ;
    USE SIGNAL ;
    PORT
      LAYER M4 ;
        RECT 0.000 384.192 0.192 384.216 ;
    END
  END n_y[109]
  PIN n_y[110]
    DIRECTION OUTPUT ;
    USE SIGNAL ;
    PORT
      LAYER M4 ;
        RECT 0.000 384.384 0.192 384.408 ;
    END
  END n_y[110]
  PIN n_y[111]
    DIRECTION OUTPUT ;
    USE SIGNAL ;
    PORT
      LAYER M4 ;
        RECT 0.000 384.576 0.192 384.600 ;
    END
  END n_y[111]
  PIN n_y[112]
    DIRECTION OUTPUT ;
    USE SIGNAL ;
    PORT
      LAYER M4 ;
        RECT 0.000 384.768 0.192 384.792 ;
    END
  END n_y[112]
  PIN n_y[113]
    DIRECTION OUTPUT ;
    USE SIGNAL ;
    PORT
      LAYER M4 ;
        RECT 0.000 384.960 0.192 384.984 ;
    END
  END n_y[113]
  PIN n_y[114]
    DIRECTION OUTPUT ;
    USE SIGNAL ;
    PORT
      LAYER M4 ;
        RECT 0.000 385.152 0.192 385.176 ;
    END
  END n_y[114]
  PIN n_y[115]
    DIRECTION OUTPUT ;
    USE SIGNAL ;
    PORT
      LAYER M4 ;
        RECT 0.000 385.344 0.192 385.368 ;
    END
  END n_y[115]
  PIN n_y[116]
    DIRECTION OUTPUT ;
    USE SIGNAL ;
    PORT
      LAYER M4 ;
        RECT 0.000 385.536 0.192 385.560 ;
    END
  END n_y[116]
  PIN n_y[117]
    DIRECTION OUTPUT ;
    USE SIGNAL ;
    PORT
      LAYER M4 ;
        RECT 0.000 385.728 0.192 385.752 ;
    END
  END n_y[117]
  PIN n_y[118]
    DIRECTION OUTPUT ;
    USE SIGNAL ;
    PORT
      LAYER M4 ;
        RECT 0.000 385.920 0.192 385.944 ;
    END
  END n_y[118]
  PIN n_y[119]
    DIRECTION OUTPUT ;
    USE SIGNAL ;
    PORT
      LAYER M4 ;
        RECT 0.000 386.112 0.192 386.136 ;
    END
  END n_y[119]
  PIN n_y[120]
    DIRECTION OUTPUT ;
    USE SIGNAL ;
    PORT
      LAYER M4 ;
        RECT 0.000 386.304 0.192 386.328 ;
    END
  END n_y[120]
  PIN n_y[121]
    DIRECTION OUTPUT ;
    USE SIGNAL ;
    PORT
      LAYER M4 ;
        RECT 0.000 386.496 0.192 386.520 ;
    END
  END n_y[121]
  PIN n_y[122]
    DIRECTION OUTPUT ;
    USE SIGNAL ;
    PORT
      LAYER M4 ;
        RECT 0.000 386.688 0.192 386.712 ;
    END
  END n_y[122]
  PIN n_y[123]
    DIRECTION OUTPUT ;
    USE SIGNAL ;
    PORT
      LAYER M4 ;
        RECT 0.000 386.880 0.192 386.904 ;
    END
  END n_y[123]
  PIN n_y[124]
    DIRECTION OUTPUT ;
    USE SIGNAL ;
    PORT
      LAYER M4 ;
        RECT 0.000 387.072 0.192 387.096 ;
    END
  END n_y[124]
  PIN n_y[125]
    DIRECTION OUTPUT ;
    USE SIGNAL ;
    PORT
      LAYER M4 ;
        RECT 0.000 387.264 0.192 387.288 ;
    END
  END n_y[125]
  PIN n_y[126]
    DIRECTION OUTPUT ;
    USE SIGNAL ;
    PORT
      LAYER M4 ;
        RECT 0.000 387.456 0.192 387.480 ;
    END
  END n_y[126]
  PIN n_y[127]
    DIRECTION OUTPUT ;
    USE SIGNAL ;
    PORT
      LAYER M4 ;
        RECT 0.000 387.648 0.192 387.672 ;
    END
  END n_y[127]
  PIN n_y[128]
    DIRECTION OUTPUT ;
    USE SIGNAL ;
    PORT
      LAYER M4 ;
        RECT 0.000 387.840 0.192 387.864 ;
    END
  END n_y[128]
  PIN n_y[129]
    DIRECTION OUTPUT ;
    USE SIGNAL ;
    PORT
      LAYER M4 ;
        RECT 0.000 388.032 0.192 388.056 ;
    END
  END n_y[129]
  PIN n_y[130]
    DIRECTION OUTPUT ;
    USE SIGNAL ;
    PORT
      LAYER M4 ;
        RECT 0.000 388.224 0.192 388.248 ;
    END
  END n_y[130]
  PIN n_y[131]
    DIRECTION OUTPUT ;
    USE SIGNAL ;
    PORT
      LAYER M4 ;
        RECT 0.000 388.416 0.192 388.440 ;
    END
  END n_y[131]
  PIN n_y[132]
    DIRECTION OUTPUT ;
    USE SIGNAL ;
    PORT
      LAYER M4 ;
        RECT 0.000 388.608 0.192 388.632 ;
    END
  END n_y[132]
  PIN n_y[133]
    DIRECTION OUTPUT ;
    USE SIGNAL ;
    PORT
      LAYER M4 ;
        RECT 0.000 388.800 0.192 388.824 ;
    END
  END n_y[133]
  PIN n_y[134]
    DIRECTION OUTPUT ;
    USE SIGNAL ;
    PORT
      LAYER M4 ;
        RECT 0.000 388.992 0.192 389.016 ;
    END
  END n_y[134]
  PIN n_y[135]
    DIRECTION OUTPUT ;
    USE SIGNAL ;
    PORT
      LAYER M4 ;
        RECT 0.000 389.184 0.192 389.208 ;
    END
  END n_y[135]
  PIN n_y[136]
    DIRECTION OUTPUT ;
    USE SIGNAL ;
    PORT
      LAYER M4 ;
        RECT 0.000 389.376 0.192 389.400 ;
    END
  END n_y[136]
  PIN n_y[137]
    DIRECTION OUTPUT ;
    USE SIGNAL ;
    PORT
      LAYER M4 ;
        RECT 0.000 389.568 0.192 389.592 ;
    END
  END n_y[137]
  PIN n_y[138]
    DIRECTION OUTPUT ;
    USE SIGNAL ;
    PORT
      LAYER M4 ;
        RECT 0.000 389.760 0.192 389.784 ;
    END
  END n_y[138]
  PIN n_y[139]
    DIRECTION OUTPUT ;
    USE SIGNAL ;
    PORT
      LAYER M4 ;
        RECT 0.000 389.952 0.192 389.976 ;
    END
  END n_y[139]
  PIN n_y[140]
    DIRECTION OUTPUT ;
    USE SIGNAL ;
    PORT
      LAYER M4 ;
        RECT 0.000 390.144 0.192 390.168 ;
    END
  END n_y[140]
  PIN n_y[141]
    DIRECTION OUTPUT ;
    USE SIGNAL ;
    PORT
      LAYER M4 ;
        RECT 0.000 390.336 0.192 390.360 ;
    END
  END n_y[141]
  PIN n_y[142]
    DIRECTION OUTPUT ;
    USE SIGNAL ;
    PORT
      LAYER M4 ;
        RECT 0.000 390.528 0.192 390.552 ;
    END
  END n_y[142]
  PIN n_y[143]
    DIRECTION OUTPUT ;
    USE SIGNAL ;
    PORT
      LAYER M4 ;
        RECT 0.000 390.720 0.192 390.744 ;
    END
  END n_y[143]
  PIN n_y[144]
    DIRECTION OUTPUT ;
    USE SIGNAL ;
    PORT
      LAYER M4 ;
        RECT 0.000 390.912 0.192 390.936 ;
    END
  END n_y[144]
  PIN n_y[145]
    DIRECTION OUTPUT ;
    USE SIGNAL ;
    PORT
      LAYER M4 ;
        RECT 0.000 391.104 0.192 391.128 ;
    END
  END n_y[145]
  PIN n_y[146]
    DIRECTION OUTPUT ;
    USE SIGNAL ;
    PORT
      LAYER M4 ;
        RECT 0.000 391.296 0.192 391.320 ;
    END
  END n_y[146]
  PIN n_y[147]
    DIRECTION OUTPUT ;
    USE SIGNAL ;
    PORT
      LAYER M4 ;
        RECT 0.000 391.488 0.192 391.512 ;
    END
  END n_y[147]
  PIN n_y[148]
    DIRECTION OUTPUT ;
    USE SIGNAL ;
    PORT
      LAYER M4 ;
        RECT 0.000 391.680 0.192 391.704 ;
    END
  END n_y[148]
  PIN n_y[149]
    DIRECTION OUTPUT ;
    USE SIGNAL ;
    PORT
      LAYER M4 ;
        RECT 0.000 391.872 0.192 391.896 ;
    END
  END n_y[149]
  PIN n_y[150]
    DIRECTION OUTPUT ;
    USE SIGNAL ;
    PORT
      LAYER M4 ;
        RECT 0.000 392.064 0.192 392.088 ;
    END
  END n_y[150]
  PIN n_y[151]
    DIRECTION OUTPUT ;
    USE SIGNAL ;
    PORT
      LAYER M4 ;
        RECT 0.000 392.256 0.192 392.280 ;
    END
  END n_y[151]
  PIN n_y[152]
    DIRECTION OUTPUT ;
    USE SIGNAL ;
    PORT
      LAYER M4 ;
        RECT 0.000 392.448 0.192 392.472 ;
    END
  END n_y[152]
  PIN n_y[153]
    DIRECTION OUTPUT ;
    USE SIGNAL ;
    PORT
      LAYER M4 ;
        RECT 0.000 392.640 0.192 392.664 ;
    END
  END n_y[153]
  PIN n_y[154]
    DIRECTION OUTPUT ;
    USE SIGNAL ;
    PORT
      LAYER M4 ;
        RECT 0.000 392.832 0.192 392.856 ;
    END
  END n_y[154]
  PIN n_y[155]
    DIRECTION OUTPUT ;
    USE SIGNAL ;
    PORT
      LAYER M4 ;
        RECT 0.000 393.024 0.192 393.048 ;
    END
  END n_y[155]
  PIN n_y[156]
    DIRECTION OUTPUT ;
    USE SIGNAL ;
    PORT
      LAYER M4 ;
        RECT 0.000 393.216 0.192 393.240 ;
    END
  END n_y[156]
  PIN n_y[157]
    DIRECTION OUTPUT ;
    USE SIGNAL ;
    PORT
      LAYER M4 ;
        RECT 0.000 393.408 0.192 393.432 ;
    END
  END n_y[157]
  PIN n_y[158]
    DIRECTION OUTPUT ;
    USE SIGNAL ;
    PORT
      LAYER M4 ;
        RECT 0.000 393.600 0.192 393.624 ;
    END
  END n_y[158]
  PIN n_y[159]
    DIRECTION OUTPUT ;
    USE SIGNAL ;
    PORT
      LAYER M4 ;
        RECT 0.000 393.792 0.192 393.816 ;
    END
  END n_y[159]
  PIN n_y[160]
    DIRECTION OUTPUT ;
    USE SIGNAL ;
    PORT
      LAYER M4 ;
        RECT 0.000 393.984 0.192 394.008 ;
    END
  END n_y[160]
  PIN n_y[161]
    DIRECTION OUTPUT ;
    USE SIGNAL ;
    PORT
      LAYER M4 ;
        RECT 0.000 394.176 0.192 394.200 ;
    END
  END n_y[161]
  PIN n_y[162]
    DIRECTION OUTPUT ;
    USE SIGNAL ;
    PORT
      LAYER M4 ;
        RECT 0.000 394.368 0.192 394.392 ;
    END
  END n_y[162]
  PIN n_y[163]
    DIRECTION OUTPUT ;
    USE SIGNAL ;
    PORT
      LAYER M4 ;
        RECT 0.000 394.560 0.192 394.584 ;
    END
  END n_y[163]
  PIN n_y[164]
    DIRECTION OUTPUT ;
    USE SIGNAL ;
    PORT
      LAYER M4 ;
        RECT 0.000 394.752 0.192 394.776 ;
    END
  END n_y[164]
  PIN n_y[165]
    DIRECTION OUTPUT ;
    USE SIGNAL ;
    PORT
      LAYER M4 ;
        RECT 0.000 394.944 0.192 394.968 ;
    END
  END n_y[165]
  PIN n_y[166]
    DIRECTION OUTPUT ;
    USE SIGNAL ;
    PORT
      LAYER M4 ;
        RECT 0.000 395.136 0.192 395.160 ;
    END
  END n_y[166]
  PIN n_y[167]
    DIRECTION OUTPUT ;
    USE SIGNAL ;
    PORT
      LAYER M4 ;
        RECT 0.000 395.328 0.192 395.352 ;
    END
  END n_y[167]
  PIN n_y[168]
    DIRECTION OUTPUT ;
    USE SIGNAL ;
    PORT
      LAYER M4 ;
        RECT 0.000 395.520 0.192 395.544 ;
    END
  END n_y[168]
  PIN n_y[169]
    DIRECTION OUTPUT ;
    USE SIGNAL ;
    PORT
      LAYER M4 ;
        RECT 0.000 395.712 0.192 395.736 ;
    END
  END n_y[169]
  PIN n_y[170]
    DIRECTION OUTPUT ;
    USE SIGNAL ;
    PORT
      LAYER M4 ;
        RECT 0.000 395.904 0.192 395.928 ;
    END
  END n_y[170]
  PIN n_y[171]
    DIRECTION OUTPUT ;
    USE SIGNAL ;
    PORT
      LAYER M4 ;
        RECT 0.000 396.096 0.192 396.120 ;
    END
  END n_y[171]
  PIN n_y[172]
    DIRECTION OUTPUT ;
    USE SIGNAL ;
    PORT
      LAYER M4 ;
        RECT 0.000 396.288 0.192 396.312 ;
    END
  END n_y[172]
  PIN n_y[173]
    DIRECTION OUTPUT ;
    USE SIGNAL ;
    PORT
      LAYER M4 ;
        RECT 0.000 396.480 0.192 396.504 ;
    END
  END n_y[173]
  PIN n_y[174]
    DIRECTION OUTPUT ;
    USE SIGNAL ;
    PORT
      LAYER M4 ;
        RECT 0.000 396.672 0.192 396.696 ;
    END
  END n_y[174]
  PIN n_y[175]
    DIRECTION OUTPUT ;
    USE SIGNAL ;
    PORT
      LAYER M4 ;
        RECT 0.000 396.864 0.192 396.888 ;
    END
  END n_y[175]
  PIN n_y[176]
    DIRECTION OUTPUT ;
    USE SIGNAL ;
    PORT
      LAYER M4 ;
        RECT 0.000 397.056 0.192 397.080 ;
    END
  END n_y[176]
  PIN n_y[177]
    DIRECTION OUTPUT ;
    USE SIGNAL ;
    PORT
      LAYER M4 ;
        RECT 0.000 397.248 0.192 397.272 ;
    END
  END n_y[177]
  PIN n_y[178]
    DIRECTION OUTPUT ;
    USE SIGNAL ;
    PORT
      LAYER M4 ;
        RECT 0.000 397.440 0.192 397.464 ;
    END
  END n_y[178]
  PIN n_y[179]
    DIRECTION OUTPUT ;
    USE SIGNAL ;
    PORT
      LAYER M4 ;
        RECT 0.000 397.632 0.192 397.656 ;
    END
  END n_y[179]
  PIN n_y[180]
    DIRECTION OUTPUT ;
    USE SIGNAL ;
    PORT
      LAYER M4 ;
        RECT 0.000 397.824 0.192 397.848 ;
    END
  END n_y[180]
  PIN n_y[181]
    DIRECTION OUTPUT ;
    USE SIGNAL ;
    PORT
      LAYER M4 ;
        RECT 0.000 398.016 0.192 398.040 ;
    END
  END n_y[181]
  PIN n_y[182]
    DIRECTION OUTPUT ;
    USE SIGNAL ;
    PORT
      LAYER M4 ;
        RECT 0.000 398.208 0.192 398.232 ;
    END
  END n_y[182]
  PIN n_y[183]
    DIRECTION OUTPUT ;
    USE SIGNAL ;
    PORT
      LAYER M4 ;
        RECT 0.000 398.400 0.192 398.424 ;
    END
  END n_y[183]
  PIN n_y[184]
    DIRECTION OUTPUT ;
    USE SIGNAL ;
    PORT
      LAYER M4 ;
        RECT 0.000 398.592 0.192 398.616 ;
    END
  END n_y[184]
  PIN n_y[185]
    DIRECTION OUTPUT ;
    USE SIGNAL ;
    PORT
      LAYER M4 ;
        RECT 0.000 398.784 0.192 398.808 ;
    END
  END n_y[185]
  PIN n_y[186]
    DIRECTION OUTPUT ;
    USE SIGNAL ;
    PORT
      LAYER M4 ;
        RECT 0.000 398.976 0.192 399.000 ;
    END
  END n_y[186]
  PIN n_y[187]
    DIRECTION OUTPUT ;
    USE SIGNAL ;
    PORT
      LAYER M4 ;
        RECT 0.000 399.168 0.192 399.192 ;
    END
  END n_y[187]
  PIN n_y[188]
    DIRECTION OUTPUT ;
    USE SIGNAL ;
    PORT
      LAYER M4 ;
        RECT 0.000 399.360 0.192 399.384 ;
    END
  END n_y[188]
  PIN n_y[189]
    DIRECTION OUTPUT ;
    USE SIGNAL ;
    PORT
      LAYER M4 ;
        RECT 0.000 399.552 0.192 399.576 ;
    END
  END n_y[189]
  PIN n_y[190]
    DIRECTION OUTPUT ;
    USE SIGNAL ;
    PORT
      LAYER M4 ;
        RECT 0.000 399.744 0.192 399.768 ;
    END
  END n_y[190]
  PIN n_y[191]
    DIRECTION OUTPUT ;
    USE SIGNAL ;
    PORT
      LAYER M4 ;
        RECT 0.000 399.936 0.192 399.960 ;
    END
  END n_y[191]
  PIN n_y[192]
    DIRECTION OUTPUT ;
    USE SIGNAL ;
    PORT
      LAYER M4 ;
        RECT 0.000 400.128 0.192 400.152 ;
    END
  END n_y[192]
  PIN n_y[193]
    DIRECTION OUTPUT ;
    USE SIGNAL ;
    PORT
      LAYER M4 ;
        RECT 0.000 400.320 0.192 400.344 ;
    END
  END n_y[193]
  PIN n_y[194]
    DIRECTION OUTPUT ;
    USE SIGNAL ;
    PORT
      LAYER M4 ;
        RECT 0.000 400.512 0.192 400.536 ;
    END
  END n_y[194]
  PIN n_y[195]
    DIRECTION OUTPUT ;
    USE SIGNAL ;
    PORT
      LAYER M4 ;
        RECT 0.000 400.704 0.192 400.728 ;
    END
  END n_y[195]
  PIN n_y[196]
    DIRECTION OUTPUT ;
    USE SIGNAL ;
    PORT
      LAYER M4 ;
        RECT 0.000 400.896 0.192 400.920 ;
    END
  END n_y[196]
  PIN n_y[197]
    DIRECTION OUTPUT ;
    USE SIGNAL ;
    PORT
      LAYER M4 ;
        RECT 0.000 401.088 0.192 401.112 ;
    END
  END n_y[197]
  PIN n_y[198]
    DIRECTION OUTPUT ;
    USE SIGNAL ;
    PORT
      LAYER M4 ;
        RECT 0.000 401.280 0.192 401.304 ;
    END
  END n_y[198]
  PIN n_y[199]
    DIRECTION OUTPUT ;
    USE SIGNAL ;
    PORT
      LAYER M4 ;
        RECT 0.000 401.472 0.192 401.496 ;
    END
  END n_y[199]
  PIN n_y[200]
    DIRECTION OUTPUT ;
    USE SIGNAL ;
    PORT
      LAYER M4 ;
        RECT 0.000 401.664 0.192 401.688 ;
    END
  END n_y[200]
  PIN n_y[201]
    DIRECTION OUTPUT ;
    USE SIGNAL ;
    PORT
      LAYER M4 ;
        RECT 0.000 401.856 0.192 401.880 ;
    END
  END n_y[201]
  PIN n_y[202]
    DIRECTION OUTPUT ;
    USE SIGNAL ;
    PORT
      LAYER M4 ;
        RECT 0.000 402.048 0.192 402.072 ;
    END
  END n_y[202]
  PIN n_y[203]
    DIRECTION OUTPUT ;
    USE SIGNAL ;
    PORT
      LAYER M4 ;
        RECT 0.000 402.240 0.192 402.264 ;
    END
  END n_y[203]
  PIN n_y[204]
    DIRECTION OUTPUT ;
    USE SIGNAL ;
    PORT
      LAYER M4 ;
        RECT 0.000 402.432 0.192 402.456 ;
    END
  END n_y[204]
  PIN n_y[205]
    DIRECTION OUTPUT ;
    USE SIGNAL ;
    PORT
      LAYER M4 ;
        RECT 0.000 402.624 0.192 402.648 ;
    END
  END n_y[205]
  PIN n_y[206]
    DIRECTION OUTPUT ;
    USE SIGNAL ;
    PORT
      LAYER M4 ;
        RECT 0.000 402.816 0.192 402.840 ;
    END
  END n_y[206]
  PIN n_y[207]
    DIRECTION OUTPUT ;
    USE SIGNAL ;
    PORT
      LAYER M4 ;
        RECT 0.000 403.008 0.192 403.032 ;
    END
  END n_y[207]
  PIN n_y[208]
    DIRECTION OUTPUT ;
    USE SIGNAL ;
    PORT
      LAYER M4 ;
        RECT 0.000 403.200 0.192 403.224 ;
    END
  END n_y[208]
  PIN n_y[209]
    DIRECTION OUTPUT ;
    USE SIGNAL ;
    PORT
      LAYER M4 ;
        RECT 0.000 403.392 0.192 403.416 ;
    END
  END n_y[209]
  PIN n_y[210]
    DIRECTION OUTPUT ;
    USE SIGNAL ;
    PORT
      LAYER M4 ;
        RECT 0.000 403.584 0.192 403.608 ;
    END
  END n_y[210]
  PIN n_y[211]
    DIRECTION OUTPUT ;
    USE SIGNAL ;
    PORT
      LAYER M4 ;
        RECT 0.000 403.776 0.192 403.800 ;
    END
  END n_y[211]
  PIN n_y[212]
    DIRECTION OUTPUT ;
    USE SIGNAL ;
    PORT
      LAYER M4 ;
        RECT 0.000 403.968 0.192 403.992 ;
    END
  END n_y[212]
  PIN n_y[213]
    DIRECTION OUTPUT ;
    USE SIGNAL ;
    PORT
      LAYER M4 ;
        RECT 0.000 404.160 0.192 404.184 ;
    END
  END n_y[213]
  PIN n_y[214]
    DIRECTION OUTPUT ;
    USE SIGNAL ;
    PORT
      LAYER M4 ;
        RECT 0.000 404.352 0.192 404.376 ;
    END
  END n_y[214]
  PIN n_y[215]
    DIRECTION OUTPUT ;
    USE SIGNAL ;
    PORT
      LAYER M4 ;
        RECT 0.000 404.544 0.192 404.568 ;
    END
  END n_y[215]
  PIN n_y[216]
    DIRECTION OUTPUT ;
    USE SIGNAL ;
    PORT
      LAYER M4 ;
        RECT 0.000 404.736 0.192 404.760 ;
    END
  END n_y[216]
  PIN n_y[217]
    DIRECTION OUTPUT ;
    USE SIGNAL ;
    PORT
      LAYER M4 ;
        RECT 0.000 404.928 0.192 404.952 ;
    END
  END n_y[217]
  PIN n_y[218]
    DIRECTION OUTPUT ;
    USE SIGNAL ;
    PORT
      LAYER M4 ;
        RECT 0.000 405.120 0.192 405.144 ;
    END
  END n_y[218]
  PIN n_y[219]
    DIRECTION OUTPUT ;
    USE SIGNAL ;
    PORT
      LAYER M4 ;
        RECT 0.000 405.312 0.192 405.336 ;
    END
  END n_y[219]
  PIN n_y[220]
    DIRECTION OUTPUT ;
    USE SIGNAL ;
    PORT
      LAYER M4 ;
        RECT 0.000 405.504 0.192 405.528 ;
    END
  END n_y[220]
  PIN n_y[221]
    DIRECTION OUTPUT ;
    USE SIGNAL ;
    PORT
      LAYER M4 ;
        RECT 0.000 405.696 0.192 405.720 ;
    END
  END n_y[221]
  PIN n_y[222]
    DIRECTION OUTPUT ;
    USE SIGNAL ;
    PORT
      LAYER M4 ;
        RECT 0.000 405.888 0.192 405.912 ;
    END
  END n_y[222]
  PIN n_y[223]
    DIRECTION OUTPUT ;
    USE SIGNAL ;
    PORT
      LAYER M4 ;
        RECT 0.000 406.080 0.192 406.104 ;
    END
  END n_y[223]
  PIN n_y[224]
    DIRECTION OUTPUT ;
    USE SIGNAL ;
    PORT
      LAYER M4 ;
        RECT 0.000 406.272 0.192 406.296 ;
    END
  END n_y[224]
  PIN n_y[225]
    DIRECTION OUTPUT ;
    USE SIGNAL ;
    PORT
      LAYER M4 ;
        RECT 0.000 406.464 0.192 406.488 ;
    END
  END n_y[225]
  PIN n_y[226]
    DIRECTION OUTPUT ;
    USE SIGNAL ;
    PORT
      LAYER M4 ;
        RECT 0.000 406.656 0.192 406.680 ;
    END
  END n_y[226]
  PIN n_y[227]
    DIRECTION OUTPUT ;
    USE SIGNAL ;
    PORT
      LAYER M4 ;
        RECT 0.000 406.848 0.192 406.872 ;
    END
  END n_y[227]
  PIN n_y[228]
    DIRECTION OUTPUT ;
    USE SIGNAL ;
    PORT
      LAYER M4 ;
        RECT 0.000 407.040 0.192 407.064 ;
    END
  END n_y[228]
  PIN n_y[229]
    DIRECTION OUTPUT ;
    USE SIGNAL ;
    PORT
      LAYER M4 ;
        RECT 0.000 407.232 0.192 407.256 ;
    END
  END n_y[229]
  PIN n_y[230]
    DIRECTION OUTPUT ;
    USE SIGNAL ;
    PORT
      LAYER M4 ;
        RECT 0.000 407.424 0.192 407.448 ;
    END
  END n_y[230]
  PIN n_y[231]
    DIRECTION OUTPUT ;
    USE SIGNAL ;
    PORT
      LAYER M4 ;
        RECT 0.000 407.616 0.192 407.640 ;
    END
  END n_y[231]
  PIN n_y[232]
    DIRECTION OUTPUT ;
    USE SIGNAL ;
    PORT
      LAYER M4 ;
        RECT 0.000 407.808 0.192 407.832 ;
    END
  END n_y[232]
  PIN n_y[233]
    DIRECTION OUTPUT ;
    USE SIGNAL ;
    PORT
      LAYER M4 ;
        RECT 0.000 408.000 0.192 408.024 ;
    END
  END n_y[233]
  PIN n_y[234]
    DIRECTION OUTPUT ;
    USE SIGNAL ;
    PORT
      LAYER M4 ;
        RECT 0.000 408.192 0.192 408.216 ;
    END
  END n_y[234]
  PIN n_y[235]
    DIRECTION OUTPUT ;
    USE SIGNAL ;
    PORT
      LAYER M4 ;
        RECT 0.000 408.384 0.192 408.408 ;
    END
  END n_y[235]
  PIN n_y[236]
    DIRECTION OUTPUT ;
    USE SIGNAL ;
    PORT
      LAYER M4 ;
        RECT 0.000 408.576 0.192 408.600 ;
    END
  END n_y[236]
  PIN n_y[237]
    DIRECTION OUTPUT ;
    USE SIGNAL ;
    PORT
      LAYER M4 ;
        RECT 0.000 408.768 0.192 408.792 ;
    END
  END n_y[237]
  PIN n_y[238]
    DIRECTION OUTPUT ;
    USE SIGNAL ;
    PORT
      LAYER M4 ;
        RECT 0.000 408.960 0.192 408.984 ;
    END
  END n_y[238]
  PIN n_y[239]
    DIRECTION OUTPUT ;
    USE SIGNAL ;
    PORT
      LAYER M4 ;
        RECT 0.000 409.152 0.192 409.176 ;
    END
  END n_y[239]
  PIN n_y[240]
    DIRECTION OUTPUT ;
    USE SIGNAL ;
    PORT
      LAYER M4 ;
        RECT 0.000 409.344 0.192 409.368 ;
    END
  END n_y[240]
  PIN n_y[241]
    DIRECTION OUTPUT ;
    USE SIGNAL ;
    PORT
      LAYER M4 ;
        RECT 0.000 409.536 0.192 409.560 ;
    END
  END n_y[241]
  PIN n_y[242]
    DIRECTION OUTPUT ;
    USE SIGNAL ;
    PORT
      LAYER M4 ;
        RECT 0.000 409.728 0.192 409.752 ;
    END
  END n_y[242]
  PIN n_y[243]
    DIRECTION OUTPUT ;
    USE SIGNAL ;
    PORT
      LAYER M4 ;
        RECT 0.000 409.920 0.192 409.944 ;
    END
  END n_y[243]
  PIN n_y[244]
    DIRECTION OUTPUT ;
    USE SIGNAL ;
    PORT
      LAYER M4 ;
        RECT 0.000 410.112 0.192 410.136 ;
    END
  END n_y[244]
  PIN n_y[245]
    DIRECTION OUTPUT ;
    USE SIGNAL ;
    PORT
      LAYER M4 ;
        RECT 0.000 410.304 0.192 410.328 ;
    END
  END n_y[245]
  PIN n_y[246]
    DIRECTION OUTPUT ;
    USE SIGNAL ;
    PORT
      LAYER M4 ;
        RECT 0.000 410.496 0.192 410.520 ;
    END
  END n_y[246]
  PIN n_y[247]
    DIRECTION OUTPUT ;
    USE SIGNAL ;
    PORT
      LAYER M4 ;
        RECT 0.000 410.688 0.192 410.712 ;
    END
  END n_y[247]
  PIN n_y[248]
    DIRECTION OUTPUT ;
    USE SIGNAL ;
    PORT
      LAYER M4 ;
        RECT 0.000 410.880 0.192 410.904 ;
    END
  END n_y[248]
  PIN n_y[249]
    DIRECTION OUTPUT ;
    USE SIGNAL ;
    PORT
      LAYER M4 ;
        RECT 0.000 411.072 0.192 411.096 ;
    END
  END n_y[249]
  PIN n_y[250]
    DIRECTION OUTPUT ;
    USE SIGNAL ;
    PORT
      LAYER M4 ;
        RECT 0.000 411.264 0.192 411.288 ;
    END
  END n_y[250]
  PIN n_y[251]
    DIRECTION OUTPUT ;
    USE SIGNAL ;
    PORT
      LAYER M4 ;
        RECT 0.000 411.456 0.192 411.480 ;
    END
  END n_y[251]
  PIN n_y[252]
    DIRECTION OUTPUT ;
    USE SIGNAL ;
    PORT
      LAYER M4 ;
        RECT 0.000 411.648 0.192 411.672 ;
    END
  END n_y[252]
  PIN n_y[253]
    DIRECTION OUTPUT ;
    USE SIGNAL ;
    PORT
      LAYER M4 ;
        RECT 0.000 411.840 0.192 411.864 ;
    END
  END n_y[253]
  PIN n_y[254]
    DIRECTION OUTPUT ;
    USE SIGNAL ;
    PORT
      LAYER M4 ;
        RECT 0.000 412.032 0.192 412.056 ;
    END
  END n_y[254]
  PIN n_y[255]
    DIRECTION OUTPUT ;
    USE SIGNAL ;
    PORT
      LAYER M4 ;
        RECT 0.000 412.224 0.192 412.248 ;
    END
  END n_y[255]
  PIN n_y[256]
    DIRECTION OUTPUT ;
    USE SIGNAL ;
    PORT
      LAYER M4 ;
        RECT 0.000 412.416 0.192 412.440 ;
    END
  END n_y[256]
  PIN n_y[257]
    DIRECTION OUTPUT ;
    USE SIGNAL ;
    PORT
      LAYER M4 ;
        RECT 0.000 412.608 0.192 412.632 ;
    END
  END n_y[257]
  PIN n_y[258]
    DIRECTION OUTPUT ;
    USE SIGNAL ;
    PORT
      LAYER M4 ;
        RECT 0.000 412.800 0.192 412.824 ;
    END
  END n_y[258]
  PIN n_y[259]
    DIRECTION OUTPUT ;
    USE SIGNAL ;
    PORT
      LAYER M4 ;
        RECT 0.000 412.992 0.192 413.016 ;
    END
  END n_y[259]
  PIN n_y[260]
    DIRECTION OUTPUT ;
    USE SIGNAL ;
    PORT
      LAYER M4 ;
        RECT 0.000 413.184 0.192 413.208 ;
    END
  END n_y[260]
  PIN n_y[261]
    DIRECTION OUTPUT ;
    USE SIGNAL ;
    PORT
      LAYER M4 ;
        RECT 0.000 413.376 0.192 413.400 ;
    END
  END n_y[261]
  PIN n_y[262]
    DIRECTION OUTPUT ;
    USE SIGNAL ;
    PORT
      LAYER M4 ;
        RECT 0.000 413.568 0.192 413.592 ;
    END
  END n_y[262]
  PIN n_y[263]
    DIRECTION OUTPUT ;
    USE SIGNAL ;
    PORT
      LAYER M4 ;
        RECT 0.000 413.760 0.192 413.784 ;
    END
  END n_y[263]
  PIN n_y[264]
    DIRECTION OUTPUT ;
    USE SIGNAL ;
    PORT
      LAYER M4 ;
        RECT 0.000 413.952 0.192 413.976 ;
    END
  END n_y[264]
  PIN n_y[265]
    DIRECTION OUTPUT ;
    USE SIGNAL ;
    PORT
      LAYER M4 ;
        RECT 0.000 414.144 0.192 414.168 ;
    END
  END n_y[265]
  PIN n_y[266]
    DIRECTION OUTPUT ;
    USE SIGNAL ;
    PORT
      LAYER M4 ;
        RECT 0.000 414.336 0.192 414.360 ;
    END
  END n_y[266]
  PIN n_y[267]
    DIRECTION OUTPUT ;
    USE SIGNAL ;
    PORT
      LAYER M4 ;
        RECT 0.000 414.528 0.192 414.552 ;
    END
  END n_y[267]
  PIN n_y[268]
    DIRECTION OUTPUT ;
    USE SIGNAL ;
    PORT
      LAYER M4 ;
        RECT 0.000 414.720 0.192 414.744 ;
    END
  END n_y[268]
  PIN n_y[269]
    DIRECTION OUTPUT ;
    USE SIGNAL ;
    PORT
      LAYER M4 ;
        RECT 0.000 414.912 0.192 414.936 ;
    END
  END n_y[269]
  PIN n_y[270]
    DIRECTION OUTPUT ;
    USE SIGNAL ;
    PORT
      LAYER M4 ;
        RECT 0.000 415.104 0.192 415.128 ;
    END
  END n_y[270]
  PIN n_y[271]
    DIRECTION OUTPUT ;
    USE SIGNAL ;
    PORT
      LAYER M4 ;
        RECT 0.000 415.296 0.192 415.320 ;
    END
  END n_y[271]
  PIN n_y[272]
    DIRECTION OUTPUT ;
    USE SIGNAL ;
    PORT
      LAYER M4 ;
        RECT 0.000 415.488 0.192 415.512 ;
    END
  END n_y[272]
  PIN n_y[273]
    DIRECTION OUTPUT ;
    USE SIGNAL ;
    PORT
      LAYER M4 ;
        RECT 0.000 415.680 0.192 415.704 ;
    END
  END n_y[273]
  PIN n_y[274]
    DIRECTION OUTPUT ;
    USE SIGNAL ;
    PORT
      LAYER M4 ;
        RECT 0.000 415.872 0.192 415.896 ;
    END
  END n_y[274]
  PIN n_y[275]
    DIRECTION OUTPUT ;
    USE SIGNAL ;
    PORT
      LAYER M4 ;
        RECT 0.000 416.064 0.192 416.088 ;
    END
  END n_y[275]
  PIN n_y[276]
    DIRECTION OUTPUT ;
    USE SIGNAL ;
    PORT
      LAYER M4 ;
        RECT 0.000 416.256 0.192 416.280 ;
    END
  END n_y[276]
  PIN n_y[277]
    DIRECTION OUTPUT ;
    USE SIGNAL ;
    PORT
      LAYER M4 ;
        RECT 0.000 416.448 0.192 416.472 ;
    END
  END n_y[277]
  PIN n_y[278]
    DIRECTION OUTPUT ;
    USE SIGNAL ;
    PORT
      LAYER M4 ;
        RECT 0.000 416.640 0.192 416.664 ;
    END
  END n_y[278]
  PIN n_y[279]
    DIRECTION OUTPUT ;
    USE SIGNAL ;
    PORT
      LAYER M4 ;
        RECT 0.000 416.832 0.192 416.856 ;
    END
  END n_y[279]
  PIN n_y[280]
    DIRECTION OUTPUT ;
    USE SIGNAL ;
    PORT
      LAYER M4 ;
        RECT 0.000 417.024 0.192 417.048 ;
    END
  END n_y[280]
  PIN n_y[281]
    DIRECTION OUTPUT ;
    USE SIGNAL ;
    PORT
      LAYER M4 ;
        RECT 0.000 417.216 0.192 417.240 ;
    END
  END n_y[281]
  PIN n_y[282]
    DIRECTION OUTPUT ;
    USE SIGNAL ;
    PORT
      LAYER M4 ;
        RECT 0.000 417.408 0.192 417.432 ;
    END
  END n_y[282]
  PIN n_y[283]
    DIRECTION OUTPUT ;
    USE SIGNAL ;
    PORT
      LAYER M4 ;
        RECT 0.000 417.600 0.192 417.624 ;
    END
  END n_y[283]
  PIN n_y[284]
    DIRECTION OUTPUT ;
    USE SIGNAL ;
    PORT
      LAYER M4 ;
        RECT 0.000 417.792 0.192 417.816 ;
    END
  END n_y[284]
  PIN n_y[285]
    DIRECTION OUTPUT ;
    USE SIGNAL ;
    PORT
      LAYER M4 ;
        RECT 0.000 417.984 0.192 418.008 ;
    END
  END n_y[285]
  PIN n_y[286]
    DIRECTION OUTPUT ;
    USE SIGNAL ;
    PORT
      LAYER M4 ;
        RECT 0.000 418.176 0.192 418.200 ;
    END
  END n_y[286]
  PIN n_y[287]
    DIRECTION OUTPUT ;
    USE SIGNAL ;
    PORT
      LAYER M4 ;
        RECT 0.000 418.368 0.192 418.392 ;
    END
  END n_y[287]
  PIN n_y[288]
    DIRECTION OUTPUT ;
    USE SIGNAL ;
    PORT
      LAYER M4 ;
        RECT 0.000 418.560 0.192 418.584 ;
    END
  END n_y[288]
  PIN n_y[289]
    DIRECTION OUTPUT ;
    USE SIGNAL ;
    PORT
      LAYER M4 ;
        RECT 0.000 418.752 0.192 418.776 ;
    END
  END n_y[289]
  PIN n_y[290]
    DIRECTION OUTPUT ;
    USE SIGNAL ;
    PORT
      LAYER M4 ;
        RECT 0.000 418.944 0.192 418.968 ;
    END
  END n_y[290]
  PIN n_y[291]
    DIRECTION OUTPUT ;
    USE SIGNAL ;
    PORT
      LAYER M4 ;
        RECT 0.000 419.136 0.192 419.160 ;
    END
  END n_y[291]
  PIN n_y[292]
    DIRECTION OUTPUT ;
    USE SIGNAL ;
    PORT
      LAYER M4 ;
        RECT 0.000 419.328 0.192 419.352 ;
    END
  END n_y[292]
  PIN n_y[293]
    DIRECTION OUTPUT ;
    USE SIGNAL ;
    PORT
      LAYER M4 ;
        RECT 0.000 419.520 0.192 419.544 ;
    END
  END n_y[293]
  PIN n_y[294]
    DIRECTION OUTPUT ;
    USE SIGNAL ;
    PORT
      LAYER M4 ;
        RECT 0.000 419.712 0.192 419.736 ;
    END
  END n_y[294]
  PIN n_y[295]
    DIRECTION OUTPUT ;
    USE SIGNAL ;
    PORT
      LAYER M4 ;
        RECT 0.000 419.904 0.192 419.928 ;
    END
  END n_y[295]
  PIN n_y[296]
    DIRECTION OUTPUT ;
    USE SIGNAL ;
    PORT
      LAYER M4 ;
        RECT 0.000 420.096 0.192 420.120 ;
    END
  END n_y[296]
  PIN n_y[297]
    DIRECTION OUTPUT ;
    USE SIGNAL ;
    PORT
      LAYER M4 ;
        RECT 0.000 420.288 0.192 420.312 ;
    END
  END n_y[297]
  PIN n_y[298]
    DIRECTION OUTPUT ;
    USE SIGNAL ;
    PORT
      LAYER M4 ;
        RECT 0.000 420.480 0.192 420.504 ;
    END
  END n_y[298]
  PIN n_y[299]
    DIRECTION OUTPUT ;
    USE SIGNAL ;
    PORT
      LAYER M4 ;
        RECT 0.000 420.672 0.192 420.696 ;
    END
  END n_y[299]
  PIN n_y[300]
    DIRECTION OUTPUT ;
    USE SIGNAL ;
    PORT
      LAYER M4 ;
        RECT 0.000 420.864 0.192 420.888 ;
    END
  END n_y[300]
  PIN n_y[301]
    DIRECTION OUTPUT ;
    USE SIGNAL ;
    PORT
      LAYER M4 ;
        RECT 0.000 421.056 0.192 421.080 ;
    END
  END n_y[301]
  PIN n_y[302]
    DIRECTION OUTPUT ;
    USE SIGNAL ;
    PORT
      LAYER M4 ;
        RECT 0.000 421.248 0.192 421.272 ;
    END
  END n_y[302]
  PIN n_y[303]
    DIRECTION OUTPUT ;
    USE SIGNAL ;
    PORT
      LAYER M4 ;
        RECT 0.000 421.440 0.192 421.464 ;
    END
  END n_y[303]
  PIN n_y[304]
    DIRECTION OUTPUT ;
    USE SIGNAL ;
    PORT
      LAYER M4 ;
        RECT 0.000 421.632 0.192 421.656 ;
    END
  END n_y[304]
  PIN n_y[305]
    DIRECTION OUTPUT ;
    USE SIGNAL ;
    PORT
      LAYER M4 ;
        RECT 0.000 421.824 0.192 421.848 ;
    END
  END n_y[305]
  PIN n_y[306]
    DIRECTION OUTPUT ;
    USE SIGNAL ;
    PORT
      LAYER M4 ;
        RECT 0.000 422.016 0.192 422.040 ;
    END
  END n_y[306]
  PIN n_y[307]
    DIRECTION OUTPUT ;
    USE SIGNAL ;
    PORT
      LAYER M4 ;
        RECT 0.000 422.208 0.192 422.232 ;
    END
  END n_y[307]
  PIN n_y[308]
    DIRECTION OUTPUT ;
    USE SIGNAL ;
    PORT
      LAYER M4 ;
        RECT 0.000 422.400 0.192 422.424 ;
    END
  END n_y[308]
  PIN n_y[309]
    DIRECTION OUTPUT ;
    USE SIGNAL ;
    PORT
      LAYER M4 ;
        RECT 0.000 422.592 0.192 422.616 ;
    END
  END n_y[309]
  PIN n_y[310]
    DIRECTION OUTPUT ;
    USE SIGNAL ;
    PORT
      LAYER M4 ;
        RECT 0.000 422.784 0.192 422.808 ;
    END
  END n_y[310]
  PIN n_y[311]
    DIRECTION OUTPUT ;
    USE SIGNAL ;
    PORT
      LAYER M4 ;
        RECT 0.000 422.976 0.192 423.000 ;
    END
  END n_y[311]
  PIN n_y[312]
    DIRECTION OUTPUT ;
    USE SIGNAL ;
    PORT
      LAYER M4 ;
        RECT 0.000 423.168 0.192 423.192 ;
    END
  END n_y[312]
  PIN n_y[313]
    DIRECTION OUTPUT ;
    USE SIGNAL ;
    PORT
      LAYER M4 ;
        RECT 0.000 423.360 0.192 423.384 ;
    END
  END n_y[313]
  PIN n_y[314]
    DIRECTION OUTPUT ;
    USE SIGNAL ;
    PORT
      LAYER M4 ;
        RECT 0.000 423.552 0.192 423.576 ;
    END
  END n_y[314]
  PIN n_y[315]
    DIRECTION OUTPUT ;
    USE SIGNAL ;
    PORT
      LAYER M4 ;
        RECT 0.000 423.744 0.192 423.768 ;
    END
  END n_y[315]
  PIN n_y[316]
    DIRECTION OUTPUT ;
    USE SIGNAL ;
    PORT
      LAYER M4 ;
        RECT 0.000 423.936 0.192 423.960 ;
    END
  END n_y[316]
  PIN n_y[317]
    DIRECTION OUTPUT ;
    USE SIGNAL ;
    PORT
      LAYER M4 ;
        RECT 0.000 424.128 0.192 424.152 ;
    END
  END n_y[317]
  PIN n_y[318]
    DIRECTION OUTPUT ;
    USE SIGNAL ;
    PORT
      LAYER M4 ;
        RECT 0.000 424.320 0.192 424.344 ;
    END
  END n_y[318]
  PIN n_y[319]
    DIRECTION OUTPUT ;
    USE SIGNAL ;
    PORT
      LAYER M4 ;
        RECT 0.000 424.512 0.192 424.536 ;
    END
  END n_y[319]
  PIN n_y[320]
    DIRECTION OUTPUT ;
    USE SIGNAL ;
    PORT
      LAYER M4 ;
        RECT 0.000 424.704 0.192 424.728 ;
    END
  END n_y[320]
  PIN n_y[321]
    DIRECTION OUTPUT ;
    USE SIGNAL ;
    PORT
      LAYER M4 ;
        RECT 0.000 424.896 0.192 424.920 ;
    END
  END n_y[321]
  PIN n_y[322]
    DIRECTION OUTPUT ;
    USE SIGNAL ;
    PORT
      LAYER M4 ;
        RECT 0.000 425.088 0.192 425.112 ;
    END
  END n_y[322]
  PIN n_y[323]
    DIRECTION OUTPUT ;
    USE SIGNAL ;
    PORT
      LAYER M4 ;
        RECT 0.000 425.280 0.192 425.304 ;
    END
  END n_y[323]
  PIN n_y[324]
    DIRECTION OUTPUT ;
    USE SIGNAL ;
    PORT
      LAYER M4 ;
        RECT 0.000 425.472 0.192 425.496 ;
    END
  END n_y[324]
  PIN n_y[325]
    DIRECTION OUTPUT ;
    USE SIGNAL ;
    PORT
      LAYER M4 ;
        RECT 0.000 425.664 0.192 425.688 ;
    END
  END n_y[325]
  PIN n_y[326]
    DIRECTION OUTPUT ;
    USE SIGNAL ;
    PORT
      LAYER M4 ;
        RECT 0.000 425.856 0.192 425.880 ;
    END
  END n_y[326]
  PIN n_y[327]
    DIRECTION OUTPUT ;
    USE SIGNAL ;
    PORT
      LAYER M4 ;
        RECT 0.000 426.048 0.192 426.072 ;
    END
  END n_y[327]
  PIN n_y[328]
    DIRECTION OUTPUT ;
    USE SIGNAL ;
    PORT
      LAYER M4 ;
        RECT 0.000 426.240 0.192 426.264 ;
    END
  END n_y[328]
  PIN n_y[329]
    DIRECTION OUTPUT ;
    USE SIGNAL ;
    PORT
      LAYER M4 ;
        RECT 0.000 426.432 0.192 426.456 ;
    END
  END n_y[329]
  PIN n_y[330]
    DIRECTION OUTPUT ;
    USE SIGNAL ;
    PORT
      LAYER M4 ;
        RECT 0.000 426.624 0.192 426.648 ;
    END
  END n_y[330]
  PIN n_y[331]
    DIRECTION OUTPUT ;
    USE SIGNAL ;
    PORT
      LAYER M4 ;
        RECT 0.000 426.816 0.192 426.840 ;
    END
  END n_y[331]
  PIN n_y[332]
    DIRECTION OUTPUT ;
    USE SIGNAL ;
    PORT
      LAYER M4 ;
        RECT 0.000 427.008 0.192 427.032 ;
    END
  END n_y[332]
  PIN n_y[333]
    DIRECTION OUTPUT ;
    USE SIGNAL ;
    PORT
      LAYER M4 ;
        RECT 0.000 427.200 0.192 427.224 ;
    END
  END n_y[333]
  PIN n_y[334]
    DIRECTION OUTPUT ;
    USE SIGNAL ;
    PORT
      LAYER M4 ;
        RECT 0.000 427.392 0.192 427.416 ;
    END
  END n_y[334]
  PIN n_y[335]
    DIRECTION OUTPUT ;
    USE SIGNAL ;
    PORT
      LAYER M4 ;
        RECT 0.000 427.584 0.192 427.608 ;
    END
  END n_y[335]
  PIN n_y[336]
    DIRECTION OUTPUT ;
    USE SIGNAL ;
    PORT
      LAYER M4 ;
        RECT 0.000 427.776 0.192 427.800 ;
    END
  END n_y[336]
  PIN n_y[337]
    DIRECTION OUTPUT ;
    USE SIGNAL ;
    PORT
      LAYER M4 ;
        RECT 0.000 427.968 0.192 427.992 ;
    END
  END n_y[337]
  PIN n_y[338]
    DIRECTION OUTPUT ;
    USE SIGNAL ;
    PORT
      LAYER M4 ;
        RECT 0.000 428.160 0.192 428.184 ;
    END
  END n_y[338]
  PIN n_y[339]
    DIRECTION OUTPUT ;
    USE SIGNAL ;
    PORT
      LAYER M4 ;
        RECT 0.000 428.352 0.192 428.376 ;
    END
  END n_y[339]
  PIN n_y[340]
    DIRECTION OUTPUT ;
    USE SIGNAL ;
    PORT
      LAYER M4 ;
        RECT 0.000 428.544 0.192 428.568 ;
    END
  END n_y[340]
  PIN n_y[341]
    DIRECTION OUTPUT ;
    USE SIGNAL ;
    PORT
      LAYER M4 ;
        RECT 0.000 428.736 0.192 428.760 ;
    END
  END n_y[341]
  PIN n_y[342]
    DIRECTION OUTPUT ;
    USE SIGNAL ;
    PORT
      LAYER M4 ;
        RECT 0.000 428.928 0.192 428.952 ;
    END
  END n_y[342]
  PIN n_y[343]
    DIRECTION OUTPUT ;
    USE SIGNAL ;
    PORT
      LAYER M4 ;
        RECT 0.000 429.120 0.192 429.144 ;
    END
  END n_y[343]
  PIN n_y[344]
    DIRECTION OUTPUT ;
    USE SIGNAL ;
    PORT
      LAYER M4 ;
        RECT 0.000 429.312 0.192 429.336 ;
    END
  END n_y[344]
  PIN n_y[345]
    DIRECTION OUTPUT ;
    USE SIGNAL ;
    PORT
      LAYER M4 ;
        RECT 0.000 429.504 0.192 429.528 ;
    END
  END n_y[345]
  PIN n_y[346]
    DIRECTION OUTPUT ;
    USE SIGNAL ;
    PORT
      LAYER M4 ;
        RECT 0.000 429.696 0.192 429.720 ;
    END
  END n_y[346]
  PIN n_y[347]
    DIRECTION OUTPUT ;
    USE SIGNAL ;
    PORT
      LAYER M4 ;
        RECT 0.000 429.888 0.192 429.912 ;
    END
  END n_y[347]
  PIN n_y[348]
    DIRECTION OUTPUT ;
    USE SIGNAL ;
    PORT
      LAYER M4 ;
        RECT 0.000 430.080 0.192 430.104 ;
    END
  END n_y[348]
  PIN n_y[349]
    DIRECTION OUTPUT ;
    USE SIGNAL ;
    PORT
      LAYER M4 ;
        RECT 0.000 430.272 0.192 430.296 ;
    END
  END n_y[349]
  PIN n_y[350]
    DIRECTION OUTPUT ;
    USE SIGNAL ;
    PORT
      LAYER M4 ;
        RECT 0.000 430.464 0.192 430.488 ;
    END
  END n_y[350]
  PIN n_y[351]
    DIRECTION OUTPUT ;
    USE SIGNAL ;
    PORT
      LAYER M4 ;
        RECT 0.000 430.656 0.192 430.680 ;
    END
  END n_y[351]
  PIN n_y[352]
    DIRECTION OUTPUT ;
    USE SIGNAL ;
    PORT
      LAYER M4 ;
        RECT 0.000 430.848 0.192 430.872 ;
    END
  END n_y[352]
  PIN n_y[353]
    DIRECTION OUTPUT ;
    USE SIGNAL ;
    PORT
      LAYER M4 ;
        RECT 0.000 431.040 0.192 431.064 ;
    END
  END n_y[353]
  PIN n_y[354]
    DIRECTION OUTPUT ;
    USE SIGNAL ;
    PORT
      LAYER M4 ;
        RECT 0.000 431.232 0.192 431.256 ;
    END
  END n_y[354]
  PIN n_y[355]
    DIRECTION OUTPUT ;
    USE SIGNAL ;
    PORT
      LAYER M4 ;
        RECT 0.000 431.424 0.192 431.448 ;
    END
  END n_y[355]
  PIN n_y[356]
    DIRECTION OUTPUT ;
    USE SIGNAL ;
    PORT
      LAYER M4 ;
        RECT 0.000 431.616 0.192 431.640 ;
    END
  END n_y[356]
  PIN n_y[357]
    DIRECTION OUTPUT ;
    USE SIGNAL ;
    PORT
      LAYER M4 ;
        RECT 0.000 431.808 0.192 431.832 ;
    END
  END n_y[357]
  PIN n_y[358]
    DIRECTION OUTPUT ;
    USE SIGNAL ;
    PORT
      LAYER M4 ;
        RECT 0.000 432.000 0.192 432.024 ;
    END
  END n_y[358]
  PIN n_y[359]
    DIRECTION OUTPUT ;
    USE SIGNAL ;
    PORT
      LAYER M4 ;
        RECT 0.000 432.192 0.192 432.216 ;
    END
  END n_y[359]
  PIN n_y[360]
    DIRECTION OUTPUT ;
    USE SIGNAL ;
    PORT
      LAYER M4 ;
        RECT 0.000 432.384 0.192 432.408 ;
    END
  END n_y[360]
  PIN n_y[361]
    DIRECTION OUTPUT ;
    USE SIGNAL ;
    PORT
      LAYER M4 ;
        RECT 0.000 432.576 0.192 432.600 ;
    END
  END n_y[361]
  PIN n_y[362]
    DIRECTION OUTPUT ;
    USE SIGNAL ;
    PORT
      LAYER M4 ;
        RECT 0.000 432.768 0.192 432.792 ;
    END
  END n_y[362]
  PIN n_y[363]
    DIRECTION OUTPUT ;
    USE SIGNAL ;
    PORT
      LAYER M4 ;
        RECT 0.000 432.960 0.192 432.984 ;
    END
  END n_y[363]
  PIN n_y[364]
    DIRECTION OUTPUT ;
    USE SIGNAL ;
    PORT
      LAYER M4 ;
        RECT 0.000 433.152 0.192 433.176 ;
    END
  END n_y[364]
  PIN n_y[365]
    DIRECTION OUTPUT ;
    USE SIGNAL ;
    PORT
      LAYER M4 ;
        RECT 0.000 433.344 0.192 433.368 ;
    END
  END n_y[365]
  PIN n_y[366]
    DIRECTION OUTPUT ;
    USE SIGNAL ;
    PORT
      LAYER M4 ;
        RECT 0.000 433.536 0.192 433.560 ;
    END
  END n_y[366]
  PIN n_y[367]
    DIRECTION OUTPUT ;
    USE SIGNAL ;
    PORT
      LAYER M4 ;
        RECT 0.000 433.728 0.192 433.752 ;
    END
  END n_y[367]
  PIN n_y[368]
    DIRECTION OUTPUT ;
    USE SIGNAL ;
    PORT
      LAYER M4 ;
        RECT 0.000 433.920 0.192 433.944 ;
    END
  END n_y[368]
  PIN n_y[369]
    DIRECTION OUTPUT ;
    USE SIGNAL ;
    PORT
      LAYER M4 ;
        RECT 0.000 434.112 0.192 434.136 ;
    END
  END n_y[369]
  PIN n_y[370]
    DIRECTION OUTPUT ;
    USE SIGNAL ;
    PORT
      LAYER M4 ;
        RECT 0.000 434.304 0.192 434.328 ;
    END
  END n_y[370]
  PIN n_y[371]
    DIRECTION OUTPUT ;
    USE SIGNAL ;
    PORT
      LAYER M4 ;
        RECT 0.000 434.496 0.192 434.520 ;
    END
  END n_y[371]
  PIN n_y[372]
    DIRECTION OUTPUT ;
    USE SIGNAL ;
    PORT
      LAYER M4 ;
        RECT 0.000 434.688 0.192 434.712 ;
    END
  END n_y[372]
  PIN n_y[373]
    DIRECTION OUTPUT ;
    USE SIGNAL ;
    PORT
      LAYER M4 ;
        RECT 0.000 434.880 0.192 434.904 ;
    END
  END n_y[373]
  PIN n_y[374]
    DIRECTION OUTPUT ;
    USE SIGNAL ;
    PORT
      LAYER M4 ;
        RECT 0.000 435.072 0.192 435.096 ;
    END
  END n_y[374]
  PIN n_y[375]
    DIRECTION OUTPUT ;
    USE SIGNAL ;
    PORT
      LAYER M4 ;
        RECT 0.000 435.264 0.192 435.288 ;
    END
  END n_y[375]
  PIN n_y[376]
    DIRECTION OUTPUT ;
    USE SIGNAL ;
    PORT
      LAYER M4 ;
        RECT 0.000 435.456 0.192 435.480 ;
    END
  END n_y[376]
  PIN n_y[377]
    DIRECTION OUTPUT ;
    USE SIGNAL ;
    PORT
      LAYER M4 ;
        RECT 0.000 435.648 0.192 435.672 ;
    END
  END n_y[377]
  PIN n_y[378]
    DIRECTION OUTPUT ;
    USE SIGNAL ;
    PORT
      LAYER M4 ;
        RECT 0.000 435.840 0.192 435.864 ;
    END
  END n_y[378]
  PIN n_y[379]
    DIRECTION OUTPUT ;
    USE SIGNAL ;
    PORT
      LAYER M4 ;
        RECT 0.000 436.032 0.192 436.056 ;
    END
  END n_y[379]
  PIN n_y[380]
    DIRECTION OUTPUT ;
    USE SIGNAL ;
    PORT
      LAYER M4 ;
        RECT 0.000 436.224 0.192 436.248 ;
    END
  END n_y[380]
  PIN n_y[381]
    DIRECTION OUTPUT ;
    USE SIGNAL ;
    PORT
      LAYER M4 ;
        RECT 0.000 436.416 0.192 436.440 ;
    END
  END n_y[381]
  PIN n_y[382]
    DIRECTION OUTPUT ;
    USE SIGNAL ;
    PORT
      LAYER M4 ;
        RECT 0.000 436.608 0.192 436.632 ;
    END
  END n_y[382]
  PIN n_y[383]
    DIRECTION OUTPUT ;
    USE SIGNAL ;
    PORT
      LAYER M4 ;
        RECT 0.000 436.800 0.192 436.824 ;
    END
  END n_y[383]
  PIN n_y[384]
    DIRECTION OUTPUT ;
    USE SIGNAL ;
    PORT
      LAYER M4 ;
        RECT 0.000 436.992 0.192 437.016 ;
    END
  END n_y[384]
  PIN n_y[385]
    DIRECTION OUTPUT ;
    USE SIGNAL ;
    PORT
      LAYER M4 ;
        RECT 0.000 437.184 0.192 437.208 ;
    END
  END n_y[385]
  PIN n_y[386]
    DIRECTION OUTPUT ;
    USE SIGNAL ;
    PORT
      LAYER M4 ;
        RECT 0.000 437.376 0.192 437.400 ;
    END
  END n_y[386]
  PIN n_y[387]
    DIRECTION OUTPUT ;
    USE SIGNAL ;
    PORT
      LAYER M4 ;
        RECT 0.000 437.568 0.192 437.592 ;
    END
  END n_y[387]
  PIN n_y[388]
    DIRECTION OUTPUT ;
    USE SIGNAL ;
    PORT
      LAYER M4 ;
        RECT 0.000 437.760 0.192 437.784 ;
    END
  END n_y[388]
  PIN n_y[389]
    DIRECTION OUTPUT ;
    USE SIGNAL ;
    PORT
      LAYER M4 ;
        RECT 0.000 437.952 0.192 437.976 ;
    END
  END n_y[389]
  PIN n_y[390]
    DIRECTION OUTPUT ;
    USE SIGNAL ;
    PORT
      LAYER M4 ;
        RECT 0.000 438.144 0.192 438.168 ;
    END
  END n_y[390]
  PIN n_y[391]
    DIRECTION OUTPUT ;
    USE SIGNAL ;
    PORT
      LAYER M4 ;
        RECT 0.000 438.336 0.192 438.360 ;
    END
  END n_y[391]
  PIN n_y[392]
    DIRECTION OUTPUT ;
    USE SIGNAL ;
    PORT
      LAYER M4 ;
        RECT 0.000 438.528 0.192 438.552 ;
    END
  END n_y[392]
  PIN n_y[393]
    DIRECTION OUTPUT ;
    USE SIGNAL ;
    PORT
      LAYER M4 ;
        RECT 0.000 438.720 0.192 438.744 ;
    END
  END n_y[393]
  PIN n_y[394]
    DIRECTION OUTPUT ;
    USE SIGNAL ;
    PORT
      LAYER M4 ;
        RECT 0.000 438.912 0.192 438.936 ;
    END
  END n_y[394]
  PIN n_y[395]
    DIRECTION OUTPUT ;
    USE SIGNAL ;
    PORT
      LAYER M4 ;
        RECT 0.000 439.104 0.192 439.128 ;
    END
  END n_y[395]
  PIN n_y[396]
    DIRECTION OUTPUT ;
    USE SIGNAL ;
    PORT
      LAYER M4 ;
        RECT 0.000 439.296 0.192 439.320 ;
    END
  END n_y[396]
  PIN n_y[397]
    DIRECTION OUTPUT ;
    USE SIGNAL ;
    PORT
      LAYER M4 ;
        RECT 0.000 439.488 0.192 439.512 ;
    END
  END n_y[397]
  PIN n_y[398]
    DIRECTION OUTPUT ;
    USE SIGNAL ;
    PORT
      LAYER M4 ;
        RECT 0.000 439.680 0.192 439.704 ;
    END
  END n_y[398]
  PIN n_y[399]
    DIRECTION OUTPUT ;
    USE SIGNAL ;
    PORT
      LAYER M4 ;
        RECT 0.000 439.872 0.192 439.896 ;
    END
  END n_y[399]
  PIN n_y[400]
    DIRECTION OUTPUT ;
    USE SIGNAL ;
    PORT
      LAYER M4 ;
        RECT 0.000 440.064 0.192 440.088 ;
    END
  END n_y[400]
  PIN n_y[401]
    DIRECTION OUTPUT ;
    USE SIGNAL ;
    PORT
      LAYER M4 ;
        RECT 0.000 440.256 0.192 440.280 ;
    END
  END n_y[401]
  PIN n_y[402]
    DIRECTION OUTPUT ;
    USE SIGNAL ;
    PORT
      LAYER M4 ;
        RECT 0.000 440.448 0.192 440.472 ;
    END
  END n_y[402]
  PIN n_y[403]
    DIRECTION OUTPUT ;
    USE SIGNAL ;
    PORT
      LAYER M4 ;
        RECT 0.000 440.640 0.192 440.664 ;
    END
  END n_y[403]
  PIN n_y[404]
    DIRECTION OUTPUT ;
    USE SIGNAL ;
    PORT
      LAYER M4 ;
        RECT 0.000 440.832 0.192 440.856 ;
    END
  END n_y[404]
  PIN n_y[405]
    DIRECTION OUTPUT ;
    USE SIGNAL ;
    PORT
      LAYER M4 ;
        RECT 0.000 441.024 0.192 441.048 ;
    END
  END n_y[405]
  PIN n_y[406]
    DIRECTION OUTPUT ;
    USE SIGNAL ;
    PORT
      LAYER M4 ;
        RECT 0.000 441.216 0.192 441.240 ;
    END
  END n_y[406]
  PIN n_y[407]
    DIRECTION OUTPUT ;
    USE SIGNAL ;
    PORT
      LAYER M4 ;
        RECT 0.000 441.408 0.192 441.432 ;
    END
  END n_y[407]
  PIN n_y[408]
    DIRECTION OUTPUT ;
    USE SIGNAL ;
    PORT
      LAYER M4 ;
        RECT 0.000 441.600 0.192 441.624 ;
    END
  END n_y[408]
  PIN n_y[409]
    DIRECTION OUTPUT ;
    USE SIGNAL ;
    PORT
      LAYER M4 ;
        RECT 0.000 441.792 0.192 441.816 ;
    END
  END n_y[409]
  PIN n_y[410]
    DIRECTION OUTPUT ;
    USE SIGNAL ;
    PORT
      LAYER M4 ;
        RECT 0.000 441.984 0.192 442.008 ;
    END
  END n_y[410]
  PIN n_y[411]
    DIRECTION OUTPUT ;
    USE SIGNAL ;
    PORT
      LAYER M4 ;
        RECT 0.000 442.176 0.192 442.200 ;
    END
  END n_y[411]
  PIN n_y[412]
    DIRECTION OUTPUT ;
    USE SIGNAL ;
    PORT
      LAYER M4 ;
        RECT 0.000 442.368 0.192 442.392 ;
    END
  END n_y[412]
  PIN n_y[413]
    DIRECTION OUTPUT ;
    USE SIGNAL ;
    PORT
      LAYER M4 ;
        RECT 0.000 442.560 0.192 442.584 ;
    END
  END n_y[413]
  PIN n_y[414]
    DIRECTION OUTPUT ;
    USE SIGNAL ;
    PORT
      LAYER M4 ;
        RECT 0.000 442.752 0.192 442.776 ;
    END
  END n_y[414]
  PIN n_y[415]
    DIRECTION OUTPUT ;
    USE SIGNAL ;
    PORT
      LAYER M4 ;
        RECT 0.000 442.944 0.192 442.968 ;
    END
  END n_y[415]
  PIN n_y[416]
    DIRECTION OUTPUT ;
    USE SIGNAL ;
    PORT
      LAYER M4 ;
        RECT 0.000 443.136 0.192 443.160 ;
    END
  END n_y[416]
  PIN n_y[417]
    DIRECTION OUTPUT ;
    USE SIGNAL ;
    PORT
      LAYER M4 ;
        RECT 0.000 443.328 0.192 443.352 ;
    END
  END n_y[417]
  PIN n_y[418]
    DIRECTION OUTPUT ;
    USE SIGNAL ;
    PORT
      LAYER M4 ;
        RECT 0.000 443.520 0.192 443.544 ;
    END
  END n_y[418]
  PIN n_y[419]
    DIRECTION OUTPUT ;
    USE SIGNAL ;
    PORT
      LAYER M4 ;
        RECT 0.000 443.712 0.192 443.736 ;
    END
  END n_y[419]
  PIN n_y[420]
    DIRECTION OUTPUT ;
    USE SIGNAL ;
    PORT
      LAYER M4 ;
        RECT 0.000 443.904 0.192 443.928 ;
    END
  END n_y[420]
  PIN n_y[421]
    DIRECTION OUTPUT ;
    USE SIGNAL ;
    PORT
      LAYER M4 ;
        RECT 0.000 444.096 0.192 444.120 ;
    END
  END n_y[421]
  PIN n_y[422]
    DIRECTION OUTPUT ;
    USE SIGNAL ;
    PORT
      LAYER M4 ;
        RECT 0.000 444.288 0.192 444.312 ;
    END
  END n_y[422]
  PIN n_y[423]
    DIRECTION OUTPUT ;
    USE SIGNAL ;
    PORT
      LAYER M4 ;
        RECT 0.000 444.480 0.192 444.504 ;
    END
  END n_y[423]
  PIN n_y[424]
    DIRECTION OUTPUT ;
    USE SIGNAL ;
    PORT
      LAYER M4 ;
        RECT 0.000 444.672 0.192 444.696 ;
    END
  END n_y[424]
  PIN n_y[425]
    DIRECTION OUTPUT ;
    USE SIGNAL ;
    PORT
      LAYER M4 ;
        RECT 0.000 444.864 0.192 444.888 ;
    END
  END n_y[425]
  PIN n_y[426]
    DIRECTION OUTPUT ;
    USE SIGNAL ;
    PORT
      LAYER M4 ;
        RECT 0.000 445.056 0.192 445.080 ;
    END
  END n_y[426]
  PIN n_y[427]
    DIRECTION OUTPUT ;
    USE SIGNAL ;
    PORT
      LAYER M4 ;
        RECT 0.000 445.248 0.192 445.272 ;
    END
  END n_y[427]
  PIN n_y[428]
    DIRECTION OUTPUT ;
    USE SIGNAL ;
    PORT
      LAYER M4 ;
        RECT 0.000 445.440 0.192 445.464 ;
    END
  END n_y[428]
  PIN n_y[429]
    DIRECTION OUTPUT ;
    USE SIGNAL ;
    PORT
      LAYER M4 ;
        RECT 0.000 445.632 0.192 445.656 ;
    END
  END n_y[429]
  PIN n_y[430]
    DIRECTION OUTPUT ;
    USE SIGNAL ;
    PORT
      LAYER M4 ;
        RECT 0.000 445.824 0.192 445.848 ;
    END
  END n_y[430]
  PIN n_y[431]
    DIRECTION OUTPUT ;
    USE SIGNAL ;
    PORT
      LAYER M4 ;
        RECT 0.000 446.016 0.192 446.040 ;
    END
  END n_y[431]
  PIN n_y[432]
    DIRECTION OUTPUT ;
    USE SIGNAL ;
    PORT
      LAYER M4 ;
        RECT 0.000 446.208 0.192 446.232 ;
    END
  END n_y[432]
  PIN n_y[433]
    DIRECTION OUTPUT ;
    USE SIGNAL ;
    PORT
      LAYER M4 ;
        RECT 0.000 446.400 0.192 446.424 ;
    END
  END n_y[433]
  PIN n_y[434]
    DIRECTION OUTPUT ;
    USE SIGNAL ;
    PORT
      LAYER M4 ;
        RECT 0.000 446.592 0.192 446.616 ;
    END
  END n_y[434]
  PIN n_y[435]
    DIRECTION OUTPUT ;
    USE SIGNAL ;
    PORT
      LAYER M4 ;
        RECT 0.000 446.784 0.192 446.808 ;
    END
  END n_y[435]
  PIN n_y[436]
    DIRECTION OUTPUT ;
    USE SIGNAL ;
    PORT
      LAYER M4 ;
        RECT 0.000 446.976 0.192 447.000 ;
    END
  END n_y[436]
  PIN n_y[437]
    DIRECTION OUTPUT ;
    USE SIGNAL ;
    PORT
      LAYER M4 ;
        RECT 0.000 447.168 0.192 447.192 ;
    END
  END n_y[437]
  PIN n_y[438]
    DIRECTION OUTPUT ;
    USE SIGNAL ;
    PORT
      LAYER M4 ;
        RECT 0.000 447.360 0.192 447.384 ;
    END
  END n_y[438]
  PIN n_y[439]
    DIRECTION OUTPUT ;
    USE SIGNAL ;
    PORT
      LAYER M4 ;
        RECT 0.000 447.552 0.192 447.576 ;
    END
  END n_y[439]
  PIN n_y[440]
    DIRECTION OUTPUT ;
    USE SIGNAL ;
    PORT
      LAYER M4 ;
        RECT 0.000 447.744 0.192 447.768 ;
    END
  END n_y[440]
  PIN n_y[441]
    DIRECTION OUTPUT ;
    USE SIGNAL ;
    PORT
      LAYER M4 ;
        RECT 0.000 447.936 0.192 447.960 ;
    END
  END n_y[441]
  PIN n_y[442]
    DIRECTION OUTPUT ;
    USE SIGNAL ;
    PORT
      LAYER M4 ;
        RECT 0.000 448.128 0.192 448.152 ;
    END
  END n_y[442]
  PIN n_y[443]
    DIRECTION OUTPUT ;
    USE SIGNAL ;
    PORT
      LAYER M4 ;
        RECT 0.000 448.320 0.192 448.344 ;
    END
  END n_y[443]
  PIN n_y[444]
    DIRECTION OUTPUT ;
    USE SIGNAL ;
    PORT
      LAYER M4 ;
        RECT 0.000 448.512 0.192 448.536 ;
    END
  END n_y[444]
  PIN n_y[445]
    DIRECTION OUTPUT ;
    USE SIGNAL ;
    PORT
      LAYER M4 ;
        RECT 0.000 448.704 0.192 448.728 ;
    END
  END n_y[445]
  PIN n_y[446]
    DIRECTION OUTPUT ;
    USE SIGNAL ;
    PORT
      LAYER M4 ;
        RECT 0.000 448.896 0.192 448.920 ;
    END
  END n_y[446]
  PIN n_y[447]
    DIRECTION OUTPUT ;
    USE SIGNAL ;
    PORT
      LAYER M4 ;
        RECT 0.000 449.088 0.192 449.112 ;
    END
  END n_y[447]
  PIN n_y[448]
    DIRECTION OUTPUT ;
    USE SIGNAL ;
    PORT
      LAYER M4 ;
        RECT 0.000 449.280 0.192 449.304 ;
    END
  END n_y[448]
  PIN n_y[449]
    DIRECTION OUTPUT ;
    USE SIGNAL ;
    PORT
      LAYER M4 ;
        RECT 0.000 449.472 0.192 449.496 ;
    END
  END n_y[449]
  PIN n_y[450]
    DIRECTION OUTPUT ;
    USE SIGNAL ;
    PORT
      LAYER M4 ;
        RECT 0.000 449.664 0.192 449.688 ;
    END
  END n_y[450]
  PIN n_y[451]
    DIRECTION OUTPUT ;
    USE SIGNAL ;
    PORT
      LAYER M4 ;
        RECT 0.000 449.856 0.192 449.880 ;
    END
  END n_y[451]
  PIN n_y[452]
    DIRECTION OUTPUT ;
    USE SIGNAL ;
    PORT
      LAYER M4 ;
        RECT 0.000 450.048 0.192 450.072 ;
    END
  END n_y[452]
  PIN n_y[453]
    DIRECTION OUTPUT ;
    USE SIGNAL ;
    PORT
      LAYER M4 ;
        RECT 0.000 450.240 0.192 450.264 ;
    END
  END n_y[453]
  PIN n_y[454]
    DIRECTION OUTPUT ;
    USE SIGNAL ;
    PORT
      LAYER M4 ;
        RECT 0.000 450.432 0.192 450.456 ;
    END
  END n_y[454]
  PIN n_y[455]
    DIRECTION OUTPUT ;
    USE SIGNAL ;
    PORT
      LAYER M4 ;
        RECT 0.000 450.624 0.192 450.648 ;
    END
  END n_y[455]
  PIN n_y[456]
    DIRECTION OUTPUT ;
    USE SIGNAL ;
    PORT
      LAYER M4 ;
        RECT 0.000 450.816 0.192 450.840 ;
    END
  END n_y[456]
  PIN n_y[457]
    DIRECTION OUTPUT ;
    USE SIGNAL ;
    PORT
      LAYER M4 ;
        RECT 0.000 451.008 0.192 451.032 ;
    END
  END n_y[457]
  PIN n_y[458]
    DIRECTION OUTPUT ;
    USE SIGNAL ;
    PORT
      LAYER M4 ;
        RECT 0.000 451.200 0.192 451.224 ;
    END
  END n_y[458]
  PIN n_y[459]
    DIRECTION OUTPUT ;
    USE SIGNAL ;
    PORT
      LAYER M4 ;
        RECT 0.000 451.392 0.192 451.416 ;
    END
  END n_y[459]
  PIN n_y[460]
    DIRECTION OUTPUT ;
    USE SIGNAL ;
    PORT
      LAYER M4 ;
        RECT 0.000 451.584 0.192 451.608 ;
    END
  END n_y[460]
  PIN n_y[461]
    DIRECTION OUTPUT ;
    USE SIGNAL ;
    PORT
      LAYER M4 ;
        RECT 0.000 451.776 0.192 451.800 ;
    END
  END n_y[461]
  PIN n_y[462]
    DIRECTION OUTPUT ;
    USE SIGNAL ;
    PORT
      LAYER M4 ;
        RECT 0.000 451.968 0.192 451.992 ;
    END
  END n_y[462]
  PIN n_y[463]
    DIRECTION OUTPUT ;
    USE SIGNAL ;
    PORT
      LAYER M4 ;
        RECT 0.000 452.160 0.192 452.184 ;
    END
  END n_y[463]
  PIN n_y[464]
    DIRECTION OUTPUT ;
    USE SIGNAL ;
    PORT
      LAYER M4 ;
        RECT 0.000 452.352 0.192 452.376 ;
    END
  END n_y[464]
  PIN n_y[465]
    DIRECTION OUTPUT ;
    USE SIGNAL ;
    PORT
      LAYER M4 ;
        RECT 0.000 452.544 0.192 452.568 ;
    END
  END n_y[465]
  PIN n_y[466]
    DIRECTION OUTPUT ;
    USE SIGNAL ;
    PORT
      LAYER M4 ;
        RECT 0.000 452.736 0.192 452.760 ;
    END
  END n_y[466]
  PIN n_y[467]
    DIRECTION OUTPUT ;
    USE SIGNAL ;
    PORT
      LAYER M4 ;
        RECT 0.000 452.928 0.192 452.952 ;
    END
  END n_y[467]
  PIN n_y[468]
    DIRECTION OUTPUT ;
    USE SIGNAL ;
    PORT
      LAYER M4 ;
        RECT 0.000 453.120 0.192 453.144 ;
    END
  END n_y[468]
  PIN n_y[469]
    DIRECTION OUTPUT ;
    USE SIGNAL ;
    PORT
      LAYER M4 ;
        RECT 0.000 453.312 0.192 453.336 ;
    END
  END n_y[469]
  PIN n_y[470]
    DIRECTION OUTPUT ;
    USE SIGNAL ;
    PORT
      LAYER M4 ;
        RECT 0.000 453.504 0.192 453.528 ;
    END
  END n_y[470]
  PIN n_y[471]
    DIRECTION OUTPUT ;
    USE SIGNAL ;
    PORT
      LAYER M4 ;
        RECT 0.000 453.696 0.192 453.720 ;
    END
  END n_y[471]
  PIN n_y[472]
    DIRECTION OUTPUT ;
    USE SIGNAL ;
    PORT
      LAYER M4 ;
        RECT 0.000 453.888 0.192 453.912 ;
    END
  END n_y[472]
  PIN n_y[473]
    DIRECTION OUTPUT ;
    USE SIGNAL ;
    PORT
      LAYER M4 ;
        RECT 0.000 454.080 0.192 454.104 ;
    END
  END n_y[473]
  PIN n_y[474]
    DIRECTION OUTPUT ;
    USE SIGNAL ;
    PORT
      LAYER M4 ;
        RECT 0.000 454.272 0.192 454.296 ;
    END
  END n_y[474]
  PIN n_y[475]
    DIRECTION OUTPUT ;
    USE SIGNAL ;
    PORT
      LAYER M4 ;
        RECT 0.000 454.464 0.192 454.488 ;
    END
  END n_y[475]
  PIN n_y[476]
    DIRECTION OUTPUT ;
    USE SIGNAL ;
    PORT
      LAYER M4 ;
        RECT 0.000 454.656 0.192 454.680 ;
    END
  END n_y[476]
  PIN n_y[477]
    DIRECTION OUTPUT ;
    USE SIGNAL ;
    PORT
      LAYER M4 ;
        RECT 0.000 454.848 0.192 454.872 ;
    END
  END n_y[477]
  PIN n_y[478]
    DIRECTION OUTPUT ;
    USE SIGNAL ;
    PORT
      LAYER M4 ;
        RECT 0.000 455.040 0.192 455.064 ;
    END
  END n_y[478]
  PIN n_y[479]
    DIRECTION OUTPUT ;
    USE SIGNAL ;
    PORT
      LAYER M4 ;
        RECT 0.000 455.232 0.192 455.256 ;
    END
  END n_y[479]
  PIN n_y[480]
    DIRECTION OUTPUT ;
    USE SIGNAL ;
    PORT
      LAYER M4 ;
        RECT 0.000 455.424 0.192 455.448 ;
    END
  END n_y[480]
  PIN n_y[481]
    DIRECTION OUTPUT ;
    USE SIGNAL ;
    PORT
      LAYER M4 ;
        RECT 0.000 455.616 0.192 455.640 ;
    END
  END n_y[481]
  PIN n_y[482]
    DIRECTION OUTPUT ;
    USE SIGNAL ;
    PORT
      LAYER M4 ;
        RECT 0.000 455.808 0.192 455.832 ;
    END
  END n_y[482]
  PIN n_y[483]
    DIRECTION OUTPUT ;
    USE SIGNAL ;
    PORT
      LAYER M4 ;
        RECT 0.000 456.000 0.192 456.024 ;
    END
  END n_y[483]
  PIN n_y[484]
    DIRECTION OUTPUT ;
    USE SIGNAL ;
    PORT
      LAYER M4 ;
        RECT 0.000 456.192 0.192 456.216 ;
    END
  END n_y[484]
  PIN n_y[485]
    DIRECTION OUTPUT ;
    USE SIGNAL ;
    PORT
      LAYER M4 ;
        RECT 0.000 456.384 0.192 456.408 ;
    END
  END n_y[485]
  PIN n_y[486]
    DIRECTION OUTPUT ;
    USE SIGNAL ;
    PORT
      LAYER M4 ;
        RECT 0.000 456.576 0.192 456.600 ;
    END
  END n_y[486]
  PIN n_y[487]
    DIRECTION OUTPUT ;
    USE SIGNAL ;
    PORT
      LAYER M4 ;
        RECT 0.000 456.768 0.192 456.792 ;
    END
  END n_y[487]
  PIN n_y[488]
    DIRECTION OUTPUT ;
    USE SIGNAL ;
    PORT
      LAYER M4 ;
        RECT 0.000 456.960 0.192 456.984 ;
    END
  END n_y[488]
  PIN n_y[489]
    DIRECTION OUTPUT ;
    USE SIGNAL ;
    PORT
      LAYER M4 ;
        RECT 0.000 457.152 0.192 457.176 ;
    END
  END n_y[489]
  PIN n_y[490]
    DIRECTION OUTPUT ;
    USE SIGNAL ;
    PORT
      LAYER M4 ;
        RECT 0.000 457.344 0.192 457.368 ;
    END
  END n_y[490]
  PIN n_y[491]
    DIRECTION OUTPUT ;
    USE SIGNAL ;
    PORT
      LAYER M4 ;
        RECT 0.000 457.536 0.192 457.560 ;
    END
  END n_y[491]
  PIN n_y[492]
    DIRECTION OUTPUT ;
    USE SIGNAL ;
    PORT
      LAYER M4 ;
        RECT 0.000 457.728 0.192 457.752 ;
    END
  END n_y[492]
  PIN n_y[493]
    DIRECTION OUTPUT ;
    USE SIGNAL ;
    PORT
      LAYER M4 ;
        RECT 0.000 457.920 0.192 457.944 ;
    END
  END n_y[493]
  PIN n_y[494]
    DIRECTION OUTPUT ;
    USE SIGNAL ;
    PORT
      LAYER M4 ;
        RECT 0.000 458.112 0.192 458.136 ;
    END
  END n_y[494]
  PIN n_y[495]
    DIRECTION OUTPUT ;
    USE SIGNAL ;
    PORT
      LAYER M4 ;
        RECT 0.000 458.304 0.192 458.328 ;
    END
  END n_y[495]
  PIN n_y[496]
    DIRECTION OUTPUT ;
    USE SIGNAL ;
    PORT
      LAYER M4 ;
        RECT 0.000 458.496 0.192 458.520 ;
    END
  END n_y[496]
  PIN n_y[497]
    DIRECTION OUTPUT ;
    USE SIGNAL ;
    PORT
      LAYER M4 ;
        RECT 0.000 458.688 0.192 458.712 ;
    END
  END n_y[497]
  PIN n_y[498]
    DIRECTION OUTPUT ;
    USE SIGNAL ;
    PORT
      LAYER M4 ;
        RECT 0.000 458.880 0.192 458.904 ;
    END
  END n_y[498]
  PIN n_y[499]
    DIRECTION OUTPUT ;
    USE SIGNAL ;
    PORT
      LAYER M4 ;
        RECT 0.000 459.072 0.192 459.096 ;
    END
  END n_y[499]
  PIN n_y[500]
    DIRECTION OUTPUT ;
    USE SIGNAL ;
    PORT
      LAYER M4 ;
        RECT 0.000 459.264 0.192 459.288 ;
    END
  END n_y[500]
  PIN n_y[501]
    DIRECTION OUTPUT ;
    USE SIGNAL ;
    PORT
      LAYER M4 ;
        RECT 0.000 459.456 0.192 459.480 ;
    END
  END n_y[501]
  PIN n_y[502]
    DIRECTION OUTPUT ;
    USE SIGNAL ;
    PORT
      LAYER M4 ;
        RECT 0.000 459.648 0.192 459.672 ;
    END
  END n_y[502]
  PIN n_y[503]
    DIRECTION OUTPUT ;
    USE SIGNAL ;
    PORT
      LAYER M4 ;
        RECT 0.000 459.840 0.192 459.864 ;
    END
  END n_y[503]
  PIN n_y[504]
    DIRECTION OUTPUT ;
    USE SIGNAL ;
    PORT
      LAYER M4 ;
        RECT 0.000 460.032 0.192 460.056 ;
    END
  END n_y[504]
  PIN n_y[505]
    DIRECTION OUTPUT ;
    USE SIGNAL ;
    PORT
      LAYER M4 ;
        RECT 0.000 460.224 0.192 460.248 ;
    END
  END n_y[505]
  PIN n_y[506]
    DIRECTION OUTPUT ;
    USE SIGNAL ;
    PORT
      LAYER M4 ;
        RECT 0.000 460.416 0.192 460.440 ;
    END
  END n_y[506]
  PIN n_y[507]
    DIRECTION OUTPUT ;
    USE SIGNAL ;
    PORT
      LAYER M4 ;
        RECT 0.000 460.608 0.192 460.632 ;
    END
  END n_y[507]
  PIN n_y[508]
    DIRECTION OUTPUT ;
    USE SIGNAL ;
    PORT
      LAYER M4 ;
        RECT 0.000 460.800 0.192 460.824 ;
    END
  END n_y[508]
  PIN n_y[509]
    DIRECTION OUTPUT ;
    USE SIGNAL ;
    PORT
      LAYER M4 ;
        RECT 0.000 460.992 0.192 461.016 ;
    END
  END n_y[509]
  PIN n_y[510]
    DIRECTION OUTPUT ;
    USE SIGNAL ;
    PORT
      LAYER M4 ;
        RECT 0.000 461.184 0.192 461.208 ;
    END
  END n_y[510]
  PIN n_y[511]
    DIRECTION OUTPUT ;
    USE SIGNAL ;
    PORT
      LAYER M4 ;
        RECT 0.000 461.376 0.192 461.400 ;
    END
  END n_y[511]
  PIN n_y[512]
    DIRECTION OUTPUT ;
    USE SIGNAL ;
    PORT
      LAYER M4 ;
        RECT 0.000 461.568 0.192 461.592 ;
    END
  END n_y[512]
  PIN n_y[513]
    DIRECTION OUTPUT ;
    USE SIGNAL ;
    PORT
      LAYER M4 ;
        RECT 0.000 461.760 0.192 461.784 ;
    END
  END n_y[513]
  PIN tie_lo
    DIRECTION OUTPUT ;
    USE SIGNAL ;
    PORT
      LAYER M4 ;
        RECT 457.728 429.168 457.920 429.192 ;
    END
  END tie_lo
  PIN tie_hi
    DIRECTION OUTPUT ;
    USE SIGNAL ;
    PORT
      LAYER M4 ;
        RECT 457.728 430.704 457.920 430.728 ;
    END
  END tie_hi
  PIN tile_id[0]
    DIRECTION INPUT ;
    USE SIGNAL ;
    PORT
      LAYER M4 ;
        RECT 457.728 432.192 457.920 432.216 ;
    END
  END tile_id[0]
  PIN tile_id[1]
    DIRECTION INPUT ;
    USE SIGNAL ;
    PORT
      LAYER M4 ;
        RECT 457.728 432.384 457.920 432.408 ;
    END
  END tile_id[1]
  PIN tile_id[2]
    DIRECTION INPUT ;
    USE SIGNAL ;
    PORT
      LAYER M4 ;
        RECT 457.728 432.576 457.920 432.600 ;
    END
  END tile_id[2]
  PIN tile_id[3]
    DIRECTION INPUT ;
    USE SIGNAL ;
    PORT
      LAYER M4 ;
        RECT 457.728 432.768 457.920 432.792 ;
    END
  END tile_id[3]
  PIN tile_id[4]
    DIRECTION INPUT ;
    USE SIGNAL ;
    PORT
      LAYER M4 ;
        RECT 457.728 432.960 457.920 432.984 ;
    END
  END tile_id[4]
  PIN tile_id[5]
    DIRECTION INPUT ;
    USE SIGNAL ;
    PORT
      LAYER M4 ;
        RECT 457.728 433.152 457.920 433.176 ;
    END
  END tile_id[5]
  PIN tile_id[6]
    DIRECTION INPUT ;
    USE SIGNAL ;
    PORT
      LAYER M4 ;
        RECT 457.728 433.344 457.920 433.368 ;
    END
  END tile_id[6]
  PIN tile_id[7]
    DIRECTION INPUT ;
    USE SIGNAL ;
    PORT
      LAYER M4 ;
        RECT 457.728 433.536 457.920 433.560 ;
    END
  END tile_id[7]
  PIN tile_id[8]
    DIRECTION INPUT ;
    USE SIGNAL ;
    PORT
      LAYER M4 ;
        RECT 457.728 433.728 457.920 433.752 ;
    END
  END tile_id[8]
  PIN tile_id[9]
    DIRECTION INPUT ;
    USE SIGNAL ;
    PORT
      LAYER M4 ;
        RECT 457.728 433.920 457.920 433.944 ;
    END
  END tile_id[9]
  PIN tile_id[10]
    DIRECTION INPUT ;
    USE SIGNAL ;
    PORT
      LAYER M4 ;
        RECT 457.728 434.112 457.920 434.136 ;
    END
  END tile_id[10]
  PIN tile_id[11]
    DIRECTION INPUT ;
    USE SIGNAL ;
    PORT
      LAYER M4 ;
        RECT 457.728 434.304 457.920 434.328 ;
    END
  END tile_id[11]
  PIN tile_id[12]
    DIRECTION INPUT ;
    USE SIGNAL ;
    PORT
      LAYER M4 ;
        RECT 457.728 434.496 457.920 434.520 ;
    END
  END tile_id[12]
  PIN tile_id[13]
    DIRECTION INPUT ;
    USE SIGNAL ;
    PORT
      LAYER M4 ;
        RECT 457.728 434.688 457.920 434.712 ;
    END
  END tile_id[13]
  PIN tile_id[14]
    DIRECTION INPUT ;
    USE SIGNAL ;
    PORT
      LAYER M4 ;
        RECT 457.728 434.880 457.920 434.904 ;
    END
  END tile_id[14]
  PIN tile_id[15]
    DIRECTION INPUT ;
    USE SIGNAL ;
    PORT
      LAYER M4 ;
        RECT 457.728 435.072 457.920 435.096 ;
    END
  END tile_id[15]
  PIN rst_n
    DIRECTION INPUT ;
    USE SIGNAL ;
    PORT
      LAYER M4 ;
        RECT 457.728 435.696 457.920 435.720 ;
    END
  END rst_n
  PIN tap[0]
    DIRECTION INPUT ;
    USE SIGNAL ;
    PORT
      LAYER M4 ;
        RECT 457.728 437.184 457.920 437.208 ;
    END
  END tap[0]
  PIN tap[1]
    DIRECTION INPUT ;
    USE SIGNAL ;
    PORT
      LAYER M4 ;
        RECT 457.728 437.280 457.920 437.304 ;
    END
  END tap[1]
  PIN tap[2]
    DIRECTION INPUT ;
    USE SIGNAL ;
    PORT
      LAYER M4 ;
        RECT 457.728 437.376 457.920 437.400 ;
    END
  END tap[2]
  PIN tap[3]
    DIRECTION INPUT ;
    USE SIGNAL ;
    PORT
      LAYER M4 ;
        RECT 457.728 437.472 457.920 437.496 ;
    END
  END tap[3]
  PIN tap[4]
    DIRECTION INPUT ;
    USE SIGNAL ;
    PORT
      LAYER M4 ;
        RECT 457.728 437.568 457.920 437.592 ;
    END
  END tap[4]
  PIN tap[5]
    DIRECTION INPUT ;
    USE SIGNAL ;
    PORT
      LAYER M4 ;
        RECT 457.728 437.664 457.920 437.688 ;
    END
  END tap[5]
  PIN tap[6]
    DIRECTION INPUT ;
    USE SIGNAL ;
    PORT
      LAYER M4 ;
        RECT 457.728 437.760 457.920 437.784 ;
    END
  END tap[6]
  PIN tap[7]
    DIRECTION INPUT ;
    USE SIGNAL ;
    PORT
      LAYER M4 ;
        RECT 457.728 437.856 457.920 437.880 ;
    END
  END tap[7]
  PIN tap[8]
    DIRECTION INPUT ;
    USE SIGNAL ;
    PORT
      LAYER M4 ;
        RECT 457.728 437.952 457.920 437.976 ;
    END
  END tap[8]
  PIN tap[9]
    DIRECTION INPUT ;
    USE SIGNAL ;
    PORT
      LAYER M4 ;
        RECT 457.728 438.048 457.920 438.072 ;
    END
  END tap[9]
  PIN tap[10]
    DIRECTION INPUT ;
    USE SIGNAL ;
    PORT
      LAYER M4 ;
        RECT 457.728 438.144 457.920 438.168 ;
    END
  END tap[10]
  PIN tap[11]
    DIRECTION INPUT ;
    USE SIGNAL ;
    PORT
      LAYER M4 ;
        RECT 457.728 438.240 457.920 438.264 ;
    END
  END tap[11]
  PIN tap[12]
    DIRECTION INPUT ;
    USE SIGNAL ;
    PORT
      LAYER M4 ;
        RECT 457.728 438.336 457.920 438.360 ;
    END
  END tap[12]
  PIN tap[13]
    DIRECTION INPUT ;
    USE SIGNAL ;
    PORT
      LAYER M4 ;
        RECT 457.728 438.432 457.920 438.456 ;
    END
  END tap[13]
  PIN tap[14]
    DIRECTION INPUT ;
    USE SIGNAL ;
    PORT
      LAYER M4 ;
        RECT 457.728 438.528 457.920 438.552 ;
    END
  END tap[14]
  PIN tap[15]
    DIRECTION INPUT ;
    USE SIGNAL ;
    PORT
      LAYER M4 ;
        RECT 457.728 438.624 457.920 438.648 ;
    END
  END tap[15]
  PIN tap[16]
    DIRECTION INPUT ;
    USE SIGNAL ;
    PORT
      LAYER M4 ;
        RECT 457.728 438.720 457.920 438.744 ;
    END
  END tap[16]
  PIN tap[17]
    DIRECTION INPUT ;
    USE SIGNAL ;
    PORT
      LAYER M4 ;
        RECT 457.728 438.816 457.920 438.840 ;
    END
  END tap[17]
  PIN tap[18]
    DIRECTION INPUT ;
    USE SIGNAL ;
    PORT
      LAYER M4 ;
        RECT 457.728 438.912 457.920 438.936 ;
    END
  END tap[18]
  PIN tap[19]
    DIRECTION INPUT ;
    USE SIGNAL ;
    PORT
      LAYER M4 ;
        RECT 457.728 439.008 457.920 439.032 ;
    END
  END tap[19]
  PIN tap[20]
    DIRECTION INPUT ;
    USE SIGNAL ;
    PORT
      LAYER M4 ;
        RECT 457.728 439.104 457.920 439.128 ;
    END
  END tap[20]
  PIN tap[21]
    DIRECTION INPUT ;
    USE SIGNAL ;
    PORT
      LAYER M4 ;
        RECT 457.728 439.200 457.920 439.224 ;
    END
  END tap[21]
  PIN tap[22]
    DIRECTION INPUT ;
    USE SIGNAL ;
    PORT
      LAYER M4 ;
        RECT 457.728 439.296 457.920 439.320 ;
    END
  END tap[22]
  PIN tap[23]
    DIRECTION INPUT ;
    USE SIGNAL ;
    PORT
      LAYER M4 ;
        RECT 457.728 439.392 457.920 439.416 ;
    END
  END tap[23]
  PIN tap[24]
    DIRECTION INPUT ;
    USE SIGNAL ;
    PORT
      LAYER M4 ;
        RECT 457.728 439.488 457.920 439.512 ;
    END
  END tap[24]
  PIN tap[25]
    DIRECTION INPUT ;
    USE SIGNAL ;
    PORT
      LAYER M4 ;
        RECT 457.728 439.584 457.920 439.608 ;
    END
  END tap[25]
  PIN tap[26]
    DIRECTION INPUT ;
    USE SIGNAL ;
    PORT
      LAYER M4 ;
        RECT 457.728 439.680 457.920 439.704 ;
    END
  END tap[26]
  PIN tap[27]
    DIRECTION INPUT ;
    USE SIGNAL ;
    PORT
      LAYER M4 ;
        RECT 457.728 439.776 457.920 439.800 ;
    END
  END tap[27]
  PIN tap[28]
    DIRECTION INPUT ;
    USE SIGNAL ;
    PORT
      LAYER M4 ;
        RECT 457.728 439.872 457.920 439.896 ;
    END
  END tap[28]
  PIN tap[29]
    DIRECTION INPUT ;
    USE SIGNAL ;
    PORT
      LAYER M4 ;
        RECT 457.728 439.968 457.920 439.992 ;
    END
  END tap[29]
  PIN tap[30]
    DIRECTION INPUT ;
    USE SIGNAL ;
    PORT
      LAYER M4 ;
        RECT 457.728 440.064 457.920 440.088 ;
    END
  END tap[30]
  PIN tap[31]
    DIRECTION INPUT ;
    USE SIGNAL ;
    PORT
      LAYER M4 ;
        RECT 457.728 440.160 457.920 440.184 ;
    END
  END tap[31]
  PIN tap[32]
    DIRECTION INPUT ;
    USE SIGNAL ;
    PORT
      LAYER M4 ;
        RECT 457.728 440.256 457.920 440.280 ;
    END
  END tap[32]
  PIN tap[33]
    DIRECTION INPUT ;
    USE SIGNAL ;
    PORT
      LAYER M4 ;
        RECT 457.728 440.352 457.920 440.376 ;
    END
  END tap[33]
  PIN tap[34]
    DIRECTION INPUT ;
    USE SIGNAL ;
    PORT
      LAYER M4 ;
        RECT 457.728 440.448 457.920 440.472 ;
    END
  END tap[34]
  PIN tap[35]
    DIRECTION INPUT ;
    USE SIGNAL ;
    PORT
      LAYER M4 ;
        RECT 457.728 440.544 457.920 440.568 ;
    END
  END tap[35]
  PIN tap[36]
    DIRECTION INPUT ;
    USE SIGNAL ;
    PORT
      LAYER M4 ;
        RECT 457.728 440.640 457.920 440.664 ;
    END
  END tap[36]
  PIN tap[37]
    DIRECTION INPUT ;
    USE SIGNAL ;
    PORT
      LAYER M4 ;
        RECT 457.728 440.736 457.920 440.760 ;
    END
  END tap[37]
  PIN tap[38]
    DIRECTION INPUT ;
    USE SIGNAL ;
    PORT
      LAYER M4 ;
        RECT 457.728 440.832 457.920 440.856 ;
    END
  END tap[38]
  PIN tap[39]
    DIRECTION INPUT ;
    USE SIGNAL ;
    PORT
      LAYER M4 ;
        RECT 457.728 440.928 457.920 440.952 ;
    END
  END tap[39]
  PIN tap[40]
    DIRECTION INPUT ;
    USE SIGNAL ;
    PORT
      LAYER M4 ;
        RECT 457.728 441.024 457.920 441.048 ;
    END
  END tap[40]
  PIN tap[41]
    DIRECTION INPUT ;
    USE SIGNAL ;
    PORT
      LAYER M4 ;
        RECT 457.728 441.120 457.920 441.144 ;
    END
  END tap[41]
  PIN tap[42]
    DIRECTION INPUT ;
    USE SIGNAL ;
    PORT
      LAYER M4 ;
        RECT 457.728 441.216 457.920 441.240 ;
    END
  END tap[42]
  PIN tap[43]
    DIRECTION INPUT ;
    USE SIGNAL ;
    PORT
      LAYER M4 ;
        RECT 457.728 441.312 457.920 441.336 ;
    END
  END tap[43]
  PIN tap[44]
    DIRECTION INPUT ;
    USE SIGNAL ;
    PORT
      LAYER M4 ;
        RECT 457.728 441.408 457.920 441.432 ;
    END
  END tap[44]
  PIN tap[45]
    DIRECTION INPUT ;
    USE SIGNAL ;
    PORT
      LAYER M4 ;
        RECT 457.728 441.504 457.920 441.528 ;
    END
  END tap[45]
  PIN tap[46]
    DIRECTION INPUT ;
    USE SIGNAL ;
    PORT
      LAYER M4 ;
        RECT 457.728 441.600 457.920 441.624 ;
    END
  END tap[46]
  PIN tap[47]
    DIRECTION INPUT ;
    USE SIGNAL ;
    PORT
      LAYER M4 ;
        RECT 457.728 441.696 457.920 441.720 ;
    END
  END tap[47]
  PIN tap[48]
    DIRECTION INPUT ;
    USE SIGNAL ;
    PORT
      LAYER M4 ;
        RECT 457.728 441.792 457.920 441.816 ;
    END
  END tap[48]
  PIN tap[49]
    DIRECTION INPUT ;
    USE SIGNAL ;
    PORT
      LAYER M4 ;
        RECT 457.728 441.888 457.920 441.912 ;
    END
  END tap[49]
  PIN tap[50]
    DIRECTION INPUT ;
    USE SIGNAL ;
    PORT
      LAYER M4 ;
        RECT 457.728 441.984 457.920 442.008 ;
    END
  END tap[50]
  PIN tap[51]
    DIRECTION INPUT ;
    USE SIGNAL ;
    PORT
      LAYER M4 ;
        RECT 457.728 442.080 457.920 442.104 ;
    END
  END tap[51]
  PIN tap[52]
    DIRECTION INPUT ;
    USE SIGNAL ;
    PORT
      LAYER M4 ;
        RECT 457.728 442.176 457.920 442.200 ;
    END
  END tap[52]
  PIN tap[53]
    DIRECTION INPUT ;
    USE SIGNAL ;
    PORT
      LAYER M4 ;
        RECT 457.728 442.272 457.920 442.296 ;
    END
  END tap[53]
  PIN tap[54]
    DIRECTION INPUT ;
    USE SIGNAL ;
    PORT
      LAYER M4 ;
        RECT 457.728 442.368 457.920 442.392 ;
    END
  END tap[54]
  PIN tap[55]
    DIRECTION INPUT ;
    USE SIGNAL ;
    PORT
      LAYER M4 ;
        RECT 457.728 442.464 457.920 442.488 ;
    END
  END tap[55]
  PIN tap[56]
    DIRECTION INPUT ;
    USE SIGNAL ;
    PORT
      LAYER M4 ;
        RECT 457.728 442.560 457.920 442.584 ;
    END
  END tap[56]
  PIN tap[57]
    DIRECTION INPUT ;
    USE SIGNAL ;
    PORT
      LAYER M4 ;
        RECT 457.728 442.656 457.920 442.680 ;
    END
  END tap[57]
  PIN tap[58]
    DIRECTION INPUT ;
    USE SIGNAL ;
    PORT
      LAYER M4 ;
        RECT 457.728 442.752 457.920 442.776 ;
    END
  END tap[58]
  PIN tap[59]
    DIRECTION INPUT ;
    USE SIGNAL ;
    PORT
      LAYER M4 ;
        RECT 457.728 442.848 457.920 442.872 ;
    END
  END tap[59]
  PIN tap[60]
    DIRECTION INPUT ;
    USE SIGNAL ;
    PORT
      LAYER M4 ;
        RECT 457.728 442.944 457.920 442.968 ;
    END
  END tap[60]
  PIN tap[61]
    DIRECTION INPUT ;
    USE SIGNAL ;
    PORT
      LAYER M4 ;
        RECT 457.728 443.040 457.920 443.064 ;
    END
  END tap[61]
  PIN tap[62]
    DIRECTION INPUT ;
    USE SIGNAL ;
    PORT
      LAYER M4 ;
        RECT 457.728 443.136 457.920 443.160 ;
    END
  END tap[62]
  PIN tap[63]
    DIRECTION INPUT ;
    USE SIGNAL ;
    PORT
      LAYER M4 ;
        RECT 457.728 443.232 457.920 443.256 ;
    END
  END tap[63]
  PIN tap[64]
    DIRECTION INPUT ;
    USE SIGNAL ;
    PORT
      LAYER M4 ;
        RECT 457.728 443.328 457.920 443.352 ;
    END
  END tap[64]
  PIN tap[65]
    DIRECTION INPUT ;
    USE SIGNAL ;
    PORT
      LAYER M4 ;
        RECT 457.728 443.424 457.920 443.448 ;
    END
  END tap[65]
  PIN tap[66]
    DIRECTION INPUT ;
    USE SIGNAL ;
    PORT
      LAYER M4 ;
        RECT 457.728 443.520 457.920 443.544 ;
    END
  END tap[66]
  PIN tap[67]
    DIRECTION INPUT ;
    USE SIGNAL ;
    PORT
      LAYER M4 ;
        RECT 457.728 443.616 457.920 443.640 ;
    END
  END tap[67]
  PIN tap[68]
    DIRECTION INPUT ;
    USE SIGNAL ;
    PORT
      LAYER M4 ;
        RECT 457.728 443.712 457.920 443.736 ;
    END
  END tap[68]
  PIN tap[69]
    DIRECTION INPUT ;
    USE SIGNAL ;
    PORT
      LAYER M4 ;
        RECT 457.728 443.808 457.920 443.832 ;
    END
  END tap[69]
  PIN tap[70]
    DIRECTION INPUT ;
    USE SIGNAL ;
    PORT
      LAYER M4 ;
        RECT 457.728 443.904 457.920 443.928 ;
    END
  END tap[70]
  PIN tap[71]
    DIRECTION INPUT ;
    USE SIGNAL ;
    PORT
      LAYER M4 ;
        RECT 457.728 444.000 457.920 444.024 ;
    END
  END tap[71]
  PIN tap[72]
    DIRECTION INPUT ;
    USE SIGNAL ;
    PORT
      LAYER M4 ;
        RECT 457.728 444.096 457.920 444.120 ;
    END
  END tap[72]
  PIN tap[73]
    DIRECTION INPUT ;
    USE SIGNAL ;
    PORT
      LAYER M4 ;
        RECT 457.728 444.192 457.920 444.216 ;
    END
  END tap[73]
  PIN tap[74]
    DIRECTION INPUT ;
    USE SIGNAL ;
    PORT
      LAYER M4 ;
        RECT 457.728 444.288 457.920 444.312 ;
    END
  END tap[74]
  PIN tap[75]
    DIRECTION INPUT ;
    USE SIGNAL ;
    PORT
      LAYER M4 ;
        RECT 457.728 444.384 457.920 444.408 ;
    END
  END tap[75]
  PIN tap[76]
    DIRECTION INPUT ;
    USE SIGNAL ;
    PORT
      LAYER M4 ;
        RECT 457.728 444.480 457.920 444.504 ;
    END
  END tap[76]
  PIN tap[77]
    DIRECTION INPUT ;
    USE SIGNAL ;
    PORT
      LAYER M4 ;
        RECT 457.728 444.576 457.920 444.600 ;
    END
  END tap[77]
  PIN tap[78]
    DIRECTION INPUT ;
    USE SIGNAL ;
    PORT
      LAYER M4 ;
        RECT 457.728 444.672 457.920 444.696 ;
    END
  END tap[78]
  PIN tap[79]
    DIRECTION INPUT ;
    USE SIGNAL ;
    PORT
      LAYER M4 ;
        RECT 457.728 444.768 457.920 444.792 ;
    END
  END tap[79]
  PIN tap[80]
    DIRECTION INPUT ;
    USE SIGNAL ;
    PORT
      LAYER M4 ;
        RECT 457.728 444.864 457.920 444.888 ;
    END
  END tap[80]
  PIN tap[81]
    DIRECTION INPUT ;
    USE SIGNAL ;
    PORT
      LAYER M4 ;
        RECT 457.728 444.960 457.920 444.984 ;
    END
  END tap[81]
  PIN tap[82]
    DIRECTION INPUT ;
    USE SIGNAL ;
    PORT
      LAYER M4 ;
        RECT 457.728 445.056 457.920 445.080 ;
    END
  END tap[82]
  PIN tap[83]
    DIRECTION INPUT ;
    USE SIGNAL ;
    PORT
      LAYER M4 ;
        RECT 457.728 445.152 457.920 445.176 ;
    END
  END tap[83]
  PIN tap[84]
    DIRECTION INPUT ;
    USE SIGNAL ;
    PORT
      LAYER M4 ;
        RECT 457.728 445.248 457.920 445.272 ;
    END
  END tap[84]
  PIN tap[85]
    DIRECTION INPUT ;
    USE SIGNAL ;
    PORT
      LAYER M4 ;
        RECT 457.728 445.344 457.920 445.368 ;
    END
  END tap[85]
  PIN tap[86]
    DIRECTION INPUT ;
    USE SIGNAL ;
    PORT
      LAYER M4 ;
        RECT 457.728 445.440 457.920 445.464 ;
    END
  END tap[86]
  PIN tap[87]
    DIRECTION INPUT ;
    USE SIGNAL ;
    PORT
      LAYER M4 ;
        RECT 457.728 445.536 457.920 445.560 ;
    END
  END tap[87]
  PIN tap[88]
    DIRECTION INPUT ;
    USE SIGNAL ;
    PORT
      LAYER M4 ;
        RECT 457.728 445.632 457.920 445.656 ;
    END
  END tap[88]
  PIN tap[89]
    DIRECTION INPUT ;
    USE SIGNAL ;
    PORT
      LAYER M4 ;
        RECT 457.728 445.728 457.920 445.752 ;
    END
  END tap[89]
  PIN tap[90]
    DIRECTION INPUT ;
    USE SIGNAL ;
    PORT
      LAYER M4 ;
        RECT 457.728 445.824 457.920 445.848 ;
    END
  END tap[90]
  PIN tap[91]
    DIRECTION INPUT ;
    USE SIGNAL ;
    PORT
      LAYER M4 ;
        RECT 457.728 445.920 457.920 445.944 ;
    END
  END tap[91]
  PIN tap[92]
    DIRECTION INPUT ;
    USE SIGNAL ;
    PORT
      LAYER M4 ;
        RECT 457.728 446.016 457.920 446.040 ;
    END
  END tap[92]
  PIN tap[93]
    DIRECTION INPUT ;
    USE SIGNAL ;
    PORT
      LAYER M4 ;
        RECT 457.728 446.112 457.920 446.136 ;
    END
  END tap[93]
  PIN tap[94]
    DIRECTION INPUT ;
    USE SIGNAL ;
    PORT
      LAYER M4 ;
        RECT 457.728 446.208 457.920 446.232 ;
    END
  END tap[94]
  PIN tap[95]
    DIRECTION INPUT ;
    USE SIGNAL ;
    PORT
      LAYER M4 ;
        RECT 457.728 446.304 457.920 446.328 ;
    END
  END tap[95]
  PIN tap[96]
    DIRECTION INPUT ;
    USE SIGNAL ;
    PORT
      LAYER M4 ;
        RECT 457.728 446.400 457.920 446.424 ;
    END
  END tap[96]
  PIN tap[97]
    DIRECTION INPUT ;
    USE SIGNAL ;
    PORT
      LAYER M4 ;
        RECT 457.728 446.496 457.920 446.520 ;
    END
  END tap[97]
  PIN tap[98]
    DIRECTION INPUT ;
    USE SIGNAL ;
    PORT
      LAYER M4 ;
        RECT 457.728 446.592 457.920 446.616 ;
    END
  END tap[98]
  PIN tap[99]
    DIRECTION INPUT ;
    USE SIGNAL ;
    PORT
      LAYER M4 ;
        RECT 457.728 446.688 457.920 446.712 ;
    END
  END tap[99]
  PIN tap[100]
    DIRECTION INPUT ;
    USE SIGNAL ;
    PORT
      LAYER M4 ;
        RECT 457.728 446.784 457.920 446.808 ;
    END
  END tap[100]
  PIN tap[101]
    DIRECTION INPUT ;
    USE SIGNAL ;
    PORT
      LAYER M4 ;
        RECT 457.728 446.880 457.920 446.904 ;
    END
  END tap[101]
  PIN tap[102]
    DIRECTION INPUT ;
    USE SIGNAL ;
    PORT
      LAYER M4 ;
        RECT 457.728 446.976 457.920 447.000 ;
    END
  END tap[102]
  PIN tap[103]
    DIRECTION INPUT ;
    USE SIGNAL ;
    PORT
      LAYER M4 ;
        RECT 457.728 447.072 457.920 447.096 ;
    END
  END tap[103]
  PIN tap[104]
    DIRECTION INPUT ;
    USE SIGNAL ;
    PORT
      LAYER M4 ;
        RECT 457.728 447.168 457.920 447.192 ;
    END
  END tap[104]
  PIN tap[105]
    DIRECTION INPUT ;
    USE SIGNAL ;
    PORT
      LAYER M4 ;
        RECT 457.728 447.264 457.920 447.288 ;
    END
  END tap[105]
  PIN tap[106]
    DIRECTION INPUT ;
    USE SIGNAL ;
    PORT
      LAYER M4 ;
        RECT 457.728 447.360 457.920 447.384 ;
    END
  END tap[106]
  PIN tap[107]
    DIRECTION INPUT ;
    USE SIGNAL ;
    PORT
      LAYER M4 ;
        RECT 457.728 447.456 457.920 447.480 ;
    END
  END tap[107]
  PIN tap[108]
    DIRECTION INPUT ;
    USE SIGNAL ;
    PORT
      LAYER M4 ;
        RECT 457.728 447.552 457.920 447.576 ;
    END
  END tap[108]
  PIN tap[109]
    DIRECTION INPUT ;
    USE SIGNAL ;
    PORT
      LAYER M4 ;
        RECT 457.728 447.648 457.920 447.672 ;
    END
  END tap[109]
  PIN tap[110]
    DIRECTION INPUT ;
    USE SIGNAL ;
    PORT
      LAYER M4 ;
        RECT 457.728 447.744 457.920 447.768 ;
    END
  END tap[110]
  PIN tap[111]
    DIRECTION INPUT ;
    USE SIGNAL ;
    PORT
      LAYER M4 ;
        RECT 457.728 447.840 457.920 447.864 ;
    END
  END tap[111]
  PIN tap[112]
    DIRECTION INPUT ;
    USE SIGNAL ;
    PORT
      LAYER M4 ;
        RECT 457.728 447.936 457.920 447.960 ;
    END
  END tap[112]
  PIN tap[113]
    DIRECTION INPUT ;
    USE SIGNAL ;
    PORT
      LAYER M4 ;
        RECT 457.728 448.032 457.920 448.056 ;
    END
  END tap[113]
  PIN tap[114]
    DIRECTION INPUT ;
    USE SIGNAL ;
    PORT
      LAYER M4 ;
        RECT 457.728 448.128 457.920 448.152 ;
    END
  END tap[114]
  PIN tap[115]
    DIRECTION INPUT ;
    USE SIGNAL ;
    PORT
      LAYER M4 ;
        RECT 457.728 448.224 457.920 448.248 ;
    END
  END tap[115]
  PIN tap[116]
    DIRECTION INPUT ;
    USE SIGNAL ;
    PORT
      LAYER M4 ;
        RECT 457.728 448.320 457.920 448.344 ;
    END
  END tap[116]
  PIN tap[117]
    DIRECTION INPUT ;
    USE SIGNAL ;
    PORT
      LAYER M4 ;
        RECT 457.728 448.416 457.920 448.440 ;
    END
  END tap[117]
  PIN tap[118]
    DIRECTION INPUT ;
    USE SIGNAL ;
    PORT
      LAYER M4 ;
        RECT 457.728 448.512 457.920 448.536 ;
    END
  END tap[118]
  PIN tap[119]
    DIRECTION INPUT ;
    USE SIGNAL ;
    PORT
      LAYER M4 ;
        RECT 457.728 448.608 457.920 448.632 ;
    END
  END tap[119]
  PIN tap[120]
    DIRECTION INPUT ;
    USE SIGNAL ;
    PORT
      LAYER M4 ;
        RECT 457.728 448.704 457.920 448.728 ;
    END
  END tap[120]
  PIN tap[121]
    DIRECTION INPUT ;
    USE SIGNAL ;
    PORT
      LAYER M4 ;
        RECT 457.728 448.800 457.920 448.824 ;
    END
  END tap[121]
  PIN tap[122]
    DIRECTION INPUT ;
    USE SIGNAL ;
    PORT
      LAYER M4 ;
        RECT 457.728 448.896 457.920 448.920 ;
    END
  END tap[122]
  PIN tap[123]
    DIRECTION INPUT ;
    USE SIGNAL ;
    PORT
      LAYER M4 ;
        RECT 457.728 448.992 457.920 449.016 ;
    END
  END tap[123]
  PIN tap[124]
    DIRECTION INPUT ;
    USE SIGNAL ;
    PORT
      LAYER M4 ;
        RECT 457.728 449.088 457.920 449.112 ;
    END
  END tap[124]
  PIN tap[125]
    DIRECTION INPUT ;
    USE SIGNAL ;
    PORT
      LAYER M4 ;
        RECT 457.728 449.184 457.920 449.208 ;
    END
  END tap[125]
  PIN tap[126]
    DIRECTION INPUT ;
    USE SIGNAL ;
    PORT
      LAYER M4 ;
        RECT 457.728 449.280 457.920 449.304 ;
    END
  END tap[126]
  PIN tap[127]
    DIRECTION INPUT ;
    USE SIGNAL ;
    PORT
      LAYER M4 ;
        RECT 457.728 449.376 457.920 449.400 ;
    END
  END tap[127]
  PIN tap[128]
    DIRECTION INPUT ;
    USE SIGNAL ;
    PORT
      LAYER M4 ;
        RECT 457.728 449.472 457.920 449.496 ;
    END
  END tap[128]
  PIN tap[129]
    DIRECTION INPUT ;
    USE SIGNAL ;
    PORT
      LAYER M4 ;
        RECT 457.728 449.568 457.920 449.592 ;
    END
  END tap[129]
  PIN tap[130]
    DIRECTION INPUT ;
    USE SIGNAL ;
    PORT
      LAYER M4 ;
        RECT 457.728 449.664 457.920 449.688 ;
    END
  END tap[130]
  PIN tap[131]
    DIRECTION INPUT ;
    USE SIGNAL ;
    PORT
      LAYER M4 ;
        RECT 457.728 449.760 457.920 449.784 ;
    END
  END tap[131]
  PIN tap[132]
    DIRECTION INPUT ;
    USE SIGNAL ;
    PORT
      LAYER M4 ;
        RECT 457.728 449.856 457.920 449.880 ;
    END
  END tap[132]
  PIN tap[133]
    DIRECTION INPUT ;
    USE SIGNAL ;
    PORT
      LAYER M4 ;
        RECT 457.728 449.952 457.920 449.976 ;
    END
  END tap[133]
  PIN tap[134]
    DIRECTION INPUT ;
    USE SIGNAL ;
    PORT
      LAYER M4 ;
        RECT 457.728 450.048 457.920 450.072 ;
    END
  END tap[134]
  PIN tap[135]
    DIRECTION INPUT ;
    USE SIGNAL ;
    PORT
      LAYER M4 ;
        RECT 457.728 450.144 457.920 450.168 ;
    END
  END tap[135]
  PIN tap[136]
    DIRECTION INPUT ;
    USE SIGNAL ;
    PORT
      LAYER M4 ;
        RECT 457.728 450.240 457.920 450.264 ;
    END
  END tap[136]
  PIN tap[137]
    DIRECTION INPUT ;
    USE SIGNAL ;
    PORT
      LAYER M4 ;
        RECT 457.728 450.336 457.920 450.360 ;
    END
  END tap[137]
  PIN tap[138]
    DIRECTION INPUT ;
    USE SIGNAL ;
    PORT
      LAYER M4 ;
        RECT 457.728 450.432 457.920 450.456 ;
    END
  END tap[138]
  PIN tap[139]
    DIRECTION INPUT ;
    USE SIGNAL ;
    PORT
      LAYER M4 ;
        RECT 457.728 450.528 457.920 450.552 ;
    END
  END tap[139]
  PIN tap[140]
    DIRECTION INPUT ;
    USE SIGNAL ;
    PORT
      LAYER M4 ;
        RECT 457.728 450.624 457.920 450.648 ;
    END
  END tap[140]
  PIN tap[141]
    DIRECTION INPUT ;
    USE SIGNAL ;
    PORT
      LAYER M4 ;
        RECT 457.728 450.720 457.920 450.744 ;
    END
  END tap[141]
  PIN tap[142]
    DIRECTION INPUT ;
    USE SIGNAL ;
    PORT
      LAYER M4 ;
        RECT 457.728 450.816 457.920 450.840 ;
    END
  END tap[142]
  PIN tap[143]
    DIRECTION INPUT ;
    USE SIGNAL ;
    PORT
      LAYER M4 ;
        RECT 457.728 450.912 457.920 450.936 ;
    END
  END tap[143]
  PIN tap[144]
    DIRECTION INPUT ;
    USE SIGNAL ;
    PORT
      LAYER M4 ;
        RECT 457.728 451.008 457.920 451.032 ;
    END
  END tap[144]
  PIN tap[145]
    DIRECTION INPUT ;
    USE SIGNAL ;
    PORT
      LAYER M4 ;
        RECT 457.728 451.104 457.920 451.128 ;
    END
  END tap[145]
  PIN tap[146]
    DIRECTION INPUT ;
    USE SIGNAL ;
    PORT
      LAYER M4 ;
        RECT 457.728 451.200 457.920 451.224 ;
    END
  END tap[146]
  PIN tap[147]
    DIRECTION INPUT ;
    USE SIGNAL ;
    PORT
      LAYER M4 ;
        RECT 457.728 451.296 457.920 451.320 ;
    END
  END tap[147]
  PIN tap[148]
    DIRECTION INPUT ;
    USE SIGNAL ;
    PORT
      LAYER M4 ;
        RECT 457.728 451.392 457.920 451.416 ;
    END
  END tap[148]
  PIN tap[149]
    DIRECTION INPUT ;
    USE SIGNAL ;
    PORT
      LAYER M4 ;
        RECT 457.728 451.488 457.920 451.512 ;
    END
  END tap[149]
  PIN tap[150]
    DIRECTION INPUT ;
    USE SIGNAL ;
    PORT
      LAYER M4 ;
        RECT 457.728 451.584 457.920 451.608 ;
    END
  END tap[150]
  PIN tap[151]
    DIRECTION INPUT ;
    USE SIGNAL ;
    PORT
      LAYER M4 ;
        RECT 457.728 451.680 457.920 451.704 ;
    END
  END tap[151]
  PIN tap[152]
    DIRECTION INPUT ;
    USE SIGNAL ;
    PORT
      LAYER M4 ;
        RECT 457.728 451.776 457.920 451.800 ;
    END
  END tap[152]
  PIN tap[153]
    DIRECTION INPUT ;
    USE SIGNAL ;
    PORT
      LAYER M4 ;
        RECT 457.728 451.872 457.920 451.896 ;
    END
  END tap[153]
  PIN tap[154]
    DIRECTION INPUT ;
    USE SIGNAL ;
    PORT
      LAYER M4 ;
        RECT 457.728 451.968 457.920 451.992 ;
    END
  END tap[154]
  PIN tap[155]
    DIRECTION INPUT ;
    USE SIGNAL ;
    PORT
      LAYER M4 ;
        RECT 457.728 452.064 457.920 452.088 ;
    END
  END tap[155]
  PIN tap[156]
    DIRECTION INPUT ;
    USE SIGNAL ;
    PORT
      LAYER M4 ;
        RECT 457.728 452.160 457.920 452.184 ;
    END
  END tap[156]
  PIN tap[157]
    DIRECTION INPUT ;
    USE SIGNAL ;
    PORT
      LAYER M4 ;
        RECT 457.728 452.256 457.920 452.280 ;
    END
  END tap[157]
  PIN tap[158]
    DIRECTION INPUT ;
    USE SIGNAL ;
    PORT
      LAYER M4 ;
        RECT 457.728 452.352 457.920 452.376 ;
    END
  END tap[158]
  PIN tap[159]
    DIRECTION INPUT ;
    USE SIGNAL ;
    PORT
      LAYER M4 ;
        RECT 457.728 452.448 457.920 452.472 ;
    END
  END tap[159]
  PIN tap[160]
    DIRECTION INPUT ;
    USE SIGNAL ;
    PORT
      LAYER M4 ;
        RECT 457.728 452.544 457.920 452.568 ;
    END
  END tap[160]
  PIN tap[161]
    DIRECTION INPUT ;
    USE SIGNAL ;
    PORT
      LAYER M4 ;
        RECT 457.728 452.640 457.920 452.664 ;
    END
  END tap[161]
  PIN tap[162]
    DIRECTION INPUT ;
    USE SIGNAL ;
    PORT
      LAYER M4 ;
        RECT 457.728 452.736 457.920 452.760 ;
    END
  END tap[162]
  PIN tap[163]
    DIRECTION INPUT ;
    USE SIGNAL ;
    PORT
      LAYER M4 ;
        RECT 457.728 452.832 457.920 452.856 ;
    END
  END tap[163]
  PIN tap[164]
    DIRECTION INPUT ;
    USE SIGNAL ;
    PORT
      LAYER M4 ;
        RECT 457.728 452.928 457.920 452.952 ;
    END
  END tap[164]
  PIN tap[165]
    DIRECTION INPUT ;
    USE SIGNAL ;
    PORT
      LAYER M4 ;
        RECT 457.728 453.024 457.920 453.048 ;
    END
  END tap[165]
  PIN tap[166]
    DIRECTION INPUT ;
    USE SIGNAL ;
    PORT
      LAYER M4 ;
        RECT 457.728 453.120 457.920 453.144 ;
    END
  END tap[166]
  PIN tap[167]
    DIRECTION INPUT ;
    USE SIGNAL ;
    PORT
      LAYER M4 ;
        RECT 457.728 453.216 457.920 453.240 ;
    END
  END tap[167]
  PIN tap[168]
    DIRECTION INPUT ;
    USE SIGNAL ;
    PORT
      LAYER M4 ;
        RECT 457.728 453.312 457.920 453.336 ;
    END
  END tap[168]
  PIN tap[169]
    DIRECTION INPUT ;
    USE SIGNAL ;
    PORT
      LAYER M4 ;
        RECT 457.728 453.408 457.920 453.432 ;
    END
  END tap[169]
  PIN tap[170]
    DIRECTION INPUT ;
    USE SIGNAL ;
    PORT
      LAYER M4 ;
        RECT 457.728 453.504 457.920 453.528 ;
    END
  END tap[170]
  PIN tap[171]
    DIRECTION INPUT ;
    USE SIGNAL ;
    PORT
      LAYER M4 ;
        RECT 457.728 453.600 457.920 453.624 ;
    END
  END tap[171]
  PIN tap[172]
    DIRECTION INPUT ;
    USE SIGNAL ;
    PORT
      LAYER M4 ;
        RECT 457.728 453.696 457.920 453.720 ;
    END
  END tap[172]
  PIN tap[173]
    DIRECTION INPUT ;
    USE SIGNAL ;
    PORT
      LAYER M4 ;
        RECT 457.728 453.792 457.920 453.816 ;
    END
  END tap[173]
  PIN tap[174]
    DIRECTION INPUT ;
    USE SIGNAL ;
    PORT
      LAYER M4 ;
        RECT 457.728 453.888 457.920 453.912 ;
    END
  END tap[174]
  PIN tap[175]
    DIRECTION INPUT ;
    USE SIGNAL ;
    PORT
      LAYER M4 ;
        RECT 457.728 453.984 457.920 454.008 ;
    END
  END tap[175]
  PIN tap[176]
    DIRECTION INPUT ;
    USE SIGNAL ;
    PORT
      LAYER M4 ;
        RECT 457.728 454.080 457.920 454.104 ;
    END
  END tap[176]
  PIN tap[177]
    DIRECTION INPUT ;
    USE SIGNAL ;
    PORT
      LAYER M4 ;
        RECT 457.728 454.176 457.920 454.200 ;
    END
  END tap[177]
  PIN tap[178]
    DIRECTION INPUT ;
    USE SIGNAL ;
    PORT
      LAYER M4 ;
        RECT 457.728 454.272 457.920 454.296 ;
    END
  END tap[178]
  PIN tap[179]
    DIRECTION INPUT ;
    USE SIGNAL ;
    PORT
      LAYER M4 ;
        RECT 457.728 454.368 457.920 454.392 ;
    END
  END tap[179]
  PIN tap[180]
    DIRECTION INPUT ;
    USE SIGNAL ;
    PORT
      LAYER M4 ;
        RECT 457.728 454.464 457.920 454.488 ;
    END
  END tap[180]
  PIN tap[181]
    DIRECTION INPUT ;
    USE SIGNAL ;
    PORT
      LAYER M4 ;
        RECT 457.728 454.560 457.920 454.584 ;
    END
  END tap[181]
  PIN tap[182]
    DIRECTION INPUT ;
    USE SIGNAL ;
    PORT
      LAYER M4 ;
        RECT 457.728 454.656 457.920 454.680 ;
    END
  END tap[182]
  PIN tap[183]
    DIRECTION INPUT ;
    USE SIGNAL ;
    PORT
      LAYER M4 ;
        RECT 457.728 454.752 457.920 454.776 ;
    END
  END tap[183]
  PIN tap[184]
    DIRECTION INPUT ;
    USE SIGNAL ;
    PORT
      LAYER M4 ;
        RECT 457.728 454.848 457.920 454.872 ;
    END
  END tap[184]
  PIN tap[185]
    DIRECTION INPUT ;
    USE SIGNAL ;
    PORT
      LAYER M4 ;
        RECT 457.728 454.944 457.920 454.968 ;
    END
  END tap[185]
  PIN tap[186]
    DIRECTION INPUT ;
    USE SIGNAL ;
    PORT
      LAYER M4 ;
        RECT 457.728 455.040 457.920 455.064 ;
    END
  END tap[186]
  PIN tap[187]
    DIRECTION INPUT ;
    USE SIGNAL ;
    PORT
      LAYER M4 ;
        RECT 457.728 455.136 457.920 455.160 ;
    END
  END tap[187]
  PIN tap[188]
    DIRECTION INPUT ;
    USE SIGNAL ;
    PORT
      LAYER M4 ;
        RECT 457.728 455.232 457.920 455.256 ;
    END
  END tap[188]
  PIN tap[189]
    DIRECTION INPUT ;
    USE SIGNAL ;
    PORT
      LAYER M4 ;
        RECT 457.728 455.328 457.920 455.352 ;
    END
  END tap[189]
  PIN tap[190]
    DIRECTION INPUT ;
    USE SIGNAL ;
    PORT
      LAYER M4 ;
        RECT 457.728 455.424 457.920 455.448 ;
    END
  END tap[190]
  PIN tap[191]
    DIRECTION INPUT ;
    USE SIGNAL ;
    PORT
      LAYER M4 ;
        RECT 457.728 455.520 457.920 455.544 ;
    END
  END tap[191]
  PIN tap[192]
    DIRECTION INPUT ;
    USE SIGNAL ;
    PORT
      LAYER M4 ;
        RECT 457.728 455.616 457.920 455.640 ;
    END
  END tap[192]
  PIN tap[193]
    DIRECTION INPUT ;
    USE SIGNAL ;
    PORT
      LAYER M4 ;
        RECT 457.728 455.712 457.920 455.736 ;
    END
  END tap[193]
  PIN tap[194]
    DIRECTION INPUT ;
    USE SIGNAL ;
    PORT
      LAYER M4 ;
        RECT 457.728 455.808 457.920 455.832 ;
    END
  END tap[194]
  PIN tap[195]
    DIRECTION INPUT ;
    USE SIGNAL ;
    PORT
      LAYER M4 ;
        RECT 457.728 455.904 457.920 455.928 ;
    END
  END tap[195]
  PIN tap[196]
    DIRECTION INPUT ;
    USE SIGNAL ;
    PORT
      LAYER M4 ;
        RECT 457.728 456.000 457.920 456.024 ;
    END
  END tap[196]
  PIN tap[197]
    DIRECTION INPUT ;
    USE SIGNAL ;
    PORT
      LAYER M4 ;
        RECT 457.728 456.096 457.920 456.120 ;
    END
  END tap[197]
  PIN tap[198]
    DIRECTION INPUT ;
    USE SIGNAL ;
    PORT
      LAYER M4 ;
        RECT 457.728 456.192 457.920 456.216 ;
    END
  END tap[198]
  PIN tap[199]
    DIRECTION INPUT ;
    USE SIGNAL ;
    PORT
      LAYER M4 ;
        RECT 457.728 456.288 457.920 456.312 ;
    END
  END tap[199]
  PIN tap[200]
    DIRECTION INPUT ;
    USE SIGNAL ;
    PORT
      LAYER M4 ;
        RECT 457.728 456.384 457.920 456.408 ;
    END
  END tap[200]
  PIN tap[201]
    DIRECTION INPUT ;
    USE SIGNAL ;
    PORT
      LAYER M4 ;
        RECT 457.728 456.480 457.920 456.504 ;
    END
  END tap[201]
  PIN tap[202]
    DIRECTION INPUT ;
    USE SIGNAL ;
    PORT
      LAYER M4 ;
        RECT 457.728 456.576 457.920 456.600 ;
    END
  END tap[202]
  PIN tap[203]
    DIRECTION INPUT ;
    USE SIGNAL ;
    PORT
      LAYER M4 ;
        RECT 457.728 456.672 457.920 456.696 ;
    END
  END tap[203]
  PIN tap[204]
    DIRECTION INPUT ;
    USE SIGNAL ;
    PORT
      LAYER M4 ;
        RECT 457.728 456.768 457.920 456.792 ;
    END
  END tap[204]
  PIN tap[205]
    DIRECTION INPUT ;
    USE SIGNAL ;
    PORT
      LAYER M4 ;
        RECT 457.728 456.864 457.920 456.888 ;
    END
  END tap[205]
  PIN tap[206]
    DIRECTION INPUT ;
    USE SIGNAL ;
    PORT
      LAYER M4 ;
        RECT 457.728 456.960 457.920 456.984 ;
    END
  END tap[206]
  PIN tap[207]
    DIRECTION INPUT ;
    USE SIGNAL ;
    PORT
      LAYER M4 ;
        RECT 457.728 457.056 457.920 457.080 ;
    END
  END tap[207]
  PIN tap[208]
    DIRECTION INPUT ;
    USE SIGNAL ;
    PORT
      LAYER M4 ;
        RECT 457.728 457.152 457.920 457.176 ;
    END
  END tap[208]
  PIN tap[209]
    DIRECTION INPUT ;
    USE SIGNAL ;
    PORT
      LAYER M4 ;
        RECT 457.728 457.248 457.920 457.272 ;
    END
  END tap[209]
  PIN tap[210]
    DIRECTION INPUT ;
    USE SIGNAL ;
    PORT
      LAYER M4 ;
        RECT 457.728 457.344 457.920 457.368 ;
    END
  END tap[210]
  PIN tap[211]
    DIRECTION INPUT ;
    USE SIGNAL ;
    PORT
      LAYER M4 ;
        RECT 457.728 457.440 457.920 457.464 ;
    END
  END tap[211]
  PIN tap[212]
    DIRECTION INPUT ;
    USE SIGNAL ;
    PORT
      LAYER M4 ;
        RECT 457.728 457.536 457.920 457.560 ;
    END
  END tap[212]
  PIN tap[213]
    DIRECTION INPUT ;
    USE SIGNAL ;
    PORT
      LAYER M4 ;
        RECT 457.728 457.632 457.920 457.656 ;
    END
  END tap[213]
  PIN tap[214]
    DIRECTION INPUT ;
    USE SIGNAL ;
    PORT
      LAYER M4 ;
        RECT 457.728 457.728 457.920 457.752 ;
    END
  END tap[214]
  PIN tap[215]
    DIRECTION INPUT ;
    USE SIGNAL ;
    PORT
      LAYER M4 ;
        RECT 457.728 457.824 457.920 457.848 ;
    END
  END tap[215]
  PIN tap[216]
    DIRECTION INPUT ;
    USE SIGNAL ;
    PORT
      LAYER M4 ;
        RECT 457.728 457.920 457.920 457.944 ;
    END
  END tap[216]
  PIN tap[217]
    DIRECTION INPUT ;
    USE SIGNAL ;
    PORT
      LAYER M4 ;
        RECT 457.728 458.016 457.920 458.040 ;
    END
  END tap[217]
  PIN tap[218]
    DIRECTION INPUT ;
    USE SIGNAL ;
    PORT
      LAYER M4 ;
        RECT 457.728 458.112 457.920 458.136 ;
    END
  END tap[218]
  PIN tap[219]
    DIRECTION INPUT ;
    USE SIGNAL ;
    PORT
      LAYER M4 ;
        RECT 457.728 458.208 457.920 458.232 ;
    END
  END tap[219]
  PIN tap[220]
    DIRECTION INPUT ;
    USE SIGNAL ;
    PORT
      LAYER M4 ;
        RECT 457.728 458.304 457.920 458.328 ;
    END
  END tap[220]
  PIN tap[221]
    DIRECTION INPUT ;
    USE SIGNAL ;
    PORT
      LAYER M4 ;
        RECT 457.728 458.400 457.920 458.424 ;
    END
  END tap[221]
  PIN tap[222]
    DIRECTION INPUT ;
    USE SIGNAL ;
    PORT
      LAYER M4 ;
        RECT 457.728 458.496 457.920 458.520 ;
    END
  END tap[222]
  PIN tap[223]
    DIRECTION INPUT ;
    USE SIGNAL ;
    PORT
      LAYER M4 ;
        RECT 457.728 458.592 457.920 458.616 ;
    END
  END tap[223]
  PIN tap[224]
    DIRECTION INPUT ;
    USE SIGNAL ;
    PORT
      LAYER M4 ;
        RECT 457.728 458.688 457.920 458.712 ;
    END
  END tap[224]
  PIN tap[225]
    DIRECTION INPUT ;
    USE SIGNAL ;
    PORT
      LAYER M4 ;
        RECT 457.728 458.784 457.920 458.808 ;
    END
  END tap[225]
  PIN tap[226]
    DIRECTION INPUT ;
    USE SIGNAL ;
    PORT
      LAYER M4 ;
        RECT 457.728 458.880 457.920 458.904 ;
    END
  END tap[226]
  PIN tap[227]
    DIRECTION INPUT ;
    USE SIGNAL ;
    PORT
      LAYER M4 ;
        RECT 457.728 458.976 457.920 459.000 ;
    END
  END tap[227]
  PIN tap[228]
    DIRECTION INPUT ;
    USE SIGNAL ;
    PORT
      LAYER M4 ;
        RECT 457.728 459.072 457.920 459.096 ;
    END
  END tap[228]
  PIN tap[229]
    DIRECTION INPUT ;
    USE SIGNAL ;
    PORT
      LAYER M4 ;
        RECT 457.728 459.168 457.920 459.192 ;
    END
  END tap[229]
  PIN tap[230]
    DIRECTION INPUT ;
    USE SIGNAL ;
    PORT
      LAYER M4 ;
        RECT 457.728 459.264 457.920 459.288 ;
    END
  END tap[230]
  PIN tap[231]
    DIRECTION INPUT ;
    USE SIGNAL ;
    PORT
      LAYER M4 ;
        RECT 457.728 459.360 457.920 459.384 ;
    END
  END tap[231]
  PIN tap[232]
    DIRECTION INPUT ;
    USE SIGNAL ;
    PORT
      LAYER M4 ;
        RECT 457.728 459.456 457.920 459.480 ;
    END
  END tap[232]
  PIN tap[233]
    DIRECTION INPUT ;
    USE SIGNAL ;
    PORT
      LAYER M4 ;
        RECT 457.728 459.552 457.920 459.576 ;
    END
  END tap[233]
  PIN tap[234]
    DIRECTION INPUT ;
    USE SIGNAL ;
    PORT
      LAYER M4 ;
        RECT 457.728 459.648 457.920 459.672 ;
    END
  END tap[234]
  PIN tap[235]
    DIRECTION INPUT ;
    USE SIGNAL ;
    PORT
      LAYER M4 ;
        RECT 457.728 459.744 457.920 459.768 ;
    END
  END tap[235]
  PIN tap[236]
    DIRECTION INPUT ;
    USE SIGNAL ;
    PORT
      LAYER M4 ;
        RECT 457.728 459.840 457.920 459.864 ;
    END
  END tap[236]
  PIN tap[237]
    DIRECTION INPUT ;
    USE SIGNAL ;
    PORT
      LAYER M4 ;
        RECT 457.728 459.936 457.920 459.960 ;
    END
  END tap[237]
  PIN tap[238]
    DIRECTION INPUT ;
    USE SIGNAL ;
    PORT
      LAYER M4 ;
        RECT 457.728 460.032 457.920 460.056 ;
    END
  END tap[238]
  PIN tap[239]
    DIRECTION INPUT ;
    USE SIGNAL ;
    PORT
      LAYER M4 ;
        RECT 457.728 460.128 457.920 460.152 ;
    END
  END tap[239]
  PIN tap[240]
    DIRECTION INPUT ;
    USE SIGNAL ;
    PORT
      LAYER M4 ;
        RECT 457.728 460.224 457.920 460.248 ;
    END
  END tap[240]
  PIN tap[241]
    DIRECTION INPUT ;
    USE SIGNAL ;
    PORT
      LAYER M4 ;
        RECT 457.728 460.320 457.920 460.344 ;
    END
  END tap[241]
  PIN tap[242]
    DIRECTION INPUT ;
    USE SIGNAL ;
    PORT
      LAYER M4 ;
        RECT 457.728 460.416 457.920 460.440 ;
    END
  END tap[242]
  PIN tap[243]
    DIRECTION INPUT ;
    USE SIGNAL ;
    PORT
      LAYER M4 ;
        RECT 457.728 460.512 457.920 460.536 ;
    END
  END tap[243]
  PIN tap[244]
    DIRECTION INPUT ;
    USE SIGNAL ;
    PORT
      LAYER M4 ;
        RECT 457.728 460.608 457.920 460.632 ;
    END
  END tap[244]
  PIN tap[245]
    DIRECTION INPUT ;
    USE SIGNAL ;
    PORT
      LAYER M4 ;
        RECT 457.728 460.704 457.920 460.728 ;
    END
  END tap[245]
  PIN tap[246]
    DIRECTION INPUT ;
    USE SIGNAL ;
    PORT
      LAYER M4 ;
        RECT 457.728 460.800 457.920 460.824 ;
    END
  END tap[246]
  PIN tap[247]
    DIRECTION INPUT ;
    USE SIGNAL ;
    PORT
      LAYER M4 ;
        RECT 457.728 460.896 457.920 460.920 ;
    END
  END tap[247]
  PIN tap[248]
    DIRECTION INPUT ;
    USE SIGNAL ;
    PORT
      LAYER M4 ;
        RECT 457.728 460.992 457.920 461.016 ;
    END
  END tap[248]
  PIN tap[249]
    DIRECTION INPUT ;
    USE SIGNAL ;
    PORT
      LAYER M4 ;
        RECT 457.728 461.088 457.920 461.112 ;
    END
  END tap[249]
  PIN tap[250]
    DIRECTION INPUT ;
    USE SIGNAL ;
    PORT
      LAYER M4 ;
        RECT 457.728 461.184 457.920 461.208 ;
    END
  END tap[250]
  PIN tap[251]
    DIRECTION INPUT ;
    USE SIGNAL ;
    PORT
      LAYER M4 ;
        RECT 457.728 461.280 457.920 461.304 ;
    END
  END tap[251]
  PIN tap[252]
    DIRECTION INPUT ;
    USE SIGNAL ;
    PORT
      LAYER M4 ;
        RECT 457.728 461.376 457.920 461.400 ;
    END
  END tap[252]
  PIN tap[253]
    DIRECTION INPUT ;
    USE SIGNAL ;
    PORT
      LAYER M4 ;
        RECT 457.728 461.472 457.920 461.496 ;
    END
  END tap[253]
  PIN tap[254]
    DIRECTION INPUT ;
    USE SIGNAL ;
    PORT
      LAYER M4 ;
        RECT 457.728 461.568 457.920 461.592 ;
    END
  END tap[254]
  PIN tap[255]
    DIRECTION INPUT ;
    USE SIGNAL ;
    PORT
      LAYER M4 ;
        RECT 457.728 461.664 457.920 461.688 ;
    END
  END tap[255]
  PIN tap[256]
    DIRECTION INPUT ;
    USE SIGNAL ;
    PORT
      LAYER M4 ;
        RECT 457.728 461.760 457.920 461.784 ;
    END
  END tap[256]
  PIN tap[257]
    DIRECTION INPUT ;
    USE SIGNAL ;
    PORT
      LAYER M4 ;
        RECT 457.728 461.856 457.920 461.880 ;
    END
  END tap[257]
  PIN tap[258]
    DIRECTION INPUT ;
    USE SIGNAL ;
    PORT
      LAYER M4 ;
        RECT 457.728 461.952 457.920 461.976 ;
    END
  END tap[258]
  PIN tap[259]
    DIRECTION INPUT ;
    USE SIGNAL ;
    PORT
      LAYER M4 ;
        RECT 457.728 462.048 457.920 462.072 ;
    END
  END tap[259]
  PIN tap[260]
    DIRECTION INPUT ;
    USE SIGNAL ;
    PORT
      LAYER M4 ;
        RECT 457.728 462.144 457.920 462.168 ;
    END
  END tap[260]
  PIN tap[261]
    DIRECTION INPUT ;
    USE SIGNAL ;
    PORT
      LAYER M4 ;
        RECT 457.728 462.240 457.920 462.264 ;
    END
  END tap[261]
  PIN tap[262]
    DIRECTION INPUT ;
    USE SIGNAL ;
    PORT
      LAYER M4 ;
        RECT 457.728 462.336 457.920 462.360 ;
    END
  END tap[262]
  PIN tap[263]
    DIRECTION INPUT ;
    USE SIGNAL ;
    PORT
      LAYER M4 ;
        RECT 457.728 462.432 457.920 462.456 ;
    END
  END tap[263]
  PIN tap[264]
    DIRECTION INPUT ;
    USE SIGNAL ;
    PORT
      LAYER M4 ;
        RECT 457.728 462.528 457.920 462.552 ;
    END
  END tap[264]
  PIN tap[265]
    DIRECTION INPUT ;
    USE SIGNAL ;
    PORT
      LAYER M4 ;
        RECT 457.728 462.624 457.920 462.648 ;
    END
  END tap[265]
  PIN tap[266]
    DIRECTION INPUT ;
    USE SIGNAL ;
    PORT
      LAYER M4 ;
        RECT 457.728 462.720 457.920 462.744 ;
    END
  END tap[266]
  PIN tap[267]
    DIRECTION INPUT ;
    USE SIGNAL ;
    PORT
      LAYER M4 ;
        RECT 457.728 462.816 457.920 462.840 ;
    END
  END tap[267]
  PIN tap[268]
    DIRECTION INPUT ;
    USE SIGNAL ;
    PORT
      LAYER M4 ;
        RECT 457.728 462.912 457.920 462.936 ;
    END
  END tap[268]
  PIN tap[269]
    DIRECTION INPUT ;
    USE SIGNAL ;
    PORT
      LAYER M4 ;
        RECT 457.728 463.008 457.920 463.032 ;
    END
  END tap[269]
  PIN tap[270]
    DIRECTION INPUT ;
    USE SIGNAL ;
    PORT
      LAYER M4 ;
        RECT 457.728 463.104 457.920 463.128 ;
    END
  END tap[270]
  PIN tap[271]
    DIRECTION INPUT ;
    USE SIGNAL ;
    PORT
      LAYER M4 ;
        RECT 457.728 463.200 457.920 463.224 ;
    END
  END tap[271]
  PIN tap[272]
    DIRECTION INPUT ;
    USE SIGNAL ;
    PORT
      LAYER M4 ;
        RECT 457.728 463.296 457.920 463.320 ;
    END
  END tap[272]
  PIN tap[273]
    DIRECTION INPUT ;
    USE SIGNAL ;
    PORT
      LAYER M4 ;
        RECT 457.728 463.392 457.920 463.416 ;
    END
  END tap[273]
  PIN tap[274]
    DIRECTION INPUT ;
    USE SIGNAL ;
    PORT
      LAYER M4 ;
        RECT 457.728 463.488 457.920 463.512 ;
    END
  END tap[274]
  PIN tap[275]
    DIRECTION INPUT ;
    USE SIGNAL ;
    PORT
      LAYER M4 ;
        RECT 457.728 463.584 457.920 463.608 ;
    END
  END tap[275]
  PIN tap[276]
    DIRECTION INPUT ;
    USE SIGNAL ;
    PORT
      LAYER M4 ;
        RECT 457.728 463.680 457.920 463.704 ;
    END
  END tap[276]
  PIN tap[277]
    DIRECTION INPUT ;
    USE SIGNAL ;
    PORT
      LAYER M4 ;
        RECT 457.728 463.776 457.920 463.800 ;
    END
  END tap[277]
  PIN tap[278]
    DIRECTION INPUT ;
    USE SIGNAL ;
    PORT
      LAYER M4 ;
        RECT 457.728 463.872 457.920 463.896 ;
    END
  END tap[278]
  PIN tap[279]
    DIRECTION INPUT ;
    USE SIGNAL ;
    PORT
      LAYER M4 ;
        RECT 457.728 463.968 457.920 463.992 ;
    END
  END tap[279]
  PIN tap[280]
    DIRECTION INPUT ;
    USE SIGNAL ;
    PORT
      LAYER M4 ;
        RECT 457.728 464.064 457.920 464.088 ;
    END
  END tap[280]
  PIN tap[281]
    DIRECTION INPUT ;
    USE SIGNAL ;
    PORT
      LAYER M4 ;
        RECT 457.728 464.160 457.920 464.184 ;
    END
  END tap[281]
  PIN tap[282]
    DIRECTION INPUT ;
    USE SIGNAL ;
    PORT
      LAYER M4 ;
        RECT 457.728 464.256 457.920 464.280 ;
    END
  END tap[282]
  PIN tap[283]
    DIRECTION INPUT ;
    USE SIGNAL ;
    PORT
      LAYER M4 ;
        RECT 457.728 464.352 457.920 464.376 ;
    END
  END tap[283]
  PIN tap[284]
    DIRECTION INPUT ;
    USE SIGNAL ;
    PORT
      LAYER M4 ;
        RECT 457.728 464.448 457.920 464.472 ;
    END
  END tap[284]
  PIN tap[285]
    DIRECTION INPUT ;
    USE SIGNAL ;
    PORT
      LAYER M4 ;
        RECT 457.728 464.544 457.920 464.568 ;
    END
  END tap[285]
  PIN tap[286]
    DIRECTION INPUT ;
    USE SIGNAL ;
    PORT
      LAYER M4 ;
        RECT 457.728 464.640 457.920 464.664 ;
    END
  END tap[286]
  PIN tap[287]
    DIRECTION INPUT ;
    USE SIGNAL ;
    PORT
      LAYER M4 ;
        RECT 457.728 464.736 457.920 464.760 ;
    END
  END tap[287]
  PIN tap[288]
    DIRECTION INPUT ;
    USE SIGNAL ;
    PORT
      LAYER M4 ;
        RECT 457.728 464.832 457.920 464.856 ;
    END
  END tap[288]
  PIN tap[289]
    DIRECTION INPUT ;
    USE SIGNAL ;
    PORT
      LAYER M4 ;
        RECT 457.728 464.928 457.920 464.952 ;
    END
  END tap[289]
  PIN tap[290]
    DIRECTION INPUT ;
    USE SIGNAL ;
    PORT
      LAYER M4 ;
        RECT 457.728 465.024 457.920 465.048 ;
    END
  END tap[290]
  PIN tap[291]
    DIRECTION INPUT ;
    USE SIGNAL ;
    PORT
      LAYER M4 ;
        RECT 457.728 465.120 457.920 465.144 ;
    END
  END tap[291]
  PIN tap[292]
    DIRECTION INPUT ;
    USE SIGNAL ;
    PORT
      LAYER M4 ;
        RECT 457.728 465.216 457.920 465.240 ;
    END
  END tap[292]
  PIN tap[293]
    DIRECTION INPUT ;
    USE SIGNAL ;
    PORT
      LAYER M4 ;
        RECT 457.728 465.312 457.920 465.336 ;
    END
  END tap[293]
  PIN tap[294]
    DIRECTION INPUT ;
    USE SIGNAL ;
    PORT
      LAYER M4 ;
        RECT 457.728 465.408 457.920 465.432 ;
    END
  END tap[294]
  PIN tap[295]
    DIRECTION INPUT ;
    USE SIGNAL ;
    PORT
      LAYER M4 ;
        RECT 457.728 465.504 457.920 465.528 ;
    END
  END tap[295]
  PIN tap[296]
    DIRECTION INPUT ;
    USE SIGNAL ;
    PORT
      LAYER M4 ;
        RECT 457.728 465.600 457.920 465.624 ;
    END
  END tap[296]
  PIN tap[297]
    DIRECTION INPUT ;
    USE SIGNAL ;
    PORT
      LAYER M4 ;
        RECT 457.728 465.696 457.920 465.720 ;
    END
  END tap[297]
  PIN tap[298]
    DIRECTION INPUT ;
    USE SIGNAL ;
    PORT
      LAYER M4 ;
        RECT 457.728 465.792 457.920 465.816 ;
    END
  END tap[298]
  PIN tap[299]
    DIRECTION INPUT ;
    USE SIGNAL ;
    PORT
      LAYER M4 ;
        RECT 457.728 465.888 457.920 465.912 ;
    END
  END tap[299]
  PIN tap[300]
    DIRECTION INPUT ;
    USE SIGNAL ;
    PORT
      LAYER M4 ;
        RECT 457.728 465.984 457.920 466.008 ;
    END
  END tap[300]
  PIN tap[301]
    DIRECTION INPUT ;
    USE SIGNAL ;
    PORT
      LAYER M4 ;
        RECT 457.728 466.080 457.920 466.104 ;
    END
  END tap[301]
  PIN tap[302]
    DIRECTION INPUT ;
    USE SIGNAL ;
    PORT
      LAYER M4 ;
        RECT 457.728 466.176 457.920 466.200 ;
    END
  END tap[302]
  PIN tap[303]
    DIRECTION INPUT ;
    USE SIGNAL ;
    PORT
      LAYER M4 ;
        RECT 457.728 466.272 457.920 466.296 ;
    END
  END tap[303]
  PIN tap[304]
    DIRECTION INPUT ;
    USE SIGNAL ;
    PORT
      LAYER M4 ;
        RECT 457.728 466.368 457.920 466.392 ;
    END
  END tap[304]
  PIN tap[305]
    DIRECTION INPUT ;
    USE SIGNAL ;
    PORT
      LAYER M4 ;
        RECT 457.728 466.464 457.920 466.488 ;
    END
  END tap[305]
  PIN tap[306]
    DIRECTION INPUT ;
    USE SIGNAL ;
    PORT
      LAYER M4 ;
        RECT 457.728 466.560 457.920 466.584 ;
    END
  END tap[306]
  PIN tap[307]
    DIRECTION INPUT ;
    USE SIGNAL ;
    PORT
      LAYER M4 ;
        RECT 457.728 466.656 457.920 466.680 ;
    END
  END tap[307]
  PIN tap[308]
    DIRECTION INPUT ;
    USE SIGNAL ;
    PORT
      LAYER M4 ;
        RECT 457.728 466.752 457.920 466.776 ;
    END
  END tap[308]
  PIN tap[309]
    DIRECTION INPUT ;
    USE SIGNAL ;
    PORT
      LAYER M4 ;
        RECT 457.728 466.848 457.920 466.872 ;
    END
  END tap[309]
  PIN tap[310]
    DIRECTION INPUT ;
    USE SIGNAL ;
    PORT
      LAYER M4 ;
        RECT 457.728 466.944 457.920 466.968 ;
    END
  END tap[310]
  PIN tap[311]
    DIRECTION INPUT ;
    USE SIGNAL ;
    PORT
      LAYER M4 ;
        RECT 457.728 467.040 457.920 467.064 ;
    END
  END tap[311]
  PIN tap[312]
    DIRECTION INPUT ;
    USE SIGNAL ;
    PORT
      LAYER M4 ;
        RECT 457.728 467.136 457.920 467.160 ;
    END
  END tap[312]
  PIN tap[313]
    DIRECTION INPUT ;
    USE SIGNAL ;
    PORT
      LAYER M4 ;
        RECT 457.728 467.232 457.920 467.256 ;
    END
  END tap[313]
  PIN tap[314]
    DIRECTION INPUT ;
    USE SIGNAL ;
    PORT
      LAYER M4 ;
        RECT 457.728 467.328 457.920 467.352 ;
    END
  END tap[314]
  PIN tap[315]
    DIRECTION INPUT ;
    USE SIGNAL ;
    PORT
      LAYER M4 ;
        RECT 457.728 467.424 457.920 467.448 ;
    END
  END tap[315]
  PIN tap[316]
    DIRECTION INPUT ;
    USE SIGNAL ;
    PORT
      LAYER M4 ;
        RECT 457.728 467.520 457.920 467.544 ;
    END
  END tap[316]
  PIN tap[317]
    DIRECTION INPUT ;
    USE SIGNAL ;
    PORT
      LAYER M4 ;
        RECT 457.728 467.616 457.920 467.640 ;
    END
  END tap[317]
  PIN tap[318]
    DIRECTION INPUT ;
    USE SIGNAL ;
    PORT
      LAYER M4 ;
        RECT 457.728 467.712 457.920 467.736 ;
    END
  END tap[318]
  PIN tap[319]
    DIRECTION INPUT ;
    USE SIGNAL ;
    PORT
      LAYER M4 ;
        RECT 457.728 467.808 457.920 467.832 ;
    END
  END tap[319]
  PIN tap[320]
    DIRECTION INPUT ;
    USE SIGNAL ;
    PORT
      LAYER M4 ;
        RECT 457.728 467.904 457.920 467.928 ;
    END
  END tap[320]
  PIN tap[321]
    DIRECTION INPUT ;
    USE SIGNAL ;
    PORT
      LAYER M4 ;
        RECT 457.728 468.000 457.920 468.024 ;
    END
  END tap[321]
  PIN tap[322]
    DIRECTION INPUT ;
    USE SIGNAL ;
    PORT
      LAYER M4 ;
        RECT 457.728 468.096 457.920 468.120 ;
    END
  END tap[322]
  PIN tap[323]
    DIRECTION INPUT ;
    USE SIGNAL ;
    PORT
      LAYER M4 ;
        RECT 457.728 468.192 457.920 468.216 ;
    END
  END tap[323]
  PIN tap[324]
    DIRECTION INPUT ;
    USE SIGNAL ;
    PORT
      LAYER M4 ;
        RECT 457.728 468.288 457.920 468.312 ;
    END
  END tap[324]
  PIN tap[325]
    DIRECTION INPUT ;
    USE SIGNAL ;
    PORT
      LAYER M4 ;
        RECT 457.728 468.384 457.920 468.408 ;
    END
  END tap[325]
  PIN tap[326]
    DIRECTION INPUT ;
    USE SIGNAL ;
    PORT
      LAYER M4 ;
        RECT 457.728 468.480 457.920 468.504 ;
    END
  END tap[326]
  PIN tap[327]
    DIRECTION INPUT ;
    USE SIGNAL ;
    PORT
      LAYER M4 ;
        RECT 457.728 468.576 457.920 468.600 ;
    END
  END tap[327]
  PIN tap[328]
    DIRECTION INPUT ;
    USE SIGNAL ;
    PORT
      LAYER M4 ;
        RECT 457.728 468.672 457.920 468.696 ;
    END
  END tap[328]
  PIN tap[329]
    DIRECTION INPUT ;
    USE SIGNAL ;
    PORT
      LAYER M4 ;
        RECT 457.728 468.768 457.920 468.792 ;
    END
  END tap[329]
  PIN tap[330]
    DIRECTION INPUT ;
    USE SIGNAL ;
    PORT
      LAYER M4 ;
        RECT 457.728 468.864 457.920 468.888 ;
    END
  END tap[330]
  PIN tap[331]
    DIRECTION INPUT ;
    USE SIGNAL ;
    PORT
      LAYER M4 ;
        RECT 457.728 468.960 457.920 468.984 ;
    END
  END tap[331]
  PIN tap[332]
    DIRECTION INPUT ;
    USE SIGNAL ;
    PORT
      LAYER M4 ;
        RECT 457.728 469.056 457.920 469.080 ;
    END
  END tap[332]
  PIN tap[333]
    DIRECTION INPUT ;
    USE SIGNAL ;
    PORT
      LAYER M4 ;
        RECT 457.728 469.152 457.920 469.176 ;
    END
  END tap[333]
  PIN tap[334]
    DIRECTION INPUT ;
    USE SIGNAL ;
    PORT
      LAYER M4 ;
        RECT 457.728 469.248 457.920 469.272 ;
    END
  END tap[334]
  PIN tap[335]
    DIRECTION INPUT ;
    USE SIGNAL ;
    PORT
      LAYER M4 ;
        RECT 457.728 469.344 457.920 469.368 ;
    END
  END tap[335]
  PIN tap[336]
    DIRECTION INPUT ;
    USE SIGNAL ;
    PORT
      LAYER M4 ;
        RECT 457.728 469.440 457.920 469.464 ;
    END
  END tap[336]
  PIN tap[337]
    DIRECTION INPUT ;
    USE SIGNAL ;
    PORT
      LAYER M4 ;
        RECT 457.728 469.536 457.920 469.560 ;
    END
  END tap[337]
  PIN tap[338]
    DIRECTION INPUT ;
    USE SIGNAL ;
    PORT
      LAYER M4 ;
        RECT 457.728 469.632 457.920 469.656 ;
    END
  END tap[338]
  PIN tap[339]
    DIRECTION INPUT ;
    USE SIGNAL ;
    PORT
      LAYER M4 ;
        RECT 457.728 469.728 457.920 469.752 ;
    END
  END tap[339]
  PIN tap[340]
    DIRECTION INPUT ;
    USE SIGNAL ;
    PORT
      LAYER M4 ;
        RECT 457.728 469.824 457.920 469.848 ;
    END
  END tap[340]
  PIN tap[341]
    DIRECTION INPUT ;
    USE SIGNAL ;
    PORT
      LAYER M4 ;
        RECT 457.728 469.920 457.920 469.944 ;
    END
  END tap[341]
  PIN tap[342]
    DIRECTION INPUT ;
    USE SIGNAL ;
    PORT
      LAYER M4 ;
        RECT 457.728 470.016 457.920 470.040 ;
    END
  END tap[342]
  PIN tap[343]
    DIRECTION INPUT ;
    USE SIGNAL ;
    PORT
      LAYER M4 ;
        RECT 457.728 470.112 457.920 470.136 ;
    END
  END tap[343]
  PIN tap[344]
    DIRECTION INPUT ;
    USE SIGNAL ;
    PORT
      LAYER M4 ;
        RECT 457.728 470.208 457.920 470.232 ;
    END
  END tap[344]
  PIN tap[345]
    DIRECTION INPUT ;
    USE SIGNAL ;
    PORT
      LAYER M4 ;
        RECT 457.728 470.304 457.920 470.328 ;
    END
  END tap[345]
  PIN tap[346]
    DIRECTION INPUT ;
    USE SIGNAL ;
    PORT
      LAYER M4 ;
        RECT 457.728 470.400 457.920 470.424 ;
    END
  END tap[346]
  PIN tap[347]
    DIRECTION INPUT ;
    USE SIGNAL ;
    PORT
      LAYER M4 ;
        RECT 457.728 470.496 457.920 470.520 ;
    END
  END tap[347]
  PIN tap[348]
    DIRECTION INPUT ;
    USE SIGNAL ;
    PORT
      LAYER M4 ;
        RECT 457.728 470.592 457.920 470.616 ;
    END
  END tap[348]
  PIN tap[349]
    DIRECTION INPUT ;
    USE SIGNAL ;
    PORT
      LAYER M4 ;
        RECT 457.728 470.688 457.920 470.712 ;
    END
  END tap[349]
  PIN tap[350]
    DIRECTION INPUT ;
    USE SIGNAL ;
    PORT
      LAYER M4 ;
        RECT 457.728 470.784 457.920 470.808 ;
    END
  END tap[350]
  PIN tap[351]
    DIRECTION INPUT ;
    USE SIGNAL ;
    PORT
      LAYER M4 ;
        RECT 457.728 470.880 457.920 470.904 ;
    END
  END tap[351]
  PIN tap[352]
    DIRECTION INPUT ;
    USE SIGNAL ;
    PORT
      LAYER M4 ;
        RECT 457.728 470.976 457.920 471.000 ;
    END
  END tap[352]
  PIN tap[353]
    DIRECTION INPUT ;
    USE SIGNAL ;
    PORT
      LAYER M4 ;
        RECT 457.728 471.072 457.920 471.096 ;
    END
  END tap[353]
  PIN tap[354]
    DIRECTION INPUT ;
    USE SIGNAL ;
    PORT
      LAYER M4 ;
        RECT 457.728 471.168 457.920 471.192 ;
    END
  END tap[354]
  PIN tap[355]
    DIRECTION INPUT ;
    USE SIGNAL ;
    PORT
      LAYER M4 ;
        RECT 457.728 471.264 457.920 471.288 ;
    END
  END tap[355]
  PIN tap[356]
    DIRECTION INPUT ;
    USE SIGNAL ;
    PORT
      LAYER M4 ;
        RECT 457.728 471.360 457.920 471.384 ;
    END
  END tap[356]
  PIN tap[357]
    DIRECTION INPUT ;
    USE SIGNAL ;
    PORT
      LAYER M4 ;
        RECT 457.728 471.456 457.920 471.480 ;
    END
  END tap[357]
  PIN tap[358]
    DIRECTION INPUT ;
    USE SIGNAL ;
    PORT
      LAYER M4 ;
        RECT 457.728 471.552 457.920 471.576 ;
    END
  END tap[358]
  PIN tap[359]
    DIRECTION INPUT ;
    USE SIGNAL ;
    PORT
      LAYER M4 ;
        RECT 457.728 471.648 457.920 471.672 ;
    END
  END tap[359]
  PIN tap[360]
    DIRECTION INPUT ;
    USE SIGNAL ;
    PORT
      LAYER M4 ;
        RECT 457.728 471.744 457.920 471.768 ;
    END
  END tap[360]
  PIN tap[361]
    DIRECTION INPUT ;
    USE SIGNAL ;
    PORT
      LAYER M4 ;
        RECT 457.728 471.840 457.920 471.864 ;
    END
  END tap[361]
  PIN tap[362]
    DIRECTION INPUT ;
    USE SIGNAL ;
    PORT
      LAYER M4 ;
        RECT 457.728 471.936 457.920 471.960 ;
    END
  END tap[362]
  PIN tap[363]
    DIRECTION INPUT ;
    USE SIGNAL ;
    PORT
      LAYER M4 ;
        RECT 457.728 472.032 457.920 472.056 ;
    END
  END tap[363]
  PIN tap[364]
    DIRECTION INPUT ;
    USE SIGNAL ;
    PORT
      LAYER M4 ;
        RECT 457.728 472.128 457.920 472.152 ;
    END
  END tap[364]
  PIN tap[365]
    DIRECTION INPUT ;
    USE SIGNAL ;
    PORT
      LAYER M4 ;
        RECT 457.728 472.224 457.920 472.248 ;
    END
  END tap[365]
  PIN tap[366]
    DIRECTION INPUT ;
    USE SIGNAL ;
    PORT
      LAYER M4 ;
        RECT 457.728 472.320 457.920 472.344 ;
    END
  END tap[366]
  PIN tap[367]
    DIRECTION INPUT ;
    USE SIGNAL ;
    PORT
      LAYER M4 ;
        RECT 457.728 472.416 457.920 472.440 ;
    END
  END tap[367]
  PIN tap[368]
    DIRECTION INPUT ;
    USE SIGNAL ;
    PORT
      LAYER M4 ;
        RECT 457.728 472.512 457.920 472.536 ;
    END
  END tap[368]
  PIN tap[369]
    DIRECTION INPUT ;
    USE SIGNAL ;
    PORT
      LAYER M4 ;
        RECT 457.728 472.608 457.920 472.632 ;
    END
  END tap[369]
  PIN tap[370]
    DIRECTION INPUT ;
    USE SIGNAL ;
    PORT
      LAYER M4 ;
        RECT 457.728 472.704 457.920 472.728 ;
    END
  END tap[370]
  PIN tap[371]
    DIRECTION INPUT ;
    USE SIGNAL ;
    PORT
      LAYER M4 ;
        RECT 457.728 472.800 457.920 472.824 ;
    END
  END tap[371]
  PIN tap[372]
    DIRECTION INPUT ;
    USE SIGNAL ;
    PORT
      LAYER M4 ;
        RECT 457.728 472.896 457.920 472.920 ;
    END
  END tap[372]
  PIN tap[373]
    DIRECTION INPUT ;
    USE SIGNAL ;
    PORT
      LAYER M4 ;
        RECT 457.728 472.992 457.920 473.016 ;
    END
  END tap[373]
  PIN tap[374]
    DIRECTION INPUT ;
    USE SIGNAL ;
    PORT
      LAYER M4 ;
        RECT 457.728 473.088 457.920 473.112 ;
    END
  END tap[374]
  PIN tap[375]
    DIRECTION INPUT ;
    USE SIGNAL ;
    PORT
      LAYER M4 ;
        RECT 457.728 473.184 457.920 473.208 ;
    END
  END tap[375]
  PIN tap[376]
    DIRECTION INPUT ;
    USE SIGNAL ;
    PORT
      LAYER M4 ;
        RECT 457.728 473.280 457.920 473.304 ;
    END
  END tap[376]
  PIN tap[377]
    DIRECTION INPUT ;
    USE SIGNAL ;
    PORT
      LAYER M4 ;
        RECT 457.728 473.376 457.920 473.400 ;
    END
  END tap[377]
  PIN tap[378]
    DIRECTION INPUT ;
    USE SIGNAL ;
    PORT
      LAYER M4 ;
        RECT 457.728 473.472 457.920 473.496 ;
    END
  END tap[378]
  PIN tap[379]
    DIRECTION INPUT ;
    USE SIGNAL ;
    PORT
      LAYER M4 ;
        RECT 457.728 473.568 457.920 473.592 ;
    END
  END tap[379]
  PIN tap[380]
    DIRECTION INPUT ;
    USE SIGNAL ;
    PORT
      LAYER M4 ;
        RECT 457.728 473.664 457.920 473.688 ;
    END
  END tap[380]
  PIN tap[381]
    DIRECTION INPUT ;
    USE SIGNAL ;
    PORT
      LAYER M4 ;
        RECT 457.728 473.760 457.920 473.784 ;
    END
  END tap[381]
  PIN tap[382]
    DIRECTION INPUT ;
    USE SIGNAL ;
    PORT
      LAYER M4 ;
        RECT 457.728 473.856 457.920 473.880 ;
    END
  END tap[382]
  PIN tap[383]
    DIRECTION INPUT ;
    USE SIGNAL ;
    PORT
      LAYER M4 ;
        RECT 457.728 473.952 457.920 473.976 ;
    END
  END tap[383]
  PIN tap[384]
    DIRECTION INPUT ;
    USE SIGNAL ;
    PORT
      LAYER M4 ;
        RECT 457.728 474.048 457.920 474.072 ;
    END
  END tap[384]
  PIN tap[385]
    DIRECTION INPUT ;
    USE SIGNAL ;
    PORT
      LAYER M4 ;
        RECT 457.728 474.144 457.920 474.168 ;
    END
  END tap[385]
  PIN tap[386]
    DIRECTION INPUT ;
    USE SIGNAL ;
    PORT
      LAYER M4 ;
        RECT 457.728 474.240 457.920 474.264 ;
    END
  END tap[386]
  PIN tap[387]
    DIRECTION INPUT ;
    USE SIGNAL ;
    PORT
      LAYER M4 ;
        RECT 457.728 474.336 457.920 474.360 ;
    END
  END tap[387]
  PIN tap[388]
    DIRECTION INPUT ;
    USE SIGNAL ;
    PORT
      LAYER M4 ;
        RECT 457.728 474.432 457.920 474.456 ;
    END
  END tap[388]
  PIN tap[389]
    DIRECTION INPUT ;
    USE SIGNAL ;
    PORT
      LAYER M4 ;
        RECT 457.728 474.528 457.920 474.552 ;
    END
  END tap[389]
  PIN tap[390]
    DIRECTION INPUT ;
    USE SIGNAL ;
    PORT
      LAYER M4 ;
        RECT 457.728 474.624 457.920 474.648 ;
    END
  END tap[390]
  PIN tap[391]
    DIRECTION INPUT ;
    USE SIGNAL ;
    PORT
      LAYER M4 ;
        RECT 457.728 474.720 457.920 474.744 ;
    END
  END tap[391]
  PIN tap[392]
    DIRECTION INPUT ;
    USE SIGNAL ;
    PORT
      LAYER M4 ;
        RECT 457.728 474.816 457.920 474.840 ;
    END
  END tap[392]
  PIN tap[393]
    DIRECTION INPUT ;
    USE SIGNAL ;
    PORT
      LAYER M4 ;
        RECT 457.728 474.912 457.920 474.936 ;
    END
  END tap[393]
  PIN tap[394]
    DIRECTION INPUT ;
    USE SIGNAL ;
    PORT
      LAYER M4 ;
        RECT 457.728 475.008 457.920 475.032 ;
    END
  END tap[394]
  PIN tap[395]
    DIRECTION INPUT ;
    USE SIGNAL ;
    PORT
      LAYER M4 ;
        RECT 457.728 475.104 457.920 475.128 ;
    END
  END tap[395]
  PIN tap[396]
    DIRECTION INPUT ;
    USE SIGNAL ;
    PORT
      LAYER M4 ;
        RECT 457.728 475.200 457.920 475.224 ;
    END
  END tap[396]
  PIN tap[397]
    DIRECTION INPUT ;
    USE SIGNAL ;
    PORT
      LAYER M4 ;
        RECT 457.728 475.296 457.920 475.320 ;
    END
  END tap[397]
  PIN tap[398]
    DIRECTION INPUT ;
    USE SIGNAL ;
    PORT
      LAYER M4 ;
        RECT 457.728 475.392 457.920 475.416 ;
    END
  END tap[398]
  PIN tap[399]
    DIRECTION INPUT ;
    USE SIGNAL ;
    PORT
      LAYER M4 ;
        RECT 457.728 475.488 457.920 475.512 ;
    END
  END tap[399]
  PIN tap[400]
    DIRECTION INPUT ;
    USE SIGNAL ;
    PORT
      LAYER M4 ;
        RECT 457.728 475.584 457.920 475.608 ;
    END
  END tap[400]
  PIN tap[401]
    DIRECTION INPUT ;
    USE SIGNAL ;
    PORT
      LAYER M4 ;
        RECT 457.728 475.680 457.920 475.704 ;
    END
  END tap[401]
  PIN tap[402]
    DIRECTION INPUT ;
    USE SIGNAL ;
    PORT
      LAYER M4 ;
        RECT 457.728 475.776 457.920 475.800 ;
    END
  END tap[402]
  PIN tap[403]
    DIRECTION INPUT ;
    USE SIGNAL ;
    PORT
      LAYER M4 ;
        RECT 457.728 475.872 457.920 475.896 ;
    END
  END tap[403]
  PIN tap[404]
    DIRECTION INPUT ;
    USE SIGNAL ;
    PORT
      LAYER M4 ;
        RECT 457.728 475.968 457.920 475.992 ;
    END
  END tap[404]
  PIN tap[405]
    DIRECTION INPUT ;
    USE SIGNAL ;
    PORT
      LAYER M4 ;
        RECT 457.728 476.064 457.920 476.088 ;
    END
  END tap[405]
  PIN tap[406]
    DIRECTION INPUT ;
    USE SIGNAL ;
    PORT
      LAYER M4 ;
        RECT 457.728 476.160 457.920 476.184 ;
    END
  END tap[406]
  PIN tap[407]
    DIRECTION INPUT ;
    USE SIGNAL ;
    PORT
      LAYER M4 ;
        RECT 457.728 476.256 457.920 476.280 ;
    END
  END tap[407]
  PIN tap[408]
    DIRECTION INPUT ;
    USE SIGNAL ;
    PORT
      LAYER M4 ;
        RECT 457.728 476.352 457.920 476.376 ;
    END
  END tap[408]
  PIN tap[409]
    DIRECTION INPUT ;
    USE SIGNAL ;
    PORT
      LAYER M4 ;
        RECT 457.728 476.448 457.920 476.472 ;
    END
  END tap[409]
  PIN tap[410]
    DIRECTION INPUT ;
    USE SIGNAL ;
    PORT
      LAYER M4 ;
        RECT 457.728 476.544 457.920 476.568 ;
    END
  END tap[410]
  PIN tap[411]
    DIRECTION INPUT ;
    USE SIGNAL ;
    PORT
      LAYER M4 ;
        RECT 457.728 476.640 457.920 476.664 ;
    END
  END tap[411]
  PIN tap[412]
    DIRECTION INPUT ;
    USE SIGNAL ;
    PORT
      LAYER M4 ;
        RECT 457.728 476.736 457.920 476.760 ;
    END
  END tap[412]
  PIN tap[413]
    DIRECTION INPUT ;
    USE SIGNAL ;
    PORT
      LAYER M4 ;
        RECT 457.728 476.832 457.920 476.856 ;
    END
  END tap[413]
  PIN tap[414]
    DIRECTION INPUT ;
    USE SIGNAL ;
    PORT
      LAYER M4 ;
        RECT 457.728 476.928 457.920 476.952 ;
    END
  END tap[414]
  PIN tap[415]
    DIRECTION INPUT ;
    USE SIGNAL ;
    PORT
      LAYER M4 ;
        RECT 457.728 477.024 457.920 477.048 ;
    END
  END tap[415]
  PIN tap[416]
    DIRECTION INPUT ;
    USE SIGNAL ;
    PORT
      LAYER M4 ;
        RECT 457.728 477.120 457.920 477.144 ;
    END
  END tap[416]
  PIN tap[417]
    DIRECTION INPUT ;
    USE SIGNAL ;
    PORT
      LAYER M4 ;
        RECT 457.728 477.216 457.920 477.240 ;
    END
  END tap[417]
  PIN tap[418]
    DIRECTION INPUT ;
    USE SIGNAL ;
    PORT
      LAYER M4 ;
        RECT 457.728 477.312 457.920 477.336 ;
    END
  END tap[418]
  PIN tap[419]
    DIRECTION INPUT ;
    USE SIGNAL ;
    PORT
      LAYER M4 ;
        RECT 457.728 477.408 457.920 477.432 ;
    END
  END tap[419]
  PIN tap[420]
    DIRECTION INPUT ;
    USE SIGNAL ;
    PORT
      LAYER M4 ;
        RECT 457.728 477.504 457.920 477.528 ;
    END
  END tap[420]
  PIN tap[421]
    DIRECTION INPUT ;
    USE SIGNAL ;
    PORT
      LAYER M4 ;
        RECT 457.728 477.600 457.920 477.624 ;
    END
  END tap[421]
  PIN tap[422]
    DIRECTION INPUT ;
    USE SIGNAL ;
    PORT
      LAYER M4 ;
        RECT 457.728 477.696 457.920 477.720 ;
    END
  END tap[422]
  PIN tap[423]
    DIRECTION INPUT ;
    USE SIGNAL ;
    PORT
      LAYER M4 ;
        RECT 457.728 477.792 457.920 477.816 ;
    END
  END tap[423]
  PIN tap[424]
    DIRECTION INPUT ;
    USE SIGNAL ;
    PORT
      LAYER M4 ;
        RECT 457.728 477.888 457.920 477.912 ;
    END
  END tap[424]
  PIN tap[425]
    DIRECTION INPUT ;
    USE SIGNAL ;
    PORT
      LAYER M4 ;
        RECT 457.728 477.984 457.920 478.008 ;
    END
  END tap[425]
  PIN tap[426]
    DIRECTION INPUT ;
    USE SIGNAL ;
    PORT
      LAYER M4 ;
        RECT 457.728 478.080 457.920 478.104 ;
    END
  END tap[426]
  PIN tap[427]
    DIRECTION INPUT ;
    USE SIGNAL ;
    PORT
      LAYER M4 ;
        RECT 457.728 478.176 457.920 478.200 ;
    END
  END tap[427]
  PIN tap[428]
    DIRECTION INPUT ;
    USE SIGNAL ;
    PORT
      LAYER M4 ;
        RECT 457.728 478.272 457.920 478.296 ;
    END
  END tap[428]
  PIN tap[429]
    DIRECTION INPUT ;
    USE SIGNAL ;
    PORT
      LAYER M4 ;
        RECT 457.728 478.368 457.920 478.392 ;
    END
  END tap[429]
  PIN tap[430]
    DIRECTION INPUT ;
    USE SIGNAL ;
    PORT
      LAYER M4 ;
        RECT 457.728 478.464 457.920 478.488 ;
    END
  END tap[430]
  PIN tap[431]
    DIRECTION INPUT ;
    USE SIGNAL ;
    PORT
      LAYER M4 ;
        RECT 457.728 478.560 457.920 478.584 ;
    END
  END tap[431]
  PIN tap[432]
    DIRECTION INPUT ;
    USE SIGNAL ;
    PORT
      LAYER M4 ;
        RECT 457.728 478.656 457.920 478.680 ;
    END
  END tap[432]
  PIN tap[433]
    DIRECTION INPUT ;
    USE SIGNAL ;
    PORT
      LAYER M4 ;
        RECT 457.728 478.752 457.920 478.776 ;
    END
  END tap[433]
  PIN tap[434]
    DIRECTION INPUT ;
    USE SIGNAL ;
    PORT
      LAYER M4 ;
        RECT 457.728 478.848 457.920 478.872 ;
    END
  END tap[434]
  PIN tap[435]
    DIRECTION INPUT ;
    USE SIGNAL ;
    PORT
      LAYER M4 ;
        RECT 457.728 478.944 457.920 478.968 ;
    END
  END tap[435]
  PIN tap[436]
    DIRECTION INPUT ;
    USE SIGNAL ;
    PORT
      LAYER M4 ;
        RECT 457.728 479.040 457.920 479.064 ;
    END
  END tap[436]
  PIN tap[437]
    DIRECTION INPUT ;
    USE SIGNAL ;
    PORT
      LAYER M4 ;
        RECT 457.728 479.136 457.920 479.160 ;
    END
  END tap[437]
  PIN tap[438]
    DIRECTION INPUT ;
    USE SIGNAL ;
    PORT
      LAYER M4 ;
        RECT 457.728 479.232 457.920 479.256 ;
    END
  END tap[438]
  PIN tap[439]
    DIRECTION INPUT ;
    USE SIGNAL ;
    PORT
      LAYER M4 ;
        RECT 457.728 479.328 457.920 479.352 ;
    END
  END tap[439]
  PIN tap[440]
    DIRECTION INPUT ;
    USE SIGNAL ;
    PORT
      LAYER M4 ;
        RECT 457.728 479.424 457.920 479.448 ;
    END
  END tap[440]
  PIN tap[441]
    DIRECTION INPUT ;
    USE SIGNAL ;
    PORT
      LAYER M4 ;
        RECT 457.728 479.520 457.920 479.544 ;
    END
  END tap[441]
  PIN tap[442]
    DIRECTION INPUT ;
    USE SIGNAL ;
    PORT
      LAYER M4 ;
        RECT 457.728 479.616 457.920 479.640 ;
    END
  END tap[442]
  PIN tap[443]
    DIRECTION INPUT ;
    USE SIGNAL ;
    PORT
      LAYER M4 ;
        RECT 457.728 479.712 457.920 479.736 ;
    END
  END tap[443]
  PIN tap[444]
    DIRECTION INPUT ;
    USE SIGNAL ;
    PORT
      LAYER M4 ;
        RECT 457.728 479.808 457.920 479.832 ;
    END
  END tap[444]
  PIN tap[445]
    DIRECTION INPUT ;
    USE SIGNAL ;
    PORT
      LAYER M4 ;
        RECT 457.728 479.904 457.920 479.928 ;
    END
  END tap[445]
  PIN tap[446]
    DIRECTION INPUT ;
    USE SIGNAL ;
    PORT
      LAYER M4 ;
        RECT 457.728 480.000 457.920 480.024 ;
    END
  END tap[446]
  PIN tap[447]
    DIRECTION INPUT ;
    USE SIGNAL ;
    PORT
      LAYER M4 ;
        RECT 457.728 480.096 457.920 480.120 ;
    END
  END tap[447]
  PIN tap[448]
    DIRECTION INPUT ;
    USE SIGNAL ;
    PORT
      LAYER M4 ;
        RECT 457.728 480.192 457.920 480.216 ;
    END
  END tap[448]
  PIN tap[449]
    DIRECTION INPUT ;
    USE SIGNAL ;
    PORT
      LAYER M4 ;
        RECT 457.728 480.288 457.920 480.312 ;
    END
  END tap[449]
  PIN tap[450]
    DIRECTION INPUT ;
    USE SIGNAL ;
    PORT
      LAYER M4 ;
        RECT 457.728 480.384 457.920 480.408 ;
    END
  END tap[450]
  PIN tap[451]
    DIRECTION INPUT ;
    USE SIGNAL ;
    PORT
      LAYER M4 ;
        RECT 457.728 480.480 457.920 480.504 ;
    END
  END tap[451]
  PIN tap[452]
    DIRECTION INPUT ;
    USE SIGNAL ;
    PORT
      LAYER M4 ;
        RECT 457.728 480.576 457.920 480.600 ;
    END
  END tap[452]
  PIN tap[453]
    DIRECTION INPUT ;
    USE SIGNAL ;
    PORT
      LAYER M4 ;
        RECT 457.728 480.672 457.920 480.696 ;
    END
  END tap[453]
  PIN tap[454]
    DIRECTION INPUT ;
    USE SIGNAL ;
    PORT
      LAYER M4 ;
        RECT 457.728 480.768 457.920 480.792 ;
    END
  END tap[454]
  PIN tap[455]
    DIRECTION INPUT ;
    USE SIGNAL ;
    PORT
      LAYER M4 ;
        RECT 457.728 480.864 457.920 480.888 ;
    END
  END tap[455]
  PIN tap[456]
    DIRECTION INPUT ;
    USE SIGNAL ;
    PORT
      LAYER M4 ;
        RECT 457.728 480.960 457.920 480.984 ;
    END
  END tap[456]
  PIN tap[457]
    DIRECTION INPUT ;
    USE SIGNAL ;
    PORT
      LAYER M4 ;
        RECT 457.728 481.056 457.920 481.080 ;
    END
  END tap[457]
  PIN tap[458]
    DIRECTION INPUT ;
    USE SIGNAL ;
    PORT
      LAYER M4 ;
        RECT 457.728 481.152 457.920 481.176 ;
    END
  END tap[458]
  PIN tap[459]
    DIRECTION INPUT ;
    USE SIGNAL ;
    PORT
      LAYER M4 ;
        RECT 457.728 481.248 457.920 481.272 ;
    END
  END tap[459]
  PIN tap[460]
    DIRECTION INPUT ;
    USE SIGNAL ;
    PORT
      LAYER M4 ;
        RECT 457.728 481.344 457.920 481.368 ;
    END
  END tap[460]
  PIN tap[461]
    DIRECTION INPUT ;
    USE SIGNAL ;
    PORT
      LAYER M4 ;
        RECT 457.728 481.440 457.920 481.464 ;
    END
  END tap[461]
  PIN tap[462]
    DIRECTION INPUT ;
    USE SIGNAL ;
    PORT
      LAYER M4 ;
        RECT 457.728 481.536 457.920 481.560 ;
    END
  END tap[462]
  PIN tap[463]
    DIRECTION INPUT ;
    USE SIGNAL ;
    PORT
      LAYER M4 ;
        RECT 457.728 481.632 457.920 481.656 ;
    END
  END tap[463]
  PIN tap[464]
    DIRECTION INPUT ;
    USE SIGNAL ;
    PORT
      LAYER M4 ;
        RECT 457.728 481.728 457.920 481.752 ;
    END
  END tap[464]
  PIN tap[465]
    DIRECTION INPUT ;
    USE SIGNAL ;
    PORT
      LAYER M4 ;
        RECT 457.728 481.824 457.920 481.848 ;
    END
  END tap[465]
  PIN tap[466]
    DIRECTION INPUT ;
    USE SIGNAL ;
    PORT
      LAYER M4 ;
        RECT 457.728 481.920 457.920 481.944 ;
    END
  END tap[466]
  PIN tap[467]
    DIRECTION INPUT ;
    USE SIGNAL ;
    PORT
      LAYER M4 ;
        RECT 457.728 482.016 457.920 482.040 ;
    END
  END tap[467]
  PIN tap[468]
    DIRECTION INPUT ;
    USE SIGNAL ;
    PORT
      LAYER M4 ;
        RECT 457.728 482.112 457.920 482.136 ;
    END
  END tap[468]
  PIN tap[469]
    DIRECTION INPUT ;
    USE SIGNAL ;
    PORT
      LAYER M4 ;
        RECT 457.728 482.208 457.920 482.232 ;
    END
  END tap[469]
  PIN tap[470]
    DIRECTION INPUT ;
    USE SIGNAL ;
    PORT
      LAYER M4 ;
        RECT 457.728 482.304 457.920 482.328 ;
    END
  END tap[470]
  PIN tap[471]
    DIRECTION INPUT ;
    USE SIGNAL ;
    PORT
      LAYER M4 ;
        RECT 457.728 482.400 457.920 482.424 ;
    END
  END tap[471]
  PIN tap[472]
    DIRECTION INPUT ;
    USE SIGNAL ;
    PORT
      LAYER M4 ;
        RECT 457.728 482.496 457.920 482.520 ;
    END
  END tap[472]
  PIN tap[473]
    DIRECTION INPUT ;
    USE SIGNAL ;
    PORT
      LAYER M4 ;
        RECT 457.728 482.592 457.920 482.616 ;
    END
  END tap[473]
  PIN tap[474]
    DIRECTION INPUT ;
    USE SIGNAL ;
    PORT
      LAYER M4 ;
        RECT 457.728 482.688 457.920 482.712 ;
    END
  END tap[474]
  PIN tap[475]
    DIRECTION INPUT ;
    USE SIGNAL ;
    PORT
      LAYER M4 ;
        RECT 457.728 482.784 457.920 482.808 ;
    END
  END tap[475]
  PIN tap[476]
    DIRECTION INPUT ;
    USE SIGNAL ;
    PORT
      LAYER M4 ;
        RECT 457.728 482.880 457.920 482.904 ;
    END
  END tap[476]
  PIN tap[477]
    DIRECTION INPUT ;
    USE SIGNAL ;
    PORT
      LAYER M4 ;
        RECT 457.728 482.976 457.920 483.000 ;
    END
  END tap[477]
  PIN tap[478]
    DIRECTION INPUT ;
    USE SIGNAL ;
    PORT
      LAYER M4 ;
        RECT 457.728 483.072 457.920 483.096 ;
    END
  END tap[478]
  PIN tap[479]
    DIRECTION INPUT ;
    USE SIGNAL ;
    PORT
      LAYER M4 ;
        RECT 457.728 483.168 457.920 483.192 ;
    END
  END tap[479]
  PIN tap[480]
    DIRECTION INPUT ;
    USE SIGNAL ;
    PORT
      LAYER M4 ;
        RECT 457.728 483.264 457.920 483.288 ;
    END
  END tap[480]
  PIN tap[481]
    DIRECTION INPUT ;
    USE SIGNAL ;
    PORT
      LAYER M4 ;
        RECT 457.728 483.360 457.920 483.384 ;
    END
  END tap[481]
  PIN tap[482]
    DIRECTION INPUT ;
    USE SIGNAL ;
    PORT
      LAYER M4 ;
        RECT 457.728 483.456 457.920 483.480 ;
    END
  END tap[482]
  PIN tap[483]
    DIRECTION INPUT ;
    USE SIGNAL ;
    PORT
      LAYER M4 ;
        RECT 457.728 483.552 457.920 483.576 ;
    END
  END tap[483]
  PIN tap[484]
    DIRECTION INPUT ;
    USE SIGNAL ;
    PORT
      LAYER M4 ;
        RECT 457.728 483.648 457.920 483.672 ;
    END
  END tap[484]
  PIN tap[485]
    DIRECTION INPUT ;
    USE SIGNAL ;
    PORT
      LAYER M4 ;
        RECT 457.728 483.744 457.920 483.768 ;
    END
  END tap[485]
  PIN tap[486]
    DIRECTION INPUT ;
    USE SIGNAL ;
    PORT
      LAYER M4 ;
        RECT 457.728 483.840 457.920 483.864 ;
    END
  END tap[486]
  PIN tap[487]
    DIRECTION INPUT ;
    USE SIGNAL ;
    PORT
      LAYER M4 ;
        RECT 457.728 483.936 457.920 483.960 ;
    END
  END tap[487]
  PIN tap[488]
    DIRECTION INPUT ;
    USE SIGNAL ;
    PORT
      LAYER M4 ;
        RECT 457.728 484.032 457.920 484.056 ;
    END
  END tap[488]
  PIN tap[489]
    DIRECTION INPUT ;
    USE SIGNAL ;
    PORT
      LAYER M4 ;
        RECT 457.728 484.128 457.920 484.152 ;
    END
  END tap[489]
  PIN tap[490]
    DIRECTION INPUT ;
    USE SIGNAL ;
    PORT
      LAYER M4 ;
        RECT 457.728 484.224 457.920 484.248 ;
    END
  END tap[490]
  PIN tap[491]
    DIRECTION INPUT ;
    USE SIGNAL ;
    PORT
      LAYER M4 ;
        RECT 457.728 484.320 457.920 484.344 ;
    END
  END tap[491]
  PIN tap[492]
    DIRECTION INPUT ;
    USE SIGNAL ;
    PORT
      LAYER M4 ;
        RECT 457.728 484.416 457.920 484.440 ;
    END
  END tap[492]
  PIN tap[493]
    DIRECTION INPUT ;
    USE SIGNAL ;
    PORT
      LAYER M4 ;
        RECT 457.728 484.512 457.920 484.536 ;
    END
  END tap[493]
  PIN tap[494]
    DIRECTION INPUT ;
    USE SIGNAL ;
    PORT
      LAYER M4 ;
        RECT 457.728 484.608 457.920 484.632 ;
    END
  END tap[494]
  PIN tap[495]
    DIRECTION INPUT ;
    USE SIGNAL ;
    PORT
      LAYER M4 ;
        RECT 457.728 484.704 457.920 484.728 ;
    END
  END tap[495]
  PIN tap[496]
    DIRECTION INPUT ;
    USE SIGNAL ;
    PORT
      LAYER M4 ;
        RECT 457.728 484.800 457.920 484.824 ;
    END
  END tap[496]
  PIN tap[497]
    DIRECTION INPUT ;
    USE SIGNAL ;
    PORT
      LAYER M4 ;
        RECT 457.728 484.896 457.920 484.920 ;
    END
  END tap[497]
  PIN tap[498]
    DIRECTION INPUT ;
    USE SIGNAL ;
    PORT
      LAYER M4 ;
        RECT 457.728 484.992 457.920 485.016 ;
    END
  END tap[498]
  PIN tap[499]
    DIRECTION INPUT ;
    USE SIGNAL ;
    PORT
      LAYER M4 ;
        RECT 457.728 485.088 457.920 485.112 ;
    END
  END tap[499]
  PIN tap[500]
    DIRECTION INPUT ;
    USE SIGNAL ;
    PORT
      LAYER M4 ;
        RECT 457.728 485.184 457.920 485.208 ;
    END
  END tap[500]
  PIN tap[501]
    DIRECTION INPUT ;
    USE SIGNAL ;
    PORT
      LAYER M4 ;
        RECT 457.728 485.280 457.920 485.304 ;
    END
  END tap[501]
  PIN tap[502]
    DIRECTION INPUT ;
    USE SIGNAL ;
    PORT
      LAYER M4 ;
        RECT 457.728 485.376 457.920 485.400 ;
    END
  END tap[502]
  PIN tap[503]
    DIRECTION INPUT ;
    USE SIGNAL ;
    PORT
      LAYER M4 ;
        RECT 457.728 485.472 457.920 485.496 ;
    END
  END tap[503]
  PIN tap[504]
    DIRECTION INPUT ;
    USE SIGNAL ;
    PORT
      LAYER M4 ;
        RECT 457.728 485.568 457.920 485.592 ;
    END
  END tap[504]
  PIN tap[505]
    DIRECTION INPUT ;
    USE SIGNAL ;
    PORT
      LAYER M4 ;
        RECT 457.728 485.664 457.920 485.688 ;
    END
  END tap[505]
  PIN tap[506]
    DIRECTION INPUT ;
    USE SIGNAL ;
    PORT
      LAYER M4 ;
        RECT 457.728 485.760 457.920 485.784 ;
    END
  END tap[506]
  PIN tap[507]
    DIRECTION INPUT ;
    USE SIGNAL ;
    PORT
      LAYER M4 ;
        RECT 457.728 485.856 457.920 485.880 ;
    END
  END tap[507]
  PIN ck_lsl0
    DIRECTION INPUT ;
    USE CLOCK ;
    PORT
      LAYER M4 ;
        RECT 0.000 430.176 0.192 430.200 ;
    END
  END ck_lsl0
  PIN ck_lsl1
    DIRECTION INPUT ;
    USE CLOCK ;
    PORT
      LAYER M4 ;
        RECT 0.000 259.488 0.192 259.512 ;
    END
  END ck_lsl1
  PIN ck_lsl2
    DIRECTION INPUT ;
    USE CLOCK ;
    PORT
      LAYER M4 ;
        RECT 0.000 88.992 0.192 89.016 ;
    END
  END ck_lsl2
  PIN ck_lsl3
    DIRECTION INPUT ;
    USE CLOCK ;
    PORT
      LAYER M4 ;
        RECT 457.728 430.176 457.920 430.200 ;
    END
  END ck_lsl3
  PIN ck_lsl4
    DIRECTION INPUT ;
    USE CLOCK ;
    PORT
      LAYER M4 ;
        RECT 457.728 259.536 457.920 259.560 ;
    END
  END ck_lsl4
  PIN ck_lsl5
    DIRECTION INPUT ;
    USE CLOCK ;
    PORT
      LAYER M4 ;
        RECT 457.728 88.896 457.920 88.920 ;
    END
  END ck_lsl5
  PIN ck_lsl6
    DIRECTION INPUT ;
    USE CLOCK ;
    PORT
      LAYER M4 ;
        RECT 457.728 259.632 457.920 259.656 ;
    END
  END ck_lsl6
  PIN ck_lsl7
    DIRECTION INPUT ;
    USE CLOCK ;
    PORT
      LAYER M4 ;
        RECT 457.728 88.992 457.920 89.016 ;
    END
  END ck_lsl7
  PIN ck_node
    DIRECTION INPUT ;
    USE CLOCK ;
    PORT
      LAYER M4 ;
        RECT 0.000 262.128 0.192 262.152 ;
    END
  END ck_node
  PIN ck_fa0
    DIRECTION INPUT ;
    USE CLOCK ;
    PORT
      LAYER M4 ;
        RECT 0.000 111.264 0.192 111.288 ;
    END
  END ck_fa0
  PIN ck_fa1
    DIRECTION INPUT ;
    USE CLOCK ;
    PORT
      LAYER M4 ;
        RECT 0.000 211.872 0.192 211.896 ;
    END
  END ck_fa1
  PIN ck_fa2
    DIRECTION INPUT ;
    USE CLOCK ;
    PORT
      LAYER M4 ;
        RECT 0.000 312.384 0.192 312.408 ;
    END
  END ck_fa2
  PIN ck_fa3
    DIRECTION INPUT ;
    USE CLOCK ;
    PORT
      LAYER M4 ;
        RECT 0.000 412.896 0.192 412.920 ;
    END
  END ck_fa3
  PIN ck_fa4
    DIRECTION INPUT ;
    USE CLOCK ;
    PORT
      LAYER M4 ;
        RECT 457.728 487.872 457.920 487.896 ;
    END
  END ck_fa4
  PIN ck
    DIRECTION INPUT ;
    USE CLOCK ;
    PORT
      LAYER M4 ;
        RECT 457.728 424.992 457.920 425.016 ;
    END
  END ck
  PIN ck_rp0
    DIRECTION INPUT ;
    USE CLOCK ;
    PORT
      LAYER M4 ;
        RECT 0.000 533.232 0.192 533.256 ;
    END
  END ck_rp0
  PIN ck_rp5
    DIRECTION INPUT ;
    USE CLOCK ;
    PORT
      LAYER M4 ;
        RECT 457.728 533.232 457.920 533.256 ;
    END
  END ck_rp5
  PIN ck_rp1
    DIRECTION INPUT ;
    USE CLOCK ;
    PORT
      LAYER M4 ;
        RECT 0.000 663.696 0.192 663.720 ;
    END
  END ck_rp1
  PIN ck_rp6
    DIRECTION INPUT ;
    USE CLOCK ;
    PORT
      LAYER M4 ;
        RECT 457.728 663.696 457.920 663.720 ;
    END
  END ck_rp6
  PIN ck_rp2
    DIRECTION INPUT ;
    USE CLOCK ;
    PORT
      LAYER M4 ;
        RECT 0.000 794.160 0.192 794.184 ;
    END
  END ck_rp2
  PIN ck_rp7
    DIRECTION INPUT ;
    USE CLOCK ;
    PORT
      LAYER M4 ;
        RECT 457.728 794.160 457.920 794.184 ;
    END
  END ck_rp7
  PIN ck_rp3
    DIRECTION INPUT ;
    USE CLOCK ;
    PORT
      LAYER M4 ;
        RECT 0.000 924.624 0.192 924.648 ;
    END
  END ck_rp3
  PIN ck_rp8
    DIRECTION INPUT ;
    USE CLOCK ;
    PORT
      LAYER M4 ;
        RECT 457.728 924.624 457.920 924.648 ;
    END
  END ck_rp8
  PIN ck_rp4
    DIRECTION INPUT ;
    USE CLOCK ;
    PORT
      LAYER M4 ;
        RECT 0.000 1055.088 0.192 1055.112 ;
    END
  END ck_rp4
  PIN ck_rp9
    DIRECTION INPUT ;
    USE CLOCK ;
    PORT
      LAYER M4 ;
        RECT 457.728 1055.088 457.920 1055.112 ;
    END
  END ck_rp9
  PIN ck_tx0
    DIRECTION INPUT ;
    USE CLOCK ;
    PORT
      LAYER M4 ;
        RECT 0.000 420.960 0.192 420.984 ;
    END
  END ck_tx0
  PIN ck_tx1
    DIRECTION INPUT ;
    USE CLOCK ;
    PORT
      LAYER M4 ;
        RECT 0.000 250.080 0.192 250.104 ;
    END
  END ck_tx1
  PIN ck_tx2
    DIRECTION INPUT ;
    USE CLOCK ;
    PORT
      LAYER M4 ;
        RECT 0.000 95.904 0.192 95.928 ;
    END
  END ck_tx2
  PIN ck_tx3
    DIRECTION INPUT ;
    USE CLOCK ;
    PORT
      LAYER M4 ;
        RECT 457.728 399.984 457.920 400.008 ;
    END
  END ck_tx3
  PIN ck_tx6
    DIRECTION INPUT ;
    USE CLOCK ;
    PORT
      LAYER M4 ;
        RECT 457.728 249.984 457.920 250.008 ;
    END
  END ck_tx6
  PIN ck_tx7
    DIRECTION INPUT ;
    USE CLOCK ;
    PORT
      LAYER M4 ;
        RECT 457.728 99.984 457.920 100.008 ;
    END
  END ck_tx7
  PIN ck_rsw
    DIRECTION INPUT ;
    USE CLOCK ;
    PORT
      LAYER M4 ;
        RECT 0.000 679.968 0.192 679.992 ;
    END
  END ck_rsw
  PIN ck_rnw
    DIRECTION INPUT ;
    USE CLOCK ;
    PORT
      LAYER M4 ;
        RECT 0.000 870.000 0.192 870.024 ;
    END
  END ck_rnw
  PIN ck_dw
    DIRECTION INPUT ;
    USE CLOCK ;
    PORT
      LAYER M4 ;
        RECT 0.000 547.968 0.192 547.992 ;
    END
  END ck_dw
  PIN ck_de
    DIRECTION INPUT ;
    USE CLOCK ;
    PORT
      LAYER M4 ;
        RECT 457.728 547.968 457.920 547.992 ;
    END
  END ck_de
  PIN ck_rs
    DIRECTION INPUT ;
    USE CLOCK ;
    PORT
      LAYER M4 ;
        RECT 457.728 679.968 457.920 679.992 ;
    END
  END ck_rs
  PIN ck_rn
    DIRECTION INPUT ;
    USE CLOCK ;
    PORT
      LAYER M4 ;
        RECT 457.728 870.000 457.920 870.024 ;
    END
  END ck_rn
  PIN ck_tx5
    DIRECTION INPUT ;
    USE CLOCK ;
    PORT
      LAYER M5 ;
        RECT 314.400 0.000 314.424 0.192 ;
    END
  END ck_tx5
  PIN ck_tx4
    DIRECTION INPUT ;
    USE CLOCK ;
    PORT
      LAYER M5 ;
        RECT 315.360 0.000 315.384 0.192 ;
    END
  END ck_tx4
  PIN VDD
    DIRECTION INOUT ;
    USE POWER ;
    PORT
      LAYER M7 ;
        RECT 1.000 0.000 1.288 1166.400 ;
        RECT 11.800 0.000 12.088 1166.400 ;
        RECT 22.600 0.000 22.888 1166.400 ;
        RECT 33.400 0.000 33.688 1166.400 ;
        RECT 44.200 0.000 44.488 1166.400 ;
        RECT 55.000 0.000 55.288 1166.400 ;
        RECT 65.800 0.000 66.088 1166.400 ;
        RECT 76.600 0.000 76.888 1166.400 ;
        RECT 87.400 0.000 87.688 1166.400 ;
        RECT 98.200 0.000 98.488 1166.400 ;
        RECT 109.000 0.000 109.288 1166.400 ;
        RECT 119.800 0.000 120.088 1166.400 ;
        RECT 130.600 0.000 130.888 1166.400 ;
        RECT 141.400 0.000 141.688 1166.400 ;
        RECT 152.200 0.000 152.488 1166.400 ;
        RECT 163.000 0.000 163.288 1166.400 ;
        RECT 173.800 0.000 174.088 1166.400 ;
        RECT 184.600 0.000 184.888 1166.400 ;
        RECT 195.400 0.000 195.688 1166.400 ;
        RECT 206.200 0.000 206.488 1166.400 ;
        RECT 217.000 0.000 217.288 1166.400 ;
        RECT 227.800 0.000 228.088 1166.400 ;
        RECT 238.600 0.000 238.888 1166.400 ;
        RECT 249.400 0.000 249.688 1166.400 ;
        RECT 260.200 0.000 260.488 1166.400 ;
        RECT 271.000 0.000 271.288 1166.400 ;
        RECT 281.800 0.000 282.088 1166.400 ;
        RECT 292.600 0.000 292.888 1166.400 ;
        RECT 303.400 0.000 303.688 1166.400 ;
        RECT 314.200 0.000 314.488 1166.400 ;
        RECT 325.000 0.000 325.288 1166.400 ;
        RECT 335.800 0.000 336.088 1166.400 ;
        RECT 346.600 0.000 346.888 1166.400 ;
        RECT 357.400 0.000 357.688 1166.400 ;
        RECT 368.200 0.000 368.488 1166.400 ;
        RECT 379.000 0.000 379.288 1166.400 ;
        RECT 389.800 0.000 390.088 1166.400 ;
        RECT 400.600 0.000 400.888 1166.400 ;
        RECT 411.400 0.000 411.688 1166.400 ;
        RECT 422.200 0.000 422.488 1166.400 ;
        RECT 433.000 0.000 433.288 1166.400 ;
        RECT 443.800 0.000 444.088 1166.400 ;
        RECT 454.600 0.000 454.888 1166.400 ;
    END
  END VDD
  PIN VSS
    DIRECTION INOUT ;
    USE GROUND ;
    PORT
      LAYER M7 ;
        RECT 6.400 0.000 6.688 1166.400 ;
        RECT 17.200 0.000 17.488 1166.400 ;
        RECT 28.000 0.000 28.288 1166.400 ;
        RECT 38.800 0.000 39.088 1166.400 ;
        RECT 49.600 0.000 49.888 1166.400 ;
        RECT 60.400 0.000 60.688 1166.400 ;
        RECT 71.200 0.000 71.488 1166.400 ;
        RECT 82.000 0.000 82.288 1166.400 ;
        RECT 92.800 0.000 93.088 1166.400 ;
        RECT 103.600 0.000 103.888 1166.400 ;
        RECT 114.400 0.000 114.688 1166.400 ;
        RECT 125.200 0.000 125.488 1166.400 ;
        RECT 136.000 0.000 136.288 1166.400 ;
        RECT 146.800 0.000 147.088 1166.400 ;
        RECT 157.600 0.000 157.888 1166.400 ;
        RECT 168.400 0.000 168.688 1166.400 ;
        RECT 179.200 0.000 179.488 1166.400 ;
        RECT 190.000 0.000 190.288 1166.400 ;
        RECT 200.800 0.000 201.088 1166.400 ;
        RECT 211.600 0.000 211.888 1166.400 ;
        RECT 222.400 0.000 222.688 1166.400 ;
        RECT 233.200 0.000 233.488 1166.400 ;
        RECT 244.000 0.000 244.288 1166.400 ;
        RECT 254.800 0.000 255.088 1166.400 ;
        RECT 265.600 0.000 265.888 1166.400 ;
        RECT 276.400 0.000 276.688 1166.400 ;
        RECT 287.200 0.000 287.488 1166.400 ;
        RECT 298.000 0.000 298.288 1166.400 ;
        RECT 308.800 0.000 309.088 1166.400 ;
        RECT 319.600 0.000 319.888 1166.400 ;
        RECT 330.400 0.000 330.688 1166.400 ;
        RECT 341.200 0.000 341.488 1166.400 ;
        RECT 352.000 0.000 352.288 1166.400 ;
        RECT 362.800 0.000 363.088 1166.400 ;
        RECT 373.600 0.000 373.888 1166.400 ;
        RECT 384.400 0.000 384.688 1166.400 ;
        RECT 395.200 0.000 395.488 1166.400 ;
        RECT 406.000 0.000 406.288 1166.400 ;
        RECT 416.800 0.000 417.088 1166.400 ;
        RECT 427.600 0.000 427.888 1166.400 ;
        RECT 438.400 0.000 438.688 1166.400 ;
        RECT 449.200 0.000 449.488 1166.400 ;
    END
  END VSS
  OBS
    LAYER M1 ;
      RECT 0.500 0.500 457.420 1165.900 ;
    LAYER M2 ;
      RECT 0.500 0.500 457.420 1165.900 ;
    LAYER M3 ;
      RECT 0.500 0.500 457.420 1165.900 ;
    LAYER M4 ;
      RECT 0.500 0.500 457.420 1165.900 ;
    LAYER M5 ;
      RECT 0.500 0.500 457.420 1165.900 ;
    LAYER M6 ;
      RECT 0.500 0.500 457.420 1165.900 ;
    LAYER M7 ;
      RECT 1.488 0.500 6.200 1165.900 ;
      RECT 6.888 0.500 11.600 1165.900 ;
      RECT 12.288 0.500 17.000 1165.900 ;
      RECT 17.688 0.500 22.400 1165.900 ;
      RECT 23.088 0.500 27.800 1165.900 ;
      RECT 28.488 0.500 33.200 1165.900 ;
      RECT 33.888 0.500 38.600 1165.900 ;
      RECT 39.288 0.500 44.000 1165.900 ;
      RECT 44.688 0.500 49.400 1165.900 ;
      RECT 50.088 0.500 54.800 1165.900 ;
      RECT 55.488 0.500 60.200 1165.900 ;
      RECT 60.888 0.500 65.600 1165.900 ;
      RECT 66.288 0.500 71.000 1165.900 ;
      RECT 71.688 0.500 76.400 1165.900 ;
      RECT 77.088 0.500 81.800 1165.900 ;
      RECT 82.488 0.500 87.200 1165.900 ;
      RECT 87.888 0.500 92.600 1165.900 ;
      RECT 93.288 0.500 98.000 1165.900 ;
      RECT 98.688 0.500 103.400 1165.900 ;
      RECT 104.088 0.500 108.800 1165.900 ;
      RECT 109.488 0.500 114.200 1165.900 ;
      RECT 114.888 0.500 119.600 1165.900 ;
      RECT 120.288 0.500 125.000 1165.900 ;
      RECT 125.688 0.500 130.400 1165.900 ;
      RECT 131.088 0.500 135.800 1165.900 ;
      RECT 136.488 0.500 141.200 1165.900 ;
      RECT 141.888 0.500 146.600 1165.900 ;
      RECT 147.288 0.500 152.000 1165.900 ;
      RECT 152.688 0.500 157.400 1165.900 ;
      RECT 158.088 0.500 162.800 1165.900 ;
      RECT 163.488 0.500 168.200 1165.900 ;
      RECT 168.888 0.500 173.600 1165.900 ;
      RECT 174.288 0.500 179.000 1165.900 ;
      RECT 179.688 0.500 184.400 1165.900 ;
      RECT 185.088 0.500 189.800 1165.900 ;
      RECT 190.488 0.500 195.200 1165.900 ;
      RECT 195.888 0.500 200.600 1165.900 ;
      RECT 201.288 0.500 206.000 1165.900 ;
      RECT 206.688 0.500 211.400 1165.900 ;
      RECT 212.088 0.500 216.800 1165.900 ;
      RECT 217.488 0.500 222.200 1165.900 ;
      RECT 222.888 0.500 227.600 1165.900 ;
      RECT 228.288 0.500 233.000 1165.900 ;
      RECT 233.688 0.500 238.400 1165.900 ;
      RECT 239.088 0.500 243.800 1165.900 ;
      RECT 244.488 0.500 249.200 1165.900 ;
      RECT 249.888 0.500 254.600 1165.900 ;
      RECT 255.288 0.500 260.000 1165.900 ;
      RECT 260.688 0.500 265.400 1165.900 ;
      RECT 266.088 0.500 270.800 1165.900 ;
      RECT 271.488 0.500 276.200 1165.900 ;
      RECT 276.888 0.500 281.600 1165.900 ;
      RECT 282.288 0.500 287.000 1165.900 ;
      RECT 287.688 0.500 292.400 1165.900 ;
      RECT 293.088 0.500 297.800 1165.900 ;
      RECT 298.488 0.500 303.200 1165.900 ;
      RECT 303.888 0.500 308.600 1165.900 ;
      RECT 309.288 0.500 314.000 1165.900 ;
      RECT 314.688 0.500 319.400 1165.900 ;
      RECT 320.088 0.500 324.800 1165.900 ;
      RECT 325.488 0.500 330.200 1165.900 ;
      RECT 330.888 0.500 335.600 1165.900 ;
      RECT 336.288 0.500 341.000 1165.900 ;
      RECT 341.688 0.500 346.400 1165.900 ;
      RECT 347.088 0.500 351.800 1165.900 ;
      RECT 352.488 0.500 357.200 1165.900 ;
      RECT 357.888 0.500 362.600 1165.900 ;
      RECT 363.288 0.500 368.000 1165.900 ;
      RECT 368.688 0.500 373.400 1165.900 ;
      RECT 374.088 0.500 378.800 1165.900 ;
      RECT 379.488 0.500 384.200 1165.900 ;
      RECT 384.888 0.500 389.600 1165.900 ;
      RECT 390.288 0.500 395.000 1165.900 ;
      RECT 395.688 0.500 400.400 1165.900 ;
      RECT 401.088 0.500 405.800 1165.900 ;
      RECT 406.488 0.500 411.200 1165.900 ;
      RECT 411.888 0.500 416.600 1165.900 ;
      RECT 417.288 0.500 422.000 1165.900 ;
      RECT 422.688 0.500 427.400 1165.900 ;
      RECT 428.088 0.500 432.800 1165.900 ;
      RECT 433.488 0.500 438.200 1165.900 ;
      RECT 438.888 0.500 443.600 1165.900 ;
      RECT 444.288 0.500 449.000 1165.900 ;
      RECT 449.688 0.500 454.400 1165.900 ;
      RECT 455.088 0.500 457.420 1165.900 ;
  END
END qfd_tile_nk_rp2_romleaf_rr
END LIBRARY
